VERSION 5.8 ;
BUSBITCHARS "[]" ;
DIVIDERCHAR "/" ;
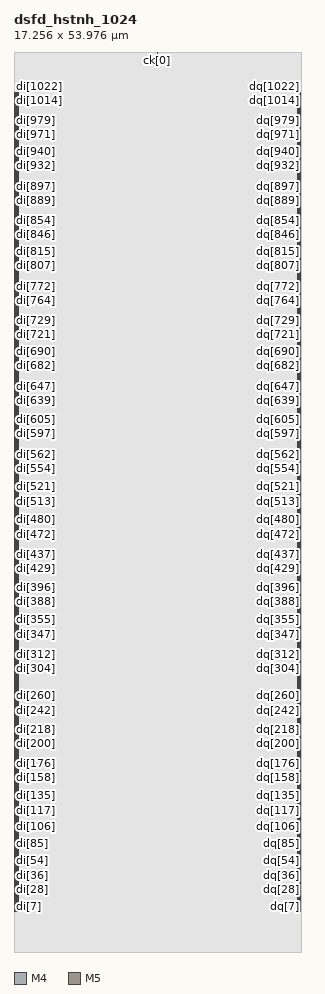
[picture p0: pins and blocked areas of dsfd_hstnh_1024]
MACRO dsfd_hstnh_1024
  CLASS BLOCK ;
  FOREIGN dsfd_hstnh_1024 0 0 ;
  SIZE 17.256 BY 53.976 ;
  SYMMETRY X Y ;
  PIN di[0]
    DIRECTION INOUT ;
    USE SIGNAL ;
    PORT
      LAYER M4 ;
        RECT 0.048 2.400 0.240 2.424 ;
    END
  END di[0]
  PIN di[1]
    DIRECTION INOUT ;
    USE SIGNAL ;
    PORT
      LAYER M4 ;
        RECT 0.048 2.448 0.240 2.472 ;
    END
  END di[1]
  PIN di[2]
    DIRECTION INOUT ;
    USE SIGNAL ;
    PORT
      LAYER M4 ;
        RECT 0.048 2.496 0.240 2.520 ;
    END
  END di[2]
  PIN di[3]
    DIRECTION INOUT ;
    USE SIGNAL ;
    PORT
      LAYER M4 ;
        RECT 0.048 2.544 0.240 2.568 ;
    END
  END di[3]
  PIN di[4]
    DIRECTION INOUT ;
    USE SIGNAL ;
    PORT
      LAYER M4 ;
        RECT 0.048 2.592 0.240 2.616 ;
    END
  END di[4]
  PIN di[5]
    DIRECTION INOUT ;
    USE SIGNAL ;
    PORT
      LAYER M4 ;
        RECT 0.048 2.640 0.240 2.664 ;
    END
  END di[5]
  PIN di[6]
    DIRECTION INOUT ;
    USE SIGNAL ;
    PORT
      LAYER M4 ;
        RECT 0.048 2.688 0.240 2.712 ;
    END
  END di[6]
  PIN di[7]
    DIRECTION INOUT ;
    USE SIGNAL ;
    PORT
      LAYER M4 ;
        RECT 0.048 2.736 0.240 2.760 ;
    END
  END di[7]
  PIN di[8]
    DIRECTION INOUT ;
    USE SIGNAL ;
    PORT
      LAYER M4 ;
        RECT 0.048 2.784 0.240 2.808 ;
    END
  END di[8]
  PIN di[9]
    DIRECTION INOUT ;
    USE SIGNAL ;
    PORT
      LAYER M4 ;
        RECT 0.048 2.832 0.240 2.856 ;
    END
  END di[9]
  PIN di[10]
    DIRECTION INOUT ;
    USE SIGNAL ;
    PORT
      LAYER M4 ;
        RECT 0.048 2.880 0.240 2.904 ;
    END
  END di[10]
  PIN di[11]
    DIRECTION INOUT ;
    USE SIGNAL ;
    PORT
      LAYER M4 ;
        RECT 0.048 2.928 0.240 2.952 ;
    END
  END di[11]
  PIN di[12]
    DIRECTION INOUT ;
    USE SIGNAL ;
    PORT
      LAYER M4 ;
        RECT 0.048 2.976 0.240 3.000 ;
    END
  END di[12]
  PIN di[13]
    DIRECTION INOUT ;
    USE SIGNAL ;
    PORT
      LAYER M4 ;
        RECT 0.048 3.024 0.240 3.048 ;
    END
  END di[13]
  PIN di[14]
    DIRECTION INOUT ;
    USE SIGNAL ;
    PORT
      LAYER M4 ;
        RECT 0.048 3.072 0.240 3.096 ;
    END
  END di[14]
  PIN di[15]
    DIRECTION INOUT ;
    USE SIGNAL ;
    PORT
      LAYER M4 ;
        RECT 0.048 3.120 0.240 3.144 ;
    END
  END di[15]
  PIN di[16]
    DIRECTION INOUT ;
    USE SIGNAL ;
    PORT
      LAYER M4 ;
        RECT 0.048 3.168 0.240 3.192 ;
    END
  END di[16]
  PIN di[17]
    DIRECTION INOUT ;
    USE SIGNAL ;
    PORT
      LAYER M4 ;
        RECT 0.048 3.216 0.240 3.240 ;
    END
  END di[17]
  PIN di[18]
    DIRECTION INOUT ;
    USE SIGNAL ;
    PORT
      LAYER M4 ;
        RECT 0.048 3.264 0.240 3.288 ;
    END
  END di[18]
  PIN di[19]
    DIRECTION INOUT ;
    USE SIGNAL ;
    PORT
      LAYER M4 ;
        RECT 0.048 3.312 0.240 3.336 ;
    END
  END di[19]
  PIN di[20]
    DIRECTION INOUT ;
    USE SIGNAL ;
    PORT
      LAYER M4 ;
        RECT 0.048 3.360 0.240 3.384 ;
    END
  END di[20]
  PIN di[21]
    DIRECTION INOUT ;
    USE SIGNAL ;
    PORT
      LAYER M4 ;
        RECT 0.048 3.408 0.240 3.432 ;
    END
  END di[21]
  PIN di[22]
    DIRECTION INOUT ;
    USE SIGNAL ;
    PORT
      LAYER M4 ;
        RECT 0.048 3.456 0.240 3.480 ;
    END
  END di[22]
  PIN di[23]
    DIRECTION INOUT ;
    USE SIGNAL ;
    PORT
      LAYER M4 ;
        RECT 0.048 3.504 0.240 3.528 ;
    END
  END di[23]
  PIN di[24]
    DIRECTION INOUT ;
    USE SIGNAL ;
    PORT
      LAYER M4 ;
        RECT 0.048 3.552 0.240 3.576 ;
    END
  END di[24]
  PIN di[25]
    DIRECTION INOUT ;
    USE SIGNAL ;
    PORT
      LAYER M4 ;
        RECT 0.048 3.600 0.240 3.624 ;
    END
  END di[25]
  PIN di[26]
    DIRECTION INOUT ;
    USE SIGNAL ;
    PORT
      LAYER M4 ;
        RECT 0.048 3.648 0.240 3.672 ;
    END
  END di[26]
  PIN di[27]
    DIRECTION INOUT ;
    USE SIGNAL ;
    PORT
      LAYER M4 ;
        RECT 0.048 3.696 0.240 3.720 ;
    END
  END di[27]
  PIN di[28]
    DIRECTION INOUT ;
    USE SIGNAL ;
    PORT
      LAYER M4 ;
        RECT 0.048 3.744 0.240 3.768 ;
    END
  END di[28]
  PIN di[29]
    DIRECTION INOUT ;
    USE SIGNAL ;
    PORT
      LAYER M4 ;
        RECT 0.048 3.792 0.240 3.816 ;
    END
  END di[29]
  PIN di[30]
    DIRECTION INOUT ;
    USE SIGNAL ;
    PORT
      LAYER M4 ;
        RECT 0.048 3.840 0.240 3.864 ;
    END
  END di[30]
  PIN di[31]
    DIRECTION INOUT ;
    USE SIGNAL ;
    PORT
      LAYER M4 ;
        RECT 0.048 3.888 0.240 3.912 ;
    END
  END di[31]
  PIN di[32]
    DIRECTION INOUT ;
    USE SIGNAL ;
    PORT
      LAYER M4 ;
        RECT 0.048 3.936 0.240 3.960 ;
    END
  END di[32]
  PIN di[33]
    DIRECTION INOUT ;
    USE SIGNAL ;
    PORT
      LAYER M4 ;
        RECT 0.048 3.984 0.240 4.008 ;
    END
  END di[33]
  PIN di[34]
    DIRECTION INOUT ;
    USE SIGNAL ;
    PORT
      LAYER M4 ;
        RECT 0.048 4.032 0.240 4.056 ;
    END
  END di[34]
  PIN di[35]
    DIRECTION INOUT ;
    USE SIGNAL ;
    PORT
      LAYER M4 ;
        RECT 0.048 4.080 0.240 4.104 ;
    END
  END di[35]
  PIN di[36]
    DIRECTION INOUT ;
    USE SIGNAL ;
    PORT
      LAYER M4 ;
        RECT 0.048 4.128 0.240 4.152 ;
    END
  END di[36]
  PIN di[37]
    DIRECTION INOUT ;
    USE SIGNAL ;
    PORT
      LAYER M4 ;
        RECT 0.048 4.176 0.240 4.200 ;
    END
  END di[37]
  PIN di[38]
    DIRECTION INOUT ;
    USE SIGNAL ;
    PORT
      LAYER M4 ;
        RECT 0.048 4.224 0.240 4.248 ;
    END
  END di[38]
  PIN di[39]
    DIRECTION INOUT ;
    USE SIGNAL ;
    PORT
      LAYER M4 ;
        RECT 0.048 4.272 0.240 4.296 ;
    END
  END di[39]
  PIN di[40]
    DIRECTION INOUT ;
    USE SIGNAL ;
    PORT
      LAYER M4 ;
        RECT 0.048 4.320 0.240 4.344 ;
    END
  END di[40]
  PIN di[41]
    DIRECTION INOUT ;
    USE SIGNAL ;
    PORT
      LAYER M4 ;
        RECT 0.048 4.368 0.240 4.392 ;
    END
  END di[41]
  PIN di[42]
    DIRECTION INOUT ;
    USE SIGNAL ;
    PORT
      LAYER M4 ;
        RECT 0.048 4.416 0.240 4.440 ;
    END
  END di[42]
  PIN di[43]
    DIRECTION INOUT ;
    USE SIGNAL ;
    PORT
      LAYER M4 ;
        RECT 0.048 4.464 0.240 4.488 ;
    END
  END di[43]
  PIN di[44]
    DIRECTION INOUT ;
    USE SIGNAL ;
    PORT
      LAYER M4 ;
        RECT 0.048 4.512 0.240 4.536 ;
    END
  END di[44]
  PIN di[45]
    DIRECTION INOUT ;
    USE SIGNAL ;
    PORT
      LAYER M4 ;
        RECT 0.048 4.560 0.240 4.584 ;
    END
  END di[45]
  PIN di[46]
    DIRECTION INOUT ;
    USE SIGNAL ;
    PORT
      LAYER M4 ;
        RECT 0.048 4.608 0.240 4.632 ;
    END
  END di[46]
  PIN di[47]
    DIRECTION INOUT ;
    USE SIGNAL ;
    PORT
      LAYER M4 ;
        RECT 0.048 4.656 0.240 4.680 ;
    END
  END di[47]
  PIN di[48]
    DIRECTION INOUT ;
    USE SIGNAL ;
    PORT
      LAYER M4 ;
        RECT 0.048 4.704 0.240 4.728 ;
    END
  END di[48]
  PIN di[49]
    DIRECTION INOUT ;
    USE SIGNAL ;
    PORT
      LAYER M4 ;
        RECT 0.048 4.752 0.240 4.776 ;
    END
  END di[49]
  PIN di[50]
    DIRECTION INOUT ;
    USE SIGNAL ;
    PORT
      LAYER M4 ;
        RECT 0.048 4.800 0.240 4.824 ;
    END
  END di[50]
  PIN di[51]
    DIRECTION INOUT ;
    USE SIGNAL ;
    PORT
      LAYER M4 ;
        RECT 0.048 4.848 0.240 4.872 ;
    END
  END di[51]
  PIN di[52]
    DIRECTION INOUT ;
    USE SIGNAL ;
    PORT
      LAYER M4 ;
        RECT 0.048 4.896 0.240 4.920 ;
    END
  END di[52]
  PIN di[53]
    DIRECTION INOUT ;
    USE SIGNAL ;
    PORT
      LAYER M4 ;
        RECT 0.048 4.944 0.240 4.968 ;
    END
  END di[53]
  PIN di[54]
    DIRECTION INOUT ;
    USE SIGNAL ;
    PORT
      LAYER M4 ;
        RECT 0.048 4.992 0.240 5.016 ;
    END
  END di[54]
  PIN di[55]
    DIRECTION INOUT ;
    USE SIGNAL ;
    PORT
      LAYER M4 ;
        RECT 0.048 5.040 0.240 5.064 ;
    END
  END di[55]
  PIN di[56]
    DIRECTION INOUT ;
    USE SIGNAL ;
    PORT
      LAYER M4 ;
        RECT 0.048 5.088 0.240 5.112 ;
    END
  END di[56]
  PIN di[57]
    DIRECTION INOUT ;
    USE SIGNAL ;
    PORT
      LAYER M4 ;
        RECT 0.048 5.136 0.240 5.160 ;
    END
  END di[57]
  PIN di[58]
    DIRECTION INOUT ;
    USE SIGNAL ;
    PORT
      LAYER M4 ;
        RECT 0.048 5.184 0.240 5.208 ;
    END
  END di[58]
  PIN di[59]
    DIRECTION INOUT ;
    USE SIGNAL ;
    PORT
      LAYER M4 ;
        RECT 0.048 5.232 0.240 5.256 ;
    END
  END di[59]
  PIN di[60]
    DIRECTION INOUT ;
    USE SIGNAL ;
    PORT
      LAYER M4 ;
        RECT 0.048 5.280 0.240 5.304 ;
    END
  END di[60]
  PIN di[61]
    DIRECTION INOUT ;
    USE SIGNAL ;
    PORT
      LAYER M4 ;
        RECT 0.048 5.328 0.240 5.352 ;
    END
  END di[61]
  PIN di[62]
    DIRECTION INOUT ;
    USE SIGNAL ;
    PORT
      LAYER M4 ;
        RECT 0.048 5.376 0.240 5.400 ;
    END
  END di[62]
  PIN di[63]
    DIRECTION INOUT ;
    USE SIGNAL ;
    PORT
      LAYER M4 ;
        RECT 0.048 5.424 0.240 5.448 ;
    END
  END di[63]
  PIN di[64]
    DIRECTION INOUT ;
    USE SIGNAL ;
    PORT
      LAYER M4 ;
        RECT 0.048 5.472 0.240 5.496 ;
    END
  END di[64]
  PIN di[65]
    DIRECTION INOUT ;
    USE SIGNAL ;
    PORT
      LAYER M4 ;
        RECT 0.048 5.520 0.240 5.544 ;
    END
  END di[65]
  PIN di[66]
    DIRECTION INOUT ;
    USE SIGNAL ;
    PORT
      LAYER M4 ;
        RECT 0.048 5.568 0.240 5.592 ;
    END
  END di[66]
  PIN di[67]
    DIRECTION INOUT ;
    USE SIGNAL ;
    PORT
      LAYER M4 ;
        RECT 0.048 5.616 0.240 5.640 ;
    END
  END di[67]
  PIN di[68]
    DIRECTION INOUT ;
    USE SIGNAL ;
    PORT
      LAYER M4 ;
        RECT 0.048 5.664 0.240 5.688 ;
    END
  END di[68]
  PIN di[69]
    DIRECTION INOUT ;
    USE SIGNAL ;
    PORT
      LAYER M4 ;
        RECT 0.048 5.712 0.240 5.736 ;
    END
  END di[69]
  PIN di[70]
    DIRECTION INOUT ;
    USE SIGNAL ;
    PORT
      LAYER M4 ;
        RECT 0.048 5.760 0.240 5.784 ;
    END
  END di[70]
  PIN di[71]
    DIRECTION INOUT ;
    USE SIGNAL ;
    PORT
      LAYER M4 ;
        RECT 0.048 5.808 0.240 5.832 ;
    END
  END di[71]
  PIN di[72]
    DIRECTION INOUT ;
    USE SIGNAL ;
    PORT
      LAYER M4 ;
        RECT 0.048 5.856 0.240 5.880 ;
    END
  END di[72]
  PIN di[73]
    DIRECTION INOUT ;
    USE SIGNAL ;
    PORT
      LAYER M4 ;
        RECT 0.048 5.904 0.240 5.928 ;
    END
  END di[73]
  PIN di[74]
    DIRECTION INOUT ;
    USE SIGNAL ;
    PORT
      LAYER M4 ;
        RECT 0.048 5.952 0.240 5.976 ;
    END
  END di[74]
  PIN di[75]
    DIRECTION INOUT ;
    USE SIGNAL ;
    PORT
      LAYER M4 ;
        RECT 0.048 6.000 0.240 6.024 ;
    END
  END di[75]
  PIN di[76]
    DIRECTION INOUT ;
    USE SIGNAL ;
    PORT
      LAYER M4 ;
        RECT 0.048 6.048 0.240 6.072 ;
    END
  END di[76]
  PIN di[77]
    DIRECTION INOUT ;
    USE SIGNAL ;
    PORT
      LAYER M4 ;
        RECT 0.048 6.096 0.240 6.120 ;
    END
  END di[77]
  PIN di[78]
    DIRECTION INOUT ;
    USE SIGNAL ;
    PORT
      LAYER M4 ;
        RECT 0.048 6.144 0.240 6.168 ;
    END
  END di[78]
  PIN di[79]
    DIRECTION INOUT ;
    USE SIGNAL ;
    PORT
      LAYER M4 ;
        RECT 0.048 6.192 0.240 6.216 ;
    END
  END di[79]
  PIN di[80]
    DIRECTION INOUT ;
    USE SIGNAL ;
    PORT
      LAYER M4 ;
        RECT 0.048 6.240 0.240 6.264 ;
    END
  END di[80]
  PIN di[81]
    DIRECTION INOUT ;
    USE SIGNAL ;
    PORT
      LAYER M4 ;
        RECT 0.048 6.288 0.240 6.312 ;
    END
  END di[81]
  PIN di[82]
    DIRECTION INOUT ;
    USE SIGNAL ;
    PORT
      LAYER M4 ;
        RECT 0.048 6.336 0.240 6.360 ;
    END
  END di[82]
  PIN di[83]
    DIRECTION INOUT ;
    USE SIGNAL ;
    PORT
      LAYER M4 ;
        RECT 0.048 6.384 0.240 6.408 ;
    END
  END di[83]
  PIN di[84]
    DIRECTION INOUT ;
    USE SIGNAL ;
    PORT
      LAYER M4 ;
        RECT 0.048 6.432 0.240 6.456 ;
    END
  END di[84]
  PIN di[85]
    DIRECTION INOUT ;
    USE SIGNAL ;
    PORT
      LAYER M4 ;
        RECT 0.048 6.480 0.240 6.504 ;
    END
  END di[85]
  PIN di[86]
    DIRECTION INOUT ;
    USE SIGNAL ;
    PORT
      LAYER M4 ;
        RECT 0.048 6.528 0.240 6.552 ;
    END
  END di[86]
  PIN di[87]
    DIRECTION INOUT ;
    USE SIGNAL ;
    PORT
      LAYER M4 ;
        RECT 0.048 6.576 0.240 6.600 ;
    END
  END di[87]
  PIN di[88]
    DIRECTION INOUT ;
    USE SIGNAL ;
    PORT
      LAYER M4 ;
        RECT 0.048 6.624 0.240 6.648 ;
    END
  END di[88]
  PIN di[89]
    DIRECTION INOUT ;
    USE SIGNAL ;
    PORT
      LAYER M4 ;
        RECT 0.048 6.672 0.240 6.696 ;
    END
  END di[89]
  PIN di[90]
    DIRECTION INOUT ;
    USE SIGNAL ;
    PORT
      LAYER M4 ;
        RECT 0.048 6.720 0.240 6.744 ;
    END
  END di[90]
  PIN di[91]
    DIRECTION INOUT ;
    USE SIGNAL ;
    PORT
      LAYER M4 ;
        RECT 0.048 6.768 0.240 6.792 ;
    END
  END di[91]
  PIN di[92]
    DIRECTION INOUT ;
    USE SIGNAL ;
    PORT
      LAYER M4 ;
        RECT 0.048 6.816 0.240 6.840 ;
    END
  END di[92]
  PIN di[93]
    DIRECTION INOUT ;
    USE SIGNAL ;
    PORT
      LAYER M4 ;
        RECT 0.048 6.864 0.240 6.888 ;
    END
  END di[93]
  PIN di[94]
    DIRECTION INOUT ;
    USE SIGNAL ;
    PORT
      LAYER M4 ;
        RECT 0.048 6.912 0.240 6.936 ;
    END
  END di[94]
  PIN di[95]
    DIRECTION INOUT ;
    USE SIGNAL ;
    PORT
      LAYER M4 ;
        RECT 0.048 6.960 0.240 6.984 ;
    END
  END di[95]
  PIN di[96]
    DIRECTION INOUT ;
    USE SIGNAL ;
    PORT
      LAYER M4 ;
        RECT 0.048 7.008 0.240 7.032 ;
    END
  END di[96]
  PIN di[97]
    DIRECTION INOUT ;
    USE SIGNAL ;
    PORT
      LAYER M4 ;
        RECT 0.048 7.056 0.240 7.080 ;
    END
  END di[97]
  PIN di[98]
    DIRECTION INOUT ;
    USE SIGNAL ;
    PORT
      LAYER M4 ;
        RECT 0.048 7.104 0.240 7.128 ;
    END
  END di[98]
  PIN di[99]
    DIRECTION INOUT ;
    USE SIGNAL ;
    PORT
      LAYER M4 ;
        RECT 0.048 7.152 0.240 7.176 ;
    END
  END di[99]
  PIN di[100]
    DIRECTION INOUT ;
    USE SIGNAL ;
    PORT
      LAYER M4 ;
        RECT 0.048 7.200 0.240 7.224 ;
    END
  END di[100]
  PIN di[101]
    DIRECTION INOUT ;
    USE SIGNAL ;
    PORT
      LAYER M4 ;
        RECT 0.048 7.248 0.240 7.272 ;
    END
  END di[101]
  PIN di[102]
    DIRECTION INOUT ;
    USE SIGNAL ;
    PORT
      LAYER M4 ;
        RECT 0.048 7.296 0.240 7.320 ;
    END
  END di[102]
  PIN di[103]
    DIRECTION INOUT ;
    USE SIGNAL ;
    PORT
      LAYER M4 ;
        RECT 0.048 7.344 0.240 7.368 ;
    END
  END di[103]
  PIN di[104]
    DIRECTION INOUT ;
    USE SIGNAL ;
    PORT
      LAYER M4 ;
        RECT 0.048 7.392 0.240 7.416 ;
    END
  END di[104]
  PIN di[105]
    DIRECTION INOUT ;
    USE SIGNAL ;
    PORT
      LAYER M4 ;
        RECT 0.048 7.440 0.240 7.464 ;
    END
  END di[105]
  PIN di[106]
    DIRECTION INOUT ;
    USE SIGNAL ;
    PORT
      LAYER M4 ;
        RECT 0.048 7.488 0.240 7.512 ;
    END
  END di[106]
  PIN di[107]
    DIRECTION INOUT ;
    USE SIGNAL ;
    PORT
      LAYER M4 ;
        RECT 0.048 7.536 0.240 7.560 ;
    END
  END di[107]
  PIN di[108]
    DIRECTION INOUT ;
    USE SIGNAL ;
    PORT
      LAYER M4 ;
        RECT 0.048 7.584 0.240 7.608 ;
    END
  END di[108]
  PIN di[109]
    DIRECTION INOUT ;
    USE SIGNAL ;
    PORT
      LAYER M4 ;
        RECT 0.048 7.632 0.240 7.656 ;
    END
  END di[109]
  PIN di[110]
    DIRECTION INOUT ;
    USE SIGNAL ;
    PORT
      LAYER M4 ;
        RECT 0.048 7.680 0.240 7.704 ;
    END
  END di[110]
  PIN di[111]
    DIRECTION INOUT ;
    USE SIGNAL ;
    PORT
      LAYER M4 ;
        RECT 0.048 7.728 0.240 7.752 ;
    END
  END di[111]
  PIN di[112]
    DIRECTION INOUT ;
    USE SIGNAL ;
    PORT
      LAYER M4 ;
        RECT 0.048 7.776 0.240 7.800 ;
    END
  END di[112]
  PIN di[113]
    DIRECTION INOUT ;
    USE SIGNAL ;
    PORT
      LAYER M4 ;
        RECT 0.048 7.824 0.240 7.848 ;
    END
  END di[113]
  PIN di[114]
    DIRECTION INOUT ;
    USE SIGNAL ;
    PORT
      LAYER M4 ;
        RECT 0.048 7.872 0.240 7.896 ;
    END
  END di[114]
  PIN di[115]
    DIRECTION INOUT ;
    USE SIGNAL ;
    PORT
      LAYER M4 ;
        RECT 0.048 7.920 0.240 7.944 ;
    END
  END di[115]
  PIN di[116]
    DIRECTION INOUT ;
    USE SIGNAL ;
    PORT
      LAYER M4 ;
        RECT 0.048 7.968 0.240 7.992 ;
    END
  END di[116]
  PIN di[117]
    DIRECTION INOUT ;
    USE SIGNAL ;
    PORT
      LAYER M4 ;
        RECT 0.048 8.016 0.240 8.040 ;
    END
  END di[117]
  PIN di[118]
    DIRECTION INOUT ;
    USE SIGNAL ;
    PORT
      LAYER M4 ;
        RECT 0.048 8.064 0.240 8.088 ;
    END
  END di[118]
  PIN di[119]
    DIRECTION INOUT ;
    USE SIGNAL ;
    PORT
      LAYER M4 ;
        RECT 0.048 8.112 0.240 8.136 ;
    END
  END di[119]
  PIN di[120]
    DIRECTION INOUT ;
    USE SIGNAL ;
    PORT
      LAYER M4 ;
        RECT 0.048 8.160 0.240 8.184 ;
    END
  END di[120]
  PIN di[121]
    DIRECTION INOUT ;
    USE SIGNAL ;
    PORT
      LAYER M4 ;
        RECT 0.048 8.208 0.240 8.232 ;
    END
  END di[121]
  PIN di[122]
    DIRECTION INOUT ;
    USE SIGNAL ;
    PORT
      LAYER M4 ;
        RECT 0.048 8.256 0.240 8.280 ;
    END
  END di[122]
  PIN di[123]
    DIRECTION INOUT ;
    USE SIGNAL ;
    PORT
      LAYER M4 ;
        RECT 0.048 8.304 0.240 8.328 ;
    END
  END di[123]
  PIN di[124]
    DIRECTION INOUT ;
    USE SIGNAL ;
    PORT
      LAYER M4 ;
        RECT 0.048 8.352 0.240 8.376 ;
    END
  END di[124]
  PIN di[125]
    DIRECTION INOUT ;
    USE SIGNAL ;
    PORT
      LAYER M4 ;
        RECT 0.048 8.400 0.240 8.424 ;
    END
  END di[125]
  PIN di[126]
    DIRECTION INOUT ;
    USE SIGNAL ;
    PORT
      LAYER M4 ;
        RECT 0.048 8.448 0.240 8.472 ;
    END
  END di[126]
  PIN di[127]
    DIRECTION INOUT ;
    USE SIGNAL ;
    PORT
      LAYER M4 ;
        RECT 0.048 8.496 0.240 8.520 ;
    END
  END di[127]
  PIN di[128]
    DIRECTION INOUT ;
    USE SIGNAL ;
    PORT
      LAYER M4 ;
        RECT 0.048 8.544 0.240 8.568 ;
    END
  END di[128]
  PIN di[129]
    DIRECTION INOUT ;
    USE SIGNAL ;
    PORT
      LAYER M4 ;
        RECT 0.048 8.592 0.240 8.616 ;
    END
  END di[129]
  PIN di[130]
    DIRECTION INOUT ;
    USE SIGNAL ;
    PORT
      LAYER M4 ;
        RECT 0.048 8.640 0.240 8.664 ;
    END
  END di[130]
  PIN di[131]
    DIRECTION INOUT ;
    USE SIGNAL ;
    PORT
      LAYER M4 ;
        RECT 0.048 8.688 0.240 8.712 ;
    END
  END di[131]
  PIN di[132]
    DIRECTION INOUT ;
    USE SIGNAL ;
    PORT
      LAYER M4 ;
        RECT 0.048 8.736 0.240 8.760 ;
    END
  END di[132]
  PIN di[133]
    DIRECTION INOUT ;
    USE SIGNAL ;
    PORT
      LAYER M4 ;
        RECT 0.048 8.784 0.240 8.808 ;
    END
  END di[133]
  PIN di[134]
    DIRECTION INOUT ;
    USE SIGNAL ;
    PORT
      LAYER M4 ;
        RECT 0.048 8.832 0.240 8.856 ;
    END
  END di[134]
  PIN di[135]
    DIRECTION INOUT ;
    USE SIGNAL ;
    PORT
      LAYER M4 ;
        RECT 0.048 8.880 0.240 8.904 ;
    END
  END di[135]
  PIN di[136]
    DIRECTION INOUT ;
    USE SIGNAL ;
    PORT
      LAYER M4 ;
        RECT 0.048 8.928 0.240 8.952 ;
    END
  END di[136]
  PIN di[137]
    DIRECTION INOUT ;
    USE SIGNAL ;
    PORT
      LAYER M4 ;
        RECT 0.048 8.976 0.240 9.000 ;
    END
  END di[137]
  PIN di[138]
    DIRECTION INOUT ;
    USE SIGNAL ;
    PORT
      LAYER M4 ;
        RECT 0.048 9.024 0.240 9.048 ;
    END
  END di[138]
  PIN di[139]
    DIRECTION INOUT ;
    USE SIGNAL ;
    PORT
      LAYER M4 ;
        RECT 0.048 9.072 0.240 9.096 ;
    END
  END di[139]
  PIN di[140]
    DIRECTION INOUT ;
    USE SIGNAL ;
    PORT
      LAYER M4 ;
        RECT 0.048 9.120 0.240 9.144 ;
    END
  END di[140]
  PIN di[141]
    DIRECTION INOUT ;
    USE SIGNAL ;
    PORT
      LAYER M4 ;
        RECT 0.048 9.168 0.240 9.192 ;
    END
  END di[141]
  PIN di[142]
    DIRECTION INOUT ;
    USE SIGNAL ;
    PORT
      LAYER M4 ;
        RECT 0.048 9.216 0.240 9.240 ;
    END
  END di[142]
  PIN di[143]
    DIRECTION INOUT ;
    USE SIGNAL ;
    PORT
      LAYER M4 ;
        RECT 0.048 9.264 0.240 9.288 ;
    END
  END di[143]
  PIN di[144]
    DIRECTION INOUT ;
    USE SIGNAL ;
    PORT
      LAYER M4 ;
        RECT 0.048 9.312 0.240 9.336 ;
    END
  END di[144]
  PIN di[145]
    DIRECTION INOUT ;
    USE SIGNAL ;
    PORT
      LAYER M4 ;
        RECT 0.048 9.360 0.240 9.384 ;
    END
  END di[145]
  PIN di[146]
    DIRECTION INOUT ;
    USE SIGNAL ;
    PORT
      LAYER M4 ;
        RECT 0.048 9.408 0.240 9.432 ;
    END
  END di[146]
  PIN di[147]
    DIRECTION INOUT ;
    USE SIGNAL ;
    PORT
      LAYER M4 ;
        RECT 0.048 9.456 0.240 9.480 ;
    END
  END di[147]
  PIN di[148]
    DIRECTION INOUT ;
    USE SIGNAL ;
    PORT
      LAYER M4 ;
        RECT 0.048 9.504 0.240 9.528 ;
    END
  END di[148]
  PIN di[149]
    DIRECTION INOUT ;
    USE SIGNAL ;
    PORT
      LAYER M4 ;
        RECT 0.048 9.552 0.240 9.576 ;
    END
  END di[149]
  PIN di[150]
    DIRECTION INOUT ;
    USE SIGNAL ;
    PORT
      LAYER M4 ;
        RECT 0.048 9.600 0.240 9.624 ;
    END
  END di[150]
  PIN di[151]
    DIRECTION INOUT ;
    USE SIGNAL ;
    PORT
      LAYER M4 ;
        RECT 0.048 9.648 0.240 9.672 ;
    END
  END di[151]
  PIN di[152]
    DIRECTION INOUT ;
    USE SIGNAL ;
    PORT
      LAYER M4 ;
        RECT 0.048 9.696 0.240 9.720 ;
    END
  END di[152]
  PIN di[153]
    DIRECTION INOUT ;
    USE SIGNAL ;
    PORT
      LAYER M4 ;
        RECT 0.048 9.744 0.240 9.768 ;
    END
  END di[153]
  PIN di[154]
    DIRECTION INOUT ;
    USE SIGNAL ;
    PORT
      LAYER M4 ;
        RECT 0.048 9.792 0.240 9.816 ;
    END
  END di[154]
  PIN di[155]
    DIRECTION INOUT ;
    USE SIGNAL ;
    PORT
      LAYER M4 ;
        RECT 0.048 9.840 0.240 9.864 ;
    END
  END di[155]
  PIN di[156]
    DIRECTION INOUT ;
    USE SIGNAL ;
    PORT
      LAYER M4 ;
        RECT 0.048 9.888 0.240 9.912 ;
    END
  END di[156]
  PIN di[157]
    DIRECTION INOUT ;
    USE SIGNAL ;
    PORT
      LAYER M4 ;
        RECT 0.048 9.936 0.240 9.960 ;
    END
  END di[157]
  PIN di[158]
    DIRECTION INOUT ;
    USE SIGNAL ;
    PORT
      LAYER M4 ;
        RECT 0.048 9.984 0.240 10.008 ;
    END
  END di[158]
  PIN di[159]
    DIRECTION INOUT ;
    USE SIGNAL ;
    PORT
      LAYER M4 ;
        RECT 0.048 10.032 0.240 10.056 ;
    END
  END di[159]
  PIN di[160]
    DIRECTION INOUT ;
    USE SIGNAL ;
    PORT
      LAYER M4 ;
        RECT 0.048 10.080 0.240 10.104 ;
    END
  END di[160]
  PIN di[161]
    DIRECTION INOUT ;
    USE SIGNAL ;
    PORT
      LAYER M4 ;
        RECT 0.048 10.128 0.240 10.152 ;
    END
  END di[161]
  PIN di[162]
    DIRECTION INOUT ;
    USE SIGNAL ;
    PORT
      LAYER M4 ;
        RECT 0.048 10.176 0.240 10.200 ;
    END
  END di[162]
  PIN di[163]
    DIRECTION INOUT ;
    USE SIGNAL ;
    PORT
      LAYER M4 ;
        RECT 0.048 10.224 0.240 10.248 ;
    END
  END di[163]
  PIN di[164]
    DIRECTION INOUT ;
    USE SIGNAL ;
    PORT
      LAYER M4 ;
        RECT 0.048 10.272 0.240 10.296 ;
    END
  END di[164]
  PIN di[165]
    DIRECTION INOUT ;
    USE SIGNAL ;
    PORT
      LAYER M4 ;
        RECT 0.048 10.320 0.240 10.344 ;
    END
  END di[165]
  PIN di[166]
    DIRECTION INOUT ;
    USE SIGNAL ;
    PORT
      LAYER M4 ;
        RECT 0.048 10.368 0.240 10.392 ;
    END
  END di[166]
  PIN di[167]
    DIRECTION INOUT ;
    USE SIGNAL ;
    PORT
      LAYER M4 ;
        RECT 0.048 10.416 0.240 10.440 ;
    END
  END di[167]
  PIN di[168]
    DIRECTION INOUT ;
    USE SIGNAL ;
    PORT
      LAYER M4 ;
        RECT 0.048 10.464 0.240 10.488 ;
    END
  END di[168]
  PIN di[169]
    DIRECTION INOUT ;
    USE SIGNAL ;
    PORT
      LAYER M4 ;
        RECT 0.048 10.512 0.240 10.536 ;
    END
  END di[169]
  PIN di[170]
    DIRECTION INOUT ;
    USE SIGNAL ;
    PORT
      LAYER M4 ;
        RECT 0.048 10.560 0.240 10.584 ;
    END
  END di[170]
  PIN di[171]
    DIRECTION INOUT ;
    USE SIGNAL ;
    PORT
      LAYER M4 ;
        RECT 0.048 10.608 0.240 10.632 ;
    END
  END di[171]
  PIN di[172]
    DIRECTION INOUT ;
    USE SIGNAL ;
    PORT
      LAYER M4 ;
        RECT 0.048 10.656 0.240 10.680 ;
    END
  END di[172]
  PIN di[173]
    DIRECTION INOUT ;
    USE SIGNAL ;
    PORT
      LAYER M4 ;
        RECT 0.048 10.704 0.240 10.728 ;
    END
  END di[173]
  PIN di[174]
    DIRECTION INOUT ;
    USE SIGNAL ;
    PORT
      LAYER M4 ;
        RECT 0.048 10.752 0.240 10.776 ;
    END
  END di[174]
  PIN di[175]
    DIRECTION INOUT ;
    USE SIGNAL ;
    PORT
      LAYER M4 ;
        RECT 0.048 10.800 0.240 10.824 ;
    END
  END di[175]
  PIN di[176]
    DIRECTION INOUT ;
    USE SIGNAL ;
    PORT
      LAYER M4 ;
        RECT 0.048 10.848 0.240 10.872 ;
    END
  END di[176]
  PIN di[177]
    DIRECTION INOUT ;
    USE SIGNAL ;
    PORT
      LAYER M4 ;
        RECT 0.048 10.896 0.240 10.920 ;
    END
  END di[177]
  PIN di[178]
    DIRECTION INOUT ;
    USE SIGNAL ;
    PORT
      LAYER M4 ;
        RECT 0.048 10.944 0.240 10.968 ;
    END
  END di[178]
  PIN di[179]
    DIRECTION INOUT ;
    USE SIGNAL ;
    PORT
      LAYER M4 ;
        RECT 0.048 10.992 0.240 11.016 ;
    END
  END di[179]
  PIN di[180]
    DIRECTION INOUT ;
    USE SIGNAL ;
    PORT
      LAYER M4 ;
        RECT 0.048 11.040 0.240 11.064 ;
    END
  END di[180]
  PIN di[181]
    DIRECTION INOUT ;
    USE SIGNAL ;
    PORT
      LAYER M4 ;
        RECT 0.048 11.088 0.240 11.112 ;
    END
  END di[181]
  PIN di[182]
    DIRECTION INOUT ;
    USE SIGNAL ;
    PORT
      LAYER M4 ;
        RECT 0.048 11.136 0.240 11.160 ;
    END
  END di[182]
  PIN di[183]
    DIRECTION INOUT ;
    USE SIGNAL ;
    PORT
      LAYER M4 ;
        RECT 0.048 11.184 0.240 11.208 ;
    END
  END di[183]
  PIN di[184]
    DIRECTION INOUT ;
    USE SIGNAL ;
    PORT
      LAYER M4 ;
        RECT 0.048 11.232 0.240 11.256 ;
    END
  END di[184]
  PIN di[185]
    DIRECTION INOUT ;
    USE SIGNAL ;
    PORT
      LAYER M4 ;
        RECT 0.048 11.280 0.240 11.304 ;
    END
  END di[185]
  PIN di[186]
    DIRECTION INOUT ;
    USE SIGNAL ;
    PORT
      LAYER M4 ;
        RECT 0.048 11.328 0.240 11.352 ;
    END
  END di[186]
  PIN di[187]
    DIRECTION INOUT ;
    USE SIGNAL ;
    PORT
      LAYER M4 ;
        RECT 0.048 11.376 0.240 11.400 ;
    END
  END di[187]
  PIN di[188]
    DIRECTION INOUT ;
    USE SIGNAL ;
    PORT
      LAYER M4 ;
        RECT 0.048 11.424 0.240 11.448 ;
    END
  END di[188]
  PIN di[189]
    DIRECTION INOUT ;
    USE SIGNAL ;
    PORT
      LAYER M4 ;
        RECT 0.048 11.472 0.240 11.496 ;
    END
  END di[189]
  PIN di[190]
    DIRECTION INOUT ;
    USE SIGNAL ;
    PORT
      LAYER M4 ;
        RECT 0.048 11.520 0.240 11.544 ;
    END
  END di[190]
  PIN di[191]
    DIRECTION INOUT ;
    USE SIGNAL ;
    PORT
      LAYER M4 ;
        RECT 0.048 11.568 0.240 11.592 ;
    END
  END di[191]
  PIN di[192]
    DIRECTION INOUT ;
    USE SIGNAL ;
    PORT
      LAYER M4 ;
        RECT 0.048 11.616 0.240 11.640 ;
    END
  END di[192]
  PIN di[193]
    DIRECTION INOUT ;
    USE SIGNAL ;
    PORT
      LAYER M4 ;
        RECT 0.048 11.664 0.240 11.688 ;
    END
  END di[193]
  PIN di[194]
    DIRECTION INOUT ;
    USE SIGNAL ;
    PORT
      LAYER M4 ;
        RECT 0.048 11.712 0.240 11.736 ;
    END
  END di[194]
  PIN di[195]
    DIRECTION INOUT ;
    USE SIGNAL ;
    PORT
      LAYER M4 ;
        RECT 0.048 11.760 0.240 11.784 ;
    END
  END di[195]
  PIN di[196]
    DIRECTION INOUT ;
    USE SIGNAL ;
    PORT
      LAYER M4 ;
        RECT 0.048 11.808 0.240 11.832 ;
    END
  END di[196]
  PIN di[197]
    DIRECTION INOUT ;
    USE SIGNAL ;
    PORT
      LAYER M4 ;
        RECT 0.048 11.856 0.240 11.880 ;
    END
  END di[197]
  PIN di[198]
    DIRECTION INOUT ;
    USE SIGNAL ;
    PORT
      LAYER M4 ;
        RECT 0.048 11.904 0.240 11.928 ;
    END
  END di[198]
  PIN di[199]
    DIRECTION INOUT ;
    USE SIGNAL ;
    PORT
      LAYER M4 ;
        RECT 0.048 11.952 0.240 11.976 ;
    END
  END di[199]
  PIN di[200]
    DIRECTION INOUT ;
    USE SIGNAL ;
    PORT
      LAYER M4 ;
        RECT 0.048 12.000 0.240 12.024 ;
    END
  END di[200]
  PIN di[201]
    DIRECTION INOUT ;
    USE SIGNAL ;
    PORT
      LAYER M4 ;
        RECT 0.048 12.048 0.240 12.072 ;
    END
  END di[201]
  PIN di[202]
    DIRECTION INOUT ;
    USE SIGNAL ;
    PORT
      LAYER M4 ;
        RECT 0.048 12.096 0.240 12.120 ;
    END
  END di[202]
  PIN di[203]
    DIRECTION INOUT ;
    USE SIGNAL ;
    PORT
      LAYER M4 ;
        RECT 0.048 12.144 0.240 12.168 ;
    END
  END di[203]
  PIN di[204]
    DIRECTION INOUT ;
    USE SIGNAL ;
    PORT
      LAYER M4 ;
        RECT 0.048 12.192 0.240 12.216 ;
    END
  END di[204]
  PIN di[205]
    DIRECTION INOUT ;
    USE SIGNAL ;
    PORT
      LAYER M4 ;
        RECT 0.048 12.240 0.240 12.264 ;
    END
  END di[205]
  PIN di[206]
    DIRECTION INOUT ;
    USE SIGNAL ;
    PORT
      LAYER M4 ;
        RECT 0.048 12.288 0.240 12.312 ;
    END
  END di[206]
  PIN di[207]
    DIRECTION INOUT ;
    USE SIGNAL ;
    PORT
      LAYER M4 ;
        RECT 0.048 12.336 0.240 12.360 ;
    END
  END di[207]
  PIN di[208]
    DIRECTION INOUT ;
    USE SIGNAL ;
    PORT
      LAYER M4 ;
        RECT 0.048 12.384 0.240 12.408 ;
    END
  END di[208]
  PIN di[209]
    DIRECTION INOUT ;
    USE SIGNAL ;
    PORT
      LAYER M4 ;
        RECT 0.048 12.432 0.240 12.456 ;
    END
  END di[209]
  PIN di[210]
    DIRECTION INOUT ;
    USE SIGNAL ;
    PORT
      LAYER M4 ;
        RECT 0.048 12.480 0.240 12.504 ;
    END
  END di[210]
  PIN di[211]
    DIRECTION INOUT ;
    USE SIGNAL ;
    PORT
      LAYER M4 ;
        RECT 0.048 12.528 0.240 12.552 ;
    END
  END di[211]
  PIN di[212]
    DIRECTION INOUT ;
    USE SIGNAL ;
    PORT
      LAYER M4 ;
        RECT 0.048 12.576 0.240 12.600 ;
    END
  END di[212]
  PIN di[213]
    DIRECTION INOUT ;
    USE SIGNAL ;
    PORT
      LAYER M4 ;
        RECT 0.048 12.624 0.240 12.648 ;
    END
  END di[213]
  PIN di[214]
    DIRECTION INOUT ;
    USE SIGNAL ;
    PORT
      LAYER M4 ;
        RECT 0.048 12.672 0.240 12.696 ;
    END
  END di[214]
  PIN di[215]
    DIRECTION INOUT ;
    USE SIGNAL ;
    PORT
      LAYER M4 ;
        RECT 0.048 12.720 0.240 12.744 ;
    END
  END di[215]
  PIN di[216]
    DIRECTION INOUT ;
    USE SIGNAL ;
    PORT
      LAYER M4 ;
        RECT 0.048 12.768 0.240 12.792 ;
    END
  END di[216]
  PIN di[217]
    DIRECTION INOUT ;
    USE SIGNAL ;
    PORT
      LAYER M4 ;
        RECT 0.048 12.816 0.240 12.840 ;
    END
  END di[217]
  PIN di[218]
    DIRECTION INOUT ;
    USE SIGNAL ;
    PORT
      LAYER M4 ;
        RECT 0.048 12.864 0.240 12.888 ;
    END
  END di[218]
  PIN di[219]
    DIRECTION INOUT ;
    USE SIGNAL ;
    PORT
      LAYER M4 ;
        RECT 0.048 12.912 0.240 12.936 ;
    END
  END di[219]
  PIN di[220]
    DIRECTION INOUT ;
    USE SIGNAL ;
    PORT
      LAYER M4 ;
        RECT 0.048 12.960 0.240 12.984 ;
    END
  END di[220]
  PIN di[221]
    DIRECTION INOUT ;
    USE SIGNAL ;
    PORT
      LAYER M4 ;
        RECT 0.048 13.008 0.240 13.032 ;
    END
  END di[221]
  PIN di[222]
    DIRECTION INOUT ;
    USE SIGNAL ;
    PORT
      LAYER M4 ;
        RECT 0.048 13.056 0.240 13.080 ;
    END
  END di[222]
  PIN di[223]
    DIRECTION INOUT ;
    USE SIGNAL ;
    PORT
      LAYER M4 ;
        RECT 0.048 13.104 0.240 13.128 ;
    END
  END di[223]
  PIN di[224]
    DIRECTION INOUT ;
    USE SIGNAL ;
    PORT
      LAYER M4 ;
        RECT 0.048 13.152 0.240 13.176 ;
    END
  END di[224]
  PIN di[225]
    DIRECTION INOUT ;
    USE SIGNAL ;
    PORT
      LAYER M4 ;
        RECT 0.048 13.200 0.240 13.224 ;
    END
  END di[225]
  PIN di[226]
    DIRECTION INOUT ;
    USE SIGNAL ;
    PORT
      LAYER M4 ;
        RECT 0.048 13.248 0.240 13.272 ;
    END
  END di[226]
  PIN di[227]
    DIRECTION INOUT ;
    USE SIGNAL ;
    PORT
      LAYER M4 ;
        RECT 0.048 13.296 0.240 13.320 ;
    END
  END di[227]
  PIN di[228]
    DIRECTION INOUT ;
    USE SIGNAL ;
    PORT
      LAYER M4 ;
        RECT 0.048 13.344 0.240 13.368 ;
    END
  END di[228]
  PIN di[229]
    DIRECTION INOUT ;
    USE SIGNAL ;
    PORT
      LAYER M4 ;
        RECT 0.048 13.392 0.240 13.416 ;
    END
  END di[229]
  PIN di[230]
    DIRECTION INOUT ;
    USE SIGNAL ;
    PORT
      LAYER M4 ;
        RECT 0.048 13.440 0.240 13.464 ;
    END
  END di[230]
  PIN di[231]
    DIRECTION INOUT ;
    USE SIGNAL ;
    PORT
      LAYER M4 ;
        RECT 0.048 13.488 0.240 13.512 ;
    END
  END di[231]
  PIN di[232]
    DIRECTION INOUT ;
    USE SIGNAL ;
    PORT
      LAYER M4 ;
        RECT 0.048 13.536 0.240 13.560 ;
    END
  END di[232]
  PIN di[233]
    DIRECTION INOUT ;
    USE SIGNAL ;
    PORT
      LAYER M4 ;
        RECT 0.048 13.584 0.240 13.608 ;
    END
  END di[233]
  PIN di[234]
    DIRECTION INOUT ;
    USE SIGNAL ;
    PORT
      LAYER M4 ;
        RECT 0.048 13.632 0.240 13.656 ;
    END
  END di[234]
  PIN di[235]
    DIRECTION INOUT ;
    USE SIGNAL ;
    PORT
      LAYER M4 ;
        RECT 0.048 13.680 0.240 13.704 ;
    END
  END di[235]
  PIN di[236]
    DIRECTION INOUT ;
    USE SIGNAL ;
    PORT
      LAYER M4 ;
        RECT 0.048 13.728 0.240 13.752 ;
    END
  END di[236]
  PIN di[237]
    DIRECTION INOUT ;
    USE SIGNAL ;
    PORT
      LAYER M4 ;
        RECT 0.048 13.776 0.240 13.800 ;
    END
  END di[237]
  PIN di[238]
    DIRECTION INOUT ;
    USE SIGNAL ;
    PORT
      LAYER M4 ;
        RECT 0.048 13.824 0.240 13.848 ;
    END
  END di[238]
  PIN di[239]
    DIRECTION INOUT ;
    USE SIGNAL ;
    PORT
      LAYER M4 ;
        RECT 0.048 13.872 0.240 13.896 ;
    END
  END di[239]
  PIN di[240]
    DIRECTION INOUT ;
    USE SIGNAL ;
    PORT
      LAYER M4 ;
        RECT 0.048 13.920 0.240 13.944 ;
    END
  END di[240]
  PIN di[241]
    DIRECTION INOUT ;
    USE SIGNAL ;
    PORT
      LAYER M4 ;
        RECT 0.048 13.968 0.240 13.992 ;
    END
  END di[241]
  PIN di[242]
    DIRECTION INOUT ;
    USE SIGNAL ;
    PORT
      LAYER M4 ;
        RECT 0.048 14.016 0.240 14.040 ;
    END
  END di[242]
  PIN di[243]
    DIRECTION INOUT ;
    USE SIGNAL ;
    PORT
      LAYER M4 ;
        RECT 0.048 14.064 0.240 14.088 ;
    END
  END di[243]
  PIN di[244]
    DIRECTION INOUT ;
    USE SIGNAL ;
    PORT
      LAYER M4 ;
        RECT 0.048 14.112 0.240 14.136 ;
    END
  END di[244]
  PIN di[245]
    DIRECTION INOUT ;
    USE SIGNAL ;
    PORT
      LAYER M4 ;
        RECT 0.048 14.160 0.240 14.184 ;
    END
  END di[245]
  PIN di[246]
    DIRECTION INOUT ;
    USE SIGNAL ;
    PORT
      LAYER M4 ;
        RECT 0.048 14.208 0.240 14.232 ;
    END
  END di[246]
  PIN di[247]
    DIRECTION INOUT ;
    USE SIGNAL ;
    PORT
      LAYER M4 ;
        RECT 0.048 14.256 0.240 14.280 ;
    END
  END di[247]
  PIN di[248]
    DIRECTION INOUT ;
    USE SIGNAL ;
    PORT
      LAYER M4 ;
        RECT 0.048 14.304 0.240 14.328 ;
    END
  END di[248]
  PIN di[249]
    DIRECTION INOUT ;
    USE SIGNAL ;
    PORT
      LAYER M4 ;
        RECT 0.048 14.352 0.240 14.376 ;
    END
  END di[249]
  PIN di[250]
    DIRECTION INOUT ;
    USE SIGNAL ;
    PORT
      LAYER M4 ;
        RECT 0.048 14.400 0.240 14.424 ;
    END
  END di[250]
  PIN di[251]
    DIRECTION INOUT ;
    USE SIGNAL ;
    PORT
      LAYER M4 ;
        RECT 0.048 14.448 0.240 14.472 ;
    END
  END di[251]
  PIN di[252]
    DIRECTION INOUT ;
    USE SIGNAL ;
    PORT
      LAYER M4 ;
        RECT 0.048 14.496 0.240 14.520 ;
    END
  END di[252]
  PIN di[253]
    DIRECTION INOUT ;
    USE SIGNAL ;
    PORT
      LAYER M4 ;
        RECT 0.048 14.544 0.240 14.568 ;
    END
  END di[253]
  PIN di[254]
    DIRECTION INOUT ;
    USE SIGNAL ;
    PORT
      LAYER M4 ;
        RECT 0.048 14.592 0.240 14.616 ;
    END
  END di[254]
  PIN di[255]
    DIRECTION INOUT ;
    USE SIGNAL ;
    PORT
      LAYER M4 ;
        RECT 0.048 14.640 0.240 14.664 ;
    END
  END di[255]
  PIN di[256]
    DIRECTION INOUT ;
    USE SIGNAL ;
    PORT
      LAYER M4 ;
        RECT 0.048 14.688 0.240 14.712 ;
    END
  END di[256]
  PIN di[257]
    DIRECTION INOUT ;
    USE SIGNAL ;
    PORT
      LAYER M4 ;
        RECT 0.048 14.736 0.240 14.760 ;
    END
  END di[257]
  PIN di[258]
    DIRECTION INOUT ;
    USE SIGNAL ;
    PORT
      LAYER M4 ;
        RECT 0.048 14.784 0.240 14.808 ;
    END
  END di[258]
  PIN di[259]
    DIRECTION INOUT ;
    USE SIGNAL ;
    PORT
      LAYER M4 ;
        RECT 0.048 14.832 0.240 14.856 ;
    END
  END di[259]
  PIN di[260]
    DIRECTION INOUT ;
    USE SIGNAL ;
    PORT
      LAYER M4 ;
        RECT 0.048 14.880 0.240 14.904 ;
    END
  END di[260]
  PIN di[261]
    DIRECTION INOUT ;
    USE SIGNAL ;
    PORT
      LAYER M4 ;
        RECT 0.048 14.928 0.240 14.952 ;
    END
  END di[261]
  PIN di[262]
    DIRECTION INOUT ;
    USE SIGNAL ;
    PORT
      LAYER M4 ;
        RECT 0.048 14.976 0.240 15.000 ;
    END
  END di[262]
  PIN di[263]
    DIRECTION INOUT ;
    USE SIGNAL ;
    PORT
      LAYER M4 ;
        RECT 0.048 15.024 0.240 15.048 ;
    END
  END di[263]
  PIN di[264]
    DIRECTION INOUT ;
    USE SIGNAL ;
    PORT
      LAYER M4 ;
        RECT 0.048 15.072 0.240 15.096 ;
    END
  END di[264]
  PIN di[265]
    DIRECTION INOUT ;
    USE SIGNAL ;
    PORT
      LAYER M4 ;
        RECT 0.048 15.120 0.240 15.144 ;
    END
  END di[265]
  PIN di[266]
    DIRECTION INOUT ;
    USE SIGNAL ;
    PORT
      LAYER M4 ;
        RECT 0.048 15.168 0.240 15.192 ;
    END
  END di[266]
  PIN di[267]
    DIRECTION INOUT ;
    USE SIGNAL ;
    PORT
      LAYER M4 ;
        RECT 0.048 15.216 0.240 15.240 ;
    END
  END di[267]
  PIN di[268]
    DIRECTION INOUT ;
    USE SIGNAL ;
    PORT
      LAYER M4 ;
        RECT 0.048 15.264 0.240 15.288 ;
    END
  END di[268]
  PIN di[269]
    DIRECTION INOUT ;
    USE SIGNAL ;
    PORT
      LAYER M4 ;
        RECT 0.048 15.312 0.240 15.336 ;
    END
  END di[269]
  PIN di[270]
    DIRECTION INOUT ;
    USE SIGNAL ;
    PORT
      LAYER M4 ;
        RECT 0.048 15.360 0.240 15.384 ;
    END
  END di[270]
  PIN di[271]
    DIRECTION INOUT ;
    USE SIGNAL ;
    PORT
      LAYER M4 ;
        RECT 0.048 15.408 0.240 15.432 ;
    END
  END di[271]
  PIN di[272]
    DIRECTION INOUT ;
    USE SIGNAL ;
    PORT
      LAYER M4 ;
        RECT 0.048 15.456 0.240 15.480 ;
    END
  END di[272]
  PIN di[273]
    DIRECTION INOUT ;
    USE SIGNAL ;
    PORT
      LAYER M4 ;
        RECT 0.048 15.504 0.240 15.528 ;
    END
  END di[273]
  PIN di[274]
    DIRECTION INOUT ;
    USE SIGNAL ;
    PORT
      LAYER M4 ;
        RECT 0.048 15.552 0.240 15.576 ;
    END
  END di[274]
  PIN di[275]
    DIRECTION INOUT ;
    USE SIGNAL ;
    PORT
      LAYER M4 ;
        RECT 0.048 15.600 0.240 15.624 ;
    END
  END di[275]
  PIN di[276]
    DIRECTION INOUT ;
    USE SIGNAL ;
    PORT
      LAYER M4 ;
        RECT 0.048 15.648 0.240 15.672 ;
    END
  END di[276]
  PIN di[277]
    DIRECTION INOUT ;
    USE SIGNAL ;
    PORT
      LAYER M4 ;
        RECT 0.048 15.696 0.240 15.720 ;
    END
  END di[277]
  PIN di[278]
    DIRECTION INOUT ;
    USE SIGNAL ;
    PORT
      LAYER M4 ;
        RECT 0.048 15.744 0.240 15.768 ;
    END
  END di[278]
  PIN di[279]
    DIRECTION INOUT ;
    USE SIGNAL ;
    PORT
      LAYER M4 ;
        RECT 0.048 15.792 0.240 15.816 ;
    END
  END di[279]
  PIN di[280]
    DIRECTION INOUT ;
    USE SIGNAL ;
    PORT
      LAYER M4 ;
        RECT 0.048 15.840 0.240 15.864 ;
    END
  END di[280]
  PIN di[281]
    DIRECTION INOUT ;
    USE SIGNAL ;
    PORT
      LAYER M4 ;
        RECT 0.048 15.888 0.240 15.912 ;
    END
  END di[281]
  PIN di[282]
    DIRECTION INOUT ;
    USE SIGNAL ;
    PORT
      LAYER M4 ;
        RECT 0.048 15.936 0.240 15.960 ;
    END
  END di[282]
  PIN di[283]
    DIRECTION INOUT ;
    USE SIGNAL ;
    PORT
      LAYER M4 ;
        RECT 0.048 15.984 0.240 16.008 ;
    END
  END di[283]
  PIN di[284]
    DIRECTION INOUT ;
    USE SIGNAL ;
    PORT
      LAYER M4 ;
        RECT 0.048 16.032 0.240 16.056 ;
    END
  END di[284]
  PIN di[285]
    DIRECTION INOUT ;
    USE SIGNAL ;
    PORT
      LAYER M4 ;
        RECT 0.048 16.080 0.240 16.104 ;
    END
  END di[285]
  PIN di[286]
    DIRECTION INOUT ;
    USE SIGNAL ;
    PORT
      LAYER M4 ;
        RECT 0.048 16.128 0.240 16.152 ;
    END
  END di[286]
  PIN di[287]
    DIRECTION INOUT ;
    USE SIGNAL ;
    PORT
      LAYER M4 ;
        RECT 0.048 16.176 0.240 16.200 ;
    END
  END di[287]
  PIN di[288]
    DIRECTION INOUT ;
    USE SIGNAL ;
    PORT
      LAYER M4 ;
        RECT 0.048 16.224 0.240 16.248 ;
    END
  END di[288]
  PIN di[289]
    DIRECTION INOUT ;
    USE SIGNAL ;
    PORT
      LAYER M4 ;
        RECT 0.048 16.272 0.240 16.296 ;
    END
  END di[289]
  PIN di[290]
    DIRECTION INOUT ;
    USE SIGNAL ;
    PORT
      LAYER M4 ;
        RECT 0.048 16.320 0.240 16.344 ;
    END
  END di[290]
  PIN di[291]
    DIRECTION INOUT ;
    USE SIGNAL ;
    PORT
      LAYER M4 ;
        RECT 0.048 16.368 0.240 16.392 ;
    END
  END di[291]
  PIN di[292]
    DIRECTION INOUT ;
    USE SIGNAL ;
    PORT
      LAYER M4 ;
        RECT 0.048 16.416 0.240 16.440 ;
    END
  END di[292]
  PIN di[293]
    DIRECTION INOUT ;
    USE SIGNAL ;
    PORT
      LAYER M4 ;
        RECT 0.048 16.464 0.240 16.488 ;
    END
  END di[293]
  PIN di[294]
    DIRECTION INOUT ;
    USE SIGNAL ;
    PORT
      LAYER M4 ;
        RECT 0.048 16.512 0.240 16.536 ;
    END
  END di[294]
  PIN di[295]
    DIRECTION INOUT ;
    USE SIGNAL ;
    PORT
      LAYER M4 ;
        RECT 0.048 16.560 0.240 16.584 ;
    END
  END di[295]
  PIN di[296]
    DIRECTION INOUT ;
    USE SIGNAL ;
    PORT
      LAYER M4 ;
        RECT 0.048 16.608 0.240 16.632 ;
    END
  END di[296]
  PIN di[297]
    DIRECTION INOUT ;
    USE SIGNAL ;
    PORT
      LAYER M4 ;
        RECT 0.048 16.656 0.240 16.680 ;
    END
  END di[297]
  PIN di[298]
    DIRECTION INOUT ;
    USE SIGNAL ;
    PORT
      LAYER M4 ;
        RECT 0.048 16.704 0.240 16.728 ;
    END
  END di[298]
  PIN di[299]
    DIRECTION INOUT ;
    USE SIGNAL ;
    PORT
      LAYER M4 ;
        RECT 0.048 16.752 0.240 16.776 ;
    END
  END di[299]
  PIN di[300]
    DIRECTION INOUT ;
    USE SIGNAL ;
    PORT
      LAYER M4 ;
        RECT 0.048 16.800 0.240 16.824 ;
    END
  END di[300]
  PIN di[301]
    DIRECTION INOUT ;
    USE SIGNAL ;
    PORT
      LAYER M4 ;
        RECT 0.048 16.848 0.240 16.872 ;
    END
  END di[301]
  PIN di[302]
    DIRECTION INOUT ;
    USE SIGNAL ;
    PORT
      LAYER M4 ;
        RECT 0.048 16.896 0.240 16.920 ;
    END
  END di[302]
  PIN di[303]
    DIRECTION INOUT ;
    USE SIGNAL ;
    PORT
      LAYER M4 ;
        RECT 0.048 16.944 0.240 16.968 ;
    END
  END di[303]
  PIN di[304]
    DIRECTION INOUT ;
    USE SIGNAL ;
    PORT
      LAYER M4 ;
        RECT 0.048 16.992 0.240 17.016 ;
    END
  END di[304]
  PIN di[305]
    DIRECTION INOUT ;
    USE SIGNAL ;
    PORT
      LAYER M4 ;
        RECT 0.048 17.040 0.240 17.064 ;
    END
  END di[305]
  PIN di[306]
    DIRECTION INOUT ;
    USE SIGNAL ;
    PORT
      LAYER M4 ;
        RECT 0.048 17.088 0.240 17.112 ;
    END
  END di[306]
  PIN di[307]
    DIRECTION INOUT ;
    USE SIGNAL ;
    PORT
      LAYER M4 ;
        RECT 0.048 17.136 0.240 17.160 ;
    END
  END di[307]
  PIN di[308]
    DIRECTION INOUT ;
    USE SIGNAL ;
    PORT
      LAYER M4 ;
        RECT 0.048 17.184 0.240 17.208 ;
    END
  END di[308]
  PIN di[309]
    DIRECTION INOUT ;
    USE SIGNAL ;
    PORT
      LAYER M4 ;
        RECT 0.048 17.232 0.240 17.256 ;
    END
  END di[309]
  PIN di[310]
    DIRECTION INOUT ;
    USE SIGNAL ;
    PORT
      LAYER M4 ;
        RECT 0.048 17.280 0.240 17.304 ;
    END
  END di[310]
  PIN di[311]
    DIRECTION INOUT ;
    USE SIGNAL ;
    PORT
      LAYER M4 ;
        RECT 0.048 17.328 0.240 17.352 ;
    END
  END di[311]
  PIN di[312]
    DIRECTION INOUT ;
    USE SIGNAL ;
    PORT
      LAYER M4 ;
        RECT 0.048 17.376 0.240 17.400 ;
    END
  END di[312]
  PIN di[313]
    DIRECTION INOUT ;
    USE SIGNAL ;
    PORT
      LAYER M4 ;
        RECT 0.048 17.424 0.240 17.448 ;
    END
  END di[313]
  PIN di[314]
    DIRECTION INOUT ;
    USE SIGNAL ;
    PORT
      LAYER M4 ;
        RECT 0.048 17.472 0.240 17.496 ;
    END
  END di[314]
  PIN di[315]
    DIRECTION INOUT ;
    USE SIGNAL ;
    PORT
      LAYER M4 ;
        RECT 0.048 17.520 0.240 17.544 ;
    END
  END di[315]
  PIN di[316]
    DIRECTION INOUT ;
    USE SIGNAL ;
    PORT
      LAYER M4 ;
        RECT 0.048 17.568 0.240 17.592 ;
    END
  END di[316]
  PIN di[317]
    DIRECTION INOUT ;
    USE SIGNAL ;
    PORT
      LAYER M4 ;
        RECT 0.048 17.616 0.240 17.640 ;
    END
  END di[317]
  PIN di[318]
    DIRECTION INOUT ;
    USE SIGNAL ;
    PORT
      LAYER M4 ;
        RECT 0.048 17.664 0.240 17.688 ;
    END
  END di[318]
  PIN di[319]
    DIRECTION INOUT ;
    USE SIGNAL ;
    PORT
      LAYER M4 ;
        RECT 0.048 17.712 0.240 17.736 ;
    END
  END di[319]
  PIN di[320]
    DIRECTION INOUT ;
    USE SIGNAL ;
    PORT
      LAYER M4 ;
        RECT 0.048 17.760 0.240 17.784 ;
    END
  END di[320]
  PIN di[321]
    DIRECTION INOUT ;
    USE SIGNAL ;
    PORT
      LAYER M4 ;
        RECT 0.048 17.808 0.240 17.832 ;
    END
  END di[321]
  PIN di[322]
    DIRECTION INOUT ;
    USE SIGNAL ;
    PORT
      LAYER M4 ;
        RECT 0.048 17.856 0.240 17.880 ;
    END
  END di[322]
  PIN di[323]
    DIRECTION INOUT ;
    USE SIGNAL ;
    PORT
      LAYER M4 ;
        RECT 0.048 17.904 0.240 17.928 ;
    END
  END di[323]
  PIN di[324]
    DIRECTION INOUT ;
    USE SIGNAL ;
    PORT
      LAYER M4 ;
        RECT 0.048 17.952 0.240 17.976 ;
    END
  END di[324]
  PIN di[325]
    DIRECTION INOUT ;
    USE SIGNAL ;
    PORT
      LAYER M4 ;
        RECT 0.048 18.000 0.240 18.024 ;
    END
  END di[325]
  PIN di[326]
    DIRECTION INOUT ;
    USE SIGNAL ;
    PORT
      LAYER M4 ;
        RECT 0.048 18.048 0.240 18.072 ;
    END
  END di[326]
  PIN di[327]
    DIRECTION INOUT ;
    USE SIGNAL ;
    PORT
      LAYER M4 ;
        RECT 0.048 18.096 0.240 18.120 ;
    END
  END di[327]
  PIN di[328]
    DIRECTION INOUT ;
    USE SIGNAL ;
    PORT
      LAYER M4 ;
        RECT 0.048 18.144 0.240 18.168 ;
    END
  END di[328]
  PIN di[329]
    DIRECTION INOUT ;
    USE SIGNAL ;
    PORT
      LAYER M4 ;
        RECT 0.048 18.192 0.240 18.216 ;
    END
  END di[329]
  PIN di[330]
    DIRECTION INOUT ;
    USE SIGNAL ;
    PORT
      LAYER M4 ;
        RECT 0.048 18.240 0.240 18.264 ;
    END
  END di[330]
  PIN di[331]
    DIRECTION INOUT ;
    USE SIGNAL ;
    PORT
      LAYER M4 ;
        RECT 0.048 18.288 0.240 18.312 ;
    END
  END di[331]
  PIN di[332]
    DIRECTION INOUT ;
    USE SIGNAL ;
    PORT
      LAYER M4 ;
        RECT 0.048 18.336 0.240 18.360 ;
    END
  END di[332]
  PIN di[333]
    DIRECTION INOUT ;
    USE SIGNAL ;
    PORT
      LAYER M4 ;
        RECT 0.048 18.384 0.240 18.408 ;
    END
  END di[333]
  PIN di[334]
    DIRECTION INOUT ;
    USE SIGNAL ;
    PORT
      LAYER M4 ;
        RECT 0.048 18.432 0.240 18.456 ;
    END
  END di[334]
  PIN di[335]
    DIRECTION INOUT ;
    USE SIGNAL ;
    PORT
      LAYER M4 ;
        RECT 0.048 18.480 0.240 18.504 ;
    END
  END di[335]
  PIN di[336]
    DIRECTION INOUT ;
    USE SIGNAL ;
    PORT
      LAYER M4 ;
        RECT 0.048 18.528 0.240 18.552 ;
    END
  END di[336]
  PIN di[337]
    DIRECTION INOUT ;
    USE SIGNAL ;
    PORT
      LAYER M4 ;
        RECT 0.048 18.576 0.240 18.600 ;
    END
  END di[337]
  PIN di[338]
    DIRECTION INOUT ;
    USE SIGNAL ;
    PORT
      LAYER M4 ;
        RECT 0.048 18.624 0.240 18.648 ;
    END
  END di[338]
  PIN di[339]
    DIRECTION INOUT ;
    USE SIGNAL ;
    PORT
      LAYER M4 ;
        RECT 0.048 18.672 0.240 18.696 ;
    END
  END di[339]
  PIN di[340]
    DIRECTION INOUT ;
    USE SIGNAL ;
    PORT
      LAYER M4 ;
        RECT 0.048 18.720 0.240 18.744 ;
    END
  END di[340]
  PIN di[341]
    DIRECTION INOUT ;
    USE SIGNAL ;
    PORT
      LAYER M4 ;
        RECT 0.048 18.768 0.240 18.792 ;
    END
  END di[341]
  PIN di[342]
    DIRECTION INOUT ;
    USE SIGNAL ;
    PORT
      LAYER M4 ;
        RECT 0.048 18.816 0.240 18.840 ;
    END
  END di[342]
  PIN di[343]
    DIRECTION INOUT ;
    USE SIGNAL ;
    PORT
      LAYER M4 ;
        RECT 0.048 18.864 0.240 18.888 ;
    END
  END di[343]
  PIN di[344]
    DIRECTION INOUT ;
    USE SIGNAL ;
    PORT
      LAYER M4 ;
        RECT 0.048 18.912 0.240 18.936 ;
    END
  END di[344]
  PIN di[345]
    DIRECTION INOUT ;
    USE SIGNAL ;
    PORT
      LAYER M4 ;
        RECT 0.048 18.960 0.240 18.984 ;
    END
  END di[345]
  PIN di[346]
    DIRECTION INOUT ;
    USE SIGNAL ;
    PORT
      LAYER M4 ;
        RECT 0.048 19.008 0.240 19.032 ;
    END
  END di[346]
  PIN di[347]
    DIRECTION INOUT ;
    USE SIGNAL ;
    PORT
      LAYER M4 ;
        RECT 0.048 19.056 0.240 19.080 ;
    END
  END di[347]
  PIN di[348]
    DIRECTION INOUT ;
    USE SIGNAL ;
    PORT
      LAYER M4 ;
        RECT 0.048 19.104 0.240 19.128 ;
    END
  END di[348]
  PIN di[349]
    DIRECTION INOUT ;
    USE SIGNAL ;
    PORT
      LAYER M4 ;
        RECT 0.048 19.152 0.240 19.176 ;
    END
  END di[349]
  PIN di[350]
    DIRECTION INOUT ;
    USE SIGNAL ;
    PORT
      LAYER M4 ;
        RECT 0.048 19.200 0.240 19.224 ;
    END
  END di[350]
  PIN di[351]
    DIRECTION INOUT ;
    USE SIGNAL ;
    PORT
      LAYER M4 ;
        RECT 0.048 19.248 0.240 19.272 ;
    END
  END di[351]
  PIN di[352]
    DIRECTION INOUT ;
    USE SIGNAL ;
    PORT
      LAYER M4 ;
        RECT 0.048 19.296 0.240 19.320 ;
    END
  END di[352]
  PIN di[353]
    DIRECTION INOUT ;
    USE SIGNAL ;
    PORT
      LAYER M4 ;
        RECT 0.048 19.344 0.240 19.368 ;
    END
  END di[353]
  PIN di[354]
    DIRECTION INOUT ;
    USE SIGNAL ;
    PORT
      LAYER M4 ;
        RECT 0.048 19.392 0.240 19.416 ;
    END
  END di[354]
  PIN di[355]
    DIRECTION INOUT ;
    USE SIGNAL ;
    PORT
      LAYER M4 ;
        RECT 0.048 19.440 0.240 19.464 ;
    END
  END di[355]
  PIN di[356]
    DIRECTION INOUT ;
    USE SIGNAL ;
    PORT
      LAYER M4 ;
        RECT 0.048 19.488 0.240 19.512 ;
    END
  END di[356]
  PIN di[357]
    DIRECTION INOUT ;
    USE SIGNAL ;
    PORT
      LAYER M4 ;
        RECT 0.048 19.536 0.240 19.560 ;
    END
  END di[357]
  PIN di[358]
    DIRECTION INOUT ;
    USE SIGNAL ;
    PORT
      LAYER M4 ;
        RECT 0.048 19.584 0.240 19.608 ;
    END
  END di[358]
  PIN di[359]
    DIRECTION INOUT ;
    USE SIGNAL ;
    PORT
      LAYER M4 ;
        RECT 0.048 19.632 0.240 19.656 ;
    END
  END di[359]
  PIN di[360]
    DIRECTION INOUT ;
    USE SIGNAL ;
    PORT
      LAYER M4 ;
        RECT 0.048 19.680 0.240 19.704 ;
    END
  END di[360]
  PIN di[361]
    DIRECTION INOUT ;
    USE SIGNAL ;
    PORT
      LAYER M4 ;
        RECT 0.048 19.728 0.240 19.752 ;
    END
  END di[361]
  PIN di[362]
    DIRECTION INOUT ;
    USE SIGNAL ;
    PORT
      LAYER M4 ;
        RECT 0.048 19.776 0.240 19.800 ;
    END
  END di[362]
  PIN di[363]
    DIRECTION INOUT ;
    USE SIGNAL ;
    PORT
      LAYER M4 ;
        RECT 0.048 19.824 0.240 19.848 ;
    END
  END di[363]
  PIN di[364]
    DIRECTION INOUT ;
    USE SIGNAL ;
    PORT
      LAYER M4 ;
        RECT 0.048 19.872 0.240 19.896 ;
    END
  END di[364]
  PIN di[365]
    DIRECTION INOUT ;
    USE SIGNAL ;
    PORT
      LAYER M4 ;
        RECT 0.048 19.920 0.240 19.944 ;
    END
  END di[365]
  PIN di[366]
    DIRECTION INOUT ;
    USE SIGNAL ;
    PORT
      LAYER M4 ;
        RECT 0.048 19.968 0.240 19.992 ;
    END
  END di[366]
  PIN di[367]
    DIRECTION INOUT ;
    USE SIGNAL ;
    PORT
      LAYER M4 ;
        RECT 0.048 20.016 0.240 20.040 ;
    END
  END di[367]
  PIN di[368]
    DIRECTION INOUT ;
    USE SIGNAL ;
    PORT
      LAYER M4 ;
        RECT 0.048 20.064 0.240 20.088 ;
    END
  END di[368]
  PIN di[369]
    DIRECTION INOUT ;
    USE SIGNAL ;
    PORT
      LAYER M4 ;
        RECT 0.048 20.112 0.240 20.136 ;
    END
  END di[369]
  PIN di[370]
    DIRECTION INOUT ;
    USE SIGNAL ;
    PORT
      LAYER M4 ;
        RECT 0.048 20.160 0.240 20.184 ;
    END
  END di[370]
  PIN di[371]
    DIRECTION INOUT ;
    USE SIGNAL ;
    PORT
      LAYER M4 ;
        RECT 0.048 20.208 0.240 20.232 ;
    END
  END di[371]
  PIN di[372]
    DIRECTION INOUT ;
    USE SIGNAL ;
    PORT
      LAYER M4 ;
        RECT 0.048 20.256 0.240 20.280 ;
    END
  END di[372]
  PIN di[373]
    DIRECTION INOUT ;
    USE SIGNAL ;
    PORT
      LAYER M4 ;
        RECT 0.048 20.304 0.240 20.328 ;
    END
  END di[373]
  PIN di[374]
    DIRECTION INOUT ;
    USE SIGNAL ;
    PORT
      LAYER M4 ;
        RECT 0.048 20.352 0.240 20.376 ;
    END
  END di[374]
  PIN di[375]
    DIRECTION INOUT ;
    USE SIGNAL ;
    PORT
      LAYER M4 ;
        RECT 0.048 20.400 0.240 20.424 ;
    END
  END di[375]
  PIN di[376]
    DIRECTION INOUT ;
    USE SIGNAL ;
    PORT
      LAYER M4 ;
        RECT 0.048 20.448 0.240 20.472 ;
    END
  END di[376]
  PIN di[377]
    DIRECTION INOUT ;
    USE SIGNAL ;
    PORT
      LAYER M4 ;
        RECT 0.048 20.496 0.240 20.520 ;
    END
  END di[377]
  PIN di[378]
    DIRECTION INOUT ;
    USE SIGNAL ;
    PORT
      LAYER M4 ;
        RECT 0.048 20.544 0.240 20.568 ;
    END
  END di[378]
  PIN di[379]
    DIRECTION INOUT ;
    USE SIGNAL ;
    PORT
      LAYER M4 ;
        RECT 0.048 20.592 0.240 20.616 ;
    END
  END di[379]
  PIN di[380]
    DIRECTION INOUT ;
    USE SIGNAL ;
    PORT
      LAYER M4 ;
        RECT 0.048 20.640 0.240 20.664 ;
    END
  END di[380]
  PIN di[381]
    DIRECTION INOUT ;
    USE SIGNAL ;
    PORT
      LAYER M4 ;
        RECT 0.048 20.688 0.240 20.712 ;
    END
  END di[381]
  PIN di[382]
    DIRECTION INOUT ;
    USE SIGNAL ;
    PORT
      LAYER M4 ;
        RECT 0.048 20.736 0.240 20.760 ;
    END
  END di[382]
  PIN di[383]
    DIRECTION INOUT ;
    USE SIGNAL ;
    PORT
      LAYER M4 ;
        RECT 0.048 20.784 0.240 20.808 ;
    END
  END di[383]
  PIN di[384]
    DIRECTION INOUT ;
    USE SIGNAL ;
    PORT
      LAYER M4 ;
        RECT 0.048 20.832 0.240 20.856 ;
    END
  END di[384]
  PIN di[385]
    DIRECTION INOUT ;
    USE SIGNAL ;
    PORT
      LAYER M4 ;
        RECT 0.048 20.880 0.240 20.904 ;
    END
  END di[385]
  PIN di[386]
    DIRECTION INOUT ;
    USE SIGNAL ;
    PORT
      LAYER M4 ;
        RECT 0.048 20.928 0.240 20.952 ;
    END
  END di[386]
  PIN di[387]
    DIRECTION INOUT ;
    USE SIGNAL ;
    PORT
      LAYER M4 ;
        RECT 0.048 20.976 0.240 21.000 ;
    END
  END di[387]
  PIN di[388]
    DIRECTION INOUT ;
    USE SIGNAL ;
    PORT
      LAYER M4 ;
        RECT 0.048 21.024 0.240 21.048 ;
    END
  END di[388]
  PIN di[389]
    DIRECTION INOUT ;
    USE SIGNAL ;
    PORT
      LAYER M4 ;
        RECT 0.048 21.072 0.240 21.096 ;
    END
  END di[389]
  PIN di[390]
    DIRECTION INOUT ;
    USE SIGNAL ;
    PORT
      LAYER M4 ;
        RECT 0.048 21.120 0.240 21.144 ;
    END
  END di[390]
  PIN di[391]
    DIRECTION INOUT ;
    USE SIGNAL ;
    PORT
      LAYER M4 ;
        RECT 0.048 21.168 0.240 21.192 ;
    END
  END di[391]
  PIN di[392]
    DIRECTION INOUT ;
    USE SIGNAL ;
    PORT
      LAYER M4 ;
        RECT 0.048 21.216 0.240 21.240 ;
    END
  END di[392]
  PIN di[393]
    DIRECTION INOUT ;
    USE SIGNAL ;
    PORT
      LAYER M4 ;
        RECT 0.048 21.264 0.240 21.288 ;
    END
  END di[393]
  PIN di[394]
    DIRECTION INOUT ;
    USE SIGNAL ;
    PORT
      LAYER M4 ;
        RECT 0.048 21.312 0.240 21.336 ;
    END
  END di[394]
  PIN di[395]
    DIRECTION INOUT ;
    USE SIGNAL ;
    PORT
      LAYER M4 ;
        RECT 0.048 21.360 0.240 21.384 ;
    END
  END di[395]
  PIN di[396]
    DIRECTION INOUT ;
    USE SIGNAL ;
    PORT
      LAYER M4 ;
        RECT 0.048 21.408 0.240 21.432 ;
    END
  END di[396]
  PIN di[397]
    DIRECTION INOUT ;
    USE SIGNAL ;
    PORT
      LAYER M4 ;
        RECT 0.048 21.456 0.240 21.480 ;
    END
  END di[397]
  PIN di[398]
    DIRECTION INOUT ;
    USE SIGNAL ;
    PORT
      LAYER M4 ;
        RECT 0.048 21.504 0.240 21.528 ;
    END
  END di[398]
  PIN di[399]
    DIRECTION INOUT ;
    USE SIGNAL ;
    PORT
      LAYER M4 ;
        RECT 0.048 21.552 0.240 21.576 ;
    END
  END di[399]
  PIN di[400]
    DIRECTION INOUT ;
    USE SIGNAL ;
    PORT
      LAYER M4 ;
        RECT 0.048 21.600 0.240 21.624 ;
    END
  END di[400]
  PIN di[401]
    DIRECTION INOUT ;
    USE SIGNAL ;
    PORT
      LAYER M4 ;
        RECT 0.048 21.648 0.240 21.672 ;
    END
  END di[401]
  PIN di[402]
    DIRECTION INOUT ;
    USE SIGNAL ;
    PORT
      LAYER M4 ;
        RECT 0.048 21.696 0.240 21.720 ;
    END
  END di[402]
  PIN di[403]
    DIRECTION INOUT ;
    USE SIGNAL ;
    PORT
      LAYER M4 ;
        RECT 0.048 21.744 0.240 21.768 ;
    END
  END di[403]
  PIN di[404]
    DIRECTION INOUT ;
    USE SIGNAL ;
    PORT
      LAYER M4 ;
        RECT 0.048 21.792 0.240 21.816 ;
    END
  END di[404]
  PIN di[405]
    DIRECTION INOUT ;
    USE SIGNAL ;
    PORT
      LAYER M4 ;
        RECT 0.048 21.840 0.240 21.864 ;
    END
  END di[405]
  PIN di[406]
    DIRECTION INOUT ;
    USE SIGNAL ;
    PORT
      LAYER M4 ;
        RECT 0.048 21.888 0.240 21.912 ;
    END
  END di[406]
  PIN di[407]
    DIRECTION INOUT ;
    USE SIGNAL ;
    PORT
      LAYER M4 ;
        RECT 0.048 21.936 0.240 21.960 ;
    END
  END di[407]
  PIN di[408]
    DIRECTION INOUT ;
    USE SIGNAL ;
    PORT
      LAYER M4 ;
        RECT 0.048 21.984 0.240 22.008 ;
    END
  END di[408]
  PIN di[409]
    DIRECTION INOUT ;
    USE SIGNAL ;
    PORT
      LAYER M4 ;
        RECT 0.048 22.032 0.240 22.056 ;
    END
  END di[409]
  PIN di[410]
    DIRECTION INOUT ;
    USE SIGNAL ;
    PORT
      LAYER M4 ;
        RECT 0.048 22.080 0.240 22.104 ;
    END
  END di[410]
  PIN di[411]
    DIRECTION INOUT ;
    USE SIGNAL ;
    PORT
      LAYER M4 ;
        RECT 0.048 22.128 0.240 22.152 ;
    END
  END di[411]
  PIN di[412]
    DIRECTION INOUT ;
    USE SIGNAL ;
    PORT
      LAYER M4 ;
        RECT 0.048 22.176 0.240 22.200 ;
    END
  END di[412]
  PIN di[413]
    DIRECTION INOUT ;
    USE SIGNAL ;
    PORT
      LAYER M4 ;
        RECT 0.048 22.224 0.240 22.248 ;
    END
  END di[413]
  PIN di[414]
    DIRECTION INOUT ;
    USE SIGNAL ;
    PORT
      LAYER M4 ;
        RECT 0.048 22.272 0.240 22.296 ;
    END
  END di[414]
  PIN di[415]
    DIRECTION INOUT ;
    USE SIGNAL ;
    PORT
      LAYER M4 ;
        RECT 0.048 22.320 0.240 22.344 ;
    END
  END di[415]
  PIN di[416]
    DIRECTION INOUT ;
    USE SIGNAL ;
    PORT
      LAYER M4 ;
        RECT 0.048 22.368 0.240 22.392 ;
    END
  END di[416]
  PIN di[417]
    DIRECTION INOUT ;
    USE SIGNAL ;
    PORT
      LAYER M4 ;
        RECT 0.048 22.416 0.240 22.440 ;
    END
  END di[417]
  PIN di[418]
    DIRECTION INOUT ;
    USE SIGNAL ;
    PORT
      LAYER M4 ;
        RECT 0.048 22.464 0.240 22.488 ;
    END
  END di[418]
  PIN di[419]
    DIRECTION INOUT ;
    USE SIGNAL ;
    PORT
      LAYER M4 ;
        RECT 0.048 22.512 0.240 22.536 ;
    END
  END di[419]
  PIN di[420]
    DIRECTION INOUT ;
    USE SIGNAL ;
    PORT
      LAYER M4 ;
        RECT 0.048 22.560 0.240 22.584 ;
    END
  END di[420]
  PIN di[421]
    DIRECTION INOUT ;
    USE SIGNAL ;
    PORT
      LAYER M4 ;
        RECT 0.048 22.608 0.240 22.632 ;
    END
  END di[421]
  PIN di[422]
    DIRECTION INOUT ;
    USE SIGNAL ;
    PORT
      LAYER M4 ;
        RECT 0.048 22.656 0.240 22.680 ;
    END
  END di[422]
  PIN di[423]
    DIRECTION INOUT ;
    USE SIGNAL ;
    PORT
      LAYER M4 ;
        RECT 0.048 22.704 0.240 22.728 ;
    END
  END di[423]
  PIN di[424]
    DIRECTION INOUT ;
    USE SIGNAL ;
    PORT
      LAYER M4 ;
        RECT 0.048 22.752 0.240 22.776 ;
    END
  END di[424]
  PIN di[425]
    DIRECTION INOUT ;
    USE SIGNAL ;
    PORT
      LAYER M4 ;
        RECT 0.048 22.800 0.240 22.824 ;
    END
  END di[425]
  PIN di[426]
    DIRECTION INOUT ;
    USE SIGNAL ;
    PORT
      LAYER M4 ;
        RECT 0.048 22.848 0.240 22.872 ;
    END
  END di[426]
  PIN di[427]
    DIRECTION INOUT ;
    USE SIGNAL ;
    PORT
      LAYER M4 ;
        RECT 0.048 22.896 0.240 22.920 ;
    END
  END di[427]
  PIN di[428]
    DIRECTION INOUT ;
    USE SIGNAL ;
    PORT
      LAYER M4 ;
        RECT 0.048 22.944 0.240 22.968 ;
    END
  END di[428]
  PIN di[429]
    DIRECTION INOUT ;
    USE SIGNAL ;
    PORT
      LAYER M4 ;
        RECT 0.048 22.992 0.240 23.016 ;
    END
  END di[429]
  PIN di[430]
    DIRECTION INOUT ;
    USE SIGNAL ;
    PORT
      LAYER M4 ;
        RECT 0.048 23.040 0.240 23.064 ;
    END
  END di[430]
  PIN di[431]
    DIRECTION INOUT ;
    USE SIGNAL ;
    PORT
      LAYER M4 ;
        RECT 0.048 23.088 0.240 23.112 ;
    END
  END di[431]
  PIN di[432]
    DIRECTION INOUT ;
    USE SIGNAL ;
    PORT
      LAYER M4 ;
        RECT 0.048 23.136 0.240 23.160 ;
    END
  END di[432]
  PIN di[433]
    DIRECTION INOUT ;
    USE SIGNAL ;
    PORT
      LAYER M4 ;
        RECT 0.048 23.184 0.240 23.208 ;
    END
  END di[433]
  PIN di[434]
    DIRECTION INOUT ;
    USE SIGNAL ;
    PORT
      LAYER M4 ;
        RECT 0.048 23.232 0.240 23.256 ;
    END
  END di[434]
  PIN di[435]
    DIRECTION INOUT ;
    USE SIGNAL ;
    PORT
      LAYER M4 ;
        RECT 0.048 23.280 0.240 23.304 ;
    END
  END di[435]
  PIN di[436]
    DIRECTION INOUT ;
    USE SIGNAL ;
    PORT
      LAYER M4 ;
        RECT 0.048 23.328 0.240 23.352 ;
    END
  END di[436]
  PIN di[437]
    DIRECTION INOUT ;
    USE SIGNAL ;
    PORT
      LAYER M4 ;
        RECT 0.048 23.376 0.240 23.400 ;
    END
  END di[437]
  PIN di[438]
    DIRECTION INOUT ;
    USE SIGNAL ;
    PORT
      LAYER M4 ;
        RECT 0.048 23.424 0.240 23.448 ;
    END
  END di[438]
  PIN di[439]
    DIRECTION INOUT ;
    USE SIGNAL ;
    PORT
      LAYER M4 ;
        RECT 0.048 23.472 0.240 23.496 ;
    END
  END di[439]
  PIN di[440]
    DIRECTION INOUT ;
    USE SIGNAL ;
    PORT
      LAYER M4 ;
        RECT 0.048 23.520 0.240 23.544 ;
    END
  END di[440]
  PIN di[441]
    DIRECTION INOUT ;
    USE SIGNAL ;
    PORT
      LAYER M4 ;
        RECT 0.048 23.568 0.240 23.592 ;
    END
  END di[441]
  PIN di[442]
    DIRECTION INOUT ;
    USE SIGNAL ;
    PORT
      LAYER M4 ;
        RECT 0.048 23.616 0.240 23.640 ;
    END
  END di[442]
  PIN di[443]
    DIRECTION INOUT ;
    USE SIGNAL ;
    PORT
      LAYER M4 ;
        RECT 0.048 23.664 0.240 23.688 ;
    END
  END di[443]
  PIN di[444]
    DIRECTION INOUT ;
    USE SIGNAL ;
    PORT
      LAYER M4 ;
        RECT 0.048 23.712 0.240 23.736 ;
    END
  END di[444]
  PIN di[445]
    DIRECTION INOUT ;
    USE SIGNAL ;
    PORT
      LAYER M4 ;
        RECT 0.048 23.760 0.240 23.784 ;
    END
  END di[445]
  PIN di[446]
    DIRECTION INOUT ;
    USE SIGNAL ;
    PORT
      LAYER M4 ;
        RECT 0.048 23.808 0.240 23.832 ;
    END
  END di[446]
  PIN di[447]
    DIRECTION INOUT ;
    USE SIGNAL ;
    PORT
      LAYER M4 ;
        RECT 0.048 23.856 0.240 23.880 ;
    END
  END di[447]
  PIN di[448]
    DIRECTION INOUT ;
    USE SIGNAL ;
    PORT
      LAYER M4 ;
        RECT 0.048 23.904 0.240 23.928 ;
    END
  END di[448]
  PIN di[449]
    DIRECTION INOUT ;
    USE SIGNAL ;
    PORT
      LAYER M4 ;
        RECT 0.048 23.952 0.240 23.976 ;
    END
  END di[449]
  PIN di[450]
    DIRECTION INOUT ;
    USE SIGNAL ;
    PORT
      LAYER M4 ;
        RECT 0.048 24.000 0.240 24.024 ;
    END
  END di[450]
  PIN di[451]
    DIRECTION INOUT ;
    USE SIGNAL ;
    PORT
      LAYER M4 ;
        RECT 0.048 24.048 0.240 24.072 ;
    END
  END di[451]
  PIN di[452]
    DIRECTION INOUT ;
    USE SIGNAL ;
    PORT
      LAYER M4 ;
        RECT 0.048 24.096 0.240 24.120 ;
    END
  END di[452]
  PIN di[453]
    DIRECTION INOUT ;
    USE SIGNAL ;
    PORT
      LAYER M4 ;
        RECT 0.048 24.144 0.240 24.168 ;
    END
  END di[453]
  PIN di[454]
    DIRECTION INOUT ;
    USE SIGNAL ;
    PORT
      LAYER M4 ;
        RECT 0.048 24.192 0.240 24.216 ;
    END
  END di[454]
  PIN di[455]
    DIRECTION INOUT ;
    USE SIGNAL ;
    PORT
      LAYER M4 ;
        RECT 0.048 24.240 0.240 24.264 ;
    END
  END di[455]
  PIN di[456]
    DIRECTION INOUT ;
    USE SIGNAL ;
    PORT
      LAYER M4 ;
        RECT 0.048 24.288 0.240 24.312 ;
    END
  END di[456]
  PIN di[457]
    DIRECTION INOUT ;
    USE SIGNAL ;
    PORT
      LAYER M4 ;
        RECT 0.048 24.336 0.240 24.360 ;
    END
  END di[457]
  PIN di[458]
    DIRECTION INOUT ;
    USE SIGNAL ;
    PORT
      LAYER M4 ;
        RECT 0.048 24.384 0.240 24.408 ;
    END
  END di[458]
  PIN di[459]
    DIRECTION INOUT ;
    USE SIGNAL ;
    PORT
      LAYER M4 ;
        RECT 0.048 24.432 0.240 24.456 ;
    END
  END di[459]
  PIN di[460]
    DIRECTION INOUT ;
    USE SIGNAL ;
    PORT
      LAYER M4 ;
        RECT 0.048 24.480 0.240 24.504 ;
    END
  END di[460]
  PIN di[461]
    DIRECTION INOUT ;
    USE SIGNAL ;
    PORT
      LAYER M4 ;
        RECT 0.048 24.528 0.240 24.552 ;
    END
  END di[461]
  PIN di[462]
    DIRECTION INOUT ;
    USE SIGNAL ;
    PORT
      LAYER M4 ;
        RECT 0.048 24.576 0.240 24.600 ;
    END
  END di[462]
  PIN di[463]
    DIRECTION INOUT ;
    USE SIGNAL ;
    PORT
      LAYER M4 ;
        RECT 0.048 24.624 0.240 24.648 ;
    END
  END di[463]
  PIN di[464]
    DIRECTION INOUT ;
    USE SIGNAL ;
    PORT
      LAYER M4 ;
        RECT 0.048 24.672 0.240 24.696 ;
    END
  END di[464]
  PIN di[465]
    DIRECTION INOUT ;
    USE SIGNAL ;
    PORT
      LAYER M4 ;
        RECT 0.048 24.720 0.240 24.744 ;
    END
  END di[465]
  PIN di[466]
    DIRECTION INOUT ;
    USE SIGNAL ;
    PORT
      LAYER M4 ;
        RECT 0.048 24.768 0.240 24.792 ;
    END
  END di[466]
  PIN di[467]
    DIRECTION INOUT ;
    USE SIGNAL ;
    PORT
      LAYER M4 ;
        RECT 0.048 24.816 0.240 24.840 ;
    END
  END di[467]
  PIN di[468]
    DIRECTION INOUT ;
    USE SIGNAL ;
    PORT
      LAYER M4 ;
        RECT 0.048 24.864 0.240 24.888 ;
    END
  END di[468]
  PIN di[469]
    DIRECTION INOUT ;
    USE SIGNAL ;
    PORT
      LAYER M4 ;
        RECT 0.048 24.912 0.240 24.936 ;
    END
  END di[469]
  PIN di[470]
    DIRECTION INOUT ;
    USE SIGNAL ;
    PORT
      LAYER M4 ;
        RECT 0.048 24.960 0.240 24.984 ;
    END
  END di[470]
  PIN di[471]
    DIRECTION INOUT ;
    USE SIGNAL ;
    PORT
      LAYER M4 ;
        RECT 0.048 25.008 0.240 25.032 ;
    END
  END di[471]
  PIN di[472]
    DIRECTION INOUT ;
    USE SIGNAL ;
    PORT
      LAYER M4 ;
        RECT 0.048 25.056 0.240 25.080 ;
    END
  END di[472]
  PIN di[473]
    DIRECTION INOUT ;
    USE SIGNAL ;
    PORT
      LAYER M4 ;
        RECT 0.048 25.104 0.240 25.128 ;
    END
  END di[473]
  PIN di[474]
    DIRECTION INOUT ;
    USE SIGNAL ;
    PORT
      LAYER M4 ;
        RECT 0.048 25.152 0.240 25.176 ;
    END
  END di[474]
  PIN di[475]
    DIRECTION INOUT ;
    USE SIGNAL ;
    PORT
      LAYER M4 ;
        RECT 0.048 25.200 0.240 25.224 ;
    END
  END di[475]
  PIN di[476]
    DIRECTION INOUT ;
    USE SIGNAL ;
    PORT
      LAYER M4 ;
        RECT 0.048 25.248 0.240 25.272 ;
    END
  END di[476]
  PIN di[477]
    DIRECTION INOUT ;
    USE SIGNAL ;
    PORT
      LAYER M4 ;
        RECT 0.048 25.296 0.240 25.320 ;
    END
  END di[477]
  PIN di[478]
    DIRECTION INOUT ;
    USE SIGNAL ;
    PORT
      LAYER M4 ;
        RECT 0.048 25.344 0.240 25.368 ;
    END
  END di[478]
  PIN di[479]
    DIRECTION INOUT ;
    USE SIGNAL ;
    PORT
      LAYER M4 ;
        RECT 0.048 25.392 0.240 25.416 ;
    END
  END di[479]
  PIN di[480]
    DIRECTION INOUT ;
    USE SIGNAL ;
    PORT
      LAYER M4 ;
        RECT 0.048 25.440 0.240 25.464 ;
    END
  END di[480]
  PIN di[481]
    DIRECTION INOUT ;
    USE SIGNAL ;
    PORT
      LAYER M4 ;
        RECT 0.048 25.488 0.240 25.512 ;
    END
  END di[481]
  PIN di[482]
    DIRECTION INOUT ;
    USE SIGNAL ;
    PORT
      LAYER M4 ;
        RECT 0.048 25.536 0.240 25.560 ;
    END
  END di[482]
  PIN di[483]
    DIRECTION INOUT ;
    USE SIGNAL ;
    PORT
      LAYER M4 ;
        RECT 0.048 25.584 0.240 25.608 ;
    END
  END di[483]
  PIN di[484]
    DIRECTION INOUT ;
    USE SIGNAL ;
    PORT
      LAYER M4 ;
        RECT 0.048 25.632 0.240 25.656 ;
    END
  END di[484]
  PIN di[485]
    DIRECTION INOUT ;
    USE SIGNAL ;
    PORT
      LAYER M4 ;
        RECT 0.048 25.680 0.240 25.704 ;
    END
  END di[485]
  PIN di[486]
    DIRECTION INOUT ;
    USE SIGNAL ;
    PORT
      LAYER M4 ;
        RECT 0.048 25.728 0.240 25.752 ;
    END
  END di[486]
  PIN di[487]
    DIRECTION INOUT ;
    USE SIGNAL ;
    PORT
      LAYER M4 ;
        RECT 0.048 25.776 0.240 25.800 ;
    END
  END di[487]
  PIN di[488]
    DIRECTION INOUT ;
    USE SIGNAL ;
    PORT
      LAYER M4 ;
        RECT 0.048 25.824 0.240 25.848 ;
    END
  END di[488]
  PIN di[489]
    DIRECTION INOUT ;
    USE SIGNAL ;
    PORT
      LAYER M4 ;
        RECT 0.048 25.872 0.240 25.896 ;
    END
  END di[489]
  PIN di[490]
    DIRECTION INOUT ;
    USE SIGNAL ;
    PORT
      LAYER M4 ;
        RECT 0.048 25.920 0.240 25.944 ;
    END
  END di[490]
  PIN di[491]
    DIRECTION INOUT ;
    USE SIGNAL ;
    PORT
      LAYER M4 ;
        RECT 0.048 25.968 0.240 25.992 ;
    END
  END di[491]
  PIN di[492]
    DIRECTION INOUT ;
    USE SIGNAL ;
    PORT
      LAYER M4 ;
        RECT 0.048 26.016 0.240 26.040 ;
    END
  END di[492]
  PIN di[493]
    DIRECTION INOUT ;
    USE SIGNAL ;
    PORT
      LAYER M4 ;
        RECT 0.048 26.064 0.240 26.088 ;
    END
  END di[493]
  PIN di[494]
    DIRECTION INOUT ;
    USE SIGNAL ;
    PORT
      LAYER M4 ;
        RECT 0.048 26.112 0.240 26.136 ;
    END
  END di[494]
  PIN di[495]
    DIRECTION INOUT ;
    USE SIGNAL ;
    PORT
      LAYER M4 ;
        RECT 0.048 26.160 0.240 26.184 ;
    END
  END di[495]
  PIN di[496]
    DIRECTION INOUT ;
    USE SIGNAL ;
    PORT
      LAYER M4 ;
        RECT 0.048 26.208 0.240 26.232 ;
    END
  END di[496]
  PIN di[497]
    DIRECTION INOUT ;
    USE SIGNAL ;
    PORT
      LAYER M4 ;
        RECT 0.048 26.256 0.240 26.280 ;
    END
  END di[497]
  PIN di[498]
    DIRECTION INOUT ;
    USE SIGNAL ;
    PORT
      LAYER M4 ;
        RECT 0.048 26.304 0.240 26.328 ;
    END
  END di[498]
  PIN di[499]
    DIRECTION INOUT ;
    USE SIGNAL ;
    PORT
      LAYER M4 ;
        RECT 0.048 26.352 0.240 26.376 ;
    END
  END di[499]
  PIN di[500]
    DIRECTION INOUT ;
    USE SIGNAL ;
    PORT
      LAYER M4 ;
        RECT 0.048 26.400 0.240 26.424 ;
    END
  END di[500]
  PIN di[501]
    DIRECTION INOUT ;
    USE SIGNAL ;
    PORT
      LAYER M4 ;
        RECT 0.048 26.448 0.240 26.472 ;
    END
  END di[501]
  PIN di[502]
    DIRECTION INOUT ;
    USE SIGNAL ;
    PORT
      LAYER M4 ;
        RECT 0.048 26.496 0.240 26.520 ;
    END
  END di[502]
  PIN di[503]
    DIRECTION INOUT ;
    USE SIGNAL ;
    PORT
      LAYER M4 ;
        RECT 0.048 26.544 0.240 26.568 ;
    END
  END di[503]
  PIN di[504]
    DIRECTION INOUT ;
    USE SIGNAL ;
    PORT
      LAYER M4 ;
        RECT 0.048 26.592 0.240 26.616 ;
    END
  END di[504]
  PIN di[505]
    DIRECTION INOUT ;
    USE SIGNAL ;
    PORT
      LAYER M4 ;
        RECT 0.048 26.640 0.240 26.664 ;
    END
  END di[505]
  PIN di[506]
    DIRECTION INOUT ;
    USE SIGNAL ;
    PORT
      LAYER M4 ;
        RECT 0.048 26.688 0.240 26.712 ;
    END
  END di[506]
  PIN di[507]
    DIRECTION INOUT ;
    USE SIGNAL ;
    PORT
      LAYER M4 ;
        RECT 0.048 26.736 0.240 26.760 ;
    END
  END di[507]
  PIN di[508]
    DIRECTION INOUT ;
    USE SIGNAL ;
    PORT
      LAYER M4 ;
        RECT 0.048 26.784 0.240 26.808 ;
    END
  END di[508]
  PIN di[509]
    DIRECTION INOUT ;
    USE SIGNAL ;
    PORT
      LAYER M4 ;
        RECT 0.048 26.832 0.240 26.856 ;
    END
  END di[509]
  PIN di[510]
    DIRECTION INOUT ;
    USE SIGNAL ;
    PORT
      LAYER M4 ;
        RECT 0.048 26.880 0.240 26.904 ;
    END
  END di[510]
  PIN di[511]
    DIRECTION INOUT ;
    USE SIGNAL ;
    PORT
      LAYER M4 ;
        RECT 0.048 26.928 0.240 26.952 ;
    END
  END di[511]
  PIN di[512]
    DIRECTION INOUT ;
    USE SIGNAL ;
    PORT
      LAYER M4 ;
        RECT 0.048 26.976 0.240 27.000 ;
    END
  END di[512]
  PIN di[513]
    DIRECTION INOUT ;
    USE SIGNAL ;
    PORT
      LAYER M4 ;
        RECT 0.048 27.024 0.240 27.048 ;
    END
  END di[513]
  PIN di[514]
    DIRECTION INOUT ;
    USE SIGNAL ;
    PORT
      LAYER M4 ;
        RECT 0.048 27.072 0.240 27.096 ;
    END
  END di[514]
  PIN di[515]
    DIRECTION INOUT ;
    USE SIGNAL ;
    PORT
      LAYER M4 ;
        RECT 0.048 27.120 0.240 27.144 ;
    END
  END di[515]
  PIN di[516]
    DIRECTION INOUT ;
    USE SIGNAL ;
    PORT
      LAYER M4 ;
        RECT 0.048 27.168 0.240 27.192 ;
    END
  END di[516]
  PIN di[517]
    DIRECTION INOUT ;
    USE SIGNAL ;
    PORT
      LAYER M4 ;
        RECT 0.048 27.216 0.240 27.240 ;
    END
  END di[517]
  PIN di[518]
    DIRECTION INOUT ;
    USE SIGNAL ;
    PORT
      LAYER M4 ;
        RECT 0.048 27.264 0.240 27.288 ;
    END
  END di[518]
  PIN di[519]
    DIRECTION INOUT ;
    USE SIGNAL ;
    PORT
      LAYER M4 ;
        RECT 0.048 27.312 0.240 27.336 ;
    END
  END di[519]
  PIN di[520]
    DIRECTION INOUT ;
    USE SIGNAL ;
    PORT
      LAYER M4 ;
        RECT 0.048 27.360 0.240 27.384 ;
    END
  END di[520]
  PIN di[521]
    DIRECTION INOUT ;
    USE SIGNAL ;
    PORT
      LAYER M4 ;
        RECT 0.048 27.408 0.240 27.432 ;
    END
  END di[521]
  PIN di[522]
    DIRECTION INOUT ;
    USE SIGNAL ;
    PORT
      LAYER M4 ;
        RECT 0.048 27.456 0.240 27.480 ;
    END
  END di[522]
  PIN di[523]
    DIRECTION INOUT ;
    USE SIGNAL ;
    PORT
      LAYER M4 ;
        RECT 0.048 27.504 0.240 27.528 ;
    END
  END di[523]
  PIN di[524]
    DIRECTION INOUT ;
    USE SIGNAL ;
    PORT
      LAYER M4 ;
        RECT 0.048 27.552 0.240 27.576 ;
    END
  END di[524]
  PIN di[525]
    DIRECTION INOUT ;
    USE SIGNAL ;
    PORT
      LAYER M4 ;
        RECT 0.048 27.600 0.240 27.624 ;
    END
  END di[525]
  PIN di[526]
    DIRECTION INOUT ;
    USE SIGNAL ;
    PORT
      LAYER M4 ;
        RECT 0.048 27.648 0.240 27.672 ;
    END
  END di[526]
  PIN di[527]
    DIRECTION INOUT ;
    USE SIGNAL ;
    PORT
      LAYER M4 ;
        RECT 0.048 27.696 0.240 27.720 ;
    END
  END di[527]
  PIN di[528]
    DIRECTION INOUT ;
    USE SIGNAL ;
    PORT
      LAYER M4 ;
        RECT 0.048 27.744 0.240 27.768 ;
    END
  END di[528]
  PIN di[529]
    DIRECTION INOUT ;
    USE SIGNAL ;
    PORT
      LAYER M4 ;
        RECT 0.048 27.792 0.240 27.816 ;
    END
  END di[529]
  PIN di[530]
    DIRECTION INOUT ;
    USE SIGNAL ;
    PORT
      LAYER M4 ;
        RECT 0.048 27.840 0.240 27.864 ;
    END
  END di[530]
  PIN di[531]
    DIRECTION INOUT ;
    USE SIGNAL ;
    PORT
      LAYER M4 ;
        RECT 0.048 27.888 0.240 27.912 ;
    END
  END di[531]
  PIN di[532]
    DIRECTION INOUT ;
    USE SIGNAL ;
    PORT
      LAYER M4 ;
        RECT 0.048 27.936 0.240 27.960 ;
    END
  END di[532]
  PIN di[533]
    DIRECTION INOUT ;
    USE SIGNAL ;
    PORT
      LAYER M4 ;
        RECT 0.048 27.984 0.240 28.008 ;
    END
  END di[533]
  PIN di[534]
    DIRECTION INOUT ;
    USE SIGNAL ;
    PORT
      LAYER M4 ;
        RECT 0.048 28.032 0.240 28.056 ;
    END
  END di[534]
  PIN di[535]
    DIRECTION INOUT ;
    USE SIGNAL ;
    PORT
      LAYER M4 ;
        RECT 0.048 28.080 0.240 28.104 ;
    END
  END di[535]
  PIN di[536]
    DIRECTION INOUT ;
    USE SIGNAL ;
    PORT
      LAYER M4 ;
        RECT 0.048 28.128 0.240 28.152 ;
    END
  END di[536]
  PIN di[537]
    DIRECTION INOUT ;
    USE SIGNAL ;
    PORT
      LAYER M4 ;
        RECT 0.048 28.176 0.240 28.200 ;
    END
  END di[537]
  PIN di[538]
    DIRECTION INOUT ;
    USE SIGNAL ;
    PORT
      LAYER M4 ;
        RECT 0.048 28.224 0.240 28.248 ;
    END
  END di[538]
  PIN di[539]
    DIRECTION INOUT ;
    USE SIGNAL ;
    PORT
      LAYER M4 ;
        RECT 0.048 28.272 0.240 28.296 ;
    END
  END di[539]
  PIN di[540]
    DIRECTION INOUT ;
    USE SIGNAL ;
    PORT
      LAYER M4 ;
        RECT 0.048 28.320 0.240 28.344 ;
    END
  END di[540]
  PIN di[541]
    DIRECTION INOUT ;
    USE SIGNAL ;
    PORT
      LAYER M4 ;
        RECT 0.048 28.368 0.240 28.392 ;
    END
  END di[541]
  PIN di[542]
    DIRECTION INOUT ;
    USE SIGNAL ;
    PORT
      LAYER M4 ;
        RECT 0.048 28.416 0.240 28.440 ;
    END
  END di[542]
  PIN di[543]
    DIRECTION INOUT ;
    USE SIGNAL ;
    PORT
      LAYER M4 ;
        RECT 0.048 28.464 0.240 28.488 ;
    END
  END di[543]
  PIN di[544]
    DIRECTION INOUT ;
    USE SIGNAL ;
    PORT
      LAYER M4 ;
        RECT 0.048 28.512 0.240 28.536 ;
    END
  END di[544]
  PIN di[545]
    DIRECTION INOUT ;
    USE SIGNAL ;
    PORT
      LAYER M4 ;
        RECT 0.048 28.560 0.240 28.584 ;
    END
  END di[545]
  PIN di[546]
    DIRECTION INOUT ;
    USE SIGNAL ;
    PORT
      LAYER M4 ;
        RECT 0.048 28.608 0.240 28.632 ;
    END
  END di[546]
  PIN di[547]
    DIRECTION INOUT ;
    USE SIGNAL ;
    PORT
      LAYER M4 ;
        RECT 0.048 28.656 0.240 28.680 ;
    END
  END di[547]
  PIN di[548]
    DIRECTION INOUT ;
    USE SIGNAL ;
    PORT
      LAYER M4 ;
        RECT 0.048 28.704 0.240 28.728 ;
    END
  END di[548]
  PIN di[549]
    DIRECTION INOUT ;
    USE SIGNAL ;
    PORT
      LAYER M4 ;
        RECT 0.048 28.752 0.240 28.776 ;
    END
  END di[549]
  PIN di[550]
    DIRECTION INOUT ;
    USE SIGNAL ;
    PORT
      LAYER M4 ;
        RECT 0.048 28.800 0.240 28.824 ;
    END
  END di[550]
  PIN di[551]
    DIRECTION INOUT ;
    USE SIGNAL ;
    PORT
      LAYER M4 ;
        RECT 0.048 28.848 0.240 28.872 ;
    END
  END di[551]
  PIN di[552]
    DIRECTION INOUT ;
    USE SIGNAL ;
    PORT
      LAYER M4 ;
        RECT 0.048 28.896 0.240 28.920 ;
    END
  END di[552]
  PIN di[553]
    DIRECTION INOUT ;
    USE SIGNAL ;
    PORT
      LAYER M4 ;
        RECT 0.048 28.944 0.240 28.968 ;
    END
  END di[553]
  PIN di[554]
    DIRECTION INOUT ;
    USE SIGNAL ;
    PORT
      LAYER M4 ;
        RECT 0.048 28.992 0.240 29.016 ;
    END
  END di[554]
  PIN di[555]
    DIRECTION INOUT ;
    USE SIGNAL ;
    PORT
      LAYER M4 ;
        RECT 0.048 29.040 0.240 29.064 ;
    END
  END di[555]
  PIN di[556]
    DIRECTION INOUT ;
    USE SIGNAL ;
    PORT
      LAYER M4 ;
        RECT 0.048 29.088 0.240 29.112 ;
    END
  END di[556]
  PIN di[557]
    DIRECTION INOUT ;
    USE SIGNAL ;
    PORT
      LAYER M4 ;
        RECT 0.048 29.136 0.240 29.160 ;
    END
  END di[557]
  PIN di[558]
    DIRECTION INOUT ;
    USE SIGNAL ;
    PORT
      LAYER M4 ;
        RECT 0.048 29.184 0.240 29.208 ;
    END
  END di[558]
  PIN di[559]
    DIRECTION INOUT ;
    USE SIGNAL ;
    PORT
      LAYER M4 ;
        RECT 0.048 29.232 0.240 29.256 ;
    END
  END di[559]
  PIN di[560]
    DIRECTION INOUT ;
    USE SIGNAL ;
    PORT
      LAYER M4 ;
        RECT 0.048 29.280 0.240 29.304 ;
    END
  END di[560]
  PIN di[561]
    DIRECTION INOUT ;
    USE SIGNAL ;
    PORT
      LAYER M4 ;
        RECT 0.048 29.328 0.240 29.352 ;
    END
  END di[561]
  PIN di[562]
    DIRECTION INOUT ;
    USE SIGNAL ;
    PORT
      LAYER M4 ;
        RECT 0.048 29.376 0.240 29.400 ;
    END
  END di[562]
  PIN di[563]
    DIRECTION INOUT ;
    USE SIGNAL ;
    PORT
      LAYER M4 ;
        RECT 0.048 29.424 0.240 29.448 ;
    END
  END di[563]
  PIN di[564]
    DIRECTION INOUT ;
    USE SIGNAL ;
    PORT
      LAYER M4 ;
        RECT 0.048 29.472 0.240 29.496 ;
    END
  END di[564]
  PIN di[565]
    DIRECTION INOUT ;
    USE SIGNAL ;
    PORT
      LAYER M4 ;
        RECT 0.048 29.520 0.240 29.544 ;
    END
  END di[565]
  PIN di[566]
    DIRECTION INOUT ;
    USE SIGNAL ;
    PORT
      LAYER M4 ;
        RECT 0.048 29.568 0.240 29.592 ;
    END
  END di[566]
  PIN di[567]
    DIRECTION INOUT ;
    USE SIGNAL ;
    PORT
      LAYER M4 ;
        RECT 0.048 29.616 0.240 29.640 ;
    END
  END di[567]
  PIN di[568]
    DIRECTION INOUT ;
    USE SIGNAL ;
    PORT
      LAYER M4 ;
        RECT 0.048 29.664 0.240 29.688 ;
    END
  END di[568]
  PIN di[569]
    DIRECTION INOUT ;
    USE SIGNAL ;
    PORT
      LAYER M4 ;
        RECT 0.048 29.712 0.240 29.736 ;
    END
  END di[569]
  PIN di[570]
    DIRECTION INOUT ;
    USE SIGNAL ;
    PORT
      LAYER M4 ;
        RECT 0.048 29.760 0.240 29.784 ;
    END
  END di[570]
  PIN di[571]
    DIRECTION INOUT ;
    USE SIGNAL ;
    PORT
      LAYER M4 ;
        RECT 0.048 29.808 0.240 29.832 ;
    END
  END di[571]
  PIN di[572]
    DIRECTION INOUT ;
    USE SIGNAL ;
    PORT
      LAYER M4 ;
        RECT 0.048 29.856 0.240 29.880 ;
    END
  END di[572]
  PIN di[573]
    DIRECTION INOUT ;
    USE SIGNAL ;
    PORT
      LAYER M4 ;
        RECT 0.048 29.904 0.240 29.928 ;
    END
  END di[573]
  PIN di[574]
    DIRECTION INOUT ;
    USE SIGNAL ;
    PORT
      LAYER M4 ;
        RECT 0.048 29.952 0.240 29.976 ;
    END
  END di[574]
  PIN di[575]
    DIRECTION INOUT ;
    USE SIGNAL ;
    PORT
      LAYER M4 ;
        RECT 0.048 30.000 0.240 30.024 ;
    END
  END di[575]
  PIN di[576]
    DIRECTION INOUT ;
    USE SIGNAL ;
    PORT
      LAYER M4 ;
        RECT 0.048 30.048 0.240 30.072 ;
    END
  END di[576]
  PIN di[577]
    DIRECTION INOUT ;
    USE SIGNAL ;
    PORT
      LAYER M4 ;
        RECT 0.048 30.096 0.240 30.120 ;
    END
  END di[577]
  PIN di[578]
    DIRECTION INOUT ;
    USE SIGNAL ;
    PORT
      LAYER M4 ;
        RECT 0.048 30.144 0.240 30.168 ;
    END
  END di[578]
  PIN di[579]
    DIRECTION INOUT ;
    USE SIGNAL ;
    PORT
      LAYER M4 ;
        RECT 0.048 30.192 0.240 30.216 ;
    END
  END di[579]
  PIN di[580]
    DIRECTION INOUT ;
    USE SIGNAL ;
    PORT
      LAYER M4 ;
        RECT 0.048 30.240 0.240 30.264 ;
    END
  END di[580]
  PIN di[581]
    DIRECTION INOUT ;
    USE SIGNAL ;
    PORT
      LAYER M4 ;
        RECT 0.048 30.288 0.240 30.312 ;
    END
  END di[581]
  PIN di[582]
    DIRECTION INOUT ;
    USE SIGNAL ;
    PORT
      LAYER M4 ;
        RECT 0.048 30.336 0.240 30.360 ;
    END
  END di[582]
  PIN di[583]
    DIRECTION INOUT ;
    USE SIGNAL ;
    PORT
      LAYER M4 ;
        RECT 0.048 30.384 0.240 30.408 ;
    END
  END di[583]
  PIN di[584]
    DIRECTION INOUT ;
    USE SIGNAL ;
    PORT
      LAYER M4 ;
        RECT 0.048 30.432 0.240 30.456 ;
    END
  END di[584]
  PIN di[585]
    DIRECTION INOUT ;
    USE SIGNAL ;
    PORT
      LAYER M4 ;
        RECT 0.048 30.480 0.240 30.504 ;
    END
  END di[585]
  PIN di[586]
    DIRECTION INOUT ;
    USE SIGNAL ;
    PORT
      LAYER M4 ;
        RECT 0.048 30.528 0.240 30.552 ;
    END
  END di[586]
  PIN di[587]
    DIRECTION INOUT ;
    USE SIGNAL ;
    PORT
      LAYER M4 ;
        RECT 0.048 30.576 0.240 30.600 ;
    END
  END di[587]
  PIN di[588]
    DIRECTION INOUT ;
    USE SIGNAL ;
    PORT
      LAYER M4 ;
        RECT 0.048 30.624 0.240 30.648 ;
    END
  END di[588]
  PIN di[589]
    DIRECTION INOUT ;
    USE SIGNAL ;
    PORT
      LAYER M4 ;
        RECT 0.048 30.672 0.240 30.696 ;
    END
  END di[589]
  PIN di[590]
    DIRECTION INOUT ;
    USE SIGNAL ;
    PORT
      LAYER M4 ;
        RECT 0.048 30.720 0.240 30.744 ;
    END
  END di[590]
  PIN di[591]
    DIRECTION INOUT ;
    USE SIGNAL ;
    PORT
      LAYER M4 ;
        RECT 0.048 30.768 0.240 30.792 ;
    END
  END di[591]
  PIN di[592]
    DIRECTION INOUT ;
    USE SIGNAL ;
    PORT
      LAYER M4 ;
        RECT 0.048 30.816 0.240 30.840 ;
    END
  END di[592]
  PIN di[593]
    DIRECTION INOUT ;
    USE SIGNAL ;
    PORT
      LAYER M4 ;
        RECT 0.048 30.864 0.240 30.888 ;
    END
  END di[593]
  PIN di[594]
    DIRECTION INOUT ;
    USE SIGNAL ;
    PORT
      LAYER M4 ;
        RECT 0.048 30.912 0.240 30.936 ;
    END
  END di[594]
  PIN di[595]
    DIRECTION INOUT ;
    USE SIGNAL ;
    PORT
      LAYER M4 ;
        RECT 0.048 30.960 0.240 30.984 ;
    END
  END di[595]
  PIN di[596]
    DIRECTION INOUT ;
    USE SIGNAL ;
    PORT
      LAYER M4 ;
        RECT 0.048 31.008 0.240 31.032 ;
    END
  END di[596]
  PIN di[597]
    DIRECTION INOUT ;
    USE SIGNAL ;
    PORT
      LAYER M4 ;
        RECT 0.048 31.056 0.240 31.080 ;
    END
  END di[597]
  PIN di[598]
    DIRECTION INOUT ;
    USE SIGNAL ;
    PORT
      LAYER M4 ;
        RECT 0.048 31.104 0.240 31.128 ;
    END
  END di[598]
  PIN di[599]
    DIRECTION INOUT ;
    USE SIGNAL ;
    PORT
      LAYER M4 ;
        RECT 0.048 31.152 0.240 31.176 ;
    END
  END di[599]
  PIN di[600]
    DIRECTION INOUT ;
    USE SIGNAL ;
    PORT
      LAYER M4 ;
        RECT 0.048 31.200 0.240 31.224 ;
    END
  END di[600]
  PIN di[601]
    DIRECTION INOUT ;
    USE SIGNAL ;
    PORT
      LAYER M4 ;
        RECT 0.048 31.248 0.240 31.272 ;
    END
  END di[601]
  PIN di[602]
    DIRECTION INOUT ;
    USE SIGNAL ;
    PORT
      LAYER M4 ;
        RECT 0.048 31.296 0.240 31.320 ;
    END
  END di[602]
  PIN di[603]
    DIRECTION INOUT ;
    USE SIGNAL ;
    PORT
      LAYER M4 ;
        RECT 0.048 31.344 0.240 31.368 ;
    END
  END di[603]
  PIN di[604]
    DIRECTION INOUT ;
    USE SIGNAL ;
    PORT
      LAYER M4 ;
        RECT 0.048 31.392 0.240 31.416 ;
    END
  END di[604]
  PIN di[605]
    DIRECTION INOUT ;
    USE SIGNAL ;
    PORT
      LAYER M4 ;
        RECT 0.048 31.440 0.240 31.464 ;
    END
  END di[605]
  PIN di[606]
    DIRECTION INOUT ;
    USE SIGNAL ;
    PORT
      LAYER M4 ;
        RECT 0.048 31.488 0.240 31.512 ;
    END
  END di[606]
  PIN di[607]
    DIRECTION INOUT ;
    USE SIGNAL ;
    PORT
      LAYER M4 ;
        RECT 0.048 31.536 0.240 31.560 ;
    END
  END di[607]
  PIN di[608]
    DIRECTION INOUT ;
    USE SIGNAL ;
    PORT
      LAYER M4 ;
        RECT 0.048 31.584 0.240 31.608 ;
    END
  END di[608]
  PIN di[609]
    DIRECTION INOUT ;
    USE SIGNAL ;
    PORT
      LAYER M4 ;
        RECT 0.048 31.632 0.240 31.656 ;
    END
  END di[609]
  PIN di[610]
    DIRECTION INOUT ;
    USE SIGNAL ;
    PORT
      LAYER M4 ;
        RECT 0.048 31.680 0.240 31.704 ;
    END
  END di[610]
  PIN di[611]
    DIRECTION INOUT ;
    USE SIGNAL ;
    PORT
      LAYER M4 ;
        RECT 0.048 31.728 0.240 31.752 ;
    END
  END di[611]
  PIN di[612]
    DIRECTION INOUT ;
    USE SIGNAL ;
    PORT
      LAYER M4 ;
        RECT 0.048 31.776 0.240 31.800 ;
    END
  END di[612]
  PIN di[613]
    DIRECTION INOUT ;
    USE SIGNAL ;
    PORT
      LAYER M4 ;
        RECT 0.048 31.824 0.240 31.848 ;
    END
  END di[613]
  PIN di[614]
    DIRECTION INOUT ;
    USE SIGNAL ;
    PORT
      LAYER M4 ;
        RECT 0.048 31.872 0.240 31.896 ;
    END
  END di[614]
  PIN di[615]
    DIRECTION INOUT ;
    USE SIGNAL ;
    PORT
      LAYER M4 ;
        RECT 0.048 31.920 0.240 31.944 ;
    END
  END di[615]
  PIN di[616]
    DIRECTION INOUT ;
    USE SIGNAL ;
    PORT
      LAYER M4 ;
        RECT 0.048 31.968 0.240 31.992 ;
    END
  END di[616]
  PIN di[617]
    DIRECTION INOUT ;
    USE SIGNAL ;
    PORT
      LAYER M4 ;
        RECT 0.048 32.016 0.240 32.040 ;
    END
  END di[617]
  PIN di[618]
    DIRECTION INOUT ;
    USE SIGNAL ;
    PORT
      LAYER M4 ;
        RECT 0.048 32.064 0.240 32.088 ;
    END
  END di[618]
  PIN di[619]
    DIRECTION INOUT ;
    USE SIGNAL ;
    PORT
      LAYER M4 ;
        RECT 0.048 32.112 0.240 32.136 ;
    END
  END di[619]
  PIN di[620]
    DIRECTION INOUT ;
    USE SIGNAL ;
    PORT
      LAYER M4 ;
        RECT 0.048 32.160 0.240 32.184 ;
    END
  END di[620]
  PIN di[621]
    DIRECTION INOUT ;
    USE SIGNAL ;
    PORT
      LAYER M4 ;
        RECT 0.048 32.208 0.240 32.232 ;
    END
  END di[621]
  PIN di[622]
    DIRECTION INOUT ;
    USE SIGNAL ;
    PORT
      LAYER M4 ;
        RECT 0.048 32.256 0.240 32.280 ;
    END
  END di[622]
  PIN di[623]
    DIRECTION INOUT ;
    USE SIGNAL ;
    PORT
      LAYER M4 ;
        RECT 0.048 32.304 0.240 32.328 ;
    END
  END di[623]
  PIN di[624]
    DIRECTION INOUT ;
    USE SIGNAL ;
    PORT
      LAYER M4 ;
        RECT 0.048 32.352 0.240 32.376 ;
    END
  END di[624]
  PIN di[625]
    DIRECTION INOUT ;
    USE SIGNAL ;
    PORT
      LAYER M4 ;
        RECT 0.048 32.400 0.240 32.424 ;
    END
  END di[625]
  PIN di[626]
    DIRECTION INOUT ;
    USE SIGNAL ;
    PORT
      LAYER M4 ;
        RECT 0.048 32.448 0.240 32.472 ;
    END
  END di[626]
  PIN di[627]
    DIRECTION INOUT ;
    USE SIGNAL ;
    PORT
      LAYER M4 ;
        RECT 0.048 32.496 0.240 32.520 ;
    END
  END di[627]
  PIN di[628]
    DIRECTION INOUT ;
    USE SIGNAL ;
    PORT
      LAYER M4 ;
        RECT 0.048 32.544 0.240 32.568 ;
    END
  END di[628]
  PIN di[629]
    DIRECTION INOUT ;
    USE SIGNAL ;
    PORT
      LAYER M4 ;
        RECT 0.048 32.592 0.240 32.616 ;
    END
  END di[629]
  PIN di[630]
    DIRECTION INOUT ;
    USE SIGNAL ;
    PORT
      LAYER M4 ;
        RECT 0.048 32.640 0.240 32.664 ;
    END
  END di[630]
  PIN di[631]
    DIRECTION INOUT ;
    USE SIGNAL ;
    PORT
      LAYER M4 ;
        RECT 0.048 32.688 0.240 32.712 ;
    END
  END di[631]
  PIN di[632]
    DIRECTION INOUT ;
    USE SIGNAL ;
    PORT
      LAYER M4 ;
        RECT 0.048 32.736 0.240 32.760 ;
    END
  END di[632]
  PIN di[633]
    DIRECTION INOUT ;
    USE SIGNAL ;
    PORT
      LAYER M4 ;
        RECT 0.048 32.784 0.240 32.808 ;
    END
  END di[633]
  PIN di[634]
    DIRECTION INOUT ;
    USE SIGNAL ;
    PORT
      LAYER M4 ;
        RECT 0.048 32.832 0.240 32.856 ;
    END
  END di[634]
  PIN di[635]
    DIRECTION INOUT ;
    USE SIGNAL ;
    PORT
      LAYER M4 ;
        RECT 0.048 32.880 0.240 32.904 ;
    END
  END di[635]
  PIN di[636]
    DIRECTION INOUT ;
    USE SIGNAL ;
    PORT
      LAYER M4 ;
        RECT 0.048 32.928 0.240 32.952 ;
    END
  END di[636]
  PIN di[637]
    DIRECTION INOUT ;
    USE SIGNAL ;
    PORT
      LAYER M4 ;
        RECT 0.048 32.976 0.240 33.000 ;
    END
  END di[637]
  PIN di[638]
    DIRECTION INOUT ;
    USE SIGNAL ;
    PORT
      LAYER M4 ;
        RECT 0.048 33.024 0.240 33.048 ;
    END
  END di[638]
  PIN di[639]
    DIRECTION INOUT ;
    USE SIGNAL ;
    PORT
      LAYER M4 ;
        RECT 0.048 33.072 0.240 33.096 ;
    END
  END di[639]
  PIN di[640]
    DIRECTION INOUT ;
    USE SIGNAL ;
    PORT
      LAYER M4 ;
        RECT 0.048 33.120 0.240 33.144 ;
    END
  END di[640]
  PIN di[641]
    DIRECTION INOUT ;
    USE SIGNAL ;
    PORT
      LAYER M4 ;
        RECT 0.048 33.168 0.240 33.192 ;
    END
  END di[641]
  PIN di[642]
    DIRECTION INOUT ;
    USE SIGNAL ;
    PORT
      LAYER M4 ;
        RECT 0.048 33.216 0.240 33.240 ;
    END
  END di[642]
  PIN di[643]
    DIRECTION INOUT ;
    USE SIGNAL ;
    PORT
      LAYER M4 ;
        RECT 0.048 33.264 0.240 33.288 ;
    END
  END di[643]
  PIN di[644]
    DIRECTION INOUT ;
    USE SIGNAL ;
    PORT
      LAYER M4 ;
        RECT 0.048 33.312 0.240 33.336 ;
    END
  END di[644]
  PIN di[645]
    DIRECTION INOUT ;
    USE SIGNAL ;
    PORT
      LAYER M4 ;
        RECT 0.048 33.360 0.240 33.384 ;
    END
  END di[645]
  PIN di[646]
    DIRECTION INOUT ;
    USE SIGNAL ;
    PORT
      LAYER M4 ;
        RECT 0.048 33.408 0.240 33.432 ;
    END
  END di[646]
  PIN di[647]
    DIRECTION INOUT ;
    USE SIGNAL ;
    PORT
      LAYER M4 ;
        RECT 0.048 33.456 0.240 33.480 ;
    END
  END di[647]
  PIN di[648]
    DIRECTION INOUT ;
    USE SIGNAL ;
    PORT
      LAYER M4 ;
        RECT 0.048 33.504 0.240 33.528 ;
    END
  END di[648]
  PIN di[649]
    DIRECTION INOUT ;
    USE SIGNAL ;
    PORT
      LAYER M4 ;
        RECT 0.048 33.552 0.240 33.576 ;
    END
  END di[649]
  PIN di[650]
    DIRECTION INOUT ;
    USE SIGNAL ;
    PORT
      LAYER M4 ;
        RECT 0.048 33.600 0.240 33.624 ;
    END
  END di[650]
  PIN di[651]
    DIRECTION INOUT ;
    USE SIGNAL ;
    PORT
      LAYER M4 ;
        RECT 0.048 33.648 0.240 33.672 ;
    END
  END di[651]
  PIN di[652]
    DIRECTION INOUT ;
    USE SIGNAL ;
    PORT
      LAYER M4 ;
        RECT 0.048 33.696 0.240 33.720 ;
    END
  END di[652]
  PIN di[653]
    DIRECTION INOUT ;
    USE SIGNAL ;
    PORT
      LAYER M4 ;
        RECT 0.048 33.744 0.240 33.768 ;
    END
  END di[653]
  PIN di[654]
    DIRECTION INOUT ;
    USE SIGNAL ;
    PORT
      LAYER M4 ;
        RECT 0.048 33.792 0.240 33.816 ;
    END
  END di[654]
  PIN di[655]
    DIRECTION INOUT ;
    USE SIGNAL ;
    PORT
      LAYER M4 ;
        RECT 0.048 33.840 0.240 33.864 ;
    END
  END di[655]
  PIN di[656]
    DIRECTION INOUT ;
    USE SIGNAL ;
    PORT
      LAYER M4 ;
        RECT 0.048 33.888 0.240 33.912 ;
    END
  END di[656]
  PIN di[657]
    DIRECTION INOUT ;
    USE SIGNAL ;
    PORT
      LAYER M4 ;
        RECT 0.048 33.936 0.240 33.960 ;
    END
  END di[657]
  PIN di[658]
    DIRECTION INOUT ;
    USE SIGNAL ;
    PORT
      LAYER M4 ;
        RECT 0.048 33.984 0.240 34.008 ;
    END
  END di[658]
  PIN di[659]
    DIRECTION INOUT ;
    USE SIGNAL ;
    PORT
      LAYER M4 ;
        RECT 0.048 34.032 0.240 34.056 ;
    END
  END di[659]
  PIN di[660]
    DIRECTION INOUT ;
    USE SIGNAL ;
    PORT
      LAYER M4 ;
        RECT 0.048 34.080 0.240 34.104 ;
    END
  END di[660]
  PIN di[661]
    DIRECTION INOUT ;
    USE SIGNAL ;
    PORT
      LAYER M4 ;
        RECT 0.048 34.128 0.240 34.152 ;
    END
  END di[661]
  PIN di[662]
    DIRECTION INOUT ;
    USE SIGNAL ;
    PORT
      LAYER M4 ;
        RECT 0.048 34.176 0.240 34.200 ;
    END
  END di[662]
  PIN di[663]
    DIRECTION INOUT ;
    USE SIGNAL ;
    PORT
      LAYER M4 ;
        RECT 0.048 34.224 0.240 34.248 ;
    END
  END di[663]
  PIN di[664]
    DIRECTION INOUT ;
    USE SIGNAL ;
    PORT
      LAYER M4 ;
        RECT 0.048 34.272 0.240 34.296 ;
    END
  END di[664]
  PIN di[665]
    DIRECTION INOUT ;
    USE SIGNAL ;
    PORT
      LAYER M4 ;
        RECT 0.048 34.320 0.240 34.344 ;
    END
  END di[665]
  PIN di[666]
    DIRECTION INOUT ;
    USE SIGNAL ;
    PORT
      LAYER M4 ;
        RECT 0.048 34.368 0.240 34.392 ;
    END
  END di[666]
  PIN di[667]
    DIRECTION INOUT ;
    USE SIGNAL ;
    PORT
      LAYER M4 ;
        RECT 0.048 34.416 0.240 34.440 ;
    END
  END di[667]
  PIN di[668]
    DIRECTION INOUT ;
    USE SIGNAL ;
    PORT
      LAYER M4 ;
        RECT 0.048 34.464 0.240 34.488 ;
    END
  END di[668]
  PIN di[669]
    DIRECTION INOUT ;
    USE SIGNAL ;
    PORT
      LAYER M4 ;
        RECT 0.048 34.512 0.240 34.536 ;
    END
  END di[669]
  PIN di[670]
    DIRECTION INOUT ;
    USE SIGNAL ;
    PORT
      LAYER M4 ;
        RECT 0.048 34.560 0.240 34.584 ;
    END
  END di[670]
  PIN di[671]
    DIRECTION INOUT ;
    USE SIGNAL ;
    PORT
      LAYER M4 ;
        RECT 0.048 34.608 0.240 34.632 ;
    END
  END di[671]
  PIN di[672]
    DIRECTION INOUT ;
    USE SIGNAL ;
    PORT
      LAYER M4 ;
        RECT 0.048 34.656 0.240 34.680 ;
    END
  END di[672]
  PIN di[673]
    DIRECTION INOUT ;
    USE SIGNAL ;
    PORT
      LAYER M4 ;
        RECT 0.048 34.704 0.240 34.728 ;
    END
  END di[673]
  PIN di[674]
    DIRECTION INOUT ;
    USE SIGNAL ;
    PORT
      LAYER M4 ;
        RECT 0.048 34.752 0.240 34.776 ;
    END
  END di[674]
  PIN di[675]
    DIRECTION INOUT ;
    USE SIGNAL ;
    PORT
      LAYER M4 ;
        RECT 0.048 34.800 0.240 34.824 ;
    END
  END di[675]
  PIN di[676]
    DIRECTION INOUT ;
    USE SIGNAL ;
    PORT
      LAYER M4 ;
        RECT 0.048 34.848 0.240 34.872 ;
    END
  END di[676]
  PIN di[677]
    DIRECTION INOUT ;
    USE SIGNAL ;
    PORT
      LAYER M4 ;
        RECT 0.048 34.896 0.240 34.920 ;
    END
  END di[677]
  PIN di[678]
    DIRECTION INOUT ;
    USE SIGNAL ;
    PORT
      LAYER M4 ;
        RECT 0.048 34.944 0.240 34.968 ;
    END
  END di[678]
  PIN di[679]
    DIRECTION INOUT ;
    USE SIGNAL ;
    PORT
      LAYER M4 ;
        RECT 0.048 34.992 0.240 35.016 ;
    END
  END di[679]
  PIN di[680]
    DIRECTION INOUT ;
    USE SIGNAL ;
    PORT
      LAYER M4 ;
        RECT 0.048 35.040 0.240 35.064 ;
    END
  END di[680]
  PIN di[681]
    DIRECTION INOUT ;
    USE SIGNAL ;
    PORT
      LAYER M4 ;
        RECT 0.048 35.088 0.240 35.112 ;
    END
  END di[681]
  PIN di[682]
    DIRECTION INOUT ;
    USE SIGNAL ;
    PORT
      LAYER M4 ;
        RECT 0.048 35.136 0.240 35.160 ;
    END
  END di[682]
  PIN di[683]
    DIRECTION INOUT ;
    USE SIGNAL ;
    PORT
      LAYER M4 ;
        RECT 0.048 35.184 0.240 35.208 ;
    END
  END di[683]
  PIN di[684]
    DIRECTION INOUT ;
    USE SIGNAL ;
    PORT
      LAYER M4 ;
        RECT 0.048 35.232 0.240 35.256 ;
    END
  END di[684]
  PIN di[685]
    DIRECTION INOUT ;
    USE SIGNAL ;
    PORT
      LAYER M4 ;
        RECT 0.048 35.280 0.240 35.304 ;
    END
  END di[685]
  PIN di[686]
    DIRECTION INOUT ;
    USE SIGNAL ;
    PORT
      LAYER M4 ;
        RECT 0.048 35.328 0.240 35.352 ;
    END
  END di[686]
  PIN di[687]
    DIRECTION INOUT ;
    USE SIGNAL ;
    PORT
      LAYER M4 ;
        RECT 0.048 35.376 0.240 35.400 ;
    END
  END di[687]
  PIN di[688]
    DIRECTION INOUT ;
    USE SIGNAL ;
    PORT
      LAYER M4 ;
        RECT 0.048 35.424 0.240 35.448 ;
    END
  END di[688]
  PIN di[689]
    DIRECTION INOUT ;
    USE SIGNAL ;
    PORT
      LAYER M4 ;
        RECT 0.048 35.472 0.240 35.496 ;
    END
  END di[689]
  PIN di[690]
    DIRECTION INOUT ;
    USE SIGNAL ;
    PORT
      LAYER M4 ;
        RECT 0.048 35.520 0.240 35.544 ;
    END
  END di[690]
  PIN di[691]
    DIRECTION INOUT ;
    USE SIGNAL ;
    PORT
      LAYER M4 ;
        RECT 0.048 35.568 0.240 35.592 ;
    END
  END di[691]
  PIN di[692]
    DIRECTION INOUT ;
    USE SIGNAL ;
    PORT
      LAYER M4 ;
        RECT 0.048 35.616 0.240 35.640 ;
    END
  END di[692]
  PIN di[693]
    DIRECTION INOUT ;
    USE SIGNAL ;
    PORT
      LAYER M4 ;
        RECT 0.048 35.664 0.240 35.688 ;
    END
  END di[693]
  PIN di[694]
    DIRECTION INOUT ;
    USE SIGNAL ;
    PORT
      LAYER M4 ;
        RECT 0.048 35.712 0.240 35.736 ;
    END
  END di[694]
  PIN di[695]
    DIRECTION INOUT ;
    USE SIGNAL ;
    PORT
      LAYER M4 ;
        RECT 0.048 35.760 0.240 35.784 ;
    END
  END di[695]
  PIN di[696]
    DIRECTION INOUT ;
    USE SIGNAL ;
    PORT
      LAYER M4 ;
        RECT 0.048 35.808 0.240 35.832 ;
    END
  END di[696]
  PIN di[697]
    DIRECTION INOUT ;
    USE SIGNAL ;
    PORT
      LAYER M4 ;
        RECT 0.048 35.856 0.240 35.880 ;
    END
  END di[697]
  PIN di[698]
    DIRECTION INOUT ;
    USE SIGNAL ;
    PORT
      LAYER M4 ;
        RECT 0.048 35.904 0.240 35.928 ;
    END
  END di[698]
  PIN di[699]
    DIRECTION INOUT ;
    USE SIGNAL ;
    PORT
      LAYER M4 ;
        RECT 0.048 35.952 0.240 35.976 ;
    END
  END di[699]
  PIN di[700]
    DIRECTION INOUT ;
    USE SIGNAL ;
    PORT
      LAYER M4 ;
        RECT 0.048 36.000 0.240 36.024 ;
    END
  END di[700]
  PIN di[701]
    DIRECTION INOUT ;
    USE SIGNAL ;
    PORT
      LAYER M4 ;
        RECT 0.048 36.048 0.240 36.072 ;
    END
  END di[701]
  PIN di[702]
    DIRECTION INOUT ;
    USE SIGNAL ;
    PORT
      LAYER M4 ;
        RECT 0.048 36.096 0.240 36.120 ;
    END
  END di[702]
  PIN di[703]
    DIRECTION INOUT ;
    USE SIGNAL ;
    PORT
      LAYER M4 ;
        RECT 0.048 36.144 0.240 36.168 ;
    END
  END di[703]
  PIN di[704]
    DIRECTION INOUT ;
    USE SIGNAL ;
    PORT
      LAYER M4 ;
        RECT 0.048 36.192 0.240 36.216 ;
    END
  END di[704]
  PIN di[705]
    DIRECTION INOUT ;
    USE SIGNAL ;
    PORT
      LAYER M4 ;
        RECT 0.048 36.240 0.240 36.264 ;
    END
  END di[705]
  PIN di[706]
    DIRECTION INOUT ;
    USE SIGNAL ;
    PORT
      LAYER M4 ;
        RECT 0.048 36.288 0.240 36.312 ;
    END
  END di[706]
  PIN di[707]
    DIRECTION INOUT ;
    USE SIGNAL ;
    PORT
      LAYER M4 ;
        RECT 0.048 36.336 0.240 36.360 ;
    END
  END di[707]
  PIN di[708]
    DIRECTION INOUT ;
    USE SIGNAL ;
    PORT
      LAYER M4 ;
        RECT 0.048 36.384 0.240 36.408 ;
    END
  END di[708]
  PIN di[709]
    DIRECTION INOUT ;
    USE SIGNAL ;
    PORT
      LAYER M4 ;
        RECT 0.048 36.432 0.240 36.456 ;
    END
  END di[709]
  PIN di[710]
    DIRECTION INOUT ;
    USE SIGNAL ;
    PORT
      LAYER M4 ;
        RECT 0.048 36.480 0.240 36.504 ;
    END
  END di[710]
  PIN di[711]
    DIRECTION INOUT ;
    USE SIGNAL ;
    PORT
      LAYER M4 ;
        RECT 0.048 36.528 0.240 36.552 ;
    END
  END di[711]
  PIN di[712]
    DIRECTION INOUT ;
    USE SIGNAL ;
    PORT
      LAYER M4 ;
        RECT 0.048 36.576 0.240 36.600 ;
    END
  END di[712]
  PIN di[713]
    DIRECTION INOUT ;
    USE SIGNAL ;
    PORT
      LAYER M4 ;
        RECT 0.048 36.624 0.240 36.648 ;
    END
  END di[713]
  PIN di[714]
    DIRECTION INOUT ;
    USE SIGNAL ;
    PORT
      LAYER M4 ;
        RECT 0.048 36.672 0.240 36.696 ;
    END
  END di[714]
  PIN di[715]
    DIRECTION INOUT ;
    USE SIGNAL ;
    PORT
      LAYER M4 ;
        RECT 0.048 36.720 0.240 36.744 ;
    END
  END di[715]
  PIN di[716]
    DIRECTION INOUT ;
    USE SIGNAL ;
    PORT
      LAYER M4 ;
        RECT 0.048 36.768 0.240 36.792 ;
    END
  END di[716]
  PIN di[717]
    DIRECTION INOUT ;
    USE SIGNAL ;
    PORT
      LAYER M4 ;
        RECT 0.048 36.816 0.240 36.840 ;
    END
  END di[717]
  PIN di[718]
    DIRECTION INOUT ;
    USE SIGNAL ;
    PORT
      LAYER M4 ;
        RECT 0.048 36.864 0.240 36.888 ;
    END
  END di[718]
  PIN di[719]
    DIRECTION INOUT ;
    USE SIGNAL ;
    PORT
      LAYER M4 ;
        RECT 0.048 36.912 0.240 36.936 ;
    END
  END di[719]
  PIN di[720]
    DIRECTION INOUT ;
    USE SIGNAL ;
    PORT
      LAYER M4 ;
        RECT 0.048 36.960 0.240 36.984 ;
    END
  END di[720]
  PIN di[721]
    DIRECTION INOUT ;
    USE SIGNAL ;
    PORT
      LAYER M4 ;
        RECT 0.048 37.008 0.240 37.032 ;
    END
  END di[721]
  PIN di[722]
    DIRECTION INOUT ;
    USE SIGNAL ;
    PORT
      LAYER M4 ;
        RECT 0.048 37.056 0.240 37.080 ;
    END
  END di[722]
  PIN di[723]
    DIRECTION INOUT ;
    USE SIGNAL ;
    PORT
      LAYER M4 ;
        RECT 0.048 37.104 0.240 37.128 ;
    END
  END di[723]
  PIN di[724]
    DIRECTION INOUT ;
    USE SIGNAL ;
    PORT
      LAYER M4 ;
        RECT 0.048 37.152 0.240 37.176 ;
    END
  END di[724]
  PIN di[725]
    DIRECTION INOUT ;
    USE SIGNAL ;
    PORT
      LAYER M4 ;
        RECT 0.048 37.200 0.240 37.224 ;
    END
  END di[725]
  PIN di[726]
    DIRECTION INOUT ;
    USE SIGNAL ;
    PORT
      LAYER M4 ;
        RECT 0.048 37.248 0.240 37.272 ;
    END
  END di[726]
  PIN di[727]
    DIRECTION INOUT ;
    USE SIGNAL ;
    PORT
      LAYER M4 ;
        RECT 0.048 37.296 0.240 37.320 ;
    END
  END di[727]
  PIN di[728]
    DIRECTION INOUT ;
    USE SIGNAL ;
    PORT
      LAYER M4 ;
        RECT 0.048 37.344 0.240 37.368 ;
    END
  END di[728]
  PIN di[729]
    DIRECTION INOUT ;
    USE SIGNAL ;
    PORT
      LAYER M4 ;
        RECT 0.048 37.392 0.240 37.416 ;
    END
  END di[729]
  PIN di[730]
    DIRECTION INOUT ;
    USE SIGNAL ;
    PORT
      LAYER M4 ;
        RECT 0.048 37.440 0.240 37.464 ;
    END
  END di[730]
  PIN di[731]
    DIRECTION INOUT ;
    USE SIGNAL ;
    PORT
      LAYER M4 ;
        RECT 0.048 37.488 0.240 37.512 ;
    END
  END di[731]
  PIN di[732]
    DIRECTION INOUT ;
    USE SIGNAL ;
    PORT
      LAYER M4 ;
        RECT 0.048 37.536 0.240 37.560 ;
    END
  END di[732]
  PIN di[733]
    DIRECTION INOUT ;
    USE SIGNAL ;
    PORT
      LAYER M4 ;
        RECT 0.048 37.584 0.240 37.608 ;
    END
  END di[733]
  PIN di[734]
    DIRECTION INOUT ;
    USE SIGNAL ;
    PORT
      LAYER M4 ;
        RECT 0.048 37.632 0.240 37.656 ;
    END
  END di[734]
  PIN di[735]
    DIRECTION INOUT ;
    USE SIGNAL ;
    PORT
      LAYER M4 ;
        RECT 0.048 37.680 0.240 37.704 ;
    END
  END di[735]
  PIN di[736]
    DIRECTION INOUT ;
    USE SIGNAL ;
    PORT
      LAYER M4 ;
        RECT 0.048 37.728 0.240 37.752 ;
    END
  END di[736]
  PIN di[737]
    DIRECTION INOUT ;
    USE SIGNAL ;
    PORT
      LAYER M4 ;
        RECT 0.048 37.776 0.240 37.800 ;
    END
  END di[737]
  PIN di[738]
    DIRECTION INOUT ;
    USE SIGNAL ;
    PORT
      LAYER M4 ;
        RECT 0.048 37.824 0.240 37.848 ;
    END
  END di[738]
  PIN di[739]
    DIRECTION INOUT ;
    USE SIGNAL ;
    PORT
      LAYER M4 ;
        RECT 0.048 37.872 0.240 37.896 ;
    END
  END di[739]
  PIN di[740]
    DIRECTION INOUT ;
    USE SIGNAL ;
    PORT
      LAYER M4 ;
        RECT 0.048 37.920 0.240 37.944 ;
    END
  END di[740]
  PIN di[741]
    DIRECTION INOUT ;
    USE SIGNAL ;
    PORT
      LAYER M4 ;
        RECT 0.048 37.968 0.240 37.992 ;
    END
  END di[741]
  PIN di[742]
    DIRECTION INOUT ;
    USE SIGNAL ;
    PORT
      LAYER M4 ;
        RECT 0.048 38.016 0.240 38.040 ;
    END
  END di[742]
  PIN di[743]
    DIRECTION INOUT ;
    USE SIGNAL ;
    PORT
      LAYER M4 ;
        RECT 0.048 38.064 0.240 38.088 ;
    END
  END di[743]
  PIN di[744]
    DIRECTION INOUT ;
    USE SIGNAL ;
    PORT
      LAYER M4 ;
        RECT 0.048 38.112 0.240 38.136 ;
    END
  END di[744]
  PIN di[745]
    DIRECTION INOUT ;
    USE SIGNAL ;
    PORT
      LAYER M4 ;
        RECT 0.048 38.160 0.240 38.184 ;
    END
  END di[745]
  PIN di[746]
    DIRECTION INOUT ;
    USE SIGNAL ;
    PORT
      LAYER M4 ;
        RECT 0.048 38.208 0.240 38.232 ;
    END
  END di[746]
  PIN di[747]
    DIRECTION INOUT ;
    USE SIGNAL ;
    PORT
      LAYER M4 ;
        RECT 0.048 38.256 0.240 38.280 ;
    END
  END di[747]
  PIN di[748]
    DIRECTION INOUT ;
    USE SIGNAL ;
    PORT
      LAYER M4 ;
        RECT 0.048 38.304 0.240 38.328 ;
    END
  END di[748]
  PIN di[749]
    DIRECTION INOUT ;
    USE SIGNAL ;
    PORT
      LAYER M4 ;
        RECT 0.048 38.352 0.240 38.376 ;
    END
  END di[749]
  PIN di[750]
    DIRECTION INOUT ;
    USE SIGNAL ;
    PORT
      LAYER M4 ;
        RECT 0.048 38.400 0.240 38.424 ;
    END
  END di[750]
  PIN di[751]
    DIRECTION INOUT ;
    USE SIGNAL ;
    PORT
      LAYER M4 ;
        RECT 0.048 38.448 0.240 38.472 ;
    END
  END di[751]
  PIN di[752]
    DIRECTION INOUT ;
    USE SIGNAL ;
    PORT
      LAYER M4 ;
        RECT 0.048 38.496 0.240 38.520 ;
    END
  END di[752]
  PIN di[753]
    DIRECTION INOUT ;
    USE SIGNAL ;
    PORT
      LAYER M4 ;
        RECT 0.048 38.544 0.240 38.568 ;
    END
  END di[753]
  PIN di[754]
    DIRECTION INOUT ;
    USE SIGNAL ;
    PORT
      LAYER M4 ;
        RECT 0.048 38.592 0.240 38.616 ;
    END
  END di[754]
  PIN di[755]
    DIRECTION INOUT ;
    USE SIGNAL ;
    PORT
      LAYER M4 ;
        RECT 0.048 38.640 0.240 38.664 ;
    END
  END di[755]
  PIN di[756]
    DIRECTION INOUT ;
    USE SIGNAL ;
    PORT
      LAYER M4 ;
        RECT 0.048 38.688 0.240 38.712 ;
    END
  END di[756]
  PIN di[757]
    DIRECTION INOUT ;
    USE SIGNAL ;
    PORT
      LAYER M4 ;
        RECT 0.048 38.736 0.240 38.760 ;
    END
  END di[757]
  PIN di[758]
    DIRECTION INOUT ;
    USE SIGNAL ;
    PORT
      LAYER M4 ;
        RECT 0.048 38.784 0.240 38.808 ;
    END
  END di[758]
  PIN di[759]
    DIRECTION INOUT ;
    USE SIGNAL ;
    PORT
      LAYER M4 ;
        RECT 0.048 38.832 0.240 38.856 ;
    END
  END di[759]
  PIN di[760]
    DIRECTION INOUT ;
    USE SIGNAL ;
    PORT
      LAYER M4 ;
        RECT 0.048 38.880 0.240 38.904 ;
    END
  END di[760]
  PIN di[761]
    DIRECTION INOUT ;
    USE SIGNAL ;
    PORT
      LAYER M4 ;
        RECT 0.048 38.928 0.240 38.952 ;
    END
  END di[761]
  PIN di[762]
    DIRECTION INOUT ;
    USE SIGNAL ;
    PORT
      LAYER M4 ;
        RECT 0.048 38.976 0.240 39.000 ;
    END
  END di[762]
  PIN di[763]
    DIRECTION INOUT ;
    USE SIGNAL ;
    PORT
      LAYER M4 ;
        RECT 0.048 39.024 0.240 39.048 ;
    END
  END di[763]
  PIN di[764]
    DIRECTION INOUT ;
    USE SIGNAL ;
    PORT
      LAYER M4 ;
        RECT 0.048 39.072 0.240 39.096 ;
    END
  END di[764]
  PIN di[765]
    DIRECTION INOUT ;
    USE SIGNAL ;
    PORT
      LAYER M4 ;
        RECT 0.048 39.120 0.240 39.144 ;
    END
  END di[765]
  PIN di[766]
    DIRECTION INOUT ;
    USE SIGNAL ;
    PORT
      LAYER M4 ;
        RECT 0.048 39.168 0.240 39.192 ;
    END
  END di[766]
  PIN di[767]
    DIRECTION INOUT ;
    USE SIGNAL ;
    PORT
      LAYER M4 ;
        RECT 0.048 39.216 0.240 39.240 ;
    END
  END di[767]
  PIN di[768]
    DIRECTION INOUT ;
    USE SIGNAL ;
    PORT
      LAYER M4 ;
        RECT 0.048 39.264 0.240 39.288 ;
    END
  END di[768]
  PIN di[769]
    DIRECTION INOUT ;
    USE SIGNAL ;
    PORT
      LAYER M4 ;
        RECT 0.048 39.312 0.240 39.336 ;
    END
  END di[769]
  PIN di[770]
    DIRECTION INOUT ;
    USE SIGNAL ;
    PORT
      LAYER M4 ;
        RECT 0.048 39.360 0.240 39.384 ;
    END
  END di[770]
  PIN di[771]
    DIRECTION INOUT ;
    USE SIGNAL ;
    PORT
      LAYER M4 ;
        RECT 0.048 39.408 0.240 39.432 ;
    END
  END di[771]
  PIN di[772]
    DIRECTION INOUT ;
    USE SIGNAL ;
    PORT
      LAYER M4 ;
        RECT 0.048 39.456 0.240 39.480 ;
    END
  END di[772]
  PIN di[773]
    DIRECTION INOUT ;
    USE SIGNAL ;
    PORT
      LAYER M4 ;
        RECT 0.048 39.504 0.240 39.528 ;
    END
  END di[773]
  PIN di[774]
    DIRECTION INOUT ;
    USE SIGNAL ;
    PORT
      LAYER M4 ;
        RECT 0.048 39.552 0.240 39.576 ;
    END
  END di[774]
  PIN di[775]
    DIRECTION INOUT ;
    USE SIGNAL ;
    PORT
      LAYER M4 ;
        RECT 0.048 39.600 0.240 39.624 ;
    END
  END di[775]
  PIN di[776]
    DIRECTION INOUT ;
    USE SIGNAL ;
    PORT
      LAYER M4 ;
        RECT 0.048 39.648 0.240 39.672 ;
    END
  END di[776]
  PIN di[777]
    DIRECTION INOUT ;
    USE SIGNAL ;
    PORT
      LAYER M4 ;
        RECT 0.048 39.696 0.240 39.720 ;
    END
  END di[777]
  PIN di[778]
    DIRECTION INOUT ;
    USE SIGNAL ;
    PORT
      LAYER M4 ;
        RECT 0.048 39.744 0.240 39.768 ;
    END
  END di[778]
  PIN di[779]
    DIRECTION INOUT ;
    USE SIGNAL ;
    PORT
      LAYER M4 ;
        RECT 0.048 39.792 0.240 39.816 ;
    END
  END di[779]
  PIN di[780]
    DIRECTION INOUT ;
    USE SIGNAL ;
    PORT
      LAYER M4 ;
        RECT 0.048 39.840 0.240 39.864 ;
    END
  END di[780]
  PIN di[781]
    DIRECTION INOUT ;
    USE SIGNAL ;
    PORT
      LAYER M4 ;
        RECT 0.048 39.888 0.240 39.912 ;
    END
  END di[781]
  PIN di[782]
    DIRECTION INOUT ;
    USE SIGNAL ;
    PORT
      LAYER M4 ;
        RECT 0.048 39.936 0.240 39.960 ;
    END
  END di[782]
  PIN di[783]
    DIRECTION INOUT ;
    USE SIGNAL ;
    PORT
      LAYER M4 ;
        RECT 0.048 39.984 0.240 40.008 ;
    END
  END di[783]
  PIN di[784]
    DIRECTION INOUT ;
    USE SIGNAL ;
    PORT
      LAYER M4 ;
        RECT 0.048 40.032 0.240 40.056 ;
    END
  END di[784]
  PIN di[785]
    DIRECTION INOUT ;
    USE SIGNAL ;
    PORT
      LAYER M4 ;
        RECT 0.048 40.080 0.240 40.104 ;
    END
  END di[785]
  PIN di[786]
    DIRECTION INOUT ;
    USE SIGNAL ;
    PORT
      LAYER M4 ;
        RECT 0.048 40.128 0.240 40.152 ;
    END
  END di[786]
  PIN di[787]
    DIRECTION INOUT ;
    USE SIGNAL ;
    PORT
      LAYER M4 ;
        RECT 0.048 40.176 0.240 40.200 ;
    END
  END di[787]
  PIN di[788]
    DIRECTION INOUT ;
    USE SIGNAL ;
    PORT
      LAYER M4 ;
        RECT 0.048 40.224 0.240 40.248 ;
    END
  END di[788]
  PIN di[789]
    DIRECTION INOUT ;
    USE SIGNAL ;
    PORT
      LAYER M4 ;
        RECT 0.048 40.272 0.240 40.296 ;
    END
  END di[789]
  PIN di[790]
    DIRECTION INOUT ;
    USE SIGNAL ;
    PORT
      LAYER M4 ;
        RECT 0.048 40.320 0.240 40.344 ;
    END
  END di[790]
  PIN di[791]
    DIRECTION INOUT ;
    USE SIGNAL ;
    PORT
      LAYER M4 ;
        RECT 0.048 40.368 0.240 40.392 ;
    END
  END di[791]
  PIN di[792]
    DIRECTION INOUT ;
    USE SIGNAL ;
    PORT
      LAYER M4 ;
        RECT 0.048 40.416 0.240 40.440 ;
    END
  END di[792]
  PIN di[793]
    DIRECTION INOUT ;
    USE SIGNAL ;
    PORT
      LAYER M4 ;
        RECT 0.048 40.464 0.240 40.488 ;
    END
  END di[793]
  PIN di[794]
    DIRECTION INOUT ;
    USE SIGNAL ;
    PORT
      LAYER M4 ;
        RECT 0.048 40.512 0.240 40.536 ;
    END
  END di[794]
  PIN di[795]
    DIRECTION INOUT ;
    USE SIGNAL ;
    PORT
      LAYER M4 ;
        RECT 0.048 40.560 0.240 40.584 ;
    END
  END di[795]
  PIN di[796]
    DIRECTION INOUT ;
    USE SIGNAL ;
    PORT
      LAYER M4 ;
        RECT 0.048 40.608 0.240 40.632 ;
    END
  END di[796]
  PIN di[797]
    DIRECTION INOUT ;
    USE SIGNAL ;
    PORT
      LAYER M4 ;
        RECT 0.048 40.656 0.240 40.680 ;
    END
  END di[797]
  PIN di[798]
    DIRECTION INOUT ;
    USE SIGNAL ;
    PORT
      LAYER M4 ;
        RECT 0.048 40.704 0.240 40.728 ;
    END
  END di[798]
  PIN di[799]
    DIRECTION INOUT ;
    USE SIGNAL ;
    PORT
      LAYER M4 ;
        RECT 0.048 40.752 0.240 40.776 ;
    END
  END di[799]
  PIN di[800]
    DIRECTION INOUT ;
    USE SIGNAL ;
    PORT
      LAYER M4 ;
        RECT 0.048 40.800 0.240 40.824 ;
    END
  END di[800]
  PIN di[801]
    DIRECTION INOUT ;
    USE SIGNAL ;
    PORT
      LAYER M4 ;
        RECT 0.048 40.848 0.240 40.872 ;
    END
  END di[801]
  PIN di[802]
    DIRECTION INOUT ;
    USE SIGNAL ;
    PORT
      LAYER M4 ;
        RECT 0.048 40.896 0.240 40.920 ;
    END
  END di[802]
  PIN di[803]
    DIRECTION INOUT ;
    USE SIGNAL ;
    PORT
      LAYER M4 ;
        RECT 0.048 40.944 0.240 40.968 ;
    END
  END di[803]
  PIN di[804]
    DIRECTION INOUT ;
    USE SIGNAL ;
    PORT
      LAYER M4 ;
        RECT 0.048 40.992 0.240 41.016 ;
    END
  END di[804]
  PIN di[805]
    DIRECTION INOUT ;
    USE SIGNAL ;
    PORT
      LAYER M4 ;
        RECT 0.048 41.040 0.240 41.064 ;
    END
  END di[805]
  PIN di[806]
    DIRECTION INOUT ;
    USE SIGNAL ;
    PORT
      LAYER M4 ;
        RECT 0.048 41.088 0.240 41.112 ;
    END
  END di[806]
  PIN di[807]
    DIRECTION INOUT ;
    USE SIGNAL ;
    PORT
      LAYER M4 ;
        RECT 0.048 41.136 0.240 41.160 ;
    END
  END di[807]
  PIN di[808]
    DIRECTION INOUT ;
    USE SIGNAL ;
    PORT
      LAYER M4 ;
        RECT 0.048 41.184 0.240 41.208 ;
    END
  END di[808]
  PIN di[809]
    DIRECTION INOUT ;
    USE SIGNAL ;
    PORT
      LAYER M4 ;
        RECT 0.048 41.232 0.240 41.256 ;
    END
  END di[809]
  PIN di[810]
    DIRECTION INOUT ;
    USE SIGNAL ;
    PORT
      LAYER M4 ;
        RECT 0.048 41.280 0.240 41.304 ;
    END
  END di[810]
  PIN di[811]
    DIRECTION INOUT ;
    USE SIGNAL ;
    PORT
      LAYER M4 ;
        RECT 0.048 41.328 0.240 41.352 ;
    END
  END di[811]
  PIN di[812]
    DIRECTION INOUT ;
    USE SIGNAL ;
    PORT
      LAYER M4 ;
        RECT 0.048 41.376 0.240 41.400 ;
    END
  END di[812]
  PIN di[813]
    DIRECTION INOUT ;
    USE SIGNAL ;
    PORT
      LAYER M4 ;
        RECT 0.048 41.424 0.240 41.448 ;
    END
  END di[813]
  PIN di[814]
    DIRECTION INOUT ;
    USE SIGNAL ;
    PORT
      LAYER M4 ;
        RECT 0.048 41.472 0.240 41.496 ;
    END
  END di[814]
  PIN di[815]
    DIRECTION INOUT ;
    USE SIGNAL ;
    PORT
      LAYER M4 ;
        RECT 0.048 41.520 0.240 41.544 ;
    END
  END di[815]
  PIN di[816]
    DIRECTION INOUT ;
    USE SIGNAL ;
    PORT
      LAYER M4 ;
        RECT 0.048 41.568 0.240 41.592 ;
    END
  END di[816]
  PIN di[817]
    DIRECTION INOUT ;
    USE SIGNAL ;
    PORT
      LAYER M4 ;
        RECT 0.048 41.616 0.240 41.640 ;
    END
  END di[817]
  PIN di[818]
    DIRECTION INOUT ;
    USE SIGNAL ;
    PORT
      LAYER M4 ;
        RECT 0.048 41.664 0.240 41.688 ;
    END
  END di[818]
  PIN di[819]
    DIRECTION INOUT ;
    USE SIGNAL ;
    PORT
      LAYER M4 ;
        RECT 0.048 41.712 0.240 41.736 ;
    END
  END di[819]
  PIN di[820]
    DIRECTION INOUT ;
    USE SIGNAL ;
    PORT
      LAYER M4 ;
        RECT 0.048 41.760 0.240 41.784 ;
    END
  END di[820]
  PIN di[821]
    DIRECTION INOUT ;
    USE SIGNAL ;
    PORT
      LAYER M4 ;
        RECT 0.048 41.808 0.240 41.832 ;
    END
  END di[821]
  PIN di[822]
    DIRECTION INOUT ;
    USE SIGNAL ;
    PORT
      LAYER M4 ;
        RECT 0.048 41.856 0.240 41.880 ;
    END
  END di[822]
  PIN di[823]
    DIRECTION INOUT ;
    USE SIGNAL ;
    PORT
      LAYER M4 ;
        RECT 0.048 41.904 0.240 41.928 ;
    END
  END di[823]
  PIN di[824]
    DIRECTION INOUT ;
    USE SIGNAL ;
    PORT
      LAYER M4 ;
        RECT 0.048 41.952 0.240 41.976 ;
    END
  END di[824]
  PIN di[825]
    DIRECTION INOUT ;
    USE SIGNAL ;
    PORT
      LAYER M4 ;
        RECT 0.048 42.000 0.240 42.024 ;
    END
  END di[825]
  PIN di[826]
    DIRECTION INOUT ;
    USE SIGNAL ;
    PORT
      LAYER M4 ;
        RECT 0.048 42.048 0.240 42.072 ;
    END
  END di[826]
  PIN di[827]
    DIRECTION INOUT ;
    USE SIGNAL ;
    PORT
      LAYER M4 ;
        RECT 0.048 42.096 0.240 42.120 ;
    END
  END di[827]
  PIN di[828]
    DIRECTION INOUT ;
    USE SIGNAL ;
    PORT
      LAYER M4 ;
        RECT 0.048 42.144 0.240 42.168 ;
    END
  END di[828]
  PIN di[829]
    DIRECTION INOUT ;
    USE SIGNAL ;
    PORT
      LAYER M4 ;
        RECT 0.048 42.192 0.240 42.216 ;
    END
  END di[829]
  PIN di[830]
    DIRECTION INOUT ;
    USE SIGNAL ;
    PORT
      LAYER M4 ;
        RECT 0.048 42.240 0.240 42.264 ;
    END
  END di[830]
  PIN di[831]
    DIRECTION INOUT ;
    USE SIGNAL ;
    PORT
      LAYER M4 ;
        RECT 0.048 42.288 0.240 42.312 ;
    END
  END di[831]
  PIN di[832]
    DIRECTION INOUT ;
    USE SIGNAL ;
    PORT
      LAYER M4 ;
        RECT 0.048 42.336 0.240 42.360 ;
    END
  END di[832]
  PIN di[833]
    DIRECTION INOUT ;
    USE SIGNAL ;
    PORT
      LAYER M4 ;
        RECT 0.048 42.384 0.240 42.408 ;
    END
  END di[833]
  PIN di[834]
    DIRECTION INOUT ;
    USE SIGNAL ;
    PORT
      LAYER M4 ;
        RECT 0.048 42.432 0.240 42.456 ;
    END
  END di[834]
  PIN di[835]
    DIRECTION INOUT ;
    USE SIGNAL ;
    PORT
      LAYER M4 ;
        RECT 0.048 42.480 0.240 42.504 ;
    END
  END di[835]
  PIN di[836]
    DIRECTION INOUT ;
    USE SIGNAL ;
    PORT
      LAYER M4 ;
        RECT 0.048 42.528 0.240 42.552 ;
    END
  END di[836]
  PIN di[837]
    DIRECTION INOUT ;
    USE SIGNAL ;
    PORT
      LAYER M4 ;
        RECT 0.048 42.576 0.240 42.600 ;
    END
  END di[837]
  PIN di[838]
    DIRECTION INOUT ;
    USE SIGNAL ;
    PORT
      LAYER M4 ;
        RECT 0.048 42.624 0.240 42.648 ;
    END
  END di[838]
  PIN di[839]
    DIRECTION INOUT ;
    USE SIGNAL ;
    PORT
      LAYER M4 ;
        RECT 0.048 42.672 0.240 42.696 ;
    END
  END di[839]
  PIN di[840]
    DIRECTION INOUT ;
    USE SIGNAL ;
    PORT
      LAYER M4 ;
        RECT 0.048 42.720 0.240 42.744 ;
    END
  END di[840]
  PIN di[841]
    DIRECTION INOUT ;
    USE SIGNAL ;
    PORT
      LAYER M4 ;
        RECT 0.048 42.768 0.240 42.792 ;
    END
  END di[841]
  PIN di[842]
    DIRECTION INOUT ;
    USE SIGNAL ;
    PORT
      LAYER M4 ;
        RECT 0.048 42.816 0.240 42.840 ;
    END
  END di[842]
  PIN di[843]
    DIRECTION INOUT ;
    USE SIGNAL ;
    PORT
      LAYER M4 ;
        RECT 0.048 42.864 0.240 42.888 ;
    END
  END di[843]
  PIN di[844]
    DIRECTION INOUT ;
    USE SIGNAL ;
    PORT
      LAYER M4 ;
        RECT 0.048 42.912 0.240 42.936 ;
    END
  END di[844]
  PIN di[845]
    DIRECTION INOUT ;
    USE SIGNAL ;
    PORT
      LAYER M4 ;
        RECT 0.048 42.960 0.240 42.984 ;
    END
  END di[845]
  PIN di[846]
    DIRECTION INOUT ;
    USE SIGNAL ;
    PORT
      LAYER M4 ;
        RECT 0.048 43.008 0.240 43.032 ;
    END
  END di[846]
  PIN di[847]
    DIRECTION INOUT ;
    USE SIGNAL ;
    PORT
      LAYER M4 ;
        RECT 0.048 43.056 0.240 43.080 ;
    END
  END di[847]
  PIN di[848]
    DIRECTION INOUT ;
    USE SIGNAL ;
    PORT
      LAYER M4 ;
        RECT 0.048 43.104 0.240 43.128 ;
    END
  END di[848]
  PIN di[849]
    DIRECTION INOUT ;
    USE SIGNAL ;
    PORT
      LAYER M4 ;
        RECT 0.048 43.152 0.240 43.176 ;
    END
  END di[849]
  PIN di[850]
    DIRECTION INOUT ;
    USE SIGNAL ;
    PORT
      LAYER M4 ;
        RECT 0.048 43.200 0.240 43.224 ;
    END
  END di[850]
  PIN di[851]
    DIRECTION INOUT ;
    USE SIGNAL ;
    PORT
      LAYER M4 ;
        RECT 0.048 43.248 0.240 43.272 ;
    END
  END di[851]
  PIN di[852]
    DIRECTION INOUT ;
    USE SIGNAL ;
    PORT
      LAYER M4 ;
        RECT 0.048 43.296 0.240 43.320 ;
    END
  END di[852]
  PIN di[853]
    DIRECTION INOUT ;
    USE SIGNAL ;
    PORT
      LAYER M4 ;
        RECT 0.048 43.344 0.240 43.368 ;
    END
  END di[853]
  PIN di[854]
    DIRECTION INOUT ;
    USE SIGNAL ;
    PORT
      LAYER M4 ;
        RECT 0.048 43.392 0.240 43.416 ;
    END
  END di[854]
  PIN di[855]
    DIRECTION INOUT ;
    USE SIGNAL ;
    PORT
      LAYER M4 ;
        RECT 0.048 43.440 0.240 43.464 ;
    END
  END di[855]
  PIN di[856]
    DIRECTION INOUT ;
    USE SIGNAL ;
    PORT
      LAYER M4 ;
        RECT 0.048 43.488 0.240 43.512 ;
    END
  END di[856]
  PIN di[857]
    DIRECTION INOUT ;
    USE SIGNAL ;
    PORT
      LAYER M4 ;
        RECT 0.048 43.536 0.240 43.560 ;
    END
  END di[857]
  PIN di[858]
    DIRECTION INOUT ;
    USE SIGNAL ;
    PORT
      LAYER M4 ;
        RECT 0.048 43.584 0.240 43.608 ;
    END
  END di[858]
  PIN di[859]
    DIRECTION INOUT ;
    USE SIGNAL ;
    PORT
      LAYER M4 ;
        RECT 0.048 43.632 0.240 43.656 ;
    END
  END di[859]
  PIN di[860]
    DIRECTION INOUT ;
    USE SIGNAL ;
    PORT
      LAYER M4 ;
        RECT 0.048 43.680 0.240 43.704 ;
    END
  END di[860]
  PIN di[861]
    DIRECTION INOUT ;
    USE SIGNAL ;
    PORT
      LAYER M4 ;
        RECT 0.048 43.728 0.240 43.752 ;
    END
  END di[861]
  PIN di[862]
    DIRECTION INOUT ;
    USE SIGNAL ;
    PORT
      LAYER M4 ;
        RECT 0.048 43.776 0.240 43.800 ;
    END
  END di[862]
  PIN di[863]
    DIRECTION INOUT ;
    USE SIGNAL ;
    PORT
      LAYER M4 ;
        RECT 0.048 43.824 0.240 43.848 ;
    END
  END di[863]
  PIN di[864]
    DIRECTION INOUT ;
    USE SIGNAL ;
    PORT
      LAYER M4 ;
        RECT 0.048 43.872 0.240 43.896 ;
    END
  END di[864]
  PIN di[865]
    DIRECTION INOUT ;
    USE SIGNAL ;
    PORT
      LAYER M4 ;
        RECT 0.048 43.920 0.240 43.944 ;
    END
  END di[865]
  PIN di[866]
    DIRECTION INOUT ;
    USE SIGNAL ;
    PORT
      LAYER M4 ;
        RECT 0.048 43.968 0.240 43.992 ;
    END
  END di[866]
  PIN di[867]
    DIRECTION INOUT ;
    USE SIGNAL ;
    PORT
      LAYER M4 ;
        RECT 0.048 44.016 0.240 44.040 ;
    END
  END di[867]
  PIN di[868]
    DIRECTION INOUT ;
    USE SIGNAL ;
    PORT
      LAYER M4 ;
        RECT 0.048 44.064 0.240 44.088 ;
    END
  END di[868]
  PIN di[869]
    DIRECTION INOUT ;
    USE SIGNAL ;
    PORT
      LAYER M4 ;
        RECT 0.048 44.112 0.240 44.136 ;
    END
  END di[869]
  PIN di[870]
    DIRECTION INOUT ;
    USE SIGNAL ;
    PORT
      LAYER M4 ;
        RECT 0.048 44.160 0.240 44.184 ;
    END
  END di[870]
  PIN di[871]
    DIRECTION INOUT ;
    USE SIGNAL ;
    PORT
      LAYER M4 ;
        RECT 0.048 44.208 0.240 44.232 ;
    END
  END di[871]
  PIN di[872]
    DIRECTION INOUT ;
    USE SIGNAL ;
    PORT
      LAYER M4 ;
        RECT 0.048 44.256 0.240 44.280 ;
    END
  END di[872]
  PIN di[873]
    DIRECTION INOUT ;
    USE SIGNAL ;
    PORT
      LAYER M4 ;
        RECT 0.048 44.304 0.240 44.328 ;
    END
  END di[873]
  PIN di[874]
    DIRECTION INOUT ;
    USE SIGNAL ;
    PORT
      LAYER M4 ;
        RECT 0.048 44.352 0.240 44.376 ;
    END
  END di[874]
  PIN di[875]
    DIRECTION INOUT ;
    USE SIGNAL ;
    PORT
      LAYER M4 ;
        RECT 0.048 44.400 0.240 44.424 ;
    END
  END di[875]
  PIN di[876]
    DIRECTION INOUT ;
    USE SIGNAL ;
    PORT
      LAYER M4 ;
        RECT 0.048 44.448 0.240 44.472 ;
    END
  END di[876]
  PIN di[877]
    DIRECTION INOUT ;
    USE SIGNAL ;
    PORT
      LAYER M4 ;
        RECT 0.048 44.496 0.240 44.520 ;
    END
  END di[877]
  PIN di[878]
    DIRECTION INOUT ;
    USE SIGNAL ;
    PORT
      LAYER M4 ;
        RECT 0.048 44.544 0.240 44.568 ;
    END
  END di[878]
  PIN di[879]
    DIRECTION INOUT ;
    USE SIGNAL ;
    PORT
      LAYER M4 ;
        RECT 0.048 44.592 0.240 44.616 ;
    END
  END di[879]
  PIN di[880]
    DIRECTION INOUT ;
    USE SIGNAL ;
    PORT
      LAYER M4 ;
        RECT 0.048 44.640 0.240 44.664 ;
    END
  END di[880]
  PIN di[881]
    DIRECTION INOUT ;
    USE SIGNAL ;
    PORT
      LAYER M4 ;
        RECT 0.048 44.688 0.240 44.712 ;
    END
  END di[881]
  PIN di[882]
    DIRECTION INOUT ;
    USE SIGNAL ;
    PORT
      LAYER M4 ;
        RECT 0.048 44.736 0.240 44.760 ;
    END
  END di[882]
  PIN di[883]
    DIRECTION INOUT ;
    USE SIGNAL ;
    PORT
      LAYER M4 ;
        RECT 0.048 44.784 0.240 44.808 ;
    END
  END di[883]
  PIN di[884]
    DIRECTION INOUT ;
    USE SIGNAL ;
    PORT
      LAYER M4 ;
        RECT 0.048 44.832 0.240 44.856 ;
    END
  END di[884]
  PIN di[885]
    DIRECTION INOUT ;
    USE SIGNAL ;
    PORT
      LAYER M4 ;
        RECT 0.048 44.880 0.240 44.904 ;
    END
  END di[885]
  PIN di[886]
    DIRECTION INOUT ;
    USE SIGNAL ;
    PORT
      LAYER M4 ;
        RECT 0.048 44.928 0.240 44.952 ;
    END
  END di[886]
  PIN di[887]
    DIRECTION INOUT ;
    USE SIGNAL ;
    PORT
      LAYER M4 ;
        RECT 0.048 44.976 0.240 45.000 ;
    END
  END di[887]
  PIN di[888]
    DIRECTION INOUT ;
    USE SIGNAL ;
    PORT
      LAYER M4 ;
        RECT 0.048 45.024 0.240 45.048 ;
    END
  END di[888]
  PIN di[889]
    DIRECTION INOUT ;
    USE SIGNAL ;
    PORT
      LAYER M4 ;
        RECT 0.048 45.072 0.240 45.096 ;
    END
  END di[889]
  PIN di[890]
    DIRECTION INOUT ;
    USE SIGNAL ;
    PORT
      LAYER M4 ;
        RECT 0.048 45.120 0.240 45.144 ;
    END
  END di[890]
  PIN di[891]
    DIRECTION INOUT ;
    USE SIGNAL ;
    PORT
      LAYER M4 ;
        RECT 0.048 45.168 0.240 45.192 ;
    END
  END di[891]
  PIN di[892]
    DIRECTION INOUT ;
    USE SIGNAL ;
    PORT
      LAYER M4 ;
        RECT 0.048 45.216 0.240 45.240 ;
    END
  END di[892]
  PIN di[893]
    DIRECTION INOUT ;
    USE SIGNAL ;
    PORT
      LAYER M4 ;
        RECT 0.048 45.264 0.240 45.288 ;
    END
  END di[893]
  PIN di[894]
    DIRECTION INOUT ;
    USE SIGNAL ;
    PORT
      LAYER M4 ;
        RECT 0.048 45.312 0.240 45.336 ;
    END
  END di[894]
  PIN di[895]
    DIRECTION INOUT ;
    USE SIGNAL ;
    PORT
      LAYER M4 ;
        RECT 0.048 45.360 0.240 45.384 ;
    END
  END di[895]
  PIN di[896]
    DIRECTION INOUT ;
    USE SIGNAL ;
    PORT
      LAYER M4 ;
        RECT 0.048 45.408 0.240 45.432 ;
    END
  END di[896]
  PIN di[897]
    DIRECTION INOUT ;
    USE SIGNAL ;
    PORT
      LAYER M4 ;
        RECT 0.048 45.456 0.240 45.480 ;
    END
  END di[897]
  PIN di[898]
    DIRECTION INOUT ;
    USE SIGNAL ;
    PORT
      LAYER M4 ;
        RECT 0.048 45.504 0.240 45.528 ;
    END
  END di[898]
  PIN di[899]
    DIRECTION INOUT ;
    USE SIGNAL ;
    PORT
      LAYER M4 ;
        RECT 0.048 45.552 0.240 45.576 ;
    END
  END di[899]
  PIN di[900]
    DIRECTION INOUT ;
    USE SIGNAL ;
    PORT
      LAYER M4 ;
        RECT 0.048 45.600 0.240 45.624 ;
    END
  END di[900]
  PIN di[901]
    DIRECTION INOUT ;
    USE SIGNAL ;
    PORT
      LAYER M4 ;
        RECT 0.048 45.648 0.240 45.672 ;
    END
  END di[901]
  PIN di[902]
    DIRECTION INOUT ;
    USE SIGNAL ;
    PORT
      LAYER M4 ;
        RECT 0.048 45.696 0.240 45.720 ;
    END
  END di[902]
  PIN di[903]
    DIRECTION INOUT ;
    USE SIGNAL ;
    PORT
      LAYER M4 ;
        RECT 0.048 45.744 0.240 45.768 ;
    END
  END di[903]
  PIN di[904]
    DIRECTION INOUT ;
    USE SIGNAL ;
    PORT
      LAYER M4 ;
        RECT 0.048 45.792 0.240 45.816 ;
    END
  END di[904]
  PIN di[905]
    DIRECTION INOUT ;
    USE SIGNAL ;
    PORT
      LAYER M4 ;
        RECT 0.048 45.840 0.240 45.864 ;
    END
  END di[905]
  PIN di[906]
    DIRECTION INOUT ;
    USE SIGNAL ;
    PORT
      LAYER M4 ;
        RECT 0.048 45.888 0.240 45.912 ;
    END
  END di[906]
  PIN di[907]
    DIRECTION INOUT ;
    USE SIGNAL ;
    PORT
      LAYER M4 ;
        RECT 0.048 45.936 0.240 45.960 ;
    END
  END di[907]
  PIN di[908]
    DIRECTION INOUT ;
    USE SIGNAL ;
    PORT
      LAYER M4 ;
        RECT 0.048 45.984 0.240 46.008 ;
    END
  END di[908]
  PIN di[909]
    DIRECTION INOUT ;
    USE SIGNAL ;
    PORT
      LAYER M4 ;
        RECT 0.048 46.032 0.240 46.056 ;
    END
  END di[909]
  PIN di[910]
    DIRECTION INOUT ;
    USE SIGNAL ;
    PORT
      LAYER M4 ;
        RECT 0.048 46.080 0.240 46.104 ;
    END
  END di[910]
  PIN di[911]
    DIRECTION INOUT ;
    USE SIGNAL ;
    PORT
      LAYER M4 ;
        RECT 0.048 46.128 0.240 46.152 ;
    END
  END di[911]
  PIN di[912]
    DIRECTION INOUT ;
    USE SIGNAL ;
    PORT
      LAYER M4 ;
        RECT 0.048 46.176 0.240 46.200 ;
    END
  END di[912]
  PIN di[913]
    DIRECTION INOUT ;
    USE SIGNAL ;
    PORT
      LAYER M4 ;
        RECT 0.048 46.224 0.240 46.248 ;
    END
  END di[913]
  PIN di[914]
    DIRECTION INOUT ;
    USE SIGNAL ;
    PORT
      LAYER M4 ;
        RECT 0.048 46.272 0.240 46.296 ;
    END
  END di[914]
  PIN di[915]
    DIRECTION INOUT ;
    USE SIGNAL ;
    PORT
      LAYER M4 ;
        RECT 0.048 46.320 0.240 46.344 ;
    END
  END di[915]
  PIN di[916]
    DIRECTION INOUT ;
    USE SIGNAL ;
    PORT
      LAYER M4 ;
        RECT 0.048 46.368 0.240 46.392 ;
    END
  END di[916]
  PIN di[917]
    DIRECTION INOUT ;
    USE SIGNAL ;
    PORT
      LAYER M4 ;
        RECT 0.048 46.416 0.240 46.440 ;
    END
  END di[917]
  PIN di[918]
    DIRECTION INOUT ;
    USE SIGNAL ;
    PORT
      LAYER M4 ;
        RECT 0.048 46.464 0.240 46.488 ;
    END
  END di[918]
  PIN di[919]
    DIRECTION INOUT ;
    USE SIGNAL ;
    PORT
      LAYER M4 ;
        RECT 0.048 46.512 0.240 46.536 ;
    END
  END di[919]
  PIN di[920]
    DIRECTION INOUT ;
    USE SIGNAL ;
    PORT
      LAYER M4 ;
        RECT 0.048 46.560 0.240 46.584 ;
    END
  END di[920]
  PIN di[921]
    DIRECTION INOUT ;
    USE SIGNAL ;
    PORT
      LAYER M4 ;
        RECT 0.048 46.608 0.240 46.632 ;
    END
  END di[921]
  PIN di[922]
    DIRECTION INOUT ;
    USE SIGNAL ;
    PORT
      LAYER M4 ;
        RECT 0.048 46.656 0.240 46.680 ;
    END
  END di[922]
  PIN di[923]
    DIRECTION INOUT ;
    USE SIGNAL ;
    PORT
      LAYER M4 ;
        RECT 0.048 46.704 0.240 46.728 ;
    END
  END di[923]
  PIN di[924]
    DIRECTION INOUT ;
    USE SIGNAL ;
    PORT
      LAYER M4 ;
        RECT 0.048 46.752 0.240 46.776 ;
    END
  END di[924]
  PIN di[925]
    DIRECTION INOUT ;
    USE SIGNAL ;
    PORT
      LAYER M4 ;
        RECT 0.048 46.800 0.240 46.824 ;
    END
  END di[925]
  PIN di[926]
    DIRECTION INOUT ;
    USE SIGNAL ;
    PORT
      LAYER M4 ;
        RECT 0.048 46.848 0.240 46.872 ;
    END
  END di[926]
  PIN di[927]
    DIRECTION INOUT ;
    USE SIGNAL ;
    PORT
      LAYER M4 ;
        RECT 0.048 46.896 0.240 46.920 ;
    END
  END di[927]
  PIN di[928]
    DIRECTION INOUT ;
    USE SIGNAL ;
    PORT
      LAYER M4 ;
        RECT 0.048 46.944 0.240 46.968 ;
    END
  END di[928]
  PIN di[929]
    DIRECTION INOUT ;
    USE SIGNAL ;
    PORT
      LAYER M4 ;
        RECT 0.048 46.992 0.240 47.016 ;
    END
  END di[929]
  PIN di[930]
    DIRECTION INOUT ;
    USE SIGNAL ;
    PORT
      LAYER M4 ;
        RECT 0.048 47.040 0.240 47.064 ;
    END
  END di[930]
  PIN di[931]
    DIRECTION INOUT ;
    USE SIGNAL ;
    PORT
      LAYER M4 ;
        RECT 0.048 47.088 0.240 47.112 ;
    END
  END di[931]
  PIN di[932]
    DIRECTION INOUT ;
    USE SIGNAL ;
    PORT
      LAYER M4 ;
        RECT 0.048 47.136 0.240 47.160 ;
    END
  END di[932]
  PIN di[933]
    DIRECTION INOUT ;
    USE SIGNAL ;
    PORT
      LAYER M4 ;
        RECT 0.048 47.184 0.240 47.208 ;
    END
  END di[933]
  PIN di[934]
    DIRECTION INOUT ;
    USE SIGNAL ;
    PORT
      LAYER M4 ;
        RECT 0.048 47.232 0.240 47.256 ;
    END
  END di[934]
  PIN di[935]
    DIRECTION INOUT ;
    USE SIGNAL ;
    PORT
      LAYER M4 ;
        RECT 0.048 47.280 0.240 47.304 ;
    END
  END di[935]
  PIN di[936]
    DIRECTION INOUT ;
    USE SIGNAL ;
    PORT
      LAYER M4 ;
        RECT 0.048 47.328 0.240 47.352 ;
    END
  END di[936]
  PIN di[937]
    DIRECTION INOUT ;
    USE SIGNAL ;
    PORT
      LAYER M4 ;
        RECT 0.048 47.376 0.240 47.400 ;
    END
  END di[937]
  PIN di[938]
    DIRECTION INOUT ;
    USE SIGNAL ;
    PORT
      LAYER M4 ;
        RECT 0.048 47.424 0.240 47.448 ;
    END
  END di[938]
  PIN di[939]
    DIRECTION INOUT ;
    USE SIGNAL ;
    PORT
      LAYER M4 ;
        RECT 0.048 47.472 0.240 47.496 ;
    END
  END di[939]
  PIN di[940]
    DIRECTION INOUT ;
    USE SIGNAL ;
    PORT
      LAYER M4 ;
        RECT 0.048 47.520 0.240 47.544 ;
    END
  END di[940]
  PIN di[941]
    DIRECTION INOUT ;
    USE SIGNAL ;
    PORT
      LAYER M4 ;
        RECT 0.048 47.568 0.240 47.592 ;
    END
  END di[941]
  PIN di[942]
    DIRECTION INOUT ;
    USE SIGNAL ;
    PORT
      LAYER M4 ;
        RECT 0.048 47.616 0.240 47.640 ;
    END
  END di[942]
  PIN di[943]
    DIRECTION INOUT ;
    USE SIGNAL ;
    PORT
      LAYER M4 ;
        RECT 0.048 47.664 0.240 47.688 ;
    END
  END di[943]
  PIN di[944]
    DIRECTION INOUT ;
    USE SIGNAL ;
    PORT
      LAYER M4 ;
        RECT 0.048 47.712 0.240 47.736 ;
    END
  END di[944]
  PIN di[945]
    DIRECTION INOUT ;
    USE SIGNAL ;
    PORT
      LAYER M4 ;
        RECT 0.048 47.760 0.240 47.784 ;
    END
  END di[945]
  PIN di[946]
    DIRECTION INOUT ;
    USE SIGNAL ;
    PORT
      LAYER M4 ;
        RECT 0.048 47.808 0.240 47.832 ;
    END
  END di[946]
  PIN di[947]
    DIRECTION INOUT ;
    USE SIGNAL ;
    PORT
      LAYER M4 ;
        RECT 0.048 47.856 0.240 47.880 ;
    END
  END di[947]
  PIN di[948]
    DIRECTION INOUT ;
    USE SIGNAL ;
    PORT
      LAYER M4 ;
        RECT 0.048 47.904 0.240 47.928 ;
    END
  END di[948]
  PIN di[949]
    DIRECTION INOUT ;
    USE SIGNAL ;
    PORT
      LAYER M4 ;
        RECT 0.048 47.952 0.240 47.976 ;
    END
  END di[949]
  PIN di[950]
    DIRECTION INOUT ;
    USE SIGNAL ;
    PORT
      LAYER M4 ;
        RECT 0.048 48.000 0.240 48.024 ;
    END
  END di[950]
  PIN di[951]
    DIRECTION INOUT ;
    USE SIGNAL ;
    PORT
      LAYER M4 ;
        RECT 0.048 48.048 0.240 48.072 ;
    END
  END di[951]
  PIN di[952]
    DIRECTION INOUT ;
    USE SIGNAL ;
    PORT
      LAYER M4 ;
        RECT 0.048 48.096 0.240 48.120 ;
    END
  END di[952]
  PIN di[953]
    DIRECTION INOUT ;
    USE SIGNAL ;
    PORT
      LAYER M4 ;
        RECT 0.048 48.144 0.240 48.168 ;
    END
  END di[953]
  PIN di[954]
    DIRECTION INOUT ;
    USE SIGNAL ;
    PORT
      LAYER M4 ;
        RECT 0.048 48.192 0.240 48.216 ;
    END
  END di[954]
  PIN di[955]
    DIRECTION INOUT ;
    USE SIGNAL ;
    PORT
      LAYER M4 ;
        RECT 0.048 48.240 0.240 48.264 ;
    END
  END di[955]
  PIN di[956]
    DIRECTION INOUT ;
    USE SIGNAL ;
    PORT
      LAYER M4 ;
        RECT 0.048 48.288 0.240 48.312 ;
    END
  END di[956]
  PIN di[957]
    DIRECTION INOUT ;
    USE SIGNAL ;
    PORT
      LAYER M4 ;
        RECT 0.048 48.336 0.240 48.360 ;
    END
  END di[957]
  PIN di[958]
    DIRECTION INOUT ;
    USE SIGNAL ;
    PORT
      LAYER M4 ;
        RECT 0.048 48.384 0.240 48.408 ;
    END
  END di[958]
  PIN di[959]
    DIRECTION INOUT ;
    USE SIGNAL ;
    PORT
      LAYER M4 ;
        RECT 0.048 48.432 0.240 48.456 ;
    END
  END di[959]
  PIN di[960]
    DIRECTION INOUT ;
    USE SIGNAL ;
    PORT
      LAYER M4 ;
        RECT 0.048 48.480 0.240 48.504 ;
    END
  END di[960]
  PIN di[961]
    DIRECTION INOUT ;
    USE SIGNAL ;
    PORT
      LAYER M4 ;
        RECT 0.048 48.528 0.240 48.552 ;
    END
  END di[961]
  PIN di[962]
    DIRECTION INOUT ;
    USE SIGNAL ;
    PORT
      LAYER M4 ;
        RECT 0.048 48.576 0.240 48.600 ;
    END
  END di[962]
  PIN di[963]
    DIRECTION INOUT ;
    USE SIGNAL ;
    PORT
      LAYER M4 ;
        RECT 0.048 48.624 0.240 48.648 ;
    END
  END di[963]
  PIN di[964]
    DIRECTION INOUT ;
    USE SIGNAL ;
    PORT
      LAYER M4 ;
        RECT 0.048 48.672 0.240 48.696 ;
    END
  END di[964]
  PIN di[965]
    DIRECTION INOUT ;
    USE SIGNAL ;
    PORT
      LAYER M4 ;
        RECT 0.048 48.720 0.240 48.744 ;
    END
  END di[965]
  PIN di[966]
    DIRECTION INOUT ;
    USE SIGNAL ;
    PORT
      LAYER M4 ;
        RECT 0.048 48.768 0.240 48.792 ;
    END
  END di[966]
  PIN di[967]
    DIRECTION INOUT ;
    USE SIGNAL ;
    PORT
      LAYER M4 ;
        RECT 0.048 48.816 0.240 48.840 ;
    END
  END di[967]
  PIN di[968]
    DIRECTION INOUT ;
    USE SIGNAL ;
    PORT
      LAYER M4 ;
        RECT 0.048 48.864 0.240 48.888 ;
    END
  END di[968]
  PIN di[969]
    DIRECTION INOUT ;
    USE SIGNAL ;
    PORT
      LAYER M4 ;
        RECT 0.048 48.912 0.240 48.936 ;
    END
  END di[969]
  PIN di[970]
    DIRECTION INOUT ;
    USE SIGNAL ;
    PORT
      LAYER M4 ;
        RECT 0.048 48.960 0.240 48.984 ;
    END
  END di[970]
  PIN di[971]
    DIRECTION INOUT ;
    USE SIGNAL ;
    PORT
      LAYER M4 ;
        RECT 0.048 49.008 0.240 49.032 ;
    END
  END di[971]
  PIN di[972]
    DIRECTION INOUT ;
    USE SIGNAL ;
    PORT
      LAYER M4 ;
        RECT 0.048 49.056 0.240 49.080 ;
    END
  END di[972]
  PIN di[973]
    DIRECTION INOUT ;
    USE SIGNAL ;
    PORT
      LAYER M4 ;
        RECT 0.048 49.104 0.240 49.128 ;
    END
  END di[973]
  PIN di[974]
    DIRECTION INOUT ;
    USE SIGNAL ;
    PORT
      LAYER M4 ;
        RECT 0.048 49.152 0.240 49.176 ;
    END
  END di[974]
  PIN di[975]
    DIRECTION INOUT ;
    USE SIGNAL ;
    PORT
      LAYER M4 ;
        RECT 0.048 49.200 0.240 49.224 ;
    END
  END di[975]
  PIN di[976]
    DIRECTION INOUT ;
    USE SIGNAL ;
    PORT
      LAYER M4 ;
        RECT 0.048 49.248 0.240 49.272 ;
    END
  END di[976]
  PIN di[977]
    DIRECTION INOUT ;
    USE SIGNAL ;
    PORT
      LAYER M4 ;
        RECT 0.048 49.296 0.240 49.320 ;
    END
  END di[977]
  PIN di[978]
    DIRECTION INOUT ;
    USE SIGNAL ;
    PORT
      LAYER M4 ;
        RECT 0.048 49.344 0.240 49.368 ;
    END
  END di[978]
  PIN di[979]
    DIRECTION INOUT ;
    USE SIGNAL ;
    PORT
      LAYER M4 ;
        RECT 0.048 49.392 0.240 49.416 ;
    END
  END di[979]
  PIN di[980]
    DIRECTION INOUT ;
    USE SIGNAL ;
    PORT
      LAYER M4 ;
        RECT 0.048 49.440 0.240 49.464 ;
    END
  END di[980]
  PIN di[981]
    DIRECTION INOUT ;
    USE SIGNAL ;
    PORT
      LAYER M4 ;
        RECT 0.048 49.488 0.240 49.512 ;
    END
  END di[981]
  PIN di[982]
    DIRECTION INOUT ;
    USE SIGNAL ;
    PORT
      LAYER M4 ;
        RECT 0.048 49.536 0.240 49.560 ;
    END
  END di[982]
  PIN di[983]
    DIRECTION INOUT ;
    USE SIGNAL ;
    PORT
      LAYER M4 ;
        RECT 0.048 49.584 0.240 49.608 ;
    END
  END di[983]
  PIN di[984]
    DIRECTION INOUT ;
    USE SIGNAL ;
    PORT
      LAYER M4 ;
        RECT 0.048 49.632 0.240 49.656 ;
    END
  END di[984]
  PIN di[985]
    DIRECTION INOUT ;
    USE SIGNAL ;
    PORT
      LAYER M4 ;
        RECT 0.048 49.680 0.240 49.704 ;
    END
  END di[985]
  PIN di[986]
    DIRECTION INOUT ;
    USE SIGNAL ;
    PORT
      LAYER M4 ;
        RECT 0.048 49.728 0.240 49.752 ;
    END
  END di[986]
  PIN di[987]
    DIRECTION INOUT ;
    USE SIGNAL ;
    PORT
      LAYER M4 ;
        RECT 0.048 49.776 0.240 49.800 ;
    END
  END di[987]
  PIN di[988]
    DIRECTION INOUT ;
    USE SIGNAL ;
    PORT
      LAYER M4 ;
        RECT 0.048 49.824 0.240 49.848 ;
    END
  END di[988]
  PIN di[989]
    DIRECTION INOUT ;
    USE SIGNAL ;
    PORT
      LAYER M4 ;
        RECT 0.048 49.872 0.240 49.896 ;
    END
  END di[989]
  PIN di[990]
    DIRECTION INOUT ;
    USE SIGNAL ;
    PORT
      LAYER M4 ;
        RECT 0.048 49.920 0.240 49.944 ;
    END
  END di[990]
  PIN di[991]
    DIRECTION INOUT ;
    USE SIGNAL ;
    PORT
      LAYER M4 ;
        RECT 0.048 49.968 0.240 49.992 ;
    END
  END di[991]
  PIN di[992]
    DIRECTION INOUT ;
    USE SIGNAL ;
    PORT
      LAYER M4 ;
        RECT 0.048 50.016 0.240 50.040 ;
    END
  END di[992]
  PIN di[993]
    DIRECTION INOUT ;
    USE SIGNAL ;
    PORT
      LAYER M4 ;
        RECT 0.048 50.064 0.240 50.088 ;
    END
  END di[993]
  PIN di[994]
    DIRECTION INOUT ;
    USE SIGNAL ;
    PORT
      LAYER M4 ;
        RECT 0.048 50.112 0.240 50.136 ;
    END
  END di[994]
  PIN di[995]
    DIRECTION INOUT ;
    USE SIGNAL ;
    PORT
      LAYER M4 ;
        RECT 0.048 50.160 0.240 50.184 ;
    END
  END di[995]
  PIN di[996]
    DIRECTION INOUT ;
    USE SIGNAL ;
    PORT
      LAYER M4 ;
        RECT 0.048 50.208 0.240 50.232 ;
    END
  END di[996]
  PIN di[997]
    DIRECTION INOUT ;
    USE SIGNAL ;
    PORT
      LAYER M4 ;
        RECT 0.048 50.256 0.240 50.280 ;
    END
  END di[997]
  PIN di[998]
    DIRECTION INOUT ;
    USE SIGNAL ;
    PORT
      LAYER M4 ;
        RECT 0.048 50.304 0.240 50.328 ;
    END
  END di[998]
  PIN di[999]
    DIRECTION INOUT ;
    USE SIGNAL ;
    PORT
      LAYER M4 ;
        RECT 0.048 50.352 0.240 50.376 ;
    END
  END di[999]
  PIN di[1000]
    DIRECTION INOUT ;
    USE SIGNAL ;
    PORT
      LAYER M4 ;
        RECT 0.048 50.400 0.240 50.424 ;
    END
  END di[1000]
  PIN di[1001]
    DIRECTION INOUT ;
    USE SIGNAL ;
    PORT
      LAYER M4 ;
        RECT 0.048 50.448 0.240 50.472 ;
    END
  END di[1001]
  PIN di[1002]
    DIRECTION INOUT ;
    USE SIGNAL ;
    PORT
      LAYER M4 ;
        RECT 0.048 50.496 0.240 50.520 ;
    END
  END di[1002]
  PIN di[1003]
    DIRECTION INOUT ;
    USE SIGNAL ;
    PORT
      LAYER M4 ;
        RECT 0.048 50.544 0.240 50.568 ;
    END
  END di[1003]
  PIN di[1004]
    DIRECTION INOUT ;
    USE SIGNAL ;
    PORT
      LAYER M4 ;
        RECT 0.048 50.592 0.240 50.616 ;
    END
  END di[1004]
  PIN di[1005]
    DIRECTION INOUT ;
    USE SIGNAL ;
    PORT
      LAYER M4 ;
        RECT 0.048 50.640 0.240 50.664 ;
    END
  END di[1005]
  PIN di[1006]
    DIRECTION INOUT ;
    USE SIGNAL ;
    PORT
      LAYER M4 ;
        RECT 0.048 50.688 0.240 50.712 ;
    END
  END di[1006]
  PIN di[1007]
    DIRECTION INOUT ;
    USE SIGNAL ;
    PORT
      LAYER M4 ;
        RECT 0.048 50.736 0.240 50.760 ;
    END
  END di[1007]
  PIN di[1008]
    DIRECTION INOUT ;
    USE SIGNAL ;
    PORT
      LAYER M4 ;
        RECT 0.048 50.784 0.240 50.808 ;
    END
  END di[1008]
  PIN di[1009]
    DIRECTION INOUT ;
    USE SIGNAL ;
    PORT
      LAYER M4 ;
        RECT 0.048 50.832 0.240 50.856 ;
    END
  END di[1009]
  PIN di[1010]
    DIRECTION INOUT ;
    USE SIGNAL ;
    PORT
      LAYER M4 ;
        RECT 0.048 50.880 0.240 50.904 ;
    END
  END di[1010]
  PIN di[1011]
    DIRECTION INOUT ;
    USE SIGNAL ;
    PORT
      LAYER M4 ;
        RECT 0.048 50.928 0.240 50.952 ;
    END
  END di[1011]
  PIN di[1012]
    DIRECTION INOUT ;
    USE SIGNAL ;
    PORT
      LAYER M4 ;
        RECT 0.048 50.976 0.240 51.000 ;
    END
  END di[1012]
  PIN di[1013]
    DIRECTION INOUT ;
    USE SIGNAL ;
    PORT
      LAYER M4 ;
        RECT 0.048 51.024 0.240 51.048 ;
    END
  END di[1013]
  PIN di[1014]
    DIRECTION INOUT ;
    USE SIGNAL ;
    PORT
      LAYER M4 ;
        RECT 0.048 51.072 0.240 51.096 ;
    END
  END di[1014]
  PIN di[1015]
    DIRECTION INOUT ;
    USE SIGNAL ;
    PORT
      LAYER M4 ;
        RECT 0.048 51.120 0.240 51.144 ;
    END
  END di[1015]
  PIN di[1016]
    DIRECTION INOUT ;
    USE SIGNAL ;
    PORT
      LAYER M4 ;
        RECT 0.048 51.168 0.240 51.192 ;
    END
  END di[1016]
  PIN di[1017]
    DIRECTION INOUT ;
    USE SIGNAL ;
    PORT
      LAYER M4 ;
        RECT 0.048 51.216 0.240 51.240 ;
    END
  END di[1017]
  PIN di[1018]
    DIRECTION INOUT ;
    USE SIGNAL ;
    PORT
      LAYER M4 ;
        RECT 0.048 51.264 0.240 51.288 ;
    END
  END di[1018]
  PIN di[1019]
    DIRECTION INOUT ;
    USE SIGNAL ;
    PORT
      LAYER M4 ;
        RECT 0.048 51.312 0.240 51.336 ;
    END
  END di[1019]
  PIN di[1020]
    DIRECTION INOUT ;
    USE SIGNAL ;
    PORT
      LAYER M4 ;
        RECT 0.048 51.360 0.240 51.384 ;
    END
  END di[1020]
  PIN di[1021]
    DIRECTION INOUT ;
    USE SIGNAL ;
    PORT
      LAYER M4 ;
        RECT 0.048 51.408 0.240 51.432 ;
    END
  END di[1021]
  PIN di[1022]
    DIRECTION INOUT ;
    USE SIGNAL ;
    PORT
      LAYER M4 ;
        RECT 0.048 51.456 0.240 51.480 ;
    END
  END di[1022]
  PIN di[1023]
    DIRECTION INOUT ;
    USE SIGNAL ;
    PORT
      LAYER M4 ;
        RECT 0.048 51.504 0.240 51.528 ;
    END
  END di[1023]
  PIN dq[0]
    DIRECTION INOUT ;
    USE SIGNAL ;
    PORT
      LAYER M4 ;
        RECT 17.016 2.400 17.208 2.424 ;
    END
  END dq[0]
  PIN dq[1]
    DIRECTION INOUT ;
    USE SIGNAL ;
    PORT
      LAYER M4 ;
        RECT 17.016 2.448 17.208 2.472 ;
    END
  END dq[1]
  PIN dq[2]
    DIRECTION INOUT ;
    USE SIGNAL ;
    PORT
      LAYER M4 ;
        RECT 17.016 2.496 17.208 2.520 ;
    END
  END dq[2]
  PIN dq[3]
    DIRECTION INOUT ;
    USE SIGNAL ;
    PORT
      LAYER M4 ;
        RECT 17.016 2.544 17.208 2.568 ;
    END
  END dq[3]
  PIN dq[4]
    DIRECTION INOUT ;
    USE SIGNAL ;
    PORT
      LAYER M4 ;
        RECT 17.016 2.592 17.208 2.616 ;
    END
  END dq[4]
  PIN dq[5]
    DIRECTION INOUT ;
    USE SIGNAL ;
    PORT
      LAYER M4 ;
        RECT 17.016 2.640 17.208 2.664 ;
    END
  END dq[5]
  PIN dq[6]
    DIRECTION INOUT ;
    USE SIGNAL ;
    PORT
      LAYER M4 ;
        RECT 17.016 2.688 17.208 2.712 ;
    END
  END dq[6]
  PIN dq[7]
    DIRECTION INOUT ;
    USE SIGNAL ;
    PORT
      LAYER M4 ;
        RECT 17.016 2.736 17.208 2.760 ;
    END
  END dq[7]
  PIN dq[8]
    DIRECTION INOUT ;
    USE SIGNAL ;
    PORT
      LAYER M4 ;
        RECT 17.016 2.784 17.208 2.808 ;
    END
  END dq[8]
  PIN dq[9]
    DIRECTION INOUT ;
    USE SIGNAL ;
    PORT
      LAYER M4 ;
        RECT 17.016 2.832 17.208 2.856 ;
    END
  END dq[9]
  PIN dq[10]
    DIRECTION INOUT ;
    USE SIGNAL ;
    PORT
      LAYER M4 ;
        RECT 17.016 2.880 17.208 2.904 ;
    END
  END dq[10]
  PIN dq[11]
    DIRECTION INOUT ;
    USE SIGNAL ;
    PORT
      LAYER M4 ;
        RECT 17.016 2.928 17.208 2.952 ;
    END
  END dq[11]
  PIN dq[12]
    DIRECTION INOUT ;
    USE SIGNAL ;
    PORT
      LAYER M4 ;
        RECT 17.016 2.976 17.208 3.000 ;
    END
  END dq[12]
  PIN dq[13]
    DIRECTION INOUT ;
    USE SIGNAL ;
    PORT
      LAYER M4 ;
        RECT 17.016 3.024 17.208 3.048 ;
    END
  END dq[13]
  PIN dq[14]
    DIRECTION INOUT ;
    USE SIGNAL ;
    PORT
      LAYER M4 ;
        RECT 17.016 3.072 17.208 3.096 ;
    END
  END dq[14]
  PIN dq[15]
    DIRECTION INOUT ;
    USE SIGNAL ;
    PORT
      LAYER M4 ;
        RECT 17.016 3.120 17.208 3.144 ;
    END
  END dq[15]
  PIN dq[16]
    DIRECTION INOUT ;
    USE SIGNAL ;
    PORT
      LAYER M4 ;
        RECT 17.016 3.168 17.208 3.192 ;
    END
  END dq[16]
  PIN dq[17]
    DIRECTION INOUT ;
    USE SIGNAL ;
    PORT
      LAYER M4 ;
        RECT 17.016 3.216 17.208 3.240 ;
    END
  END dq[17]
  PIN dq[18]
    DIRECTION INOUT ;
    USE SIGNAL ;
    PORT
      LAYER M4 ;
        RECT 17.016 3.264 17.208 3.288 ;
    END
  END dq[18]
  PIN dq[19]
    DIRECTION INOUT ;
    USE SIGNAL ;
    PORT
      LAYER M4 ;
        RECT 17.016 3.312 17.208 3.336 ;
    END
  END dq[19]
  PIN dq[20]
    DIRECTION INOUT ;
    USE SIGNAL ;
    PORT
      LAYER M4 ;
        RECT 17.016 3.360 17.208 3.384 ;
    END
  END dq[20]
  PIN dq[21]
    DIRECTION INOUT ;
    USE SIGNAL ;
    PORT
      LAYER M4 ;
        RECT 17.016 3.408 17.208 3.432 ;
    END
  END dq[21]
  PIN dq[22]
    DIRECTION INOUT ;
    USE SIGNAL ;
    PORT
      LAYER M4 ;
        RECT 17.016 3.456 17.208 3.480 ;
    END
  END dq[22]
  PIN dq[23]
    DIRECTION INOUT ;
    USE SIGNAL ;
    PORT
      LAYER M4 ;
        RECT 17.016 3.504 17.208 3.528 ;
    END
  END dq[23]
  PIN dq[24]
    DIRECTION INOUT ;
    USE SIGNAL ;
    PORT
      LAYER M4 ;
        RECT 17.016 3.552 17.208 3.576 ;
    END
  END dq[24]
  PIN dq[25]
    DIRECTION INOUT ;
    USE SIGNAL ;
    PORT
      LAYER M4 ;
        RECT 17.016 3.600 17.208 3.624 ;
    END
  END dq[25]
  PIN dq[26]
    DIRECTION INOUT ;
    USE SIGNAL ;
    PORT
      LAYER M4 ;
        RECT 17.016 3.648 17.208 3.672 ;
    END
  END dq[26]
  PIN dq[27]
    DIRECTION INOUT ;
    USE SIGNAL ;
    PORT
      LAYER M4 ;
        RECT 17.016 3.696 17.208 3.720 ;
    END
  END dq[27]
  PIN dq[28]
    DIRECTION INOUT ;
    USE SIGNAL ;
    PORT
      LAYER M4 ;
        RECT 17.016 3.744 17.208 3.768 ;
    END
  END dq[28]
  PIN dq[29]
    DIRECTION INOUT ;
    USE SIGNAL ;
    PORT
      LAYER M4 ;
        RECT 17.016 3.792 17.208 3.816 ;
    END
  END dq[29]
  PIN dq[30]
    DIRECTION INOUT ;
    USE SIGNAL ;
    PORT
      LAYER M4 ;
        RECT 17.016 3.840 17.208 3.864 ;
    END
  END dq[30]
  PIN dq[31]
    DIRECTION INOUT ;
    USE SIGNAL ;
    PORT
      LAYER M4 ;
        RECT 17.016 3.888 17.208 3.912 ;
    END
  END dq[31]
  PIN dq[32]
    DIRECTION INOUT ;
    USE SIGNAL ;
    PORT
      LAYER M4 ;
        RECT 17.016 3.936 17.208 3.960 ;
    END
  END dq[32]
  PIN dq[33]
    DIRECTION INOUT ;
    USE SIGNAL ;
    PORT
      LAYER M4 ;
        RECT 17.016 3.984 17.208 4.008 ;
    END
  END dq[33]
  PIN dq[34]
    DIRECTION INOUT ;
    USE SIGNAL ;
    PORT
      LAYER M4 ;
        RECT 17.016 4.032 17.208 4.056 ;
    END
  END dq[34]
  PIN dq[35]
    DIRECTION INOUT ;
    USE SIGNAL ;
    PORT
      LAYER M4 ;
        RECT 17.016 4.080 17.208 4.104 ;
    END
  END dq[35]
  PIN dq[36]
    DIRECTION INOUT ;
    USE SIGNAL ;
    PORT
      LAYER M4 ;
        RECT 17.016 4.128 17.208 4.152 ;
    END
  END dq[36]
  PIN dq[37]
    DIRECTION INOUT ;
    USE SIGNAL ;
    PORT
      LAYER M4 ;
        RECT 17.016 4.176 17.208 4.200 ;
    END
  END dq[37]
  PIN dq[38]
    DIRECTION INOUT ;
    USE SIGNAL ;
    PORT
      LAYER M4 ;
        RECT 17.016 4.224 17.208 4.248 ;
    END
  END dq[38]
  PIN dq[39]
    DIRECTION INOUT ;
    USE SIGNAL ;
    PORT
      LAYER M4 ;
        RECT 17.016 4.272 17.208 4.296 ;
    END
  END dq[39]
  PIN dq[40]
    DIRECTION INOUT ;
    USE SIGNAL ;
    PORT
      LAYER M4 ;
        RECT 17.016 4.320 17.208 4.344 ;
    END
  END dq[40]
  PIN dq[41]
    DIRECTION INOUT ;
    USE SIGNAL ;
    PORT
      LAYER M4 ;
        RECT 17.016 4.368 17.208 4.392 ;
    END
  END dq[41]
  PIN dq[42]
    DIRECTION INOUT ;
    USE SIGNAL ;
    PORT
      LAYER M4 ;
        RECT 17.016 4.416 17.208 4.440 ;
    END
  END dq[42]
  PIN dq[43]
    DIRECTION INOUT ;
    USE SIGNAL ;
    PORT
      LAYER M4 ;
        RECT 17.016 4.464 17.208 4.488 ;
    END
  END dq[43]
  PIN dq[44]
    DIRECTION INOUT ;
    USE SIGNAL ;
    PORT
      LAYER M4 ;
        RECT 17.016 4.512 17.208 4.536 ;
    END
  END dq[44]
  PIN dq[45]
    DIRECTION INOUT ;
    USE SIGNAL ;
    PORT
      LAYER M4 ;
        RECT 17.016 4.560 17.208 4.584 ;
    END
  END dq[45]
  PIN dq[46]
    DIRECTION INOUT ;
    USE SIGNAL ;
    PORT
      LAYER M4 ;
        RECT 17.016 4.608 17.208 4.632 ;
    END
  END dq[46]
  PIN dq[47]
    DIRECTION INOUT ;
    USE SIGNAL ;
    PORT
      LAYER M4 ;
        RECT 17.016 4.656 17.208 4.680 ;
    END
  END dq[47]
  PIN dq[48]
    DIRECTION INOUT ;
    USE SIGNAL ;
    PORT
      LAYER M4 ;
        RECT 17.016 4.704 17.208 4.728 ;
    END
  END dq[48]
  PIN dq[49]
    DIRECTION INOUT ;
    USE SIGNAL ;
    PORT
      LAYER M4 ;
        RECT 17.016 4.752 17.208 4.776 ;
    END
  END dq[49]
  PIN dq[50]
    DIRECTION INOUT ;
    USE SIGNAL ;
    PORT
      LAYER M4 ;
        RECT 17.016 4.800 17.208 4.824 ;
    END
  END dq[50]
  PIN dq[51]
    DIRECTION INOUT ;
    USE SIGNAL ;
    PORT
      LAYER M4 ;
        RECT 17.016 4.848 17.208 4.872 ;
    END
  END dq[51]
  PIN dq[52]
    DIRECTION INOUT ;
    USE SIGNAL ;
    PORT
      LAYER M4 ;
        RECT 17.016 4.896 17.208 4.920 ;
    END
  END dq[52]
  PIN dq[53]
    DIRECTION INOUT ;
    USE SIGNAL ;
    PORT
      LAYER M4 ;
        RECT 17.016 4.944 17.208 4.968 ;
    END
  END dq[53]
  PIN dq[54]
    DIRECTION INOUT ;
    USE SIGNAL ;
    PORT
      LAYER M4 ;
        RECT 17.016 4.992 17.208 5.016 ;
    END
  END dq[54]
  PIN dq[55]
    DIRECTION INOUT ;
    USE SIGNAL ;
    PORT
      LAYER M4 ;
        RECT 17.016 5.040 17.208 5.064 ;
    END
  END dq[55]
  PIN dq[56]
    DIRECTION INOUT ;
    USE SIGNAL ;
    PORT
      LAYER M4 ;
        RECT 17.016 5.088 17.208 5.112 ;
    END
  END dq[56]
  PIN dq[57]
    DIRECTION INOUT ;
    USE SIGNAL ;
    PORT
      LAYER M4 ;
        RECT 17.016 5.136 17.208 5.160 ;
    END
  END dq[57]
  PIN dq[58]
    DIRECTION INOUT ;
    USE SIGNAL ;
    PORT
      LAYER M4 ;
        RECT 17.016 5.184 17.208 5.208 ;
    END
  END dq[58]
  PIN dq[59]
    DIRECTION INOUT ;
    USE SIGNAL ;
    PORT
      LAYER M4 ;
        RECT 17.016 5.232 17.208 5.256 ;
    END
  END dq[59]
  PIN dq[60]
    DIRECTION INOUT ;
    USE SIGNAL ;
    PORT
      LAYER M4 ;
        RECT 17.016 5.280 17.208 5.304 ;
    END
  END dq[60]
  PIN dq[61]
    DIRECTION INOUT ;
    USE SIGNAL ;
    PORT
      LAYER M4 ;
        RECT 17.016 5.328 17.208 5.352 ;
    END
  END dq[61]
  PIN dq[62]
    DIRECTION INOUT ;
    USE SIGNAL ;
    PORT
      LAYER M4 ;
        RECT 17.016 5.376 17.208 5.400 ;
    END
  END dq[62]
  PIN dq[63]
    DIRECTION INOUT ;
    USE SIGNAL ;
    PORT
      LAYER M4 ;
        RECT 17.016 5.424 17.208 5.448 ;
    END
  END dq[63]
  PIN dq[64]
    DIRECTION INOUT ;
    USE SIGNAL ;
    PORT
      LAYER M4 ;
        RECT 17.016 5.472 17.208 5.496 ;
    END
  END dq[64]
  PIN dq[65]
    DIRECTION INOUT ;
    USE SIGNAL ;
    PORT
      LAYER M4 ;
        RECT 17.016 5.520 17.208 5.544 ;
    END
  END dq[65]
  PIN dq[66]
    DIRECTION INOUT ;
    USE SIGNAL ;
    PORT
      LAYER M4 ;
        RECT 17.016 5.568 17.208 5.592 ;
    END
  END dq[66]
  PIN dq[67]
    DIRECTION INOUT ;
    USE SIGNAL ;
    PORT
      LAYER M4 ;
        RECT 17.016 5.616 17.208 5.640 ;
    END
  END dq[67]
  PIN dq[68]
    DIRECTION INOUT ;
    USE SIGNAL ;
    PORT
      LAYER M4 ;
        RECT 17.016 5.664 17.208 5.688 ;
    END
  END dq[68]
  PIN dq[69]
    DIRECTION INOUT ;
    USE SIGNAL ;
    PORT
      LAYER M4 ;
        RECT 17.016 5.712 17.208 5.736 ;
    END
  END dq[69]
  PIN dq[70]
    DIRECTION INOUT ;
    USE SIGNAL ;
    PORT
      LAYER M4 ;
        RECT 17.016 5.760 17.208 5.784 ;
    END
  END dq[70]
  PIN dq[71]
    DIRECTION INOUT ;
    USE SIGNAL ;
    PORT
      LAYER M4 ;
        RECT 17.016 5.808 17.208 5.832 ;
    END
  END dq[71]
  PIN dq[72]
    DIRECTION INOUT ;
    USE SIGNAL ;
    PORT
      LAYER M4 ;
        RECT 17.016 5.856 17.208 5.880 ;
    END
  END dq[72]
  PIN dq[73]
    DIRECTION INOUT ;
    USE SIGNAL ;
    PORT
      LAYER M4 ;
        RECT 17.016 5.904 17.208 5.928 ;
    END
  END dq[73]
  PIN dq[74]
    DIRECTION INOUT ;
    USE SIGNAL ;
    PORT
      LAYER M4 ;
        RECT 17.016 5.952 17.208 5.976 ;
    END
  END dq[74]
  PIN dq[75]
    DIRECTION INOUT ;
    USE SIGNAL ;
    PORT
      LAYER M4 ;
        RECT 17.016 6.000 17.208 6.024 ;
    END
  END dq[75]
  PIN dq[76]
    DIRECTION INOUT ;
    USE SIGNAL ;
    PORT
      LAYER M4 ;
        RECT 17.016 6.048 17.208 6.072 ;
    END
  END dq[76]
  PIN dq[77]
    DIRECTION INOUT ;
    USE SIGNAL ;
    PORT
      LAYER M4 ;
        RECT 17.016 6.096 17.208 6.120 ;
    END
  END dq[77]
  PIN dq[78]
    DIRECTION INOUT ;
    USE SIGNAL ;
    PORT
      LAYER M4 ;
        RECT 17.016 6.144 17.208 6.168 ;
    END
  END dq[78]
  PIN dq[79]
    DIRECTION INOUT ;
    USE SIGNAL ;
    PORT
      LAYER M4 ;
        RECT 17.016 6.192 17.208 6.216 ;
    END
  END dq[79]
  PIN dq[80]
    DIRECTION INOUT ;
    USE SIGNAL ;
    PORT
      LAYER M4 ;
        RECT 17.016 6.240 17.208 6.264 ;
    END
  END dq[80]
  PIN dq[81]
    DIRECTION INOUT ;
    USE SIGNAL ;
    PORT
      LAYER M4 ;
        RECT 17.016 6.288 17.208 6.312 ;
    END
  END dq[81]
  PIN dq[82]
    DIRECTION INOUT ;
    USE SIGNAL ;
    PORT
      LAYER M4 ;
        RECT 17.016 6.336 17.208 6.360 ;
    END
  END dq[82]
  PIN dq[83]
    DIRECTION INOUT ;
    USE SIGNAL ;
    PORT
      LAYER M4 ;
        RECT 17.016 6.384 17.208 6.408 ;
    END
  END dq[83]
  PIN dq[84]
    DIRECTION INOUT ;
    USE SIGNAL ;
    PORT
      LAYER M4 ;
        RECT 17.016 6.432 17.208 6.456 ;
    END
  END dq[84]
  PIN dq[85]
    DIRECTION INOUT ;
    USE SIGNAL ;
    PORT
      LAYER M4 ;
        RECT 17.016 6.480 17.208 6.504 ;
    END
  END dq[85]
  PIN dq[86]
    DIRECTION INOUT ;
    USE SIGNAL ;
    PORT
      LAYER M4 ;
        RECT 17.016 6.528 17.208 6.552 ;
    END
  END dq[86]
  PIN dq[87]
    DIRECTION INOUT ;
    USE SIGNAL ;
    PORT
      LAYER M4 ;
        RECT 17.016 6.576 17.208 6.600 ;
    END
  END dq[87]
  PIN dq[88]
    DIRECTION INOUT ;
    USE SIGNAL ;
    PORT
      LAYER M4 ;
        RECT 17.016 6.624 17.208 6.648 ;
    END
  END dq[88]
  PIN dq[89]
    DIRECTION INOUT ;
    USE SIGNAL ;
    PORT
      LAYER M4 ;
        RECT 17.016 6.672 17.208 6.696 ;
    END
  END dq[89]
  PIN dq[90]
    DIRECTION INOUT ;
    USE SIGNAL ;
    PORT
      LAYER M4 ;
        RECT 17.016 6.720 17.208 6.744 ;
    END
  END dq[90]
  PIN dq[91]
    DIRECTION INOUT ;
    USE SIGNAL ;
    PORT
      LAYER M4 ;
        RECT 17.016 6.768 17.208 6.792 ;
    END
  END dq[91]
  PIN dq[92]
    DIRECTION INOUT ;
    USE SIGNAL ;
    PORT
      LAYER M4 ;
        RECT 17.016 6.816 17.208 6.840 ;
    END
  END dq[92]
  PIN dq[93]
    DIRECTION INOUT ;
    USE SIGNAL ;
    PORT
      LAYER M4 ;
        RECT 17.016 6.864 17.208 6.888 ;
    END
  END dq[93]
  PIN dq[94]
    DIRECTION INOUT ;
    USE SIGNAL ;
    PORT
      LAYER M4 ;
        RECT 17.016 6.912 17.208 6.936 ;
    END
  END dq[94]
  PIN dq[95]
    DIRECTION INOUT ;
    USE SIGNAL ;
    PORT
      LAYER M4 ;
        RECT 17.016 6.960 17.208 6.984 ;
    END
  END dq[95]
  PIN dq[96]
    DIRECTION INOUT ;
    USE SIGNAL ;
    PORT
      LAYER M4 ;
        RECT 17.016 7.008 17.208 7.032 ;
    END
  END dq[96]
  PIN dq[97]
    DIRECTION INOUT ;
    USE SIGNAL ;
    PORT
      LAYER M4 ;
        RECT 17.016 7.056 17.208 7.080 ;
    END
  END dq[97]
  PIN dq[98]
    DIRECTION INOUT ;
    USE SIGNAL ;
    PORT
      LAYER M4 ;
        RECT 17.016 7.104 17.208 7.128 ;
    END
  END dq[98]
  PIN dq[99]
    DIRECTION INOUT ;
    USE SIGNAL ;
    PORT
      LAYER M4 ;
        RECT 17.016 7.152 17.208 7.176 ;
    END
  END dq[99]
  PIN dq[100]
    DIRECTION INOUT ;
    USE SIGNAL ;
    PORT
      LAYER M4 ;
        RECT 17.016 7.200 17.208 7.224 ;
    END
  END dq[100]
  PIN dq[101]
    DIRECTION INOUT ;
    USE SIGNAL ;
    PORT
      LAYER M4 ;
        RECT 17.016 7.248 17.208 7.272 ;
    END
  END dq[101]
  PIN dq[102]
    DIRECTION INOUT ;
    USE SIGNAL ;
    PORT
      LAYER M4 ;
        RECT 17.016 7.296 17.208 7.320 ;
    END
  END dq[102]
  PIN dq[103]
    DIRECTION INOUT ;
    USE SIGNAL ;
    PORT
      LAYER M4 ;
        RECT 17.016 7.344 17.208 7.368 ;
    END
  END dq[103]
  PIN dq[104]
    DIRECTION INOUT ;
    USE SIGNAL ;
    PORT
      LAYER M4 ;
        RECT 17.016 7.392 17.208 7.416 ;
    END
  END dq[104]
  PIN dq[105]
    DIRECTION INOUT ;
    USE SIGNAL ;
    PORT
      LAYER M4 ;
        RECT 17.016 7.440 17.208 7.464 ;
    END
  END dq[105]
  PIN dq[106]
    DIRECTION INOUT ;
    USE SIGNAL ;
    PORT
      LAYER M4 ;
        RECT 17.016 7.488 17.208 7.512 ;
    END
  END dq[106]
  PIN dq[107]
    DIRECTION INOUT ;
    USE SIGNAL ;
    PORT
      LAYER M4 ;
        RECT 17.016 7.536 17.208 7.560 ;
    END
  END dq[107]
  PIN dq[108]
    DIRECTION INOUT ;
    USE SIGNAL ;
    PORT
      LAYER M4 ;
        RECT 17.016 7.584 17.208 7.608 ;
    END
  END dq[108]
  PIN dq[109]
    DIRECTION INOUT ;
    USE SIGNAL ;
    PORT
      LAYER M4 ;
        RECT 17.016 7.632 17.208 7.656 ;
    END
  END dq[109]
  PIN dq[110]
    DIRECTION INOUT ;
    USE SIGNAL ;
    PORT
      LAYER M4 ;
        RECT 17.016 7.680 17.208 7.704 ;
    END
  END dq[110]
  PIN dq[111]
    DIRECTION INOUT ;
    USE SIGNAL ;
    PORT
      LAYER M4 ;
        RECT 17.016 7.728 17.208 7.752 ;
    END
  END dq[111]
  PIN dq[112]
    DIRECTION INOUT ;
    USE SIGNAL ;
    PORT
      LAYER M4 ;
        RECT 17.016 7.776 17.208 7.800 ;
    END
  END dq[112]
  PIN dq[113]
    DIRECTION INOUT ;
    USE SIGNAL ;
    PORT
      LAYER M4 ;
        RECT 17.016 7.824 17.208 7.848 ;
    END
  END dq[113]
  PIN dq[114]
    DIRECTION INOUT ;
    USE SIGNAL ;
    PORT
      LAYER M4 ;
        RECT 17.016 7.872 17.208 7.896 ;
    END
  END dq[114]
  PIN dq[115]
    DIRECTION INOUT ;
    USE SIGNAL ;
    PORT
      LAYER M4 ;
        RECT 17.016 7.920 17.208 7.944 ;
    END
  END dq[115]
  PIN dq[116]
    DIRECTION INOUT ;
    USE SIGNAL ;
    PORT
      LAYER M4 ;
        RECT 17.016 7.968 17.208 7.992 ;
    END
  END dq[116]
  PIN dq[117]
    DIRECTION INOUT ;
    USE SIGNAL ;
    PORT
      LAYER M4 ;
        RECT 17.016 8.016 17.208 8.040 ;
    END
  END dq[117]
  PIN dq[118]
    DIRECTION INOUT ;
    USE SIGNAL ;
    PORT
      LAYER M4 ;
        RECT 17.016 8.064 17.208 8.088 ;
    END
  END dq[118]
  PIN dq[119]
    DIRECTION INOUT ;
    USE SIGNAL ;
    PORT
      LAYER M4 ;
        RECT 17.016 8.112 17.208 8.136 ;
    END
  END dq[119]
  PIN dq[120]
    DIRECTION INOUT ;
    USE SIGNAL ;
    PORT
      LAYER M4 ;
        RECT 17.016 8.160 17.208 8.184 ;
    END
  END dq[120]
  PIN dq[121]
    DIRECTION INOUT ;
    USE SIGNAL ;
    PORT
      LAYER M4 ;
        RECT 17.016 8.208 17.208 8.232 ;
    END
  END dq[121]
  PIN dq[122]
    DIRECTION INOUT ;
    USE SIGNAL ;
    PORT
      LAYER M4 ;
        RECT 17.016 8.256 17.208 8.280 ;
    END
  END dq[122]
  PIN dq[123]
    DIRECTION INOUT ;
    USE SIGNAL ;
    PORT
      LAYER M4 ;
        RECT 17.016 8.304 17.208 8.328 ;
    END
  END dq[123]
  PIN dq[124]
    DIRECTION INOUT ;
    USE SIGNAL ;
    PORT
      LAYER M4 ;
        RECT 17.016 8.352 17.208 8.376 ;
    END
  END dq[124]
  PIN dq[125]
    DIRECTION INOUT ;
    USE SIGNAL ;
    PORT
      LAYER M4 ;
        RECT 17.016 8.400 17.208 8.424 ;
    END
  END dq[125]
  PIN dq[126]
    DIRECTION INOUT ;
    USE SIGNAL ;
    PORT
      LAYER M4 ;
        RECT 17.016 8.448 17.208 8.472 ;
    END
  END dq[126]
  PIN dq[127]
    DIRECTION INOUT ;
    USE SIGNAL ;
    PORT
      LAYER M4 ;
        RECT 17.016 8.496 17.208 8.520 ;
    END
  END dq[127]
  PIN dq[128]
    DIRECTION INOUT ;
    USE SIGNAL ;
    PORT
      LAYER M4 ;
        RECT 17.016 8.544 17.208 8.568 ;
    END
  END dq[128]
  PIN dq[129]
    DIRECTION INOUT ;
    USE SIGNAL ;
    PORT
      LAYER M4 ;
        RECT 17.016 8.592 17.208 8.616 ;
    END
  END dq[129]
  PIN dq[130]
    DIRECTION INOUT ;
    USE SIGNAL ;
    PORT
      LAYER M4 ;
        RECT 17.016 8.640 17.208 8.664 ;
    END
  END dq[130]
  PIN dq[131]
    DIRECTION INOUT ;
    USE SIGNAL ;
    PORT
      LAYER M4 ;
        RECT 17.016 8.688 17.208 8.712 ;
    END
  END dq[131]
  PIN dq[132]
    DIRECTION INOUT ;
    USE SIGNAL ;
    PORT
      LAYER M4 ;
        RECT 17.016 8.736 17.208 8.760 ;
    END
  END dq[132]
  PIN dq[133]
    DIRECTION INOUT ;
    USE SIGNAL ;
    PORT
      LAYER M4 ;
        RECT 17.016 8.784 17.208 8.808 ;
    END
  END dq[133]
  PIN dq[134]
    DIRECTION INOUT ;
    USE SIGNAL ;
    PORT
      LAYER M4 ;
        RECT 17.016 8.832 17.208 8.856 ;
    END
  END dq[134]
  PIN dq[135]
    DIRECTION INOUT ;
    USE SIGNAL ;
    PORT
      LAYER M4 ;
        RECT 17.016 8.880 17.208 8.904 ;
    END
  END dq[135]
  PIN dq[136]
    DIRECTION INOUT ;
    USE SIGNAL ;
    PORT
      LAYER M4 ;
        RECT 17.016 8.928 17.208 8.952 ;
    END
  END dq[136]
  PIN dq[137]
    DIRECTION INOUT ;
    USE SIGNAL ;
    PORT
      LAYER M4 ;
        RECT 17.016 8.976 17.208 9.000 ;
    END
  END dq[137]
  PIN dq[138]
    DIRECTION INOUT ;
    USE SIGNAL ;
    PORT
      LAYER M4 ;
        RECT 17.016 9.024 17.208 9.048 ;
    END
  END dq[138]
  PIN dq[139]
    DIRECTION INOUT ;
    USE SIGNAL ;
    PORT
      LAYER M4 ;
        RECT 17.016 9.072 17.208 9.096 ;
    END
  END dq[139]
  PIN dq[140]
    DIRECTION INOUT ;
    USE SIGNAL ;
    PORT
      LAYER M4 ;
        RECT 17.016 9.120 17.208 9.144 ;
    END
  END dq[140]
  PIN dq[141]
    DIRECTION INOUT ;
    USE SIGNAL ;
    PORT
      LAYER M4 ;
        RECT 17.016 9.168 17.208 9.192 ;
    END
  END dq[141]
  PIN dq[142]
    DIRECTION INOUT ;
    USE SIGNAL ;
    PORT
      LAYER M4 ;
        RECT 17.016 9.216 17.208 9.240 ;
    END
  END dq[142]
  PIN dq[143]
    DIRECTION INOUT ;
    USE SIGNAL ;
    PORT
      LAYER M4 ;
        RECT 17.016 9.264 17.208 9.288 ;
    END
  END dq[143]
  PIN dq[144]
    DIRECTION INOUT ;
    USE SIGNAL ;
    PORT
      LAYER M4 ;
        RECT 17.016 9.312 17.208 9.336 ;
    END
  END dq[144]
  PIN dq[145]
    DIRECTION INOUT ;
    USE SIGNAL ;
    PORT
      LAYER M4 ;
        RECT 17.016 9.360 17.208 9.384 ;
    END
  END dq[145]
  PIN dq[146]
    DIRECTION INOUT ;
    USE SIGNAL ;
    PORT
      LAYER M4 ;
        RECT 17.016 9.408 17.208 9.432 ;
    END
  END dq[146]
  PIN dq[147]
    DIRECTION INOUT ;
    USE SIGNAL ;
    PORT
      LAYER M4 ;
        RECT 17.016 9.456 17.208 9.480 ;
    END
  END dq[147]
  PIN dq[148]
    DIRECTION INOUT ;
    USE SIGNAL ;
    PORT
      LAYER M4 ;
        RECT 17.016 9.504 17.208 9.528 ;
    END
  END dq[148]
  PIN dq[149]
    DIRECTION INOUT ;
    USE SIGNAL ;
    PORT
      LAYER M4 ;
        RECT 17.016 9.552 17.208 9.576 ;
    END
  END dq[149]
  PIN dq[150]
    DIRECTION INOUT ;
    USE SIGNAL ;
    PORT
      LAYER M4 ;
        RECT 17.016 9.600 17.208 9.624 ;
    END
  END dq[150]
  PIN dq[151]
    DIRECTION INOUT ;
    USE SIGNAL ;
    PORT
      LAYER M4 ;
        RECT 17.016 9.648 17.208 9.672 ;
    END
  END dq[151]
  PIN dq[152]
    DIRECTION INOUT ;
    USE SIGNAL ;
    PORT
      LAYER M4 ;
        RECT 17.016 9.696 17.208 9.720 ;
    END
  END dq[152]
  PIN dq[153]
    DIRECTION INOUT ;
    USE SIGNAL ;
    PORT
      LAYER M4 ;
        RECT 17.016 9.744 17.208 9.768 ;
    END
  END dq[153]
  PIN dq[154]
    DIRECTION INOUT ;
    USE SIGNAL ;
    PORT
      LAYER M4 ;
        RECT 17.016 9.792 17.208 9.816 ;
    END
  END dq[154]
  PIN dq[155]
    DIRECTION INOUT ;
    USE SIGNAL ;
    PORT
      LAYER M4 ;
        RECT 17.016 9.840 17.208 9.864 ;
    END
  END dq[155]
  PIN dq[156]
    DIRECTION INOUT ;
    USE SIGNAL ;
    PORT
      LAYER M4 ;
        RECT 17.016 9.888 17.208 9.912 ;
    END
  END dq[156]
  PIN dq[157]
    DIRECTION INOUT ;
    USE SIGNAL ;
    PORT
      LAYER M4 ;
        RECT 17.016 9.936 17.208 9.960 ;
    END
  END dq[157]
  PIN dq[158]
    DIRECTION INOUT ;
    USE SIGNAL ;
    PORT
      LAYER M4 ;
        RECT 17.016 9.984 17.208 10.008 ;
    END
  END dq[158]
  PIN dq[159]
    DIRECTION INOUT ;
    USE SIGNAL ;
    PORT
      LAYER M4 ;
        RECT 17.016 10.032 17.208 10.056 ;
    END
  END dq[159]
  PIN dq[160]
    DIRECTION INOUT ;
    USE SIGNAL ;
    PORT
      LAYER M4 ;
        RECT 17.016 10.080 17.208 10.104 ;
    END
  END dq[160]
  PIN dq[161]
    DIRECTION INOUT ;
    USE SIGNAL ;
    PORT
      LAYER M4 ;
        RECT 17.016 10.128 17.208 10.152 ;
    END
  END dq[161]
  PIN dq[162]
    DIRECTION INOUT ;
    USE SIGNAL ;
    PORT
      LAYER M4 ;
        RECT 17.016 10.176 17.208 10.200 ;
    END
  END dq[162]
  PIN dq[163]
    DIRECTION INOUT ;
    USE SIGNAL ;
    PORT
      LAYER M4 ;
        RECT 17.016 10.224 17.208 10.248 ;
    END
  END dq[163]
  PIN dq[164]
    DIRECTION INOUT ;
    USE SIGNAL ;
    PORT
      LAYER M4 ;
        RECT 17.016 10.272 17.208 10.296 ;
    END
  END dq[164]
  PIN dq[165]
    DIRECTION INOUT ;
    USE SIGNAL ;
    PORT
      LAYER M4 ;
        RECT 17.016 10.320 17.208 10.344 ;
    END
  END dq[165]
  PIN dq[166]
    DIRECTION INOUT ;
    USE SIGNAL ;
    PORT
      LAYER M4 ;
        RECT 17.016 10.368 17.208 10.392 ;
    END
  END dq[166]
  PIN dq[167]
    DIRECTION INOUT ;
    USE SIGNAL ;
    PORT
      LAYER M4 ;
        RECT 17.016 10.416 17.208 10.440 ;
    END
  END dq[167]
  PIN dq[168]
    DIRECTION INOUT ;
    USE SIGNAL ;
    PORT
      LAYER M4 ;
        RECT 17.016 10.464 17.208 10.488 ;
    END
  END dq[168]
  PIN dq[169]
    DIRECTION INOUT ;
    USE SIGNAL ;
    PORT
      LAYER M4 ;
        RECT 17.016 10.512 17.208 10.536 ;
    END
  END dq[169]
  PIN dq[170]
    DIRECTION INOUT ;
    USE SIGNAL ;
    PORT
      LAYER M4 ;
        RECT 17.016 10.560 17.208 10.584 ;
    END
  END dq[170]
  PIN dq[171]
    DIRECTION INOUT ;
    USE SIGNAL ;
    PORT
      LAYER M4 ;
        RECT 17.016 10.608 17.208 10.632 ;
    END
  END dq[171]
  PIN dq[172]
    DIRECTION INOUT ;
    USE SIGNAL ;
    PORT
      LAYER M4 ;
        RECT 17.016 10.656 17.208 10.680 ;
    END
  END dq[172]
  PIN dq[173]
    DIRECTION INOUT ;
    USE SIGNAL ;
    PORT
      LAYER M4 ;
        RECT 17.016 10.704 17.208 10.728 ;
    END
  END dq[173]
  PIN dq[174]
    DIRECTION INOUT ;
    USE SIGNAL ;
    PORT
      LAYER M4 ;
        RECT 17.016 10.752 17.208 10.776 ;
    END
  END dq[174]
  PIN dq[175]
    DIRECTION INOUT ;
    USE SIGNAL ;
    PORT
      LAYER M4 ;
        RECT 17.016 10.800 17.208 10.824 ;
    END
  END dq[175]
  PIN dq[176]
    DIRECTION INOUT ;
    USE SIGNAL ;
    PORT
      LAYER M4 ;
        RECT 17.016 10.848 17.208 10.872 ;
    END
  END dq[176]
  PIN dq[177]
    DIRECTION INOUT ;
    USE SIGNAL ;
    PORT
      LAYER M4 ;
        RECT 17.016 10.896 17.208 10.920 ;
    END
  END dq[177]
  PIN dq[178]
    DIRECTION INOUT ;
    USE SIGNAL ;
    PORT
      LAYER M4 ;
        RECT 17.016 10.944 17.208 10.968 ;
    END
  END dq[178]
  PIN dq[179]
    DIRECTION INOUT ;
    USE SIGNAL ;
    PORT
      LAYER M4 ;
        RECT 17.016 10.992 17.208 11.016 ;
    END
  END dq[179]
  PIN dq[180]
    DIRECTION INOUT ;
    USE SIGNAL ;
    PORT
      LAYER M4 ;
        RECT 17.016 11.040 17.208 11.064 ;
    END
  END dq[180]
  PIN dq[181]
    DIRECTION INOUT ;
    USE SIGNAL ;
    PORT
      LAYER M4 ;
        RECT 17.016 11.088 17.208 11.112 ;
    END
  END dq[181]
  PIN dq[182]
    DIRECTION INOUT ;
    USE SIGNAL ;
    PORT
      LAYER M4 ;
        RECT 17.016 11.136 17.208 11.160 ;
    END
  END dq[182]
  PIN dq[183]
    DIRECTION INOUT ;
    USE SIGNAL ;
    PORT
      LAYER M4 ;
        RECT 17.016 11.184 17.208 11.208 ;
    END
  END dq[183]
  PIN dq[184]
    DIRECTION INOUT ;
    USE SIGNAL ;
    PORT
      LAYER M4 ;
        RECT 17.016 11.232 17.208 11.256 ;
    END
  END dq[184]
  PIN dq[185]
    DIRECTION INOUT ;
    USE SIGNAL ;
    PORT
      LAYER M4 ;
        RECT 17.016 11.280 17.208 11.304 ;
    END
  END dq[185]
  PIN dq[186]
    DIRECTION INOUT ;
    USE SIGNAL ;
    PORT
      LAYER M4 ;
        RECT 17.016 11.328 17.208 11.352 ;
    END
  END dq[186]
  PIN dq[187]
    DIRECTION INOUT ;
    USE SIGNAL ;
    PORT
      LAYER M4 ;
        RECT 17.016 11.376 17.208 11.400 ;
    END
  END dq[187]
  PIN dq[188]
    DIRECTION INOUT ;
    USE SIGNAL ;
    PORT
      LAYER M4 ;
        RECT 17.016 11.424 17.208 11.448 ;
    END
  END dq[188]
  PIN dq[189]
    DIRECTION INOUT ;
    USE SIGNAL ;
    PORT
      LAYER M4 ;
        RECT 17.016 11.472 17.208 11.496 ;
    END
  END dq[189]
  PIN dq[190]
    DIRECTION INOUT ;
    USE SIGNAL ;
    PORT
      LAYER M4 ;
        RECT 17.016 11.520 17.208 11.544 ;
    END
  END dq[190]
  PIN dq[191]
    DIRECTION INOUT ;
    USE SIGNAL ;
    PORT
      LAYER M4 ;
        RECT 17.016 11.568 17.208 11.592 ;
    END
  END dq[191]
  PIN dq[192]
    DIRECTION INOUT ;
    USE SIGNAL ;
    PORT
      LAYER M4 ;
        RECT 17.016 11.616 17.208 11.640 ;
    END
  END dq[192]
  PIN dq[193]
    DIRECTION INOUT ;
    USE SIGNAL ;
    PORT
      LAYER M4 ;
        RECT 17.016 11.664 17.208 11.688 ;
    END
  END dq[193]
  PIN dq[194]
    DIRECTION INOUT ;
    USE SIGNAL ;
    PORT
      LAYER M4 ;
        RECT 17.016 11.712 17.208 11.736 ;
    END
  END dq[194]
  PIN dq[195]
    DIRECTION INOUT ;
    USE SIGNAL ;
    PORT
      LAYER M4 ;
        RECT 17.016 11.760 17.208 11.784 ;
    END
  END dq[195]
  PIN dq[196]
    DIRECTION INOUT ;
    USE SIGNAL ;
    PORT
      LAYER M4 ;
        RECT 17.016 11.808 17.208 11.832 ;
    END
  END dq[196]
  PIN dq[197]
    DIRECTION INOUT ;
    USE SIGNAL ;
    PORT
      LAYER M4 ;
        RECT 17.016 11.856 17.208 11.880 ;
    END
  END dq[197]
  PIN dq[198]
    DIRECTION INOUT ;
    USE SIGNAL ;
    PORT
      LAYER M4 ;
        RECT 17.016 11.904 17.208 11.928 ;
    END
  END dq[198]
  PIN dq[199]
    DIRECTION INOUT ;
    USE SIGNAL ;
    PORT
      LAYER M4 ;
        RECT 17.016 11.952 17.208 11.976 ;
    END
  END dq[199]
  PIN dq[200]
    DIRECTION INOUT ;
    USE SIGNAL ;
    PORT
      LAYER M4 ;
        RECT 17.016 12.000 17.208 12.024 ;
    END
  END dq[200]
  PIN dq[201]
    DIRECTION INOUT ;
    USE SIGNAL ;
    PORT
      LAYER M4 ;
        RECT 17.016 12.048 17.208 12.072 ;
    END
  END dq[201]
  PIN dq[202]
    DIRECTION INOUT ;
    USE SIGNAL ;
    PORT
      LAYER M4 ;
        RECT 17.016 12.096 17.208 12.120 ;
    END
  END dq[202]
  PIN dq[203]
    DIRECTION INOUT ;
    USE SIGNAL ;
    PORT
      LAYER M4 ;
        RECT 17.016 12.144 17.208 12.168 ;
    END
  END dq[203]
  PIN dq[204]
    DIRECTION INOUT ;
    USE SIGNAL ;
    PORT
      LAYER M4 ;
        RECT 17.016 12.192 17.208 12.216 ;
    END
  END dq[204]
  PIN dq[205]
    DIRECTION INOUT ;
    USE SIGNAL ;
    PORT
      LAYER M4 ;
        RECT 17.016 12.240 17.208 12.264 ;
    END
  END dq[205]
  PIN dq[206]
    DIRECTION INOUT ;
    USE SIGNAL ;
    PORT
      LAYER M4 ;
        RECT 17.016 12.288 17.208 12.312 ;
    END
  END dq[206]
  PIN dq[207]
    DIRECTION INOUT ;
    USE SIGNAL ;
    PORT
      LAYER M4 ;
        RECT 17.016 12.336 17.208 12.360 ;
    END
  END dq[207]
  PIN dq[208]
    DIRECTION INOUT ;
    USE SIGNAL ;
    PORT
      LAYER M4 ;
        RECT 17.016 12.384 17.208 12.408 ;
    END
  END dq[208]
  PIN dq[209]
    DIRECTION INOUT ;
    USE SIGNAL ;
    PORT
      LAYER M4 ;
        RECT 17.016 12.432 17.208 12.456 ;
    END
  END dq[209]
  PIN dq[210]
    DIRECTION INOUT ;
    USE SIGNAL ;
    PORT
      LAYER M4 ;
        RECT 17.016 12.480 17.208 12.504 ;
    END
  END dq[210]
  PIN dq[211]
    DIRECTION INOUT ;
    USE SIGNAL ;
    PORT
      LAYER M4 ;
        RECT 17.016 12.528 17.208 12.552 ;
    END
  END dq[211]
  PIN dq[212]
    DIRECTION INOUT ;
    USE SIGNAL ;
    PORT
      LAYER M4 ;
        RECT 17.016 12.576 17.208 12.600 ;
    END
  END dq[212]
  PIN dq[213]
    DIRECTION INOUT ;
    USE SIGNAL ;
    PORT
      LAYER M4 ;
        RECT 17.016 12.624 17.208 12.648 ;
    END
  END dq[213]
  PIN dq[214]
    DIRECTION INOUT ;
    USE SIGNAL ;
    PORT
      LAYER M4 ;
        RECT 17.016 12.672 17.208 12.696 ;
    END
  END dq[214]
  PIN dq[215]
    DIRECTION INOUT ;
    USE SIGNAL ;
    PORT
      LAYER M4 ;
        RECT 17.016 12.720 17.208 12.744 ;
    END
  END dq[215]
  PIN dq[216]
    DIRECTION INOUT ;
    USE SIGNAL ;
    PORT
      LAYER M4 ;
        RECT 17.016 12.768 17.208 12.792 ;
    END
  END dq[216]
  PIN dq[217]
    DIRECTION INOUT ;
    USE SIGNAL ;
    PORT
      LAYER M4 ;
        RECT 17.016 12.816 17.208 12.840 ;
    END
  END dq[217]
  PIN dq[218]
    DIRECTION INOUT ;
    USE SIGNAL ;
    PORT
      LAYER M4 ;
        RECT 17.016 12.864 17.208 12.888 ;
    END
  END dq[218]
  PIN dq[219]
    DIRECTION INOUT ;
    USE SIGNAL ;
    PORT
      LAYER M4 ;
        RECT 17.016 12.912 17.208 12.936 ;
    END
  END dq[219]
  PIN dq[220]
    DIRECTION INOUT ;
    USE SIGNAL ;
    PORT
      LAYER M4 ;
        RECT 17.016 12.960 17.208 12.984 ;
    END
  END dq[220]
  PIN dq[221]
    DIRECTION INOUT ;
    USE SIGNAL ;
    PORT
      LAYER M4 ;
        RECT 17.016 13.008 17.208 13.032 ;
    END
  END dq[221]
  PIN dq[222]
    DIRECTION INOUT ;
    USE SIGNAL ;
    PORT
      LAYER M4 ;
        RECT 17.016 13.056 17.208 13.080 ;
    END
  END dq[222]
  PIN dq[223]
    DIRECTION INOUT ;
    USE SIGNAL ;
    PORT
      LAYER M4 ;
        RECT 17.016 13.104 17.208 13.128 ;
    END
  END dq[223]
  PIN dq[224]
    DIRECTION INOUT ;
    USE SIGNAL ;
    PORT
      LAYER M4 ;
        RECT 17.016 13.152 17.208 13.176 ;
    END
  END dq[224]
  PIN dq[225]
    DIRECTION INOUT ;
    USE SIGNAL ;
    PORT
      LAYER M4 ;
        RECT 17.016 13.200 17.208 13.224 ;
    END
  END dq[225]
  PIN dq[226]
    DIRECTION INOUT ;
    USE SIGNAL ;
    PORT
      LAYER M4 ;
        RECT 17.016 13.248 17.208 13.272 ;
    END
  END dq[226]
  PIN dq[227]
    DIRECTION INOUT ;
    USE SIGNAL ;
    PORT
      LAYER M4 ;
        RECT 17.016 13.296 17.208 13.320 ;
    END
  END dq[227]
  PIN dq[228]
    DIRECTION INOUT ;
    USE SIGNAL ;
    PORT
      LAYER M4 ;
        RECT 17.016 13.344 17.208 13.368 ;
    END
  END dq[228]
  PIN dq[229]
    DIRECTION INOUT ;
    USE SIGNAL ;
    PORT
      LAYER M4 ;
        RECT 17.016 13.392 17.208 13.416 ;
    END
  END dq[229]
  PIN dq[230]
    DIRECTION INOUT ;
    USE SIGNAL ;
    PORT
      LAYER M4 ;
        RECT 17.016 13.440 17.208 13.464 ;
    END
  END dq[230]
  PIN dq[231]
    DIRECTION INOUT ;
    USE SIGNAL ;
    PORT
      LAYER M4 ;
        RECT 17.016 13.488 17.208 13.512 ;
    END
  END dq[231]
  PIN dq[232]
    DIRECTION INOUT ;
    USE SIGNAL ;
    PORT
      LAYER M4 ;
        RECT 17.016 13.536 17.208 13.560 ;
    END
  END dq[232]
  PIN dq[233]
    DIRECTION INOUT ;
    USE SIGNAL ;
    PORT
      LAYER M4 ;
        RECT 17.016 13.584 17.208 13.608 ;
    END
  END dq[233]
  PIN dq[234]
    DIRECTION INOUT ;
    USE SIGNAL ;
    PORT
      LAYER M4 ;
        RECT 17.016 13.632 17.208 13.656 ;
    END
  END dq[234]
  PIN dq[235]
    DIRECTION INOUT ;
    USE SIGNAL ;
    PORT
      LAYER M4 ;
        RECT 17.016 13.680 17.208 13.704 ;
    END
  END dq[235]
  PIN dq[236]
    DIRECTION INOUT ;
    USE SIGNAL ;
    PORT
      LAYER M4 ;
        RECT 17.016 13.728 17.208 13.752 ;
    END
  END dq[236]
  PIN dq[237]
    DIRECTION INOUT ;
    USE SIGNAL ;
    PORT
      LAYER M4 ;
        RECT 17.016 13.776 17.208 13.800 ;
    END
  END dq[237]
  PIN dq[238]
    DIRECTION INOUT ;
    USE SIGNAL ;
    PORT
      LAYER M4 ;
        RECT 17.016 13.824 17.208 13.848 ;
    END
  END dq[238]
  PIN dq[239]
    DIRECTION INOUT ;
    USE SIGNAL ;
    PORT
      LAYER M4 ;
        RECT 17.016 13.872 17.208 13.896 ;
    END
  END dq[239]
  PIN dq[240]
    DIRECTION INOUT ;
    USE SIGNAL ;
    PORT
      LAYER M4 ;
        RECT 17.016 13.920 17.208 13.944 ;
    END
  END dq[240]
  PIN dq[241]
    DIRECTION INOUT ;
    USE SIGNAL ;
    PORT
      LAYER M4 ;
        RECT 17.016 13.968 17.208 13.992 ;
    END
  END dq[241]
  PIN dq[242]
    DIRECTION INOUT ;
    USE SIGNAL ;
    PORT
      LAYER M4 ;
        RECT 17.016 14.016 17.208 14.040 ;
    END
  END dq[242]
  PIN dq[243]
    DIRECTION INOUT ;
    USE SIGNAL ;
    PORT
      LAYER M4 ;
        RECT 17.016 14.064 17.208 14.088 ;
    END
  END dq[243]
  PIN dq[244]
    DIRECTION INOUT ;
    USE SIGNAL ;
    PORT
      LAYER M4 ;
        RECT 17.016 14.112 17.208 14.136 ;
    END
  END dq[244]
  PIN dq[245]
    DIRECTION INOUT ;
    USE SIGNAL ;
    PORT
      LAYER M4 ;
        RECT 17.016 14.160 17.208 14.184 ;
    END
  END dq[245]
  PIN dq[246]
    DIRECTION INOUT ;
    USE SIGNAL ;
    PORT
      LAYER M4 ;
        RECT 17.016 14.208 17.208 14.232 ;
    END
  END dq[246]
  PIN dq[247]
    DIRECTION INOUT ;
    USE SIGNAL ;
    PORT
      LAYER M4 ;
        RECT 17.016 14.256 17.208 14.280 ;
    END
  END dq[247]
  PIN dq[248]
    DIRECTION INOUT ;
    USE SIGNAL ;
    PORT
      LAYER M4 ;
        RECT 17.016 14.304 17.208 14.328 ;
    END
  END dq[248]
  PIN dq[249]
    DIRECTION INOUT ;
    USE SIGNAL ;
    PORT
      LAYER M4 ;
        RECT 17.016 14.352 17.208 14.376 ;
    END
  END dq[249]
  PIN dq[250]
    DIRECTION INOUT ;
    USE SIGNAL ;
    PORT
      LAYER M4 ;
        RECT 17.016 14.400 17.208 14.424 ;
    END
  END dq[250]
  PIN dq[251]
    DIRECTION INOUT ;
    USE SIGNAL ;
    PORT
      LAYER M4 ;
        RECT 17.016 14.448 17.208 14.472 ;
    END
  END dq[251]
  PIN dq[252]
    DIRECTION INOUT ;
    USE SIGNAL ;
    PORT
      LAYER M4 ;
        RECT 17.016 14.496 17.208 14.520 ;
    END
  END dq[252]
  PIN dq[253]
    DIRECTION INOUT ;
    USE SIGNAL ;
    PORT
      LAYER M4 ;
        RECT 17.016 14.544 17.208 14.568 ;
    END
  END dq[253]
  PIN dq[254]
    DIRECTION INOUT ;
    USE SIGNAL ;
    PORT
      LAYER M4 ;
        RECT 17.016 14.592 17.208 14.616 ;
    END
  END dq[254]
  PIN dq[255]
    DIRECTION INOUT ;
    USE SIGNAL ;
    PORT
      LAYER M4 ;
        RECT 17.016 14.640 17.208 14.664 ;
    END
  END dq[255]
  PIN dq[256]
    DIRECTION INOUT ;
    USE SIGNAL ;
    PORT
      LAYER M4 ;
        RECT 17.016 14.688 17.208 14.712 ;
    END
  END dq[256]
  PIN dq[257]
    DIRECTION INOUT ;
    USE SIGNAL ;
    PORT
      LAYER M4 ;
        RECT 17.016 14.736 17.208 14.760 ;
    END
  END dq[257]
  PIN dq[258]
    DIRECTION INOUT ;
    USE SIGNAL ;
    PORT
      LAYER M4 ;
        RECT 17.016 14.784 17.208 14.808 ;
    END
  END dq[258]
  PIN dq[259]
    DIRECTION INOUT ;
    USE SIGNAL ;
    PORT
      LAYER M4 ;
        RECT 17.016 14.832 17.208 14.856 ;
    END
  END dq[259]
  PIN dq[260]
    DIRECTION INOUT ;
    USE SIGNAL ;
    PORT
      LAYER M4 ;
        RECT 17.016 14.880 17.208 14.904 ;
    END
  END dq[260]
  PIN dq[261]
    DIRECTION INOUT ;
    USE SIGNAL ;
    PORT
      LAYER M4 ;
        RECT 17.016 14.928 17.208 14.952 ;
    END
  END dq[261]
  PIN dq[262]
    DIRECTION INOUT ;
    USE SIGNAL ;
    PORT
      LAYER M4 ;
        RECT 17.016 14.976 17.208 15.000 ;
    END
  END dq[262]
  PIN dq[263]
    DIRECTION INOUT ;
    USE SIGNAL ;
    PORT
      LAYER M4 ;
        RECT 17.016 15.024 17.208 15.048 ;
    END
  END dq[263]
  PIN dq[264]
    DIRECTION INOUT ;
    USE SIGNAL ;
    PORT
      LAYER M4 ;
        RECT 17.016 15.072 17.208 15.096 ;
    END
  END dq[264]
  PIN dq[265]
    DIRECTION INOUT ;
    USE SIGNAL ;
    PORT
      LAYER M4 ;
        RECT 17.016 15.120 17.208 15.144 ;
    END
  END dq[265]
  PIN dq[266]
    DIRECTION INOUT ;
    USE SIGNAL ;
    PORT
      LAYER M4 ;
        RECT 17.016 15.168 17.208 15.192 ;
    END
  END dq[266]
  PIN dq[267]
    DIRECTION INOUT ;
    USE SIGNAL ;
    PORT
      LAYER M4 ;
        RECT 17.016 15.216 17.208 15.240 ;
    END
  END dq[267]
  PIN dq[268]
    DIRECTION INOUT ;
    USE SIGNAL ;
    PORT
      LAYER M4 ;
        RECT 17.016 15.264 17.208 15.288 ;
    END
  END dq[268]
  PIN dq[269]
    DIRECTION INOUT ;
    USE SIGNAL ;
    PORT
      LAYER M4 ;
        RECT 17.016 15.312 17.208 15.336 ;
    END
  END dq[269]
  PIN dq[270]
    DIRECTION INOUT ;
    USE SIGNAL ;
    PORT
      LAYER M4 ;
        RECT 17.016 15.360 17.208 15.384 ;
    END
  END dq[270]
  PIN dq[271]
    DIRECTION INOUT ;
    USE SIGNAL ;
    PORT
      LAYER M4 ;
        RECT 17.016 15.408 17.208 15.432 ;
    END
  END dq[271]
  PIN dq[272]
    DIRECTION INOUT ;
    USE SIGNAL ;
    PORT
      LAYER M4 ;
        RECT 17.016 15.456 17.208 15.480 ;
    END
  END dq[272]
  PIN dq[273]
    DIRECTION INOUT ;
    USE SIGNAL ;
    PORT
      LAYER M4 ;
        RECT 17.016 15.504 17.208 15.528 ;
    END
  END dq[273]
  PIN dq[274]
    DIRECTION INOUT ;
    USE SIGNAL ;
    PORT
      LAYER M4 ;
        RECT 17.016 15.552 17.208 15.576 ;
    END
  END dq[274]
  PIN dq[275]
    DIRECTION INOUT ;
    USE SIGNAL ;
    PORT
      LAYER M4 ;
        RECT 17.016 15.600 17.208 15.624 ;
    END
  END dq[275]
  PIN dq[276]
    DIRECTION INOUT ;
    USE SIGNAL ;
    PORT
      LAYER M4 ;
        RECT 17.016 15.648 17.208 15.672 ;
    END
  END dq[276]
  PIN dq[277]
    DIRECTION INOUT ;
    USE SIGNAL ;
    PORT
      LAYER M4 ;
        RECT 17.016 15.696 17.208 15.720 ;
    END
  END dq[277]
  PIN dq[278]
    DIRECTION INOUT ;
    USE SIGNAL ;
    PORT
      LAYER M4 ;
        RECT 17.016 15.744 17.208 15.768 ;
    END
  END dq[278]
  PIN dq[279]
    DIRECTION INOUT ;
    USE SIGNAL ;
    PORT
      LAYER M4 ;
        RECT 17.016 15.792 17.208 15.816 ;
    END
  END dq[279]
  PIN dq[280]
    DIRECTION INOUT ;
    USE SIGNAL ;
    PORT
      LAYER M4 ;
        RECT 17.016 15.840 17.208 15.864 ;
    END
  END dq[280]
  PIN dq[281]
    DIRECTION INOUT ;
    USE SIGNAL ;
    PORT
      LAYER M4 ;
        RECT 17.016 15.888 17.208 15.912 ;
    END
  END dq[281]
  PIN dq[282]
    DIRECTION INOUT ;
    USE SIGNAL ;
    PORT
      LAYER M4 ;
        RECT 17.016 15.936 17.208 15.960 ;
    END
  END dq[282]
  PIN dq[283]
    DIRECTION INOUT ;
    USE SIGNAL ;
    PORT
      LAYER M4 ;
        RECT 17.016 15.984 17.208 16.008 ;
    END
  END dq[283]
  PIN dq[284]
    DIRECTION INOUT ;
    USE SIGNAL ;
    PORT
      LAYER M4 ;
        RECT 17.016 16.032 17.208 16.056 ;
    END
  END dq[284]
  PIN dq[285]
    DIRECTION INOUT ;
    USE SIGNAL ;
    PORT
      LAYER M4 ;
        RECT 17.016 16.080 17.208 16.104 ;
    END
  END dq[285]
  PIN dq[286]
    DIRECTION INOUT ;
    USE SIGNAL ;
    PORT
      LAYER M4 ;
        RECT 17.016 16.128 17.208 16.152 ;
    END
  END dq[286]
  PIN dq[287]
    DIRECTION INOUT ;
    USE SIGNAL ;
    PORT
      LAYER M4 ;
        RECT 17.016 16.176 17.208 16.200 ;
    END
  END dq[287]
  PIN dq[288]
    DIRECTION INOUT ;
    USE SIGNAL ;
    PORT
      LAYER M4 ;
        RECT 17.016 16.224 17.208 16.248 ;
    END
  END dq[288]
  PIN dq[289]
    DIRECTION INOUT ;
    USE SIGNAL ;
    PORT
      LAYER M4 ;
        RECT 17.016 16.272 17.208 16.296 ;
    END
  END dq[289]
  PIN dq[290]
    DIRECTION INOUT ;
    USE SIGNAL ;
    PORT
      LAYER M4 ;
        RECT 17.016 16.320 17.208 16.344 ;
    END
  END dq[290]
  PIN dq[291]
    DIRECTION INOUT ;
    USE SIGNAL ;
    PORT
      LAYER M4 ;
        RECT 17.016 16.368 17.208 16.392 ;
    END
  END dq[291]
  PIN dq[292]
    DIRECTION INOUT ;
    USE SIGNAL ;
    PORT
      LAYER M4 ;
        RECT 17.016 16.416 17.208 16.440 ;
    END
  END dq[292]
  PIN dq[293]
    DIRECTION INOUT ;
    USE SIGNAL ;
    PORT
      LAYER M4 ;
        RECT 17.016 16.464 17.208 16.488 ;
    END
  END dq[293]
  PIN dq[294]
    DIRECTION INOUT ;
    USE SIGNAL ;
    PORT
      LAYER M4 ;
        RECT 17.016 16.512 17.208 16.536 ;
    END
  END dq[294]
  PIN dq[295]
    DIRECTION INOUT ;
    USE SIGNAL ;
    PORT
      LAYER M4 ;
        RECT 17.016 16.560 17.208 16.584 ;
    END
  END dq[295]
  PIN dq[296]
    DIRECTION INOUT ;
    USE SIGNAL ;
    PORT
      LAYER M4 ;
        RECT 17.016 16.608 17.208 16.632 ;
    END
  END dq[296]
  PIN dq[297]
    DIRECTION INOUT ;
    USE SIGNAL ;
    PORT
      LAYER M4 ;
        RECT 17.016 16.656 17.208 16.680 ;
    END
  END dq[297]
  PIN dq[298]
    DIRECTION INOUT ;
    USE SIGNAL ;
    PORT
      LAYER M4 ;
        RECT 17.016 16.704 17.208 16.728 ;
    END
  END dq[298]
  PIN dq[299]
    DIRECTION INOUT ;
    USE SIGNAL ;
    PORT
      LAYER M4 ;
        RECT 17.016 16.752 17.208 16.776 ;
    END
  END dq[299]
  PIN dq[300]
    DIRECTION INOUT ;
    USE SIGNAL ;
    PORT
      LAYER M4 ;
        RECT 17.016 16.800 17.208 16.824 ;
    END
  END dq[300]
  PIN dq[301]
    DIRECTION INOUT ;
    USE SIGNAL ;
    PORT
      LAYER M4 ;
        RECT 17.016 16.848 17.208 16.872 ;
    END
  END dq[301]
  PIN dq[302]
    DIRECTION INOUT ;
    USE SIGNAL ;
    PORT
      LAYER M4 ;
        RECT 17.016 16.896 17.208 16.920 ;
    END
  END dq[302]
  PIN dq[303]
    DIRECTION INOUT ;
    USE SIGNAL ;
    PORT
      LAYER M4 ;
        RECT 17.016 16.944 17.208 16.968 ;
    END
  END dq[303]
  PIN dq[304]
    DIRECTION INOUT ;
    USE SIGNAL ;
    PORT
      LAYER M4 ;
        RECT 17.016 16.992 17.208 17.016 ;
    END
  END dq[304]
  PIN dq[305]
    DIRECTION INOUT ;
    USE SIGNAL ;
    PORT
      LAYER M4 ;
        RECT 17.016 17.040 17.208 17.064 ;
    END
  END dq[305]
  PIN dq[306]
    DIRECTION INOUT ;
    USE SIGNAL ;
    PORT
      LAYER M4 ;
        RECT 17.016 17.088 17.208 17.112 ;
    END
  END dq[306]
  PIN dq[307]
    DIRECTION INOUT ;
    USE SIGNAL ;
    PORT
      LAYER M4 ;
        RECT 17.016 17.136 17.208 17.160 ;
    END
  END dq[307]
  PIN dq[308]
    DIRECTION INOUT ;
    USE SIGNAL ;
    PORT
      LAYER M4 ;
        RECT 17.016 17.184 17.208 17.208 ;
    END
  END dq[308]
  PIN dq[309]
    DIRECTION INOUT ;
    USE SIGNAL ;
    PORT
      LAYER M4 ;
        RECT 17.016 17.232 17.208 17.256 ;
    END
  END dq[309]
  PIN dq[310]
    DIRECTION INOUT ;
    USE SIGNAL ;
    PORT
      LAYER M4 ;
        RECT 17.016 17.280 17.208 17.304 ;
    END
  END dq[310]
  PIN dq[311]
    DIRECTION INOUT ;
    USE SIGNAL ;
    PORT
      LAYER M4 ;
        RECT 17.016 17.328 17.208 17.352 ;
    END
  END dq[311]
  PIN dq[312]
    DIRECTION INOUT ;
    USE SIGNAL ;
    PORT
      LAYER M4 ;
        RECT 17.016 17.376 17.208 17.400 ;
    END
  END dq[312]
  PIN dq[313]
    DIRECTION INOUT ;
    USE SIGNAL ;
    PORT
      LAYER M4 ;
        RECT 17.016 17.424 17.208 17.448 ;
    END
  END dq[313]
  PIN dq[314]
    DIRECTION INOUT ;
    USE SIGNAL ;
    PORT
      LAYER M4 ;
        RECT 17.016 17.472 17.208 17.496 ;
    END
  END dq[314]
  PIN dq[315]
    DIRECTION INOUT ;
    USE SIGNAL ;
    PORT
      LAYER M4 ;
        RECT 17.016 17.520 17.208 17.544 ;
    END
  END dq[315]
  PIN dq[316]
    DIRECTION INOUT ;
    USE SIGNAL ;
    PORT
      LAYER M4 ;
        RECT 17.016 17.568 17.208 17.592 ;
    END
  END dq[316]
  PIN dq[317]
    DIRECTION INOUT ;
    USE SIGNAL ;
    PORT
      LAYER M4 ;
        RECT 17.016 17.616 17.208 17.640 ;
    END
  END dq[317]
  PIN dq[318]
    DIRECTION INOUT ;
    USE SIGNAL ;
    PORT
      LAYER M4 ;
        RECT 17.016 17.664 17.208 17.688 ;
    END
  END dq[318]
  PIN dq[319]
    DIRECTION INOUT ;
    USE SIGNAL ;
    PORT
      LAYER M4 ;
        RECT 17.016 17.712 17.208 17.736 ;
    END
  END dq[319]
  PIN dq[320]
    DIRECTION INOUT ;
    USE SIGNAL ;
    PORT
      LAYER M4 ;
        RECT 17.016 17.760 17.208 17.784 ;
    END
  END dq[320]
  PIN dq[321]
    DIRECTION INOUT ;
    USE SIGNAL ;
    PORT
      LAYER M4 ;
        RECT 17.016 17.808 17.208 17.832 ;
    END
  END dq[321]
  PIN dq[322]
    DIRECTION INOUT ;
    USE SIGNAL ;
    PORT
      LAYER M4 ;
        RECT 17.016 17.856 17.208 17.880 ;
    END
  END dq[322]
  PIN dq[323]
    DIRECTION INOUT ;
    USE SIGNAL ;
    PORT
      LAYER M4 ;
        RECT 17.016 17.904 17.208 17.928 ;
    END
  END dq[323]
  PIN dq[324]
    DIRECTION INOUT ;
    USE SIGNAL ;
    PORT
      LAYER M4 ;
        RECT 17.016 17.952 17.208 17.976 ;
    END
  END dq[324]
  PIN dq[325]
    DIRECTION INOUT ;
    USE SIGNAL ;
    PORT
      LAYER M4 ;
        RECT 17.016 18.000 17.208 18.024 ;
    END
  END dq[325]
  PIN dq[326]
    DIRECTION INOUT ;
    USE SIGNAL ;
    PORT
      LAYER M4 ;
        RECT 17.016 18.048 17.208 18.072 ;
    END
  END dq[326]
  PIN dq[327]
    DIRECTION INOUT ;
    USE SIGNAL ;
    PORT
      LAYER M4 ;
        RECT 17.016 18.096 17.208 18.120 ;
    END
  END dq[327]
  PIN dq[328]
    DIRECTION INOUT ;
    USE SIGNAL ;
    PORT
      LAYER M4 ;
        RECT 17.016 18.144 17.208 18.168 ;
    END
  END dq[328]
  PIN dq[329]
    DIRECTION INOUT ;
    USE SIGNAL ;
    PORT
      LAYER M4 ;
        RECT 17.016 18.192 17.208 18.216 ;
    END
  END dq[329]
  PIN dq[330]
    DIRECTION INOUT ;
    USE SIGNAL ;
    PORT
      LAYER M4 ;
        RECT 17.016 18.240 17.208 18.264 ;
    END
  END dq[330]
  PIN dq[331]
    DIRECTION INOUT ;
    USE SIGNAL ;
    PORT
      LAYER M4 ;
        RECT 17.016 18.288 17.208 18.312 ;
    END
  END dq[331]
  PIN dq[332]
    DIRECTION INOUT ;
    USE SIGNAL ;
    PORT
      LAYER M4 ;
        RECT 17.016 18.336 17.208 18.360 ;
    END
  END dq[332]
  PIN dq[333]
    DIRECTION INOUT ;
    USE SIGNAL ;
    PORT
      LAYER M4 ;
        RECT 17.016 18.384 17.208 18.408 ;
    END
  END dq[333]
  PIN dq[334]
    DIRECTION INOUT ;
    USE SIGNAL ;
    PORT
      LAYER M4 ;
        RECT 17.016 18.432 17.208 18.456 ;
    END
  END dq[334]
  PIN dq[335]
    DIRECTION INOUT ;
    USE SIGNAL ;
    PORT
      LAYER M4 ;
        RECT 17.016 18.480 17.208 18.504 ;
    END
  END dq[335]
  PIN dq[336]
    DIRECTION INOUT ;
    USE SIGNAL ;
    PORT
      LAYER M4 ;
        RECT 17.016 18.528 17.208 18.552 ;
    END
  END dq[336]
  PIN dq[337]
    DIRECTION INOUT ;
    USE SIGNAL ;
    PORT
      LAYER M4 ;
        RECT 17.016 18.576 17.208 18.600 ;
    END
  END dq[337]
  PIN dq[338]
    DIRECTION INOUT ;
    USE SIGNAL ;
    PORT
      LAYER M4 ;
        RECT 17.016 18.624 17.208 18.648 ;
    END
  END dq[338]
  PIN dq[339]
    DIRECTION INOUT ;
    USE SIGNAL ;
    PORT
      LAYER M4 ;
        RECT 17.016 18.672 17.208 18.696 ;
    END
  END dq[339]
  PIN dq[340]
    DIRECTION INOUT ;
    USE SIGNAL ;
    PORT
      LAYER M4 ;
        RECT 17.016 18.720 17.208 18.744 ;
    END
  END dq[340]
  PIN dq[341]
    DIRECTION INOUT ;
    USE SIGNAL ;
    PORT
      LAYER M4 ;
        RECT 17.016 18.768 17.208 18.792 ;
    END
  END dq[341]
  PIN dq[342]
    DIRECTION INOUT ;
    USE SIGNAL ;
    PORT
      LAYER M4 ;
        RECT 17.016 18.816 17.208 18.840 ;
    END
  END dq[342]
  PIN dq[343]
    DIRECTION INOUT ;
    USE SIGNAL ;
    PORT
      LAYER M4 ;
        RECT 17.016 18.864 17.208 18.888 ;
    END
  END dq[343]
  PIN dq[344]
    DIRECTION INOUT ;
    USE SIGNAL ;
    PORT
      LAYER M4 ;
        RECT 17.016 18.912 17.208 18.936 ;
    END
  END dq[344]
  PIN dq[345]
    DIRECTION INOUT ;
    USE SIGNAL ;
    PORT
      LAYER M4 ;
        RECT 17.016 18.960 17.208 18.984 ;
    END
  END dq[345]
  PIN dq[346]
    DIRECTION INOUT ;
    USE SIGNAL ;
    PORT
      LAYER M4 ;
        RECT 17.016 19.008 17.208 19.032 ;
    END
  END dq[346]
  PIN dq[347]
    DIRECTION INOUT ;
    USE SIGNAL ;
    PORT
      LAYER M4 ;
        RECT 17.016 19.056 17.208 19.080 ;
    END
  END dq[347]
  PIN dq[348]
    DIRECTION INOUT ;
    USE SIGNAL ;
    PORT
      LAYER M4 ;
        RECT 17.016 19.104 17.208 19.128 ;
    END
  END dq[348]
  PIN dq[349]
    DIRECTION INOUT ;
    USE SIGNAL ;
    PORT
      LAYER M4 ;
        RECT 17.016 19.152 17.208 19.176 ;
    END
  END dq[349]
  PIN dq[350]
    DIRECTION INOUT ;
    USE SIGNAL ;
    PORT
      LAYER M4 ;
        RECT 17.016 19.200 17.208 19.224 ;
    END
  END dq[350]
  PIN dq[351]
    DIRECTION INOUT ;
    USE SIGNAL ;
    PORT
      LAYER M4 ;
        RECT 17.016 19.248 17.208 19.272 ;
    END
  END dq[351]
  PIN dq[352]
    DIRECTION INOUT ;
    USE SIGNAL ;
    PORT
      LAYER M4 ;
        RECT 17.016 19.296 17.208 19.320 ;
    END
  END dq[352]
  PIN dq[353]
    DIRECTION INOUT ;
    USE SIGNAL ;
    PORT
      LAYER M4 ;
        RECT 17.016 19.344 17.208 19.368 ;
    END
  END dq[353]
  PIN dq[354]
    DIRECTION INOUT ;
    USE SIGNAL ;
    PORT
      LAYER M4 ;
        RECT 17.016 19.392 17.208 19.416 ;
    END
  END dq[354]
  PIN dq[355]
    DIRECTION INOUT ;
    USE SIGNAL ;
    PORT
      LAYER M4 ;
        RECT 17.016 19.440 17.208 19.464 ;
    END
  END dq[355]
  PIN dq[356]
    DIRECTION INOUT ;
    USE SIGNAL ;
    PORT
      LAYER M4 ;
        RECT 17.016 19.488 17.208 19.512 ;
    END
  END dq[356]
  PIN dq[357]
    DIRECTION INOUT ;
    USE SIGNAL ;
    PORT
      LAYER M4 ;
        RECT 17.016 19.536 17.208 19.560 ;
    END
  END dq[357]
  PIN dq[358]
    DIRECTION INOUT ;
    USE SIGNAL ;
    PORT
      LAYER M4 ;
        RECT 17.016 19.584 17.208 19.608 ;
    END
  END dq[358]
  PIN dq[359]
    DIRECTION INOUT ;
    USE SIGNAL ;
    PORT
      LAYER M4 ;
        RECT 17.016 19.632 17.208 19.656 ;
    END
  END dq[359]
  PIN dq[360]
    DIRECTION INOUT ;
    USE SIGNAL ;
    PORT
      LAYER M4 ;
        RECT 17.016 19.680 17.208 19.704 ;
    END
  END dq[360]
  PIN dq[361]
    DIRECTION INOUT ;
    USE SIGNAL ;
    PORT
      LAYER M4 ;
        RECT 17.016 19.728 17.208 19.752 ;
    END
  END dq[361]
  PIN dq[362]
    DIRECTION INOUT ;
    USE SIGNAL ;
    PORT
      LAYER M4 ;
        RECT 17.016 19.776 17.208 19.800 ;
    END
  END dq[362]
  PIN dq[363]
    DIRECTION INOUT ;
    USE SIGNAL ;
    PORT
      LAYER M4 ;
        RECT 17.016 19.824 17.208 19.848 ;
    END
  END dq[363]
  PIN dq[364]
    DIRECTION INOUT ;
    USE SIGNAL ;
    PORT
      LAYER M4 ;
        RECT 17.016 19.872 17.208 19.896 ;
    END
  END dq[364]
  PIN dq[365]
    DIRECTION INOUT ;
    USE SIGNAL ;
    PORT
      LAYER M4 ;
        RECT 17.016 19.920 17.208 19.944 ;
    END
  END dq[365]
  PIN dq[366]
    DIRECTION INOUT ;
    USE SIGNAL ;
    PORT
      LAYER M4 ;
        RECT 17.016 19.968 17.208 19.992 ;
    END
  END dq[366]
  PIN dq[367]
    DIRECTION INOUT ;
    USE SIGNAL ;
    PORT
      LAYER M4 ;
        RECT 17.016 20.016 17.208 20.040 ;
    END
  END dq[367]
  PIN dq[368]
    DIRECTION INOUT ;
    USE SIGNAL ;
    PORT
      LAYER M4 ;
        RECT 17.016 20.064 17.208 20.088 ;
    END
  END dq[368]
  PIN dq[369]
    DIRECTION INOUT ;
    USE SIGNAL ;
    PORT
      LAYER M4 ;
        RECT 17.016 20.112 17.208 20.136 ;
    END
  END dq[369]
  PIN dq[370]
    DIRECTION INOUT ;
    USE SIGNAL ;
    PORT
      LAYER M4 ;
        RECT 17.016 20.160 17.208 20.184 ;
    END
  END dq[370]
  PIN dq[371]
    DIRECTION INOUT ;
    USE SIGNAL ;
    PORT
      LAYER M4 ;
        RECT 17.016 20.208 17.208 20.232 ;
    END
  END dq[371]
  PIN dq[372]
    DIRECTION INOUT ;
    USE SIGNAL ;
    PORT
      LAYER M4 ;
        RECT 17.016 20.256 17.208 20.280 ;
    END
  END dq[372]
  PIN dq[373]
    DIRECTION INOUT ;
    USE SIGNAL ;
    PORT
      LAYER M4 ;
        RECT 17.016 20.304 17.208 20.328 ;
    END
  END dq[373]
  PIN dq[374]
    DIRECTION INOUT ;
    USE SIGNAL ;
    PORT
      LAYER M4 ;
        RECT 17.016 20.352 17.208 20.376 ;
    END
  END dq[374]
  PIN dq[375]
    DIRECTION INOUT ;
    USE SIGNAL ;
    PORT
      LAYER M4 ;
        RECT 17.016 20.400 17.208 20.424 ;
    END
  END dq[375]
  PIN dq[376]
    DIRECTION INOUT ;
    USE SIGNAL ;
    PORT
      LAYER M4 ;
        RECT 17.016 20.448 17.208 20.472 ;
    END
  END dq[376]
  PIN dq[377]
    DIRECTION INOUT ;
    USE SIGNAL ;
    PORT
      LAYER M4 ;
        RECT 17.016 20.496 17.208 20.520 ;
    END
  END dq[377]
  PIN dq[378]
    DIRECTION INOUT ;
    USE SIGNAL ;
    PORT
      LAYER M4 ;
        RECT 17.016 20.544 17.208 20.568 ;
    END
  END dq[378]
  PIN dq[379]
    DIRECTION INOUT ;
    USE SIGNAL ;
    PORT
      LAYER M4 ;
        RECT 17.016 20.592 17.208 20.616 ;
    END
  END dq[379]
  PIN dq[380]
    DIRECTION INOUT ;
    USE SIGNAL ;
    PORT
      LAYER M4 ;
        RECT 17.016 20.640 17.208 20.664 ;
    END
  END dq[380]
  PIN dq[381]
    DIRECTION INOUT ;
    USE SIGNAL ;
    PORT
      LAYER M4 ;
        RECT 17.016 20.688 17.208 20.712 ;
    END
  END dq[381]
  PIN dq[382]
    DIRECTION INOUT ;
    USE SIGNAL ;
    PORT
      LAYER M4 ;
        RECT 17.016 20.736 17.208 20.760 ;
    END
  END dq[382]
  PIN dq[383]
    DIRECTION INOUT ;
    USE SIGNAL ;
    PORT
      LAYER M4 ;
        RECT 17.016 20.784 17.208 20.808 ;
    END
  END dq[383]
  PIN dq[384]
    DIRECTION INOUT ;
    USE SIGNAL ;
    PORT
      LAYER M4 ;
        RECT 17.016 20.832 17.208 20.856 ;
    END
  END dq[384]
  PIN dq[385]
    DIRECTION INOUT ;
    USE SIGNAL ;
    PORT
      LAYER M4 ;
        RECT 17.016 20.880 17.208 20.904 ;
    END
  END dq[385]
  PIN dq[386]
    DIRECTION INOUT ;
    USE SIGNAL ;
    PORT
      LAYER M4 ;
        RECT 17.016 20.928 17.208 20.952 ;
    END
  END dq[386]
  PIN dq[387]
    DIRECTION INOUT ;
    USE SIGNAL ;
    PORT
      LAYER M4 ;
        RECT 17.016 20.976 17.208 21.000 ;
    END
  END dq[387]
  PIN dq[388]
    DIRECTION INOUT ;
    USE SIGNAL ;
    PORT
      LAYER M4 ;
        RECT 17.016 21.024 17.208 21.048 ;
    END
  END dq[388]
  PIN dq[389]
    DIRECTION INOUT ;
    USE SIGNAL ;
    PORT
      LAYER M4 ;
        RECT 17.016 21.072 17.208 21.096 ;
    END
  END dq[389]
  PIN dq[390]
    DIRECTION INOUT ;
    USE SIGNAL ;
    PORT
      LAYER M4 ;
        RECT 17.016 21.120 17.208 21.144 ;
    END
  END dq[390]
  PIN dq[391]
    DIRECTION INOUT ;
    USE SIGNAL ;
    PORT
      LAYER M4 ;
        RECT 17.016 21.168 17.208 21.192 ;
    END
  END dq[391]
  PIN dq[392]
    DIRECTION INOUT ;
    USE SIGNAL ;
    PORT
      LAYER M4 ;
        RECT 17.016 21.216 17.208 21.240 ;
    END
  END dq[392]
  PIN dq[393]
    DIRECTION INOUT ;
    USE SIGNAL ;
    PORT
      LAYER M4 ;
        RECT 17.016 21.264 17.208 21.288 ;
    END
  END dq[393]
  PIN dq[394]
    DIRECTION INOUT ;
    USE SIGNAL ;
    PORT
      LAYER M4 ;
        RECT 17.016 21.312 17.208 21.336 ;
    END
  END dq[394]
  PIN dq[395]
    DIRECTION INOUT ;
    USE SIGNAL ;
    PORT
      LAYER M4 ;
        RECT 17.016 21.360 17.208 21.384 ;
    END
  END dq[395]
  PIN dq[396]
    DIRECTION INOUT ;
    USE SIGNAL ;
    PORT
      LAYER M4 ;
        RECT 17.016 21.408 17.208 21.432 ;
    END
  END dq[396]
  PIN dq[397]
    DIRECTION INOUT ;
    USE SIGNAL ;
    PORT
      LAYER M4 ;
        RECT 17.016 21.456 17.208 21.480 ;
    END
  END dq[397]
  PIN dq[398]
    DIRECTION INOUT ;
    USE SIGNAL ;
    PORT
      LAYER M4 ;
        RECT 17.016 21.504 17.208 21.528 ;
    END
  END dq[398]
  PIN dq[399]
    DIRECTION INOUT ;
    USE SIGNAL ;
    PORT
      LAYER M4 ;
        RECT 17.016 21.552 17.208 21.576 ;
    END
  END dq[399]
  PIN dq[400]
    DIRECTION INOUT ;
    USE SIGNAL ;
    PORT
      LAYER M4 ;
        RECT 17.016 21.600 17.208 21.624 ;
    END
  END dq[400]
  PIN dq[401]
    DIRECTION INOUT ;
    USE SIGNAL ;
    PORT
      LAYER M4 ;
        RECT 17.016 21.648 17.208 21.672 ;
    END
  END dq[401]
  PIN dq[402]
    DIRECTION INOUT ;
    USE SIGNAL ;
    PORT
      LAYER M4 ;
        RECT 17.016 21.696 17.208 21.720 ;
    END
  END dq[402]
  PIN dq[403]
    DIRECTION INOUT ;
    USE SIGNAL ;
    PORT
      LAYER M4 ;
        RECT 17.016 21.744 17.208 21.768 ;
    END
  END dq[403]
  PIN dq[404]
    DIRECTION INOUT ;
    USE SIGNAL ;
    PORT
      LAYER M4 ;
        RECT 17.016 21.792 17.208 21.816 ;
    END
  END dq[404]
  PIN dq[405]
    DIRECTION INOUT ;
    USE SIGNAL ;
    PORT
      LAYER M4 ;
        RECT 17.016 21.840 17.208 21.864 ;
    END
  END dq[405]
  PIN dq[406]
    DIRECTION INOUT ;
    USE SIGNAL ;
    PORT
      LAYER M4 ;
        RECT 17.016 21.888 17.208 21.912 ;
    END
  END dq[406]
  PIN dq[407]
    DIRECTION INOUT ;
    USE SIGNAL ;
    PORT
      LAYER M4 ;
        RECT 17.016 21.936 17.208 21.960 ;
    END
  END dq[407]
  PIN dq[408]
    DIRECTION INOUT ;
    USE SIGNAL ;
    PORT
      LAYER M4 ;
        RECT 17.016 21.984 17.208 22.008 ;
    END
  END dq[408]
  PIN dq[409]
    DIRECTION INOUT ;
    USE SIGNAL ;
    PORT
      LAYER M4 ;
        RECT 17.016 22.032 17.208 22.056 ;
    END
  END dq[409]
  PIN dq[410]
    DIRECTION INOUT ;
    USE SIGNAL ;
    PORT
      LAYER M4 ;
        RECT 17.016 22.080 17.208 22.104 ;
    END
  END dq[410]
  PIN dq[411]
    DIRECTION INOUT ;
    USE SIGNAL ;
    PORT
      LAYER M4 ;
        RECT 17.016 22.128 17.208 22.152 ;
    END
  END dq[411]
  PIN dq[412]
    DIRECTION INOUT ;
    USE SIGNAL ;
    PORT
      LAYER M4 ;
        RECT 17.016 22.176 17.208 22.200 ;
    END
  END dq[412]
  PIN dq[413]
    DIRECTION INOUT ;
    USE SIGNAL ;
    PORT
      LAYER M4 ;
        RECT 17.016 22.224 17.208 22.248 ;
    END
  END dq[413]
  PIN dq[414]
    DIRECTION INOUT ;
    USE SIGNAL ;
    PORT
      LAYER M4 ;
        RECT 17.016 22.272 17.208 22.296 ;
    END
  END dq[414]
  PIN dq[415]
    DIRECTION INOUT ;
    USE SIGNAL ;
    PORT
      LAYER M4 ;
        RECT 17.016 22.320 17.208 22.344 ;
    END
  END dq[415]
  PIN dq[416]
    DIRECTION INOUT ;
    USE SIGNAL ;
    PORT
      LAYER M4 ;
        RECT 17.016 22.368 17.208 22.392 ;
    END
  END dq[416]
  PIN dq[417]
    DIRECTION INOUT ;
    USE SIGNAL ;
    PORT
      LAYER M4 ;
        RECT 17.016 22.416 17.208 22.440 ;
    END
  END dq[417]
  PIN dq[418]
    DIRECTION INOUT ;
    USE SIGNAL ;
    PORT
      LAYER M4 ;
        RECT 17.016 22.464 17.208 22.488 ;
    END
  END dq[418]
  PIN dq[419]
    DIRECTION INOUT ;
    USE SIGNAL ;
    PORT
      LAYER M4 ;
        RECT 17.016 22.512 17.208 22.536 ;
    END
  END dq[419]
  PIN dq[420]
    DIRECTION INOUT ;
    USE SIGNAL ;
    PORT
      LAYER M4 ;
        RECT 17.016 22.560 17.208 22.584 ;
    END
  END dq[420]
  PIN dq[421]
    DIRECTION INOUT ;
    USE SIGNAL ;
    PORT
      LAYER M4 ;
        RECT 17.016 22.608 17.208 22.632 ;
    END
  END dq[421]
  PIN dq[422]
    DIRECTION INOUT ;
    USE SIGNAL ;
    PORT
      LAYER M4 ;
        RECT 17.016 22.656 17.208 22.680 ;
    END
  END dq[422]
  PIN dq[423]
    DIRECTION INOUT ;
    USE SIGNAL ;
    PORT
      LAYER M4 ;
        RECT 17.016 22.704 17.208 22.728 ;
    END
  END dq[423]
  PIN dq[424]
    DIRECTION INOUT ;
    USE SIGNAL ;
    PORT
      LAYER M4 ;
        RECT 17.016 22.752 17.208 22.776 ;
    END
  END dq[424]
  PIN dq[425]
    DIRECTION INOUT ;
    USE SIGNAL ;
    PORT
      LAYER M4 ;
        RECT 17.016 22.800 17.208 22.824 ;
    END
  END dq[425]
  PIN dq[426]
    DIRECTION INOUT ;
    USE SIGNAL ;
    PORT
      LAYER M4 ;
        RECT 17.016 22.848 17.208 22.872 ;
    END
  END dq[426]
  PIN dq[427]
    DIRECTION INOUT ;
    USE SIGNAL ;
    PORT
      LAYER M4 ;
        RECT 17.016 22.896 17.208 22.920 ;
    END
  END dq[427]
  PIN dq[428]
    DIRECTION INOUT ;
    USE SIGNAL ;
    PORT
      LAYER M4 ;
        RECT 17.016 22.944 17.208 22.968 ;
    END
  END dq[428]
  PIN dq[429]
    DIRECTION INOUT ;
    USE SIGNAL ;
    PORT
      LAYER M4 ;
        RECT 17.016 22.992 17.208 23.016 ;
    END
  END dq[429]
  PIN dq[430]
    DIRECTION INOUT ;
    USE SIGNAL ;
    PORT
      LAYER M4 ;
        RECT 17.016 23.040 17.208 23.064 ;
    END
  END dq[430]
  PIN dq[431]
    DIRECTION INOUT ;
    USE SIGNAL ;
    PORT
      LAYER M4 ;
        RECT 17.016 23.088 17.208 23.112 ;
    END
  END dq[431]
  PIN dq[432]
    DIRECTION INOUT ;
    USE SIGNAL ;
    PORT
      LAYER M4 ;
        RECT 17.016 23.136 17.208 23.160 ;
    END
  END dq[432]
  PIN dq[433]
    DIRECTION INOUT ;
    USE SIGNAL ;
    PORT
      LAYER M4 ;
        RECT 17.016 23.184 17.208 23.208 ;
    END
  END dq[433]
  PIN dq[434]
    DIRECTION INOUT ;
    USE SIGNAL ;
    PORT
      LAYER M4 ;
        RECT 17.016 23.232 17.208 23.256 ;
    END
  END dq[434]
  PIN dq[435]
    DIRECTION INOUT ;
    USE SIGNAL ;
    PORT
      LAYER M4 ;
        RECT 17.016 23.280 17.208 23.304 ;
    END
  END dq[435]
  PIN dq[436]
    DIRECTION INOUT ;
    USE SIGNAL ;
    PORT
      LAYER M4 ;
        RECT 17.016 23.328 17.208 23.352 ;
    END
  END dq[436]
  PIN dq[437]
    DIRECTION INOUT ;
    USE SIGNAL ;
    PORT
      LAYER M4 ;
        RECT 17.016 23.376 17.208 23.400 ;
    END
  END dq[437]
  PIN dq[438]
    DIRECTION INOUT ;
    USE SIGNAL ;
    PORT
      LAYER M4 ;
        RECT 17.016 23.424 17.208 23.448 ;
    END
  END dq[438]
  PIN dq[439]
    DIRECTION INOUT ;
    USE SIGNAL ;
    PORT
      LAYER M4 ;
        RECT 17.016 23.472 17.208 23.496 ;
    END
  END dq[439]
  PIN dq[440]
    DIRECTION INOUT ;
    USE SIGNAL ;
    PORT
      LAYER M4 ;
        RECT 17.016 23.520 17.208 23.544 ;
    END
  END dq[440]
  PIN dq[441]
    DIRECTION INOUT ;
    USE SIGNAL ;
    PORT
      LAYER M4 ;
        RECT 17.016 23.568 17.208 23.592 ;
    END
  END dq[441]
  PIN dq[442]
    DIRECTION INOUT ;
    USE SIGNAL ;
    PORT
      LAYER M4 ;
        RECT 17.016 23.616 17.208 23.640 ;
    END
  END dq[442]
  PIN dq[443]
    DIRECTION INOUT ;
    USE SIGNAL ;
    PORT
      LAYER M4 ;
        RECT 17.016 23.664 17.208 23.688 ;
    END
  END dq[443]
  PIN dq[444]
    DIRECTION INOUT ;
    USE SIGNAL ;
    PORT
      LAYER M4 ;
        RECT 17.016 23.712 17.208 23.736 ;
    END
  END dq[444]
  PIN dq[445]
    DIRECTION INOUT ;
    USE SIGNAL ;
    PORT
      LAYER M4 ;
        RECT 17.016 23.760 17.208 23.784 ;
    END
  END dq[445]
  PIN dq[446]
    DIRECTION INOUT ;
    USE SIGNAL ;
    PORT
      LAYER M4 ;
        RECT 17.016 23.808 17.208 23.832 ;
    END
  END dq[446]
  PIN dq[447]
    DIRECTION INOUT ;
    USE SIGNAL ;
    PORT
      LAYER M4 ;
        RECT 17.016 23.856 17.208 23.880 ;
    END
  END dq[447]
  PIN dq[448]
    DIRECTION INOUT ;
    USE SIGNAL ;
    PORT
      LAYER M4 ;
        RECT 17.016 23.904 17.208 23.928 ;
    END
  END dq[448]
  PIN dq[449]
    DIRECTION INOUT ;
    USE SIGNAL ;
    PORT
      LAYER M4 ;
        RECT 17.016 23.952 17.208 23.976 ;
    END
  END dq[449]
  PIN dq[450]
    DIRECTION INOUT ;
    USE SIGNAL ;
    PORT
      LAYER M4 ;
        RECT 17.016 24.000 17.208 24.024 ;
    END
  END dq[450]
  PIN dq[451]
    DIRECTION INOUT ;
    USE SIGNAL ;
    PORT
      LAYER M4 ;
        RECT 17.016 24.048 17.208 24.072 ;
    END
  END dq[451]
  PIN dq[452]
    DIRECTION INOUT ;
    USE SIGNAL ;
    PORT
      LAYER M4 ;
        RECT 17.016 24.096 17.208 24.120 ;
    END
  END dq[452]
  PIN dq[453]
    DIRECTION INOUT ;
    USE SIGNAL ;
    PORT
      LAYER M4 ;
        RECT 17.016 24.144 17.208 24.168 ;
    END
  END dq[453]
  PIN dq[454]
    DIRECTION INOUT ;
    USE SIGNAL ;
    PORT
      LAYER M4 ;
        RECT 17.016 24.192 17.208 24.216 ;
    END
  END dq[454]
  PIN dq[455]
    DIRECTION INOUT ;
    USE SIGNAL ;
    PORT
      LAYER M4 ;
        RECT 17.016 24.240 17.208 24.264 ;
    END
  END dq[455]
  PIN dq[456]
    DIRECTION INOUT ;
    USE SIGNAL ;
    PORT
      LAYER M4 ;
        RECT 17.016 24.288 17.208 24.312 ;
    END
  END dq[456]
  PIN dq[457]
    DIRECTION INOUT ;
    USE SIGNAL ;
    PORT
      LAYER M4 ;
        RECT 17.016 24.336 17.208 24.360 ;
    END
  END dq[457]
  PIN dq[458]
    DIRECTION INOUT ;
    USE SIGNAL ;
    PORT
      LAYER M4 ;
        RECT 17.016 24.384 17.208 24.408 ;
    END
  END dq[458]
  PIN dq[459]
    DIRECTION INOUT ;
    USE SIGNAL ;
    PORT
      LAYER M4 ;
        RECT 17.016 24.432 17.208 24.456 ;
    END
  END dq[459]
  PIN dq[460]
    DIRECTION INOUT ;
    USE SIGNAL ;
    PORT
      LAYER M4 ;
        RECT 17.016 24.480 17.208 24.504 ;
    END
  END dq[460]
  PIN dq[461]
    DIRECTION INOUT ;
    USE SIGNAL ;
    PORT
      LAYER M4 ;
        RECT 17.016 24.528 17.208 24.552 ;
    END
  END dq[461]
  PIN dq[462]
    DIRECTION INOUT ;
    USE SIGNAL ;
    PORT
      LAYER M4 ;
        RECT 17.016 24.576 17.208 24.600 ;
    END
  END dq[462]
  PIN dq[463]
    DIRECTION INOUT ;
    USE SIGNAL ;
    PORT
      LAYER M4 ;
        RECT 17.016 24.624 17.208 24.648 ;
    END
  END dq[463]
  PIN dq[464]
    DIRECTION INOUT ;
    USE SIGNAL ;
    PORT
      LAYER M4 ;
        RECT 17.016 24.672 17.208 24.696 ;
    END
  END dq[464]
  PIN dq[465]
    DIRECTION INOUT ;
    USE SIGNAL ;
    PORT
      LAYER M4 ;
        RECT 17.016 24.720 17.208 24.744 ;
    END
  END dq[465]
  PIN dq[466]
    DIRECTION INOUT ;
    USE SIGNAL ;
    PORT
      LAYER M4 ;
        RECT 17.016 24.768 17.208 24.792 ;
    END
  END dq[466]
  PIN dq[467]
    DIRECTION INOUT ;
    USE SIGNAL ;
    PORT
      LAYER M4 ;
        RECT 17.016 24.816 17.208 24.840 ;
    END
  END dq[467]
  PIN dq[468]
    DIRECTION INOUT ;
    USE SIGNAL ;
    PORT
      LAYER M4 ;
        RECT 17.016 24.864 17.208 24.888 ;
    END
  END dq[468]
  PIN dq[469]
    DIRECTION INOUT ;
    USE SIGNAL ;
    PORT
      LAYER M4 ;
        RECT 17.016 24.912 17.208 24.936 ;
    END
  END dq[469]
  PIN dq[470]
    DIRECTION INOUT ;
    USE SIGNAL ;
    PORT
      LAYER M4 ;
        RECT 17.016 24.960 17.208 24.984 ;
    END
  END dq[470]
  PIN dq[471]
    DIRECTION INOUT ;
    USE SIGNAL ;
    PORT
      LAYER M4 ;
        RECT 17.016 25.008 17.208 25.032 ;
    END
  END dq[471]
  PIN dq[472]
    DIRECTION INOUT ;
    USE SIGNAL ;
    PORT
      LAYER M4 ;
        RECT 17.016 25.056 17.208 25.080 ;
    END
  END dq[472]
  PIN dq[473]
    DIRECTION INOUT ;
    USE SIGNAL ;
    PORT
      LAYER M4 ;
        RECT 17.016 25.104 17.208 25.128 ;
    END
  END dq[473]
  PIN dq[474]
    DIRECTION INOUT ;
    USE SIGNAL ;
    PORT
      LAYER M4 ;
        RECT 17.016 25.152 17.208 25.176 ;
    END
  END dq[474]
  PIN dq[475]
    DIRECTION INOUT ;
    USE SIGNAL ;
    PORT
      LAYER M4 ;
        RECT 17.016 25.200 17.208 25.224 ;
    END
  END dq[475]
  PIN dq[476]
    DIRECTION INOUT ;
    USE SIGNAL ;
    PORT
      LAYER M4 ;
        RECT 17.016 25.248 17.208 25.272 ;
    END
  END dq[476]
  PIN dq[477]
    DIRECTION INOUT ;
    USE SIGNAL ;
    PORT
      LAYER M4 ;
        RECT 17.016 25.296 17.208 25.320 ;
    END
  END dq[477]
  PIN dq[478]
    DIRECTION INOUT ;
    USE SIGNAL ;
    PORT
      LAYER M4 ;
        RECT 17.016 25.344 17.208 25.368 ;
    END
  END dq[478]
  PIN dq[479]
    DIRECTION INOUT ;
    USE SIGNAL ;
    PORT
      LAYER M4 ;
        RECT 17.016 25.392 17.208 25.416 ;
    END
  END dq[479]
  PIN dq[480]
    DIRECTION INOUT ;
    USE SIGNAL ;
    PORT
      LAYER M4 ;
        RECT 17.016 25.440 17.208 25.464 ;
    END
  END dq[480]
  PIN dq[481]
    DIRECTION INOUT ;
    USE SIGNAL ;
    PORT
      LAYER M4 ;
        RECT 17.016 25.488 17.208 25.512 ;
    END
  END dq[481]
  PIN dq[482]
    DIRECTION INOUT ;
    USE SIGNAL ;
    PORT
      LAYER M4 ;
        RECT 17.016 25.536 17.208 25.560 ;
    END
  END dq[482]
  PIN dq[483]
    DIRECTION INOUT ;
    USE SIGNAL ;
    PORT
      LAYER M4 ;
        RECT 17.016 25.584 17.208 25.608 ;
    END
  END dq[483]
  PIN dq[484]
    DIRECTION INOUT ;
    USE SIGNAL ;
    PORT
      LAYER M4 ;
        RECT 17.016 25.632 17.208 25.656 ;
    END
  END dq[484]
  PIN dq[485]
    DIRECTION INOUT ;
    USE SIGNAL ;
    PORT
      LAYER M4 ;
        RECT 17.016 25.680 17.208 25.704 ;
    END
  END dq[485]
  PIN dq[486]
    DIRECTION INOUT ;
    USE SIGNAL ;
    PORT
      LAYER M4 ;
        RECT 17.016 25.728 17.208 25.752 ;
    END
  END dq[486]
  PIN dq[487]
    DIRECTION INOUT ;
    USE SIGNAL ;
    PORT
      LAYER M4 ;
        RECT 17.016 25.776 17.208 25.800 ;
    END
  END dq[487]
  PIN dq[488]
    DIRECTION INOUT ;
    USE SIGNAL ;
    PORT
      LAYER M4 ;
        RECT 17.016 25.824 17.208 25.848 ;
    END
  END dq[488]
  PIN dq[489]
    DIRECTION INOUT ;
    USE SIGNAL ;
    PORT
      LAYER M4 ;
        RECT 17.016 25.872 17.208 25.896 ;
    END
  END dq[489]
  PIN dq[490]
    DIRECTION INOUT ;
    USE SIGNAL ;
    PORT
      LAYER M4 ;
        RECT 17.016 25.920 17.208 25.944 ;
    END
  END dq[490]
  PIN dq[491]
    DIRECTION INOUT ;
    USE SIGNAL ;
    PORT
      LAYER M4 ;
        RECT 17.016 25.968 17.208 25.992 ;
    END
  END dq[491]
  PIN dq[492]
    DIRECTION INOUT ;
    USE SIGNAL ;
    PORT
      LAYER M4 ;
        RECT 17.016 26.016 17.208 26.040 ;
    END
  END dq[492]
  PIN dq[493]
    DIRECTION INOUT ;
    USE SIGNAL ;
    PORT
      LAYER M4 ;
        RECT 17.016 26.064 17.208 26.088 ;
    END
  END dq[493]
  PIN dq[494]
    DIRECTION INOUT ;
    USE SIGNAL ;
    PORT
      LAYER M4 ;
        RECT 17.016 26.112 17.208 26.136 ;
    END
  END dq[494]
  PIN dq[495]
    DIRECTION INOUT ;
    USE SIGNAL ;
    PORT
      LAYER M4 ;
        RECT 17.016 26.160 17.208 26.184 ;
    END
  END dq[495]
  PIN dq[496]
    DIRECTION INOUT ;
    USE SIGNAL ;
    PORT
      LAYER M4 ;
        RECT 17.016 26.208 17.208 26.232 ;
    END
  END dq[496]
  PIN dq[497]
    DIRECTION INOUT ;
    USE SIGNAL ;
    PORT
      LAYER M4 ;
        RECT 17.016 26.256 17.208 26.280 ;
    END
  END dq[497]
  PIN dq[498]
    DIRECTION INOUT ;
    USE SIGNAL ;
    PORT
      LAYER M4 ;
        RECT 17.016 26.304 17.208 26.328 ;
    END
  END dq[498]
  PIN dq[499]
    DIRECTION INOUT ;
    USE SIGNAL ;
    PORT
      LAYER M4 ;
        RECT 17.016 26.352 17.208 26.376 ;
    END
  END dq[499]
  PIN dq[500]
    DIRECTION INOUT ;
    USE SIGNAL ;
    PORT
      LAYER M4 ;
        RECT 17.016 26.400 17.208 26.424 ;
    END
  END dq[500]
  PIN dq[501]
    DIRECTION INOUT ;
    USE SIGNAL ;
    PORT
      LAYER M4 ;
        RECT 17.016 26.448 17.208 26.472 ;
    END
  END dq[501]
  PIN dq[502]
    DIRECTION INOUT ;
    USE SIGNAL ;
    PORT
      LAYER M4 ;
        RECT 17.016 26.496 17.208 26.520 ;
    END
  END dq[502]
  PIN dq[503]
    DIRECTION INOUT ;
    USE SIGNAL ;
    PORT
      LAYER M4 ;
        RECT 17.016 26.544 17.208 26.568 ;
    END
  END dq[503]
  PIN dq[504]
    DIRECTION INOUT ;
    USE SIGNAL ;
    PORT
      LAYER M4 ;
        RECT 17.016 26.592 17.208 26.616 ;
    END
  END dq[504]
  PIN dq[505]
    DIRECTION INOUT ;
    USE SIGNAL ;
    PORT
      LAYER M4 ;
        RECT 17.016 26.640 17.208 26.664 ;
    END
  END dq[505]
  PIN dq[506]
    DIRECTION INOUT ;
    USE SIGNAL ;
    PORT
      LAYER M4 ;
        RECT 17.016 26.688 17.208 26.712 ;
    END
  END dq[506]
  PIN dq[507]
    DIRECTION INOUT ;
    USE SIGNAL ;
    PORT
      LAYER M4 ;
        RECT 17.016 26.736 17.208 26.760 ;
    END
  END dq[507]
  PIN dq[508]
    DIRECTION INOUT ;
    USE SIGNAL ;
    PORT
      LAYER M4 ;
        RECT 17.016 26.784 17.208 26.808 ;
    END
  END dq[508]
  PIN dq[509]
    DIRECTION INOUT ;
    USE SIGNAL ;
    PORT
      LAYER M4 ;
        RECT 17.016 26.832 17.208 26.856 ;
    END
  END dq[509]
  PIN dq[510]
    DIRECTION INOUT ;
    USE SIGNAL ;
    PORT
      LAYER M4 ;
        RECT 17.016 26.880 17.208 26.904 ;
    END
  END dq[510]
  PIN dq[511]
    DIRECTION INOUT ;
    USE SIGNAL ;
    PORT
      LAYER M4 ;
        RECT 17.016 26.928 17.208 26.952 ;
    END
  END dq[511]
  PIN dq[512]
    DIRECTION INOUT ;
    USE SIGNAL ;
    PORT
      LAYER M4 ;
        RECT 17.016 26.976 17.208 27.000 ;
    END
  END dq[512]
  PIN dq[513]
    DIRECTION INOUT ;
    USE SIGNAL ;
    PORT
      LAYER M4 ;
        RECT 17.016 27.024 17.208 27.048 ;
    END
  END dq[513]
  PIN dq[514]
    DIRECTION INOUT ;
    USE SIGNAL ;
    PORT
      LAYER M4 ;
        RECT 17.016 27.072 17.208 27.096 ;
    END
  END dq[514]
  PIN dq[515]
    DIRECTION INOUT ;
    USE SIGNAL ;
    PORT
      LAYER M4 ;
        RECT 17.016 27.120 17.208 27.144 ;
    END
  END dq[515]
  PIN dq[516]
    DIRECTION INOUT ;
    USE SIGNAL ;
    PORT
      LAYER M4 ;
        RECT 17.016 27.168 17.208 27.192 ;
    END
  END dq[516]
  PIN dq[517]
    DIRECTION INOUT ;
    USE SIGNAL ;
    PORT
      LAYER M4 ;
        RECT 17.016 27.216 17.208 27.240 ;
    END
  END dq[517]
  PIN dq[518]
    DIRECTION INOUT ;
    USE SIGNAL ;
    PORT
      LAYER M4 ;
        RECT 17.016 27.264 17.208 27.288 ;
    END
  END dq[518]
  PIN dq[519]
    DIRECTION INOUT ;
    USE SIGNAL ;
    PORT
      LAYER M4 ;
        RECT 17.016 27.312 17.208 27.336 ;
    END
  END dq[519]
  PIN dq[520]
    DIRECTION INOUT ;
    USE SIGNAL ;
    PORT
      LAYER M4 ;
        RECT 17.016 27.360 17.208 27.384 ;
    END
  END dq[520]
  PIN dq[521]
    DIRECTION INOUT ;
    USE SIGNAL ;
    PORT
      LAYER M4 ;
        RECT 17.016 27.408 17.208 27.432 ;
    END
  END dq[521]
  PIN dq[522]
    DIRECTION INOUT ;
    USE SIGNAL ;
    PORT
      LAYER M4 ;
        RECT 17.016 27.456 17.208 27.480 ;
    END
  END dq[522]
  PIN dq[523]
    DIRECTION INOUT ;
    USE SIGNAL ;
    PORT
      LAYER M4 ;
        RECT 17.016 27.504 17.208 27.528 ;
    END
  END dq[523]
  PIN dq[524]
    DIRECTION INOUT ;
    USE SIGNAL ;
    PORT
      LAYER M4 ;
        RECT 17.016 27.552 17.208 27.576 ;
    END
  END dq[524]
  PIN dq[525]
    DIRECTION INOUT ;
    USE SIGNAL ;
    PORT
      LAYER M4 ;
        RECT 17.016 27.600 17.208 27.624 ;
    END
  END dq[525]
  PIN dq[526]
    DIRECTION INOUT ;
    USE SIGNAL ;
    PORT
      LAYER M4 ;
        RECT 17.016 27.648 17.208 27.672 ;
    END
  END dq[526]
  PIN dq[527]
    DIRECTION INOUT ;
    USE SIGNAL ;
    PORT
      LAYER M4 ;
        RECT 17.016 27.696 17.208 27.720 ;
    END
  END dq[527]
  PIN dq[528]
    DIRECTION INOUT ;
    USE SIGNAL ;
    PORT
      LAYER M4 ;
        RECT 17.016 27.744 17.208 27.768 ;
    END
  END dq[528]
  PIN dq[529]
    DIRECTION INOUT ;
    USE SIGNAL ;
    PORT
      LAYER M4 ;
        RECT 17.016 27.792 17.208 27.816 ;
    END
  END dq[529]
  PIN dq[530]
    DIRECTION INOUT ;
    USE SIGNAL ;
    PORT
      LAYER M4 ;
        RECT 17.016 27.840 17.208 27.864 ;
    END
  END dq[530]
  PIN dq[531]
    DIRECTION INOUT ;
    USE SIGNAL ;
    PORT
      LAYER M4 ;
        RECT 17.016 27.888 17.208 27.912 ;
    END
  END dq[531]
  PIN dq[532]
    DIRECTION INOUT ;
    USE SIGNAL ;
    PORT
      LAYER M4 ;
        RECT 17.016 27.936 17.208 27.960 ;
    END
  END dq[532]
  PIN dq[533]
    DIRECTION INOUT ;
    USE SIGNAL ;
    PORT
      LAYER M4 ;
        RECT 17.016 27.984 17.208 28.008 ;
    END
  END dq[533]
  PIN dq[534]
    DIRECTION INOUT ;
    USE SIGNAL ;
    PORT
      LAYER M4 ;
        RECT 17.016 28.032 17.208 28.056 ;
    END
  END dq[534]
  PIN dq[535]
    DIRECTION INOUT ;
    USE SIGNAL ;
    PORT
      LAYER M4 ;
        RECT 17.016 28.080 17.208 28.104 ;
    END
  END dq[535]
  PIN dq[536]
    DIRECTION INOUT ;
    USE SIGNAL ;
    PORT
      LAYER M4 ;
        RECT 17.016 28.128 17.208 28.152 ;
    END
  END dq[536]
  PIN dq[537]
    DIRECTION INOUT ;
    USE SIGNAL ;
    PORT
      LAYER M4 ;
        RECT 17.016 28.176 17.208 28.200 ;
    END
  END dq[537]
  PIN dq[538]
    DIRECTION INOUT ;
    USE SIGNAL ;
    PORT
      LAYER M4 ;
        RECT 17.016 28.224 17.208 28.248 ;
    END
  END dq[538]
  PIN dq[539]
    DIRECTION INOUT ;
    USE SIGNAL ;
    PORT
      LAYER M4 ;
        RECT 17.016 28.272 17.208 28.296 ;
    END
  END dq[539]
  PIN dq[540]
    DIRECTION INOUT ;
    USE SIGNAL ;
    PORT
      LAYER M4 ;
        RECT 17.016 28.320 17.208 28.344 ;
    END
  END dq[540]
  PIN dq[541]
    DIRECTION INOUT ;
    USE SIGNAL ;
    PORT
      LAYER M4 ;
        RECT 17.016 28.368 17.208 28.392 ;
    END
  END dq[541]
  PIN dq[542]
    DIRECTION INOUT ;
    USE SIGNAL ;
    PORT
      LAYER M4 ;
        RECT 17.016 28.416 17.208 28.440 ;
    END
  END dq[542]
  PIN dq[543]
    DIRECTION INOUT ;
    USE SIGNAL ;
    PORT
      LAYER M4 ;
        RECT 17.016 28.464 17.208 28.488 ;
    END
  END dq[543]
  PIN dq[544]
    DIRECTION INOUT ;
    USE SIGNAL ;
    PORT
      LAYER M4 ;
        RECT 17.016 28.512 17.208 28.536 ;
    END
  END dq[544]
  PIN dq[545]
    DIRECTION INOUT ;
    USE SIGNAL ;
    PORT
      LAYER M4 ;
        RECT 17.016 28.560 17.208 28.584 ;
    END
  END dq[545]
  PIN dq[546]
    DIRECTION INOUT ;
    USE SIGNAL ;
    PORT
      LAYER M4 ;
        RECT 17.016 28.608 17.208 28.632 ;
    END
  END dq[546]
  PIN dq[547]
    DIRECTION INOUT ;
    USE SIGNAL ;
    PORT
      LAYER M4 ;
        RECT 17.016 28.656 17.208 28.680 ;
    END
  END dq[547]
  PIN dq[548]
    DIRECTION INOUT ;
    USE SIGNAL ;
    PORT
      LAYER M4 ;
        RECT 17.016 28.704 17.208 28.728 ;
    END
  END dq[548]
  PIN dq[549]
    DIRECTION INOUT ;
    USE SIGNAL ;
    PORT
      LAYER M4 ;
        RECT 17.016 28.752 17.208 28.776 ;
    END
  END dq[549]
  PIN dq[550]
    DIRECTION INOUT ;
    USE SIGNAL ;
    PORT
      LAYER M4 ;
        RECT 17.016 28.800 17.208 28.824 ;
    END
  END dq[550]
  PIN dq[551]
    DIRECTION INOUT ;
    USE SIGNAL ;
    PORT
      LAYER M4 ;
        RECT 17.016 28.848 17.208 28.872 ;
    END
  END dq[551]
  PIN dq[552]
    DIRECTION INOUT ;
    USE SIGNAL ;
    PORT
      LAYER M4 ;
        RECT 17.016 28.896 17.208 28.920 ;
    END
  END dq[552]
  PIN dq[553]
    DIRECTION INOUT ;
    USE SIGNAL ;
    PORT
      LAYER M4 ;
        RECT 17.016 28.944 17.208 28.968 ;
    END
  END dq[553]
  PIN dq[554]
    DIRECTION INOUT ;
    USE SIGNAL ;
    PORT
      LAYER M4 ;
        RECT 17.016 28.992 17.208 29.016 ;
    END
  END dq[554]
  PIN dq[555]
    DIRECTION INOUT ;
    USE SIGNAL ;
    PORT
      LAYER M4 ;
        RECT 17.016 29.040 17.208 29.064 ;
    END
  END dq[555]
  PIN dq[556]
    DIRECTION INOUT ;
    USE SIGNAL ;
    PORT
      LAYER M4 ;
        RECT 17.016 29.088 17.208 29.112 ;
    END
  END dq[556]
  PIN dq[557]
    DIRECTION INOUT ;
    USE SIGNAL ;
    PORT
      LAYER M4 ;
        RECT 17.016 29.136 17.208 29.160 ;
    END
  END dq[557]
  PIN dq[558]
    DIRECTION INOUT ;
    USE SIGNAL ;
    PORT
      LAYER M4 ;
        RECT 17.016 29.184 17.208 29.208 ;
    END
  END dq[558]
  PIN dq[559]
    DIRECTION INOUT ;
    USE SIGNAL ;
    PORT
      LAYER M4 ;
        RECT 17.016 29.232 17.208 29.256 ;
    END
  END dq[559]
  PIN dq[560]
    DIRECTION INOUT ;
    USE SIGNAL ;
    PORT
      LAYER M4 ;
        RECT 17.016 29.280 17.208 29.304 ;
    END
  END dq[560]
  PIN dq[561]
    DIRECTION INOUT ;
    USE SIGNAL ;
    PORT
      LAYER M4 ;
        RECT 17.016 29.328 17.208 29.352 ;
    END
  END dq[561]
  PIN dq[562]
    DIRECTION INOUT ;
    USE SIGNAL ;
    PORT
      LAYER M4 ;
        RECT 17.016 29.376 17.208 29.400 ;
    END
  END dq[562]
  PIN dq[563]
    DIRECTION INOUT ;
    USE SIGNAL ;
    PORT
      LAYER M4 ;
        RECT 17.016 29.424 17.208 29.448 ;
    END
  END dq[563]
  PIN dq[564]
    DIRECTION INOUT ;
    USE SIGNAL ;
    PORT
      LAYER M4 ;
        RECT 17.016 29.472 17.208 29.496 ;
    END
  END dq[564]
  PIN dq[565]
    DIRECTION INOUT ;
    USE SIGNAL ;
    PORT
      LAYER M4 ;
        RECT 17.016 29.520 17.208 29.544 ;
    END
  END dq[565]
  PIN dq[566]
    DIRECTION INOUT ;
    USE SIGNAL ;
    PORT
      LAYER M4 ;
        RECT 17.016 29.568 17.208 29.592 ;
    END
  END dq[566]
  PIN dq[567]
    DIRECTION INOUT ;
    USE SIGNAL ;
    PORT
      LAYER M4 ;
        RECT 17.016 29.616 17.208 29.640 ;
    END
  END dq[567]
  PIN dq[568]
    DIRECTION INOUT ;
    USE SIGNAL ;
    PORT
      LAYER M4 ;
        RECT 17.016 29.664 17.208 29.688 ;
    END
  END dq[568]
  PIN dq[569]
    DIRECTION INOUT ;
    USE SIGNAL ;
    PORT
      LAYER M4 ;
        RECT 17.016 29.712 17.208 29.736 ;
    END
  END dq[569]
  PIN dq[570]
    DIRECTION INOUT ;
    USE SIGNAL ;
    PORT
      LAYER M4 ;
        RECT 17.016 29.760 17.208 29.784 ;
    END
  END dq[570]
  PIN dq[571]
    DIRECTION INOUT ;
    USE SIGNAL ;
    PORT
      LAYER M4 ;
        RECT 17.016 29.808 17.208 29.832 ;
    END
  END dq[571]
  PIN dq[572]
    DIRECTION INOUT ;
    USE SIGNAL ;
    PORT
      LAYER M4 ;
        RECT 17.016 29.856 17.208 29.880 ;
    END
  END dq[572]
  PIN dq[573]
    DIRECTION INOUT ;
    USE SIGNAL ;
    PORT
      LAYER M4 ;
        RECT 17.016 29.904 17.208 29.928 ;
    END
  END dq[573]
  PIN dq[574]
    DIRECTION INOUT ;
    USE SIGNAL ;
    PORT
      LAYER M4 ;
        RECT 17.016 29.952 17.208 29.976 ;
    END
  END dq[574]
  PIN dq[575]
    DIRECTION INOUT ;
    USE SIGNAL ;
    PORT
      LAYER M4 ;
        RECT 17.016 30.000 17.208 30.024 ;
    END
  END dq[575]
  PIN dq[576]
    DIRECTION INOUT ;
    USE SIGNAL ;
    PORT
      LAYER M4 ;
        RECT 17.016 30.048 17.208 30.072 ;
    END
  END dq[576]
  PIN dq[577]
    DIRECTION INOUT ;
    USE SIGNAL ;
    PORT
      LAYER M4 ;
        RECT 17.016 30.096 17.208 30.120 ;
    END
  END dq[577]
  PIN dq[578]
    DIRECTION INOUT ;
    USE SIGNAL ;
    PORT
      LAYER M4 ;
        RECT 17.016 30.144 17.208 30.168 ;
    END
  END dq[578]
  PIN dq[579]
    DIRECTION INOUT ;
    USE SIGNAL ;
    PORT
      LAYER M4 ;
        RECT 17.016 30.192 17.208 30.216 ;
    END
  END dq[579]
  PIN dq[580]
    DIRECTION INOUT ;
    USE SIGNAL ;
    PORT
      LAYER M4 ;
        RECT 17.016 30.240 17.208 30.264 ;
    END
  END dq[580]
  PIN dq[581]
    DIRECTION INOUT ;
    USE SIGNAL ;
    PORT
      LAYER M4 ;
        RECT 17.016 30.288 17.208 30.312 ;
    END
  END dq[581]
  PIN dq[582]
    DIRECTION INOUT ;
    USE SIGNAL ;
    PORT
      LAYER M4 ;
        RECT 17.016 30.336 17.208 30.360 ;
    END
  END dq[582]
  PIN dq[583]
    DIRECTION INOUT ;
    USE SIGNAL ;
    PORT
      LAYER M4 ;
        RECT 17.016 30.384 17.208 30.408 ;
    END
  END dq[583]
  PIN dq[584]
    DIRECTION INOUT ;
    USE SIGNAL ;
    PORT
      LAYER M4 ;
        RECT 17.016 30.432 17.208 30.456 ;
    END
  END dq[584]
  PIN dq[585]
    DIRECTION INOUT ;
    USE SIGNAL ;
    PORT
      LAYER M4 ;
        RECT 17.016 30.480 17.208 30.504 ;
    END
  END dq[585]
  PIN dq[586]
    DIRECTION INOUT ;
    USE SIGNAL ;
    PORT
      LAYER M4 ;
        RECT 17.016 30.528 17.208 30.552 ;
    END
  END dq[586]
  PIN dq[587]
    DIRECTION INOUT ;
    USE SIGNAL ;
    PORT
      LAYER M4 ;
        RECT 17.016 30.576 17.208 30.600 ;
    END
  END dq[587]
  PIN dq[588]
    DIRECTION INOUT ;
    USE SIGNAL ;
    PORT
      LAYER M4 ;
        RECT 17.016 30.624 17.208 30.648 ;
    END
  END dq[588]
  PIN dq[589]
    DIRECTION INOUT ;
    USE SIGNAL ;
    PORT
      LAYER M4 ;
        RECT 17.016 30.672 17.208 30.696 ;
    END
  END dq[589]
  PIN dq[590]
    DIRECTION INOUT ;
    USE SIGNAL ;
    PORT
      LAYER M4 ;
        RECT 17.016 30.720 17.208 30.744 ;
    END
  END dq[590]
  PIN dq[591]
    DIRECTION INOUT ;
    USE SIGNAL ;
    PORT
      LAYER M4 ;
        RECT 17.016 30.768 17.208 30.792 ;
    END
  END dq[591]
  PIN dq[592]
    DIRECTION INOUT ;
    USE SIGNAL ;
    PORT
      LAYER M4 ;
        RECT 17.016 30.816 17.208 30.840 ;
    END
  END dq[592]
  PIN dq[593]
    DIRECTION INOUT ;
    USE SIGNAL ;
    PORT
      LAYER M4 ;
        RECT 17.016 30.864 17.208 30.888 ;
    END
  END dq[593]
  PIN dq[594]
    DIRECTION INOUT ;
    USE SIGNAL ;
    PORT
      LAYER M4 ;
        RECT 17.016 30.912 17.208 30.936 ;
    END
  END dq[594]
  PIN dq[595]
    DIRECTION INOUT ;
    USE SIGNAL ;
    PORT
      LAYER M4 ;
        RECT 17.016 30.960 17.208 30.984 ;
    END
  END dq[595]
  PIN dq[596]
    DIRECTION INOUT ;
    USE SIGNAL ;
    PORT
      LAYER M4 ;
        RECT 17.016 31.008 17.208 31.032 ;
    END
  END dq[596]
  PIN dq[597]
    DIRECTION INOUT ;
    USE SIGNAL ;
    PORT
      LAYER M4 ;
        RECT 17.016 31.056 17.208 31.080 ;
    END
  END dq[597]
  PIN dq[598]
    DIRECTION INOUT ;
    USE SIGNAL ;
    PORT
      LAYER M4 ;
        RECT 17.016 31.104 17.208 31.128 ;
    END
  END dq[598]
  PIN dq[599]
    DIRECTION INOUT ;
    USE SIGNAL ;
    PORT
      LAYER M4 ;
        RECT 17.016 31.152 17.208 31.176 ;
    END
  END dq[599]
  PIN dq[600]
    DIRECTION INOUT ;
    USE SIGNAL ;
    PORT
      LAYER M4 ;
        RECT 17.016 31.200 17.208 31.224 ;
    END
  END dq[600]
  PIN dq[601]
    DIRECTION INOUT ;
    USE SIGNAL ;
    PORT
      LAYER M4 ;
        RECT 17.016 31.248 17.208 31.272 ;
    END
  END dq[601]
  PIN dq[602]
    DIRECTION INOUT ;
    USE SIGNAL ;
    PORT
      LAYER M4 ;
        RECT 17.016 31.296 17.208 31.320 ;
    END
  END dq[602]
  PIN dq[603]
    DIRECTION INOUT ;
    USE SIGNAL ;
    PORT
      LAYER M4 ;
        RECT 17.016 31.344 17.208 31.368 ;
    END
  END dq[603]
  PIN dq[604]
    DIRECTION INOUT ;
    USE SIGNAL ;
    PORT
      LAYER M4 ;
        RECT 17.016 31.392 17.208 31.416 ;
    END
  END dq[604]
  PIN dq[605]
    DIRECTION INOUT ;
    USE SIGNAL ;
    PORT
      LAYER M4 ;
        RECT 17.016 31.440 17.208 31.464 ;
    END
  END dq[605]
  PIN dq[606]
    DIRECTION INOUT ;
    USE SIGNAL ;
    PORT
      LAYER M4 ;
        RECT 17.016 31.488 17.208 31.512 ;
    END
  END dq[606]
  PIN dq[607]
    DIRECTION INOUT ;
    USE SIGNAL ;
    PORT
      LAYER M4 ;
        RECT 17.016 31.536 17.208 31.560 ;
    END
  END dq[607]
  PIN dq[608]
    DIRECTION INOUT ;
    USE SIGNAL ;
    PORT
      LAYER M4 ;
        RECT 17.016 31.584 17.208 31.608 ;
    END
  END dq[608]
  PIN dq[609]
    DIRECTION INOUT ;
    USE SIGNAL ;
    PORT
      LAYER M4 ;
        RECT 17.016 31.632 17.208 31.656 ;
    END
  END dq[609]
  PIN dq[610]
    DIRECTION INOUT ;
    USE SIGNAL ;
    PORT
      LAYER M4 ;
        RECT 17.016 31.680 17.208 31.704 ;
    END
  END dq[610]
  PIN dq[611]
    DIRECTION INOUT ;
    USE SIGNAL ;
    PORT
      LAYER M4 ;
        RECT 17.016 31.728 17.208 31.752 ;
    END
  END dq[611]
  PIN dq[612]
    DIRECTION INOUT ;
    USE SIGNAL ;
    PORT
      LAYER M4 ;
        RECT 17.016 31.776 17.208 31.800 ;
    END
  END dq[612]
  PIN dq[613]
    DIRECTION INOUT ;
    USE SIGNAL ;
    PORT
      LAYER M4 ;
        RECT 17.016 31.824 17.208 31.848 ;
    END
  END dq[613]
  PIN dq[614]
    DIRECTION INOUT ;
    USE SIGNAL ;
    PORT
      LAYER M4 ;
        RECT 17.016 31.872 17.208 31.896 ;
    END
  END dq[614]
  PIN dq[615]
    DIRECTION INOUT ;
    USE SIGNAL ;
    PORT
      LAYER M4 ;
        RECT 17.016 31.920 17.208 31.944 ;
    END
  END dq[615]
  PIN dq[616]
    DIRECTION INOUT ;
    USE SIGNAL ;
    PORT
      LAYER M4 ;
        RECT 17.016 31.968 17.208 31.992 ;
    END
  END dq[616]
  PIN dq[617]
    DIRECTION INOUT ;
    USE SIGNAL ;
    PORT
      LAYER M4 ;
        RECT 17.016 32.016 17.208 32.040 ;
    END
  END dq[617]
  PIN dq[618]
    DIRECTION INOUT ;
    USE SIGNAL ;
    PORT
      LAYER M4 ;
        RECT 17.016 32.064 17.208 32.088 ;
    END
  END dq[618]
  PIN dq[619]
    DIRECTION INOUT ;
    USE SIGNAL ;
    PORT
      LAYER M4 ;
        RECT 17.016 32.112 17.208 32.136 ;
    END
  END dq[619]
  PIN dq[620]
    DIRECTION INOUT ;
    USE SIGNAL ;
    PORT
      LAYER M4 ;
        RECT 17.016 32.160 17.208 32.184 ;
    END
  END dq[620]
  PIN dq[621]
    DIRECTION INOUT ;
    USE SIGNAL ;
    PORT
      LAYER M4 ;
        RECT 17.016 32.208 17.208 32.232 ;
    END
  END dq[621]
  PIN dq[622]
    DIRECTION INOUT ;
    USE SIGNAL ;
    PORT
      LAYER M4 ;
        RECT 17.016 32.256 17.208 32.280 ;
    END
  END dq[622]
  PIN dq[623]
    DIRECTION INOUT ;
    USE SIGNAL ;
    PORT
      LAYER M4 ;
        RECT 17.016 32.304 17.208 32.328 ;
    END
  END dq[623]
  PIN dq[624]
    DIRECTION INOUT ;
    USE SIGNAL ;
    PORT
      LAYER M4 ;
        RECT 17.016 32.352 17.208 32.376 ;
    END
  END dq[624]
  PIN dq[625]
    DIRECTION INOUT ;
    USE SIGNAL ;
    PORT
      LAYER M4 ;
        RECT 17.016 32.400 17.208 32.424 ;
    END
  END dq[625]
  PIN dq[626]
    DIRECTION INOUT ;
    USE SIGNAL ;
    PORT
      LAYER M4 ;
        RECT 17.016 32.448 17.208 32.472 ;
    END
  END dq[626]
  PIN dq[627]
    DIRECTION INOUT ;
    USE SIGNAL ;
    PORT
      LAYER M4 ;
        RECT 17.016 32.496 17.208 32.520 ;
    END
  END dq[627]
  PIN dq[628]
    DIRECTION INOUT ;
    USE SIGNAL ;
    PORT
      LAYER M4 ;
        RECT 17.016 32.544 17.208 32.568 ;
    END
  END dq[628]
  PIN dq[629]
    DIRECTION INOUT ;
    USE SIGNAL ;
    PORT
      LAYER M4 ;
        RECT 17.016 32.592 17.208 32.616 ;
    END
  END dq[629]
  PIN dq[630]
    DIRECTION INOUT ;
    USE SIGNAL ;
    PORT
      LAYER M4 ;
        RECT 17.016 32.640 17.208 32.664 ;
    END
  END dq[630]
  PIN dq[631]
    DIRECTION INOUT ;
    USE SIGNAL ;
    PORT
      LAYER M4 ;
        RECT 17.016 32.688 17.208 32.712 ;
    END
  END dq[631]
  PIN dq[632]
    DIRECTION INOUT ;
    USE SIGNAL ;
    PORT
      LAYER M4 ;
        RECT 17.016 32.736 17.208 32.760 ;
    END
  END dq[632]
  PIN dq[633]
    DIRECTION INOUT ;
    USE SIGNAL ;
    PORT
      LAYER M4 ;
        RECT 17.016 32.784 17.208 32.808 ;
    END
  END dq[633]
  PIN dq[634]
    DIRECTION INOUT ;
    USE SIGNAL ;
    PORT
      LAYER M4 ;
        RECT 17.016 32.832 17.208 32.856 ;
    END
  END dq[634]
  PIN dq[635]
    DIRECTION INOUT ;
    USE SIGNAL ;
    PORT
      LAYER M4 ;
        RECT 17.016 32.880 17.208 32.904 ;
    END
  END dq[635]
  PIN dq[636]
    DIRECTION INOUT ;
    USE SIGNAL ;
    PORT
      LAYER M4 ;
        RECT 17.016 32.928 17.208 32.952 ;
    END
  END dq[636]
  PIN dq[637]
    DIRECTION INOUT ;
    USE SIGNAL ;
    PORT
      LAYER M4 ;
        RECT 17.016 32.976 17.208 33.000 ;
    END
  END dq[637]
  PIN dq[638]
    DIRECTION INOUT ;
    USE SIGNAL ;
    PORT
      LAYER M4 ;
        RECT 17.016 33.024 17.208 33.048 ;
    END
  END dq[638]
  PIN dq[639]
    DIRECTION INOUT ;
    USE SIGNAL ;
    PORT
      LAYER M4 ;
        RECT 17.016 33.072 17.208 33.096 ;
    END
  END dq[639]
  PIN dq[640]
    DIRECTION INOUT ;
    USE SIGNAL ;
    PORT
      LAYER M4 ;
        RECT 17.016 33.120 17.208 33.144 ;
    END
  END dq[640]
  PIN dq[641]
    DIRECTION INOUT ;
    USE SIGNAL ;
    PORT
      LAYER M4 ;
        RECT 17.016 33.168 17.208 33.192 ;
    END
  END dq[641]
  PIN dq[642]
    DIRECTION INOUT ;
    USE SIGNAL ;
    PORT
      LAYER M4 ;
        RECT 17.016 33.216 17.208 33.240 ;
    END
  END dq[642]
  PIN dq[643]
    DIRECTION INOUT ;
    USE SIGNAL ;
    PORT
      LAYER M4 ;
        RECT 17.016 33.264 17.208 33.288 ;
    END
  END dq[643]
  PIN dq[644]
    DIRECTION INOUT ;
    USE SIGNAL ;
    PORT
      LAYER M4 ;
        RECT 17.016 33.312 17.208 33.336 ;
    END
  END dq[644]
  PIN dq[645]
    DIRECTION INOUT ;
    USE SIGNAL ;
    PORT
      LAYER M4 ;
        RECT 17.016 33.360 17.208 33.384 ;
    END
  END dq[645]
  PIN dq[646]
    DIRECTION INOUT ;
    USE SIGNAL ;
    PORT
      LAYER M4 ;
        RECT 17.016 33.408 17.208 33.432 ;
    END
  END dq[646]
  PIN dq[647]
    DIRECTION INOUT ;
    USE SIGNAL ;
    PORT
      LAYER M4 ;
        RECT 17.016 33.456 17.208 33.480 ;
    END
  END dq[647]
  PIN dq[648]
    DIRECTION INOUT ;
    USE SIGNAL ;
    PORT
      LAYER M4 ;
        RECT 17.016 33.504 17.208 33.528 ;
    END
  END dq[648]
  PIN dq[649]
    DIRECTION INOUT ;
    USE SIGNAL ;
    PORT
      LAYER M4 ;
        RECT 17.016 33.552 17.208 33.576 ;
    END
  END dq[649]
  PIN dq[650]
    DIRECTION INOUT ;
    USE SIGNAL ;
    PORT
      LAYER M4 ;
        RECT 17.016 33.600 17.208 33.624 ;
    END
  END dq[650]
  PIN dq[651]
    DIRECTION INOUT ;
    USE SIGNAL ;
    PORT
      LAYER M4 ;
        RECT 17.016 33.648 17.208 33.672 ;
    END
  END dq[651]
  PIN dq[652]
    DIRECTION INOUT ;
    USE SIGNAL ;
    PORT
      LAYER M4 ;
        RECT 17.016 33.696 17.208 33.720 ;
    END
  END dq[652]
  PIN dq[653]
    DIRECTION INOUT ;
    USE SIGNAL ;
    PORT
      LAYER M4 ;
        RECT 17.016 33.744 17.208 33.768 ;
    END
  END dq[653]
  PIN dq[654]
    DIRECTION INOUT ;
    USE SIGNAL ;
    PORT
      LAYER M4 ;
        RECT 17.016 33.792 17.208 33.816 ;
    END
  END dq[654]
  PIN dq[655]
    DIRECTION INOUT ;
    USE SIGNAL ;
    PORT
      LAYER M4 ;
        RECT 17.016 33.840 17.208 33.864 ;
    END
  END dq[655]
  PIN dq[656]
    DIRECTION INOUT ;
    USE SIGNAL ;
    PORT
      LAYER M4 ;
        RECT 17.016 33.888 17.208 33.912 ;
    END
  END dq[656]
  PIN dq[657]
    DIRECTION INOUT ;
    USE SIGNAL ;
    PORT
      LAYER M4 ;
        RECT 17.016 33.936 17.208 33.960 ;
    END
  END dq[657]
  PIN dq[658]
    DIRECTION INOUT ;
    USE SIGNAL ;
    PORT
      LAYER M4 ;
        RECT 17.016 33.984 17.208 34.008 ;
    END
  END dq[658]
  PIN dq[659]
    DIRECTION INOUT ;
    USE SIGNAL ;
    PORT
      LAYER M4 ;
        RECT 17.016 34.032 17.208 34.056 ;
    END
  END dq[659]
  PIN dq[660]
    DIRECTION INOUT ;
    USE SIGNAL ;
    PORT
      LAYER M4 ;
        RECT 17.016 34.080 17.208 34.104 ;
    END
  END dq[660]
  PIN dq[661]
    DIRECTION INOUT ;
    USE SIGNAL ;
    PORT
      LAYER M4 ;
        RECT 17.016 34.128 17.208 34.152 ;
    END
  END dq[661]
  PIN dq[662]
    DIRECTION INOUT ;
    USE SIGNAL ;
    PORT
      LAYER M4 ;
        RECT 17.016 34.176 17.208 34.200 ;
    END
  END dq[662]
  PIN dq[663]
    DIRECTION INOUT ;
    USE SIGNAL ;
    PORT
      LAYER M4 ;
        RECT 17.016 34.224 17.208 34.248 ;
    END
  END dq[663]
  PIN dq[664]
    DIRECTION INOUT ;
    USE SIGNAL ;
    PORT
      LAYER M4 ;
        RECT 17.016 34.272 17.208 34.296 ;
    END
  END dq[664]
  PIN dq[665]
    DIRECTION INOUT ;
    USE SIGNAL ;
    PORT
      LAYER M4 ;
        RECT 17.016 34.320 17.208 34.344 ;
    END
  END dq[665]
  PIN dq[666]
    DIRECTION INOUT ;
    USE SIGNAL ;
    PORT
      LAYER M4 ;
        RECT 17.016 34.368 17.208 34.392 ;
    END
  END dq[666]
  PIN dq[667]
    DIRECTION INOUT ;
    USE SIGNAL ;
    PORT
      LAYER M4 ;
        RECT 17.016 34.416 17.208 34.440 ;
    END
  END dq[667]
  PIN dq[668]
    DIRECTION INOUT ;
    USE SIGNAL ;
    PORT
      LAYER M4 ;
        RECT 17.016 34.464 17.208 34.488 ;
    END
  END dq[668]
  PIN dq[669]
    DIRECTION INOUT ;
    USE SIGNAL ;
    PORT
      LAYER M4 ;
        RECT 17.016 34.512 17.208 34.536 ;
    END
  END dq[669]
  PIN dq[670]
    DIRECTION INOUT ;
    USE SIGNAL ;
    PORT
      LAYER M4 ;
        RECT 17.016 34.560 17.208 34.584 ;
    END
  END dq[670]
  PIN dq[671]
    DIRECTION INOUT ;
    USE SIGNAL ;
    PORT
      LAYER M4 ;
        RECT 17.016 34.608 17.208 34.632 ;
    END
  END dq[671]
  PIN dq[672]
    DIRECTION INOUT ;
    USE SIGNAL ;
    PORT
      LAYER M4 ;
        RECT 17.016 34.656 17.208 34.680 ;
    END
  END dq[672]
  PIN dq[673]
    DIRECTION INOUT ;
    USE SIGNAL ;
    PORT
      LAYER M4 ;
        RECT 17.016 34.704 17.208 34.728 ;
    END
  END dq[673]
  PIN dq[674]
    DIRECTION INOUT ;
    USE SIGNAL ;
    PORT
      LAYER M4 ;
        RECT 17.016 34.752 17.208 34.776 ;
    END
  END dq[674]
  PIN dq[675]
    DIRECTION INOUT ;
    USE SIGNAL ;
    PORT
      LAYER M4 ;
        RECT 17.016 34.800 17.208 34.824 ;
    END
  END dq[675]
  PIN dq[676]
    DIRECTION INOUT ;
    USE SIGNAL ;
    PORT
      LAYER M4 ;
        RECT 17.016 34.848 17.208 34.872 ;
    END
  END dq[676]
  PIN dq[677]
    DIRECTION INOUT ;
    USE SIGNAL ;
    PORT
      LAYER M4 ;
        RECT 17.016 34.896 17.208 34.920 ;
    END
  END dq[677]
  PIN dq[678]
    DIRECTION INOUT ;
    USE SIGNAL ;
    PORT
      LAYER M4 ;
        RECT 17.016 34.944 17.208 34.968 ;
    END
  END dq[678]
  PIN dq[679]
    DIRECTION INOUT ;
    USE SIGNAL ;
    PORT
      LAYER M4 ;
        RECT 17.016 34.992 17.208 35.016 ;
    END
  END dq[679]
  PIN dq[680]
    DIRECTION INOUT ;
    USE SIGNAL ;
    PORT
      LAYER M4 ;
        RECT 17.016 35.040 17.208 35.064 ;
    END
  END dq[680]
  PIN dq[681]
    DIRECTION INOUT ;
    USE SIGNAL ;
    PORT
      LAYER M4 ;
        RECT 17.016 35.088 17.208 35.112 ;
    END
  END dq[681]
  PIN dq[682]
    DIRECTION INOUT ;
    USE SIGNAL ;
    PORT
      LAYER M4 ;
        RECT 17.016 35.136 17.208 35.160 ;
    END
  END dq[682]
  PIN dq[683]
    DIRECTION INOUT ;
    USE SIGNAL ;
    PORT
      LAYER M4 ;
        RECT 17.016 35.184 17.208 35.208 ;
    END
  END dq[683]
  PIN dq[684]
    DIRECTION INOUT ;
    USE SIGNAL ;
    PORT
      LAYER M4 ;
        RECT 17.016 35.232 17.208 35.256 ;
    END
  END dq[684]
  PIN dq[685]
    DIRECTION INOUT ;
    USE SIGNAL ;
    PORT
      LAYER M4 ;
        RECT 17.016 35.280 17.208 35.304 ;
    END
  END dq[685]
  PIN dq[686]
    DIRECTION INOUT ;
    USE SIGNAL ;
    PORT
      LAYER M4 ;
        RECT 17.016 35.328 17.208 35.352 ;
    END
  END dq[686]
  PIN dq[687]
    DIRECTION INOUT ;
    USE SIGNAL ;
    PORT
      LAYER M4 ;
        RECT 17.016 35.376 17.208 35.400 ;
    END
  END dq[687]
  PIN dq[688]
    DIRECTION INOUT ;
    USE SIGNAL ;
    PORT
      LAYER M4 ;
        RECT 17.016 35.424 17.208 35.448 ;
    END
  END dq[688]
  PIN dq[689]
    DIRECTION INOUT ;
    USE SIGNAL ;
    PORT
      LAYER M4 ;
        RECT 17.016 35.472 17.208 35.496 ;
    END
  END dq[689]
  PIN dq[690]
    DIRECTION INOUT ;
    USE SIGNAL ;
    PORT
      LAYER M4 ;
        RECT 17.016 35.520 17.208 35.544 ;
    END
  END dq[690]
  PIN dq[691]
    DIRECTION INOUT ;
    USE SIGNAL ;
    PORT
      LAYER M4 ;
        RECT 17.016 35.568 17.208 35.592 ;
    END
  END dq[691]
  PIN dq[692]
    DIRECTION INOUT ;
    USE SIGNAL ;
    PORT
      LAYER M4 ;
        RECT 17.016 35.616 17.208 35.640 ;
    END
  END dq[692]
  PIN dq[693]
    DIRECTION INOUT ;
    USE SIGNAL ;
    PORT
      LAYER M4 ;
        RECT 17.016 35.664 17.208 35.688 ;
    END
  END dq[693]
  PIN dq[694]
    DIRECTION INOUT ;
    USE SIGNAL ;
    PORT
      LAYER M4 ;
        RECT 17.016 35.712 17.208 35.736 ;
    END
  END dq[694]
  PIN dq[695]
    DIRECTION INOUT ;
    USE SIGNAL ;
    PORT
      LAYER M4 ;
        RECT 17.016 35.760 17.208 35.784 ;
    END
  END dq[695]
  PIN dq[696]
    DIRECTION INOUT ;
    USE SIGNAL ;
    PORT
      LAYER M4 ;
        RECT 17.016 35.808 17.208 35.832 ;
    END
  END dq[696]
  PIN dq[697]
    DIRECTION INOUT ;
    USE SIGNAL ;
    PORT
      LAYER M4 ;
        RECT 17.016 35.856 17.208 35.880 ;
    END
  END dq[697]
  PIN dq[698]
    DIRECTION INOUT ;
    USE SIGNAL ;
    PORT
      LAYER M4 ;
        RECT 17.016 35.904 17.208 35.928 ;
    END
  END dq[698]
  PIN dq[699]
    DIRECTION INOUT ;
    USE SIGNAL ;
    PORT
      LAYER M4 ;
        RECT 17.016 35.952 17.208 35.976 ;
    END
  END dq[699]
  PIN dq[700]
    DIRECTION INOUT ;
    USE SIGNAL ;
    PORT
      LAYER M4 ;
        RECT 17.016 36.000 17.208 36.024 ;
    END
  END dq[700]
  PIN dq[701]
    DIRECTION INOUT ;
    USE SIGNAL ;
    PORT
      LAYER M4 ;
        RECT 17.016 36.048 17.208 36.072 ;
    END
  END dq[701]
  PIN dq[702]
    DIRECTION INOUT ;
    USE SIGNAL ;
    PORT
      LAYER M4 ;
        RECT 17.016 36.096 17.208 36.120 ;
    END
  END dq[702]
  PIN dq[703]
    DIRECTION INOUT ;
    USE SIGNAL ;
    PORT
      LAYER M4 ;
        RECT 17.016 36.144 17.208 36.168 ;
    END
  END dq[703]
  PIN dq[704]
    DIRECTION INOUT ;
    USE SIGNAL ;
    PORT
      LAYER M4 ;
        RECT 17.016 36.192 17.208 36.216 ;
    END
  END dq[704]
  PIN dq[705]
    DIRECTION INOUT ;
    USE SIGNAL ;
    PORT
      LAYER M4 ;
        RECT 17.016 36.240 17.208 36.264 ;
    END
  END dq[705]
  PIN dq[706]
    DIRECTION INOUT ;
    USE SIGNAL ;
    PORT
      LAYER M4 ;
        RECT 17.016 36.288 17.208 36.312 ;
    END
  END dq[706]
  PIN dq[707]
    DIRECTION INOUT ;
    USE SIGNAL ;
    PORT
      LAYER M4 ;
        RECT 17.016 36.336 17.208 36.360 ;
    END
  END dq[707]
  PIN dq[708]
    DIRECTION INOUT ;
    USE SIGNAL ;
    PORT
      LAYER M4 ;
        RECT 17.016 36.384 17.208 36.408 ;
    END
  END dq[708]
  PIN dq[709]
    DIRECTION INOUT ;
    USE SIGNAL ;
    PORT
      LAYER M4 ;
        RECT 17.016 36.432 17.208 36.456 ;
    END
  END dq[709]
  PIN dq[710]
    DIRECTION INOUT ;
    USE SIGNAL ;
    PORT
      LAYER M4 ;
        RECT 17.016 36.480 17.208 36.504 ;
    END
  END dq[710]
  PIN dq[711]
    DIRECTION INOUT ;
    USE SIGNAL ;
    PORT
      LAYER M4 ;
        RECT 17.016 36.528 17.208 36.552 ;
    END
  END dq[711]
  PIN dq[712]
    DIRECTION INOUT ;
    USE SIGNAL ;
    PORT
      LAYER M4 ;
        RECT 17.016 36.576 17.208 36.600 ;
    END
  END dq[712]
  PIN dq[713]
    DIRECTION INOUT ;
    USE SIGNAL ;
    PORT
      LAYER M4 ;
        RECT 17.016 36.624 17.208 36.648 ;
    END
  END dq[713]
  PIN dq[714]
    DIRECTION INOUT ;
    USE SIGNAL ;
    PORT
      LAYER M4 ;
        RECT 17.016 36.672 17.208 36.696 ;
    END
  END dq[714]
  PIN dq[715]
    DIRECTION INOUT ;
    USE SIGNAL ;
    PORT
      LAYER M4 ;
        RECT 17.016 36.720 17.208 36.744 ;
    END
  END dq[715]
  PIN dq[716]
    DIRECTION INOUT ;
    USE SIGNAL ;
    PORT
      LAYER M4 ;
        RECT 17.016 36.768 17.208 36.792 ;
    END
  END dq[716]
  PIN dq[717]
    DIRECTION INOUT ;
    USE SIGNAL ;
    PORT
      LAYER M4 ;
        RECT 17.016 36.816 17.208 36.840 ;
    END
  END dq[717]
  PIN dq[718]
    DIRECTION INOUT ;
    USE SIGNAL ;
    PORT
      LAYER M4 ;
        RECT 17.016 36.864 17.208 36.888 ;
    END
  END dq[718]
  PIN dq[719]
    DIRECTION INOUT ;
    USE SIGNAL ;
    PORT
      LAYER M4 ;
        RECT 17.016 36.912 17.208 36.936 ;
    END
  END dq[719]
  PIN dq[720]
    DIRECTION INOUT ;
    USE SIGNAL ;
    PORT
      LAYER M4 ;
        RECT 17.016 36.960 17.208 36.984 ;
    END
  END dq[720]
  PIN dq[721]
    DIRECTION INOUT ;
    USE SIGNAL ;
    PORT
      LAYER M4 ;
        RECT 17.016 37.008 17.208 37.032 ;
    END
  END dq[721]
  PIN dq[722]
    DIRECTION INOUT ;
    USE SIGNAL ;
    PORT
      LAYER M4 ;
        RECT 17.016 37.056 17.208 37.080 ;
    END
  END dq[722]
  PIN dq[723]
    DIRECTION INOUT ;
    USE SIGNAL ;
    PORT
      LAYER M4 ;
        RECT 17.016 37.104 17.208 37.128 ;
    END
  END dq[723]
  PIN dq[724]
    DIRECTION INOUT ;
    USE SIGNAL ;
    PORT
      LAYER M4 ;
        RECT 17.016 37.152 17.208 37.176 ;
    END
  END dq[724]
  PIN dq[725]
    DIRECTION INOUT ;
    USE SIGNAL ;
    PORT
      LAYER M4 ;
        RECT 17.016 37.200 17.208 37.224 ;
    END
  END dq[725]
  PIN dq[726]
    DIRECTION INOUT ;
    USE SIGNAL ;
    PORT
      LAYER M4 ;
        RECT 17.016 37.248 17.208 37.272 ;
    END
  END dq[726]
  PIN dq[727]
    DIRECTION INOUT ;
    USE SIGNAL ;
    PORT
      LAYER M4 ;
        RECT 17.016 37.296 17.208 37.320 ;
    END
  END dq[727]
  PIN dq[728]
    DIRECTION INOUT ;
    USE SIGNAL ;
    PORT
      LAYER M4 ;
        RECT 17.016 37.344 17.208 37.368 ;
    END
  END dq[728]
  PIN dq[729]
    DIRECTION INOUT ;
    USE SIGNAL ;
    PORT
      LAYER M4 ;
        RECT 17.016 37.392 17.208 37.416 ;
    END
  END dq[729]
  PIN dq[730]
    DIRECTION INOUT ;
    USE SIGNAL ;
    PORT
      LAYER M4 ;
        RECT 17.016 37.440 17.208 37.464 ;
    END
  END dq[730]
  PIN dq[731]
    DIRECTION INOUT ;
    USE SIGNAL ;
    PORT
      LAYER M4 ;
        RECT 17.016 37.488 17.208 37.512 ;
    END
  END dq[731]
  PIN dq[732]
    DIRECTION INOUT ;
    USE SIGNAL ;
    PORT
      LAYER M4 ;
        RECT 17.016 37.536 17.208 37.560 ;
    END
  END dq[732]
  PIN dq[733]
    DIRECTION INOUT ;
    USE SIGNAL ;
    PORT
      LAYER M4 ;
        RECT 17.016 37.584 17.208 37.608 ;
    END
  END dq[733]
  PIN dq[734]
    DIRECTION INOUT ;
    USE SIGNAL ;
    PORT
      LAYER M4 ;
        RECT 17.016 37.632 17.208 37.656 ;
    END
  END dq[734]
  PIN dq[735]
    DIRECTION INOUT ;
    USE SIGNAL ;
    PORT
      LAYER M4 ;
        RECT 17.016 37.680 17.208 37.704 ;
    END
  END dq[735]
  PIN dq[736]
    DIRECTION INOUT ;
    USE SIGNAL ;
    PORT
      LAYER M4 ;
        RECT 17.016 37.728 17.208 37.752 ;
    END
  END dq[736]
  PIN dq[737]
    DIRECTION INOUT ;
    USE SIGNAL ;
    PORT
      LAYER M4 ;
        RECT 17.016 37.776 17.208 37.800 ;
    END
  END dq[737]
  PIN dq[738]
    DIRECTION INOUT ;
    USE SIGNAL ;
    PORT
      LAYER M4 ;
        RECT 17.016 37.824 17.208 37.848 ;
    END
  END dq[738]
  PIN dq[739]
    DIRECTION INOUT ;
    USE SIGNAL ;
    PORT
      LAYER M4 ;
        RECT 17.016 37.872 17.208 37.896 ;
    END
  END dq[739]
  PIN dq[740]
    DIRECTION INOUT ;
    USE SIGNAL ;
    PORT
      LAYER M4 ;
        RECT 17.016 37.920 17.208 37.944 ;
    END
  END dq[740]
  PIN dq[741]
    DIRECTION INOUT ;
    USE SIGNAL ;
    PORT
      LAYER M4 ;
        RECT 17.016 37.968 17.208 37.992 ;
    END
  END dq[741]
  PIN dq[742]
    DIRECTION INOUT ;
    USE SIGNAL ;
    PORT
      LAYER M4 ;
        RECT 17.016 38.016 17.208 38.040 ;
    END
  END dq[742]
  PIN dq[743]
    DIRECTION INOUT ;
    USE SIGNAL ;
    PORT
      LAYER M4 ;
        RECT 17.016 38.064 17.208 38.088 ;
    END
  END dq[743]
  PIN dq[744]
    DIRECTION INOUT ;
    USE SIGNAL ;
    PORT
      LAYER M4 ;
        RECT 17.016 38.112 17.208 38.136 ;
    END
  END dq[744]
  PIN dq[745]
    DIRECTION INOUT ;
    USE SIGNAL ;
    PORT
      LAYER M4 ;
        RECT 17.016 38.160 17.208 38.184 ;
    END
  END dq[745]
  PIN dq[746]
    DIRECTION INOUT ;
    USE SIGNAL ;
    PORT
      LAYER M4 ;
        RECT 17.016 38.208 17.208 38.232 ;
    END
  END dq[746]
  PIN dq[747]
    DIRECTION INOUT ;
    USE SIGNAL ;
    PORT
      LAYER M4 ;
        RECT 17.016 38.256 17.208 38.280 ;
    END
  END dq[747]
  PIN dq[748]
    DIRECTION INOUT ;
    USE SIGNAL ;
    PORT
      LAYER M4 ;
        RECT 17.016 38.304 17.208 38.328 ;
    END
  END dq[748]
  PIN dq[749]
    DIRECTION INOUT ;
    USE SIGNAL ;
    PORT
      LAYER M4 ;
        RECT 17.016 38.352 17.208 38.376 ;
    END
  END dq[749]
  PIN dq[750]
    DIRECTION INOUT ;
    USE SIGNAL ;
    PORT
      LAYER M4 ;
        RECT 17.016 38.400 17.208 38.424 ;
    END
  END dq[750]
  PIN dq[751]
    DIRECTION INOUT ;
    USE SIGNAL ;
    PORT
      LAYER M4 ;
        RECT 17.016 38.448 17.208 38.472 ;
    END
  END dq[751]
  PIN dq[752]
    DIRECTION INOUT ;
    USE SIGNAL ;
    PORT
      LAYER M4 ;
        RECT 17.016 38.496 17.208 38.520 ;
    END
  END dq[752]
  PIN dq[753]
    DIRECTION INOUT ;
    USE SIGNAL ;
    PORT
      LAYER M4 ;
        RECT 17.016 38.544 17.208 38.568 ;
    END
  END dq[753]
  PIN dq[754]
    DIRECTION INOUT ;
    USE SIGNAL ;
    PORT
      LAYER M4 ;
        RECT 17.016 38.592 17.208 38.616 ;
    END
  END dq[754]
  PIN dq[755]
    DIRECTION INOUT ;
    USE SIGNAL ;
    PORT
      LAYER M4 ;
        RECT 17.016 38.640 17.208 38.664 ;
    END
  END dq[755]
  PIN dq[756]
    DIRECTION INOUT ;
    USE SIGNAL ;
    PORT
      LAYER M4 ;
        RECT 17.016 38.688 17.208 38.712 ;
    END
  END dq[756]
  PIN dq[757]
    DIRECTION INOUT ;
    USE SIGNAL ;
    PORT
      LAYER M4 ;
        RECT 17.016 38.736 17.208 38.760 ;
    END
  END dq[757]
  PIN dq[758]
    DIRECTION INOUT ;
    USE SIGNAL ;
    PORT
      LAYER M4 ;
        RECT 17.016 38.784 17.208 38.808 ;
    END
  END dq[758]
  PIN dq[759]
    DIRECTION INOUT ;
    USE SIGNAL ;
    PORT
      LAYER M4 ;
        RECT 17.016 38.832 17.208 38.856 ;
    END
  END dq[759]
  PIN dq[760]
    DIRECTION INOUT ;
    USE SIGNAL ;
    PORT
      LAYER M4 ;
        RECT 17.016 38.880 17.208 38.904 ;
    END
  END dq[760]
  PIN dq[761]
    DIRECTION INOUT ;
    USE SIGNAL ;
    PORT
      LAYER M4 ;
        RECT 17.016 38.928 17.208 38.952 ;
    END
  END dq[761]
  PIN dq[762]
    DIRECTION INOUT ;
    USE SIGNAL ;
    PORT
      LAYER M4 ;
        RECT 17.016 38.976 17.208 39.000 ;
    END
  END dq[762]
  PIN dq[763]
    DIRECTION INOUT ;
    USE SIGNAL ;
    PORT
      LAYER M4 ;
        RECT 17.016 39.024 17.208 39.048 ;
    END
  END dq[763]
  PIN dq[764]
    DIRECTION INOUT ;
    USE SIGNAL ;
    PORT
      LAYER M4 ;
        RECT 17.016 39.072 17.208 39.096 ;
    END
  END dq[764]
  PIN dq[765]
    DIRECTION INOUT ;
    USE SIGNAL ;
    PORT
      LAYER M4 ;
        RECT 17.016 39.120 17.208 39.144 ;
    END
  END dq[765]
  PIN dq[766]
    DIRECTION INOUT ;
    USE SIGNAL ;
    PORT
      LAYER M4 ;
        RECT 17.016 39.168 17.208 39.192 ;
    END
  END dq[766]
  PIN dq[767]
    DIRECTION INOUT ;
    USE SIGNAL ;
    PORT
      LAYER M4 ;
        RECT 17.016 39.216 17.208 39.240 ;
    END
  END dq[767]
  PIN dq[768]
    DIRECTION INOUT ;
    USE SIGNAL ;
    PORT
      LAYER M4 ;
        RECT 17.016 39.264 17.208 39.288 ;
    END
  END dq[768]
  PIN dq[769]
    DIRECTION INOUT ;
    USE SIGNAL ;
    PORT
      LAYER M4 ;
        RECT 17.016 39.312 17.208 39.336 ;
    END
  END dq[769]
  PIN dq[770]
    DIRECTION INOUT ;
    USE SIGNAL ;
    PORT
      LAYER M4 ;
        RECT 17.016 39.360 17.208 39.384 ;
    END
  END dq[770]
  PIN dq[771]
    DIRECTION INOUT ;
    USE SIGNAL ;
    PORT
      LAYER M4 ;
        RECT 17.016 39.408 17.208 39.432 ;
    END
  END dq[771]
  PIN dq[772]
    DIRECTION INOUT ;
    USE SIGNAL ;
    PORT
      LAYER M4 ;
        RECT 17.016 39.456 17.208 39.480 ;
    END
  END dq[772]
  PIN dq[773]
    DIRECTION INOUT ;
    USE SIGNAL ;
    PORT
      LAYER M4 ;
        RECT 17.016 39.504 17.208 39.528 ;
    END
  END dq[773]
  PIN dq[774]
    DIRECTION INOUT ;
    USE SIGNAL ;
    PORT
      LAYER M4 ;
        RECT 17.016 39.552 17.208 39.576 ;
    END
  END dq[774]
  PIN dq[775]
    DIRECTION INOUT ;
    USE SIGNAL ;
    PORT
      LAYER M4 ;
        RECT 17.016 39.600 17.208 39.624 ;
    END
  END dq[775]
  PIN dq[776]
    DIRECTION INOUT ;
    USE SIGNAL ;
    PORT
      LAYER M4 ;
        RECT 17.016 39.648 17.208 39.672 ;
    END
  END dq[776]
  PIN dq[777]
    DIRECTION INOUT ;
    USE SIGNAL ;
    PORT
      LAYER M4 ;
        RECT 17.016 39.696 17.208 39.720 ;
    END
  END dq[777]
  PIN dq[778]
    DIRECTION INOUT ;
    USE SIGNAL ;
    PORT
      LAYER M4 ;
        RECT 17.016 39.744 17.208 39.768 ;
    END
  END dq[778]
  PIN dq[779]
    DIRECTION INOUT ;
    USE SIGNAL ;
    PORT
      LAYER M4 ;
        RECT 17.016 39.792 17.208 39.816 ;
    END
  END dq[779]
  PIN dq[780]
    DIRECTION INOUT ;
    USE SIGNAL ;
    PORT
      LAYER M4 ;
        RECT 17.016 39.840 17.208 39.864 ;
    END
  END dq[780]
  PIN dq[781]
    DIRECTION INOUT ;
    USE SIGNAL ;
    PORT
      LAYER M4 ;
        RECT 17.016 39.888 17.208 39.912 ;
    END
  END dq[781]
  PIN dq[782]
    DIRECTION INOUT ;
    USE SIGNAL ;
    PORT
      LAYER M4 ;
        RECT 17.016 39.936 17.208 39.960 ;
    END
  END dq[782]
  PIN dq[783]
    DIRECTION INOUT ;
    USE SIGNAL ;
    PORT
      LAYER M4 ;
        RECT 17.016 39.984 17.208 40.008 ;
    END
  END dq[783]
  PIN dq[784]
    DIRECTION INOUT ;
    USE SIGNAL ;
    PORT
      LAYER M4 ;
        RECT 17.016 40.032 17.208 40.056 ;
    END
  END dq[784]
  PIN dq[785]
    DIRECTION INOUT ;
    USE SIGNAL ;
    PORT
      LAYER M4 ;
        RECT 17.016 40.080 17.208 40.104 ;
    END
  END dq[785]
  PIN dq[786]
    DIRECTION INOUT ;
    USE SIGNAL ;
    PORT
      LAYER M4 ;
        RECT 17.016 40.128 17.208 40.152 ;
    END
  END dq[786]
  PIN dq[787]
    DIRECTION INOUT ;
    USE SIGNAL ;
    PORT
      LAYER M4 ;
        RECT 17.016 40.176 17.208 40.200 ;
    END
  END dq[787]
  PIN dq[788]
    DIRECTION INOUT ;
    USE SIGNAL ;
    PORT
      LAYER M4 ;
        RECT 17.016 40.224 17.208 40.248 ;
    END
  END dq[788]
  PIN dq[789]
    DIRECTION INOUT ;
    USE SIGNAL ;
    PORT
      LAYER M4 ;
        RECT 17.016 40.272 17.208 40.296 ;
    END
  END dq[789]
  PIN dq[790]
    DIRECTION INOUT ;
    USE SIGNAL ;
    PORT
      LAYER M4 ;
        RECT 17.016 40.320 17.208 40.344 ;
    END
  END dq[790]
  PIN dq[791]
    DIRECTION INOUT ;
    USE SIGNAL ;
    PORT
      LAYER M4 ;
        RECT 17.016 40.368 17.208 40.392 ;
    END
  END dq[791]
  PIN dq[792]
    DIRECTION INOUT ;
    USE SIGNAL ;
    PORT
      LAYER M4 ;
        RECT 17.016 40.416 17.208 40.440 ;
    END
  END dq[792]
  PIN dq[793]
    DIRECTION INOUT ;
    USE SIGNAL ;
    PORT
      LAYER M4 ;
        RECT 17.016 40.464 17.208 40.488 ;
    END
  END dq[793]
  PIN dq[794]
    DIRECTION INOUT ;
    USE SIGNAL ;
    PORT
      LAYER M4 ;
        RECT 17.016 40.512 17.208 40.536 ;
    END
  END dq[794]
  PIN dq[795]
    DIRECTION INOUT ;
    USE SIGNAL ;
    PORT
      LAYER M4 ;
        RECT 17.016 40.560 17.208 40.584 ;
    END
  END dq[795]
  PIN dq[796]
    DIRECTION INOUT ;
    USE SIGNAL ;
    PORT
      LAYER M4 ;
        RECT 17.016 40.608 17.208 40.632 ;
    END
  END dq[796]
  PIN dq[797]
    DIRECTION INOUT ;
    USE SIGNAL ;
    PORT
      LAYER M4 ;
        RECT 17.016 40.656 17.208 40.680 ;
    END
  END dq[797]
  PIN dq[798]
    DIRECTION INOUT ;
    USE SIGNAL ;
    PORT
      LAYER M4 ;
        RECT 17.016 40.704 17.208 40.728 ;
    END
  END dq[798]
  PIN dq[799]
    DIRECTION INOUT ;
    USE SIGNAL ;
    PORT
      LAYER M4 ;
        RECT 17.016 40.752 17.208 40.776 ;
    END
  END dq[799]
  PIN dq[800]
    DIRECTION INOUT ;
    USE SIGNAL ;
    PORT
      LAYER M4 ;
        RECT 17.016 40.800 17.208 40.824 ;
    END
  END dq[800]
  PIN dq[801]
    DIRECTION INOUT ;
    USE SIGNAL ;
    PORT
      LAYER M4 ;
        RECT 17.016 40.848 17.208 40.872 ;
    END
  END dq[801]
  PIN dq[802]
    DIRECTION INOUT ;
    USE SIGNAL ;
    PORT
      LAYER M4 ;
        RECT 17.016 40.896 17.208 40.920 ;
    END
  END dq[802]
  PIN dq[803]
    DIRECTION INOUT ;
    USE SIGNAL ;
    PORT
      LAYER M4 ;
        RECT 17.016 40.944 17.208 40.968 ;
    END
  END dq[803]
  PIN dq[804]
    DIRECTION INOUT ;
    USE SIGNAL ;
    PORT
      LAYER M4 ;
        RECT 17.016 40.992 17.208 41.016 ;
    END
  END dq[804]
  PIN dq[805]
    DIRECTION INOUT ;
    USE SIGNAL ;
    PORT
      LAYER M4 ;
        RECT 17.016 41.040 17.208 41.064 ;
    END
  END dq[805]
  PIN dq[806]
    DIRECTION INOUT ;
    USE SIGNAL ;
    PORT
      LAYER M4 ;
        RECT 17.016 41.088 17.208 41.112 ;
    END
  END dq[806]
  PIN dq[807]
    DIRECTION INOUT ;
    USE SIGNAL ;
    PORT
      LAYER M4 ;
        RECT 17.016 41.136 17.208 41.160 ;
    END
  END dq[807]
  PIN dq[808]
    DIRECTION INOUT ;
    USE SIGNAL ;
    PORT
      LAYER M4 ;
        RECT 17.016 41.184 17.208 41.208 ;
    END
  END dq[808]
  PIN dq[809]
    DIRECTION INOUT ;
    USE SIGNAL ;
    PORT
      LAYER M4 ;
        RECT 17.016 41.232 17.208 41.256 ;
    END
  END dq[809]
  PIN dq[810]
    DIRECTION INOUT ;
    USE SIGNAL ;
    PORT
      LAYER M4 ;
        RECT 17.016 41.280 17.208 41.304 ;
    END
  END dq[810]
  PIN dq[811]
    DIRECTION INOUT ;
    USE SIGNAL ;
    PORT
      LAYER M4 ;
        RECT 17.016 41.328 17.208 41.352 ;
    END
  END dq[811]
  PIN dq[812]
    DIRECTION INOUT ;
    USE SIGNAL ;
    PORT
      LAYER M4 ;
        RECT 17.016 41.376 17.208 41.400 ;
    END
  END dq[812]
  PIN dq[813]
    DIRECTION INOUT ;
    USE SIGNAL ;
    PORT
      LAYER M4 ;
        RECT 17.016 41.424 17.208 41.448 ;
    END
  END dq[813]
  PIN dq[814]
    DIRECTION INOUT ;
    USE SIGNAL ;
    PORT
      LAYER M4 ;
        RECT 17.016 41.472 17.208 41.496 ;
    END
  END dq[814]
  PIN dq[815]
    DIRECTION INOUT ;
    USE SIGNAL ;
    PORT
      LAYER M4 ;
        RECT 17.016 41.520 17.208 41.544 ;
    END
  END dq[815]
  PIN dq[816]
    DIRECTION INOUT ;
    USE SIGNAL ;
    PORT
      LAYER M4 ;
        RECT 17.016 41.568 17.208 41.592 ;
    END
  END dq[816]
  PIN dq[817]
    DIRECTION INOUT ;
    USE SIGNAL ;
    PORT
      LAYER M4 ;
        RECT 17.016 41.616 17.208 41.640 ;
    END
  END dq[817]
  PIN dq[818]
    DIRECTION INOUT ;
    USE SIGNAL ;
    PORT
      LAYER M4 ;
        RECT 17.016 41.664 17.208 41.688 ;
    END
  END dq[818]
  PIN dq[819]
    DIRECTION INOUT ;
    USE SIGNAL ;
    PORT
      LAYER M4 ;
        RECT 17.016 41.712 17.208 41.736 ;
    END
  END dq[819]
  PIN dq[820]
    DIRECTION INOUT ;
    USE SIGNAL ;
    PORT
      LAYER M4 ;
        RECT 17.016 41.760 17.208 41.784 ;
    END
  END dq[820]
  PIN dq[821]
    DIRECTION INOUT ;
    USE SIGNAL ;
    PORT
      LAYER M4 ;
        RECT 17.016 41.808 17.208 41.832 ;
    END
  END dq[821]
  PIN dq[822]
    DIRECTION INOUT ;
    USE SIGNAL ;
    PORT
      LAYER M4 ;
        RECT 17.016 41.856 17.208 41.880 ;
    END
  END dq[822]
  PIN dq[823]
    DIRECTION INOUT ;
    USE SIGNAL ;
    PORT
      LAYER M4 ;
        RECT 17.016 41.904 17.208 41.928 ;
    END
  END dq[823]
  PIN dq[824]
    DIRECTION INOUT ;
    USE SIGNAL ;
    PORT
      LAYER M4 ;
        RECT 17.016 41.952 17.208 41.976 ;
    END
  END dq[824]
  PIN dq[825]
    DIRECTION INOUT ;
    USE SIGNAL ;
    PORT
      LAYER M4 ;
        RECT 17.016 42.000 17.208 42.024 ;
    END
  END dq[825]
  PIN dq[826]
    DIRECTION INOUT ;
    USE SIGNAL ;
    PORT
      LAYER M4 ;
        RECT 17.016 42.048 17.208 42.072 ;
    END
  END dq[826]
  PIN dq[827]
    DIRECTION INOUT ;
    USE SIGNAL ;
    PORT
      LAYER M4 ;
        RECT 17.016 42.096 17.208 42.120 ;
    END
  END dq[827]
  PIN dq[828]
    DIRECTION INOUT ;
    USE SIGNAL ;
    PORT
      LAYER M4 ;
        RECT 17.016 42.144 17.208 42.168 ;
    END
  END dq[828]
  PIN dq[829]
    DIRECTION INOUT ;
    USE SIGNAL ;
    PORT
      LAYER M4 ;
        RECT 17.016 42.192 17.208 42.216 ;
    END
  END dq[829]
  PIN dq[830]
    DIRECTION INOUT ;
    USE SIGNAL ;
    PORT
      LAYER M4 ;
        RECT 17.016 42.240 17.208 42.264 ;
    END
  END dq[830]
  PIN dq[831]
    DIRECTION INOUT ;
    USE SIGNAL ;
    PORT
      LAYER M4 ;
        RECT 17.016 42.288 17.208 42.312 ;
    END
  END dq[831]
  PIN dq[832]
    DIRECTION INOUT ;
    USE SIGNAL ;
    PORT
      LAYER M4 ;
        RECT 17.016 42.336 17.208 42.360 ;
    END
  END dq[832]
  PIN dq[833]
    DIRECTION INOUT ;
    USE SIGNAL ;
    PORT
      LAYER M4 ;
        RECT 17.016 42.384 17.208 42.408 ;
    END
  END dq[833]
  PIN dq[834]
    DIRECTION INOUT ;
    USE SIGNAL ;
    PORT
      LAYER M4 ;
        RECT 17.016 42.432 17.208 42.456 ;
    END
  END dq[834]
  PIN dq[835]
    DIRECTION INOUT ;
    USE SIGNAL ;
    PORT
      LAYER M4 ;
        RECT 17.016 42.480 17.208 42.504 ;
    END
  END dq[835]
  PIN dq[836]
    DIRECTION INOUT ;
    USE SIGNAL ;
    PORT
      LAYER M4 ;
        RECT 17.016 42.528 17.208 42.552 ;
    END
  END dq[836]
  PIN dq[837]
    DIRECTION INOUT ;
    USE SIGNAL ;
    PORT
      LAYER M4 ;
        RECT 17.016 42.576 17.208 42.600 ;
    END
  END dq[837]
  PIN dq[838]
    DIRECTION INOUT ;
    USE SIGNAL ;
    PORT
      LAYER M4 ;
        RECT 17.016 42.624 17.208 42.648 ;
    END
  END dq[838]
  PIN dq[839]
    DIRECTION INOUT ;
    USE SIGNAL ;
    PORT
      LAYER M4 ;
        RECT 17.016 42.672 17.208 42.696 ;
    END
  END dq[839]
  PIN dq[840]
    DIRECTION INOUT ;
    USE SIGNAL ;
    PORT
      LAYER M4 ;
        RECT 17.016 42.720 17.208 42.744 ;
    END
  END dq[840]
  PIN dq[841]
    DIRECTION INOUT ;
    USE SIGNAL ;
    PORT
      LAYER M4 ;
        RECT 17.016 42.768 17.208 42.792 ;
    END
  END dq[841]
  PIN dq[842]
    DIRECTION INOUT ;
    USE SIGNAL ;
    PORT
      LAYER M4 ;
        RECT 17.016 42.816 17.208 42.840 ;
    END
  END dq[842]
  PIN dq[843]
    DIRECTION INOUT ;
    USE SIGNAL ;
    PORT
      LAYER M4 ;
        RECT 17.016 42.864 17.208 42.888 ;
    END
  END dq[843]
  PIN dq[844]
    DIRECTION INOUT ;
    USE SIGNAL ;
    PORT
      LAYER M4 ;
        RECT 17.016 42.912 17.208 42.936 ;
    END
  END dq[844]
  PIN dq[845]
    DIRECTION INOUT ;
    USE SIGNAL ;
    PORT
      LAYER M4 ;
        RECT 17.016 42.960 17.208 42.984 ;
    END
  END dq[845]
  PIN dq[846]
    DIRECTION INOUT ;
    USE SIGNAL ;
    PORT
      LAYER M4 ;
        RECT 17.016 43.008 17.208 43.032 ;
    END
  END dq[846]
  PIN dq[847]
    DIRECTION INOUT ;
    USE SIGNAL ;
    PORT
      LAYER M4 ;
        RECT 17.016 43.056 17.208 43.080 ;
    END
  END dq[847]
  PIN dq[848]
    DIRECTION INOUT ;
    USE SIGNAL ;
    PORT
      LAYER M4 ;
        RECT 17.016 43.104 17.208 43.128 ;
    END
  END dq[848]
  PIN dq[849]
    DIRECTION INOUT ;
    USE SIGNAL ;
    PORT
      LAYER M4 ;
        RECT 17.016 43.152 17.208 43.176 ;
    END
  END dq[849]
  PIN dq[850]
    DIRECTION INOUT ;
    USE SIGNAL ;
    PORT
      LAYER M4 ;
        RECT 17.016 43.200 17.208 43.224 ;
    END
  END dq[850]
  PIN dq[851]
    DIRECTION INOUT ;
    USE SIGNAL ;
    PORT
      LAYER M4 ;
        RECT 17.016 43.248 17.208 43.272 ;
    END
  END dq[851]
  PIN dq[852]
    DIRECTION INOUT ;
    USE SIGNAL ;
    PORT
      LAYER M4 ;
        RECT 17.016 43.296 17.208 43.320 ;
    END
  END dq[852]
  PIN dq[853]
    DIRECTION INOUT ;
    USE SIGNAL ;
    PORT
      LAYER M4 ;
        RECT 17.016 43.344 17.208 43.368 ;
    END
  END dq[853]
  PIN dq[854]
    DIRECTION INOUT ;
    USE SIGNAL ;
    PORT
      LAYER M4 ;
        RECT 17.016 43.392 17.208 43.416 ;
    END
  END dq[854]
  PIN dq[855]
    DIRECTION INOUT ;
    USE SIGNAL ;
    PORT
      LAYER M4 ;
        RECT 17.016 43.440 17.208 43.464 ;
    END
  END dq[855]
  PIN dq[856]
    DIRECTION INOUT ;
    USE SIGNAL ;
    PORT
      LAYER M4 ;
        RECT 17.016 43.488 17.208 43.512 ;
    END
  END dq[856]
  PIN dq[857]
    DIRECTION INOUT ;
    USE SIGNAL ;
    PORT
      LAYER M4 ;
        RECT 17.016 43.536 17.208 43.560 ;
    END
  END dq[857]
  PIN dq[858]
    DIRECTION INOUT ;
    USE SIGNAL ;
    PORT
      LAYER M4 ;
        RECT 17.016 43.584 17.208 43.608 ;
    END
  END dq[858]
  PIN dq[859]
    DIRECTION INOUT ;
    USE SIGNAL ;
    PORT
      LAYER M4 ;
        RECT 17.016 43.632 17.208 43.656 ;
    END
  END dq[859]
  PIN dq[860]
    DIRECTION INOUT ;
    USE SIGNAL ;
    PORT
      LAYER M4 ;
        RECT 17.016 43.680 17.208 43.704 ;
    END
  END dq[860]
  PIN dq[861]
    DIRECTION INOUT ;
    USE SIGNAL ;
    PORT
      LAYER M4 ;
        RECT 17.016 43.728 17.208 43.752 ;
    END
  END dq[861]
  PIN dq[862]
    DIRECTION INOUT ;
    USE SIGNAL ;
    PORT
      LAYER M4 ;
        RECT 17.016 43.776 17.208 43.800 ;
    END
  END dq[862]
  PIN dq[863]
    DIRECTION INOUT ;
    USE SIGNAL ;
    PORT
      LAYER M4 ;
        RECT 17.016 43.824 17.208 43.848 ;
    END
  END dq[863]
  PIN dq[864]
    DIRECTION INOUT ;
    USE SIGNAL ;
    PORT
      LAYER M4 ;
        RECT 17.016 43.872 17.208 43.896 ;
    END
  END dq[864]
  PIN dq[865]
    DIRECTION INOUT ;
    USE SIGNAL ;
    PORT
      LAYER M4 ;
        RECT 17.016 43.920 17.208 43.944 ;
    END
  END dq[865]
  PIN dq[866]
    DIRECTION INOUT ;
    USE SIGNAL ;
    PORT
      LAYER M4 ;
        RECT 17.016 43.968 17.208 43.992 ;
    END
  END dq[866]
  PIN dq[867]
    DIRECTION INOUT ;
    USE SIGNAL ;
    PORT
      LAYER M4 ;
        RECT 17.016 44.016 17.208 44.040 ;
    END
  END dq[867]
  PIN dq[868]
    DIRECTION INOUT ;
    USE SIGNAL ;
    PORT
      LAYER M4 ;
        RECT 17.016 44.064 17.208 44.088 ;
    END
  END dq[868]
  PIN dq[869]
    DIRECTION INOUT ;
    USE SIGNAL ;
    PORT
      LAYER M4 ;
        RECT 17.016 44.112 17.208 44.136 ;
    END
  END dq[869]
  PIN dq[870]
    DIRECTION INOUT ;
    USE SIGNAL ;
    PORT
      LAYER M4 ;
        RECT 17.016 44.160 17.208 44.184 ;
    END
  END dq[870]
  PIN dq[871]
    DIRECTION INOUT ;
    USE SIGNAL ;
    PORT
      LAYER M4 ;
        RECT 17.016 44.208 17.208 44.232 ;
    END
  END dq[871]
  PIN dq[872]
    DIRECTION INOUT ;
    USE SIGNAL ;
    PORT
      LAYER M4 ;
        RECT 17.016 44.256 17.208 44.280 ;
    END
  END dq[872]
  PIN dq[873]
    DIRECTION INOUT ;
    USE SIGNAL ;
    PORT
      LAYER M4 ;
        RECT 17.016 44.304 17.208 44.328 ;
    END
  END dq[873]
  PIN dq[874]
    DIRECTION INOUT ;
    USE SIGNAL ;
    PORT
      LAYER M4 ;
        RECT 17.016 44.352 17.208 44.376 ;
    END
  END dq[874]
  PIN dq[875]
    DIRECTION INOUT ;
    USE SIGNAL ;
    PORT
      LAYER M4 ;
        RECT 17.016 44.400 17.208 44.424 ;
    END
  END dq[875]
  PIN dq[876]
    DIRECTION INOUT ;
    USE SIGNAL ;
    PORT
      LAYER M4 ;
        RECT 17.016 44.448 17.208 44.472 ;
    END
  END dq[876]
  PIN dq[877]
    DIRECTION INOUT ;
    USE SIGNAL ;
    PORT
      LAYER M4 ;
        RECT 17.016 44.496 17.208 44.520 ;
    END
  END dq[877]
  PIN dq[878]
    DIRECTION INOUT ;
    USE SIGNAL ;
    PORT
      LAYER M4 ;
        RECT 17.016 44.544 17.208 44.568 ;
    END
  END dq[878]
  PIN dq[879]
    DIRECTION INOUT ;
    USE SIGNAL ;
    PORT
      LAYER M4 ;
        RECT 17.016 44.592 17.208 44.616 ;
    END
  END dq[879]
  PIN dq[880]
    DIRECTION INOUT ;
    USE SIGNAL ;
    PORT
      LAYER M4 ;
        RECT 17.016 44.640 17.208 44.664 ;
    END
  END dq[880]
  PIN dq[881]
    DIRECTION INOUT ;
    USE SIGNAL ;
    PORT
      LAYER M4 ;
        RECT 17.016 44.688 17.208 44.712 ;
    END
  END dq[881]
  PIN dq[882]
    DIRECTION INOUT ;
    USE SIGNAL ;
    PORT
      LAYER M4 ;
        RECT 17.016 44.736 17.208 44.760 ;
    END
  END dq[882]
  PIN dq[883]
    DIRECTION INOUT ;
    USE SIGNAL ;
    PORT
      LAYER M4 ;
        RECT 17.016 44.784 17.208 44.808 ;
    END
  END dq[883]
  PIN dq[884]
    DIRECTION INOUT ;
    USE SIGNAL ;
    PORT
      LAYER M4 ;
        RECT 17.016 44.832 17.208 44.856 ;
    END
  END dq[884]
  PIN dq[885]
    DIRECTION INOUT ;
    USE SIGNAL ;
    PORT
      LAYER M4 ;
        RECT 17.016 44.880 17.208 44.904 ;
    END
  END dq[885]
  PIN dq[886]
    DIRECTION INOUT ;
    USE SIGNAL ;
    PORT
      LAYER M4 ;
        RECT 17.016 44.928 17.208 44.952 ;
    END
  END dq[886]
  PIN dq[887]
    DIRECTION INOUT ;
    USE SIGNAL ;
    PORT
      LAYER M4 ;
        RECT 17.016 44.976 17.208 45.000 ;
    END
  END dq[887]
  PIN dq[888]
    DIRECTION INOUT ;
    USE SIGNAL ;
    PORT
      LAYER M4 ;
        RECT 17.016 45.024 17.208 45.048 ;
    END
  END dq[888]
  PIN dq[889]
    DIRECTION INOUT ;
    USE SIGNAL ;
    PORT
      LAYER M4 ;
        RECT 17.016 45.072 17.208 45.096 ;
    END
  END dq[889]
  PIN dq[890]
    DIRECTION INOUT ;
    USE SIGNAL ;
    PORT
      LAYER M4 ;
        RECT 17.016 45.120 17.208 45.144 ;
    END
  END dq[890]
  PIN dq[891]
    DIRECTION INOUT ;
    USE SIGNAL ;
    PORT
      LAYER M4 ;
        RECT 17.016 45.168 17.208 45.192 ;
    END
  END dq[891]
  PIN dq[892]
    DIRECTION INOUT ;
    USE SIGNAL ;
    PORT
      LAYER M4 ;
        RECT 17.016 45.216 17.208 45.240 ;
    END
  END dq[892]
  PIN dq[893]
    DIRECTION INOUT ;
    USE SIGNAL ;
    PORT
      LAYER M4 ;
        RECT 17.016 45.264 17.208 45.288 ;
    END
  END dq[893]
  PIN dq[894]
    DIRECTION INOUT ;
    USE SIGNAL ;
    PORT
      LAYER M4 ;
        RECT 17.016 45.312 17.208 45.336 ;
    END
  END dq[894]
  PIN dq[895]
    DIRECTION INOUT ;
    USE SIGNAL ;
    PORT
      LAYER M4 ;
        RECT 17.016 45.360 17.208 45.384 ;
    END
  END dq[895]
  PIN dq[896]
    DIRECTION INOUT ;
    USE SIGNAL ;
    PORT
      LAYER M4 ;
        RECT 17.016 45.408 17.208 45.432 ;
    END
  END dq[896]
  PIN dq[897]
    DIRECTION INOUT ;
    USE SIGNAL ;
    PORT
      LAYER M4 ;
        RECT 17.016 45.456 17.208 45.480 ;
    END
  END dq[897]
  PIN dq[898]
    DIRECTION INOUT ;
    USE SIGNAL ;
    PORT
      LAYER M4 ;
        RECT 17.016 45.504 17.208 45.528 ;
    END
  END dq[898]
  PIN dq[899]
    DIRECTION INOUT ;
    USE SIGNAL ;
    PORT
      LAYER M4 ;
        RECT 17.016 45.552 17.208 45.576 ;
    END
  END dq[899]
  PIN dq[900]
    DIRECTION INOUT ;
    USE SIGNAL ;
    PORT
      LAYER M4 ;
        RECT 17.016 45.600 17.208 45.624 ;
    END
  END dq[900]
  PIN dq[901]
    DIRECTION INOUT ;
    USE SIGNAL ;
    PORT
      LAYER M4 ;
        RECT 17.016 45.648 17.208 45.672 ;
    END
  END dq[901]
  PIN dq[902]
    DIRECTION INOUT ;
    USE SIGNAL ;
    PORT
      LAYER M4 ;
        RECT 17.016 45.696 17.208 45.720 ;
    END
  END dq[902]
  PIN dq[903]
    DIRECTION INOUT ;
    USE SIGNAL ;
    PORT
      LAYER M4 ;
        RECT 17.016 45.744 17.208 45.768 ;
    END
  END dq[903]
  PIN dq[904]
    DIRECTION INOUT ;
    USE SIGNAL ;
    PORT
      LAYER M4 ;
        RECT 17.016 45.792 17.208 45.816 ;
    END
  END dq[904]
  PIN dq[905]
    DIRECTION INOUT ;
    USE SIGNAL ;
    PORT
      LAYER M4 ;
        RECT 17.016 45.840 17.208 45.864 ;
    END
  END dq[905]
  PIN dq[906]
    DIRECTION INOUT ;
    USE SIGNAL ;
    PORT
      LAYER M4 ;
        RECT 17.016 45.888 17.208 45.912 ;
    END
  END dq[906]
  PIN dq[907]
    DIRECTION INOUT ;
    USE SIGNAL ;
    PORT
      LAYER M4 ;
        RECT 17.016 45.936 17.208 45.960 ;
    END
  END dq[907]
  PIN dq[908]
    DIRECTION INOUT ;
    USE SIGNAL ;
    PORT
      LAYER M4 ;
        RECT 17.016 45.984 17.208 46.008 ;
    END
  END dq[908]
  PIN dq[909]
    DIRECTION INOUT ;
    USE SIGNAL ;
    PORT
      LAYER M4 ;
        RECT 17.016 46.032 17.208 46.056 ;
    END
  END dq[909]
  PIN dq[910]
    DIRECTION INOUT ;
    USE SIGNAL ;
    PORT
      LAYER M4 ;
        RECT 17.016 46.080 17.208 46.104 ;
    END
  END dq[910]
  PIN dq[911]
    DIRECTION INOUT ;
    USE SIGNAL ;
    PORT
      LAYER M4 ;
        RECT 17.016 46.128 17.208 46.152 ;
    END
  END dq[911]
  PIN dq[912]
    DIRECTION INOUT ;
    USE SIGNAL ;
    PORT
      LAYER M4 ;
        RECT 17.016 46.176 17.208 46.200 ;
    END
  END dq[912]
  PIN dq[913]
    DIRECTION INOUT ;
    USE SIGNAL ;
    PORT
      LAYER M4 ;
        RECT 17.016 46.224 17.208 46.248 ;
    END
  END dq[913]
  PIN dq[914]
    DIRECTION INOUT ;
    USE SIGNAL ;
    PORT
      LAYER M4 ;
        RECT 17.016 46.272 17.208 46.296 ;
    END
  END dq[914]
  PIN dq[915]
    DIRECTION INOUT ;
    USE SIGNAL ;
    PORT
      LAYER M4 ;
        RECT 17.016 46.320 17.208 46.344 ;
    END
  END dq[915]
  PIN dq[916]
    DIRECTION INOUT ;
    USE SIGNAL ;
    PORT
      LAYER M4 ;
        RECT 17.016 46.368 17.208 46.392 ;
    END
  END dq[916]
  PIN dq[917]
    DIRECTION INOUT ;
    USE SIGNAL ;
    PORT
      LAYER M4 ;
        RECT 17.016 46.416 17.208 46.440 ;
    END
  END dq[917]
  PIN dq[918]
    DIRECTION INOUT ;
    USE SIGNAL ;
    PORT
      LAYER M4 ;
        RECT 17.016 46.464 17.208 46.488 ;
    END
  END dq[918]
  PIN dq[919]
    DIRECTION INOUT ;
    USE SIGNAL ;
    PORT
      LAYER M4 ;
        RECT 17.016 46.512 17.208 46.536 ;
    END
  END dq[919]
  PIN dq[920]
    DIRECTION INOUT ;
    USE SIGNAL ;
    PORT
      LAYER M4 ;
        RECT 17.016 46.560 17.208 46.584 ;
    END
  END dq[920]
  PIN dq[921]
    DIRECTION INOUT ;
    USE SIGNAL ;
    PORT
      LAYER M4 ;
        RECT 17.016 46.608 17.208 46.632 ;
    END
  END dq[921]
  PIN dq[922]
    DIRECTION INOUT ;
    USE SIGNAL ;
    PORT
      LAYER M4 ;
        RECT 17.016 46.656 17.208 46.680 ;
    END
  END dq[922]
  PIN dq[923]
    DIRECTION INOUT ;
    USE SIGNAL ;
    PORT
      LAYER M4 ;
        RECT 17.016 46.704 17.208 46.728 ;
    END
  END dq[923]
  PIN dq[924]
    DIRECTION INOUT ;
    USE SIGNAL ;
    PORT
      LAYER M4 ;
        RECT 17.016 46.752 17.208 46.776 ;
    END
  END dq[924]
  PIN dq[925]
    DIRECTION INOUT ;
    USE SIGNAL ;
    PORT
      LAYER M4 ;
        RECT 17.016 46.800 17.208 46.824 ;
    END
  END dq[925]
  PIN dq[926]
    DIRECTION INOUT ;
    USE SIGNAL ;
    PORT
      LAYER M4 ;
        RECT 17.016 46.848 17.208 46.872 ;
    END
  END dq[926]
  PIN dq[927]
    DIRECTION INOUT ;
    USE SIGNAL ;
    PORT
      LAYER M4 ;
        RECT 17.016 46.896 17.208 46.920 ;
    END
  END dq[927]
  PIN dq[928]
    DIRECTION INOUT ;
    USE SIGNAL ;
    PORT
      LAYER M4 ;
        RECT 17.016 46.944 17.208 46.968 ;
    END
  END dq[928]
  PIN dq[929]
    DIRECTION INOUT ;
    USE SIGNAL ;
    PORT
      LAYER M4 ;
        RECT 17.016 46.992 17.208 47.016 ;
    END
  END dq[929]
  PIN dq[930]
    DIRECTION INOUT ;
    USE SIGNAL ;
    PORT
      LAYER M4 ;
        RECT 17.016 47.040 17.208 47.064 ;
    END
  END dq[930]
  PIN dq[931]
    DIRECTION INOUT ;
    USE SIGNAL ;
    PORT
      LAYER M4 ;
        RECT 17.016 47.088 17.208 47.112 ;
    END
  END dq[931]
  PIN dq[932]
    DIRECTION INOUT ;
    USE SIGNAL ;
    PORT
      LAYER M4 ;
        RECT 17.016 47.136 17.208 47.160 ;
    END
  END dq[932]
  PIN dq[933]
    DIRECTION INOUT ;
    USE SIGNAL ;
    PORT
      LAYER M4 ;
        RECT 17.016 47.184 17.208 47.208 ;
    END
  END dq[933]
  PIN dq[934]
    DIRECTION INOUT ;
    USE SIGNAL ;
    PORT
      LAYER M4 ;
        RECT 17.016 47.232 17.208 47.256 ;
    END
  END dq[934]
  PIN dq[935]
    DIRECTION INOUT ;
    USE SIGNAL ;
    PORT
      LAYER M4 ;
        RECT 17.016 47.280 17.208 47.304 ;
    END
  END dq[935]
  PIN dq[936]
    DIRECTION INOUT ;
    USE SIGNAL ;
    PORT
      LAYER M4 ;
        RECT 17.016 47.328 17.208 47.352 ;
    END
  END dq[936]
  PIN dq[937]
    DIRECTION INOUT ;
    USE SIGNAL ;
    PORT
      LAYER M4 ;
        RECT 17.016 47.376 17.208 47.400 ;
    END
  END dq[937]
  PIN dq[938]
    DIRECTION INOUT ;
    USE SIGNAL ;
    PORT
      LAYER M4 ;
        RECT 17.016 47.424 17.208 47.448 ;
    END
  END dq[938]
  PIN dq[939]
    DIRECTION INOUT ;
    USE SIGNAL ;
    PORT
      LAYER M4 ;
        RECT 17.016 47.472 17.208 47.496 ;
    END
  END dq[939]
  PIN dq[940]
    DIRECTION INOUT ;
    USE SIGNAL ;
    PORT
      LAYER M4 ;
        RECT 17.016 47.520 17.208 47.544 ;
    END
  END dq[940]
  PIN dq[941]
    DIRECTION INOUT ;
    USE SIGNAL ;
    PORT
      LAYER M4 ;
        RECT 17.016 47.568 17.208 47.592 ;
    END
  END dq[941]
  PIN dq[942]
    DIRECTION INOUT ;
    USE SIGNAL ;
    PORT
      LAYER M4 ;
        RECT 17.016 47.616 17.208 47.640 ;
    END
  END dq[942]
  PIN dq[943]
    DIRECTION INOUT ;
    USE SIGNAL ;
    PORT
      LAYER M4 ;
        RECT 17.016 47.664 17.208 47.688 ;
    END
  END dq[943]
  PIN dq[944]
    DIRECTION INOUT ;
    USE SIGNAL ;
    PORT
      LAYER M4 ;
        RECT 17.016 47.712 17.208 47.736 ;
    END
  END dq[944]
  PIN dq[945]
    DIRECTION INOUT ;
    USE SIGNAL ;
    PORT
      LAYER M4 ;
        RECT 17.016 47.760 17.208 47.784 ;
    END
  END dq[945]
  PIN dq[946]
    DIRECTION INOUT ;
    USE SIGNAL ;
    PORT
      LAYER M4 ;
        RECT 17.016 47.808 17.208 47.832 ;
    END
  END dq[946]
  PIN dq[947]
    DIRECTION INOUT ;
    USE SIGNAL ;
    PORT
      LAYER M4 ;
        RECT 17.016 47.856 17.208 47.880 ;
    END
  END dq[947]
  PIN dq[948]
    DIRECTION INOUT ;
    USE SIGNAL ;
    PORT
      LAYER M4 ;
        RECT 17.016 47.904 17.208 47.928 ;
    END
  END dq[948]
  PIN dq[949]
    DIRECTION INOUT ;
    USE SIGNAL ;
    PORT
      LAYER M4 ;
        RECT 17.016 47.952 17.208 47.976 ;
    END
  END dq[949]
  PIN dq[950]
    DIRECTION INOUT ;
    USE SIGNAL ;
    PORT
      LAYER M4 ;
        RECT 17.016 48.000 17.208 48.024 ;
    END
  END dq[950]
  PIN dq[951]
    DIRECTION INOUT ;
    USE SIGNAL ;
    PORT
      LAYER M4 ;
        RECT 17.016 48.048 17.208 48.072 ;
    END
  END dq[951]
  PIN dq[952]
    DIRECTION INOUT ;
    USE SIGNAL ;
    PORT
      LAYER M4 ;
        RECT 17.016 48.096 17.208 48.120 ;
    END
  END dq[952]
  PIN dq[953]
    DIRECTION INOUT ;
    USE SIGNAL ;
    PORT
      LAYER M4 ;
        RECT 17.016 48.144 17.208 48.168 ;
    END
  END dq[953]
  PIN dq[954]
    DIRECTION INOUT ;
    USE SIGNAL ;
    PORT
      LAYER M4 ;
        RECT 17.016 48.192 17.208 48.216 ;
    END
  END dq[954]
  PIN dq[955]
    DIRECTION INOUT ;
    USE SIGNAL ;
    PORT
      LAYER M4 ;
        RECT 17.016 48.240 17.208 48.264 ;
    END
  END dq[955]
  PIN dq[956]
    DIRECTION INOUT ;
    USE SIGNAL ;
    PORT
      LAYER M4 ;
        RECT 17.016 48.288 17.208 48.312 ;
    END
  END dq[956]
  PIN dq[957]
    DIRECTION INOUT ;
    USE SIGNAL ;
    PORT
      LAYER M4 ;
        RECT 17.016 48.336 17.208 48.360 ;
    END
  END dq[957]
  PIN dq[958]
    DIRECTION INOUT ;
    USE SIGNAL ;
    PORT
      LAYER M4 ;
        RECT 17.016 48.384 17.208 48.408 ;
    END
  END dq[958]
  PIN dq[959]
    DIRECTION INOUT ;
    USE SIGNAL ;
    PORT
      LAYER M4 ;
        RECT 17.016 48.432 17.208 48.456 ;
    END
  END dq[959]
  PIN dq[960]
    DIRECTION INOUT ;
    USE SIGNAL ;
    PORT
      LAYER M4 ;
        RECT 17.016 48.480 17.208 48.504 ;
    END
  END dq[960]
  PIN dq[961]
    DIRECTION INOUT ;
    USE SIGNAL ;
    PORT
      LAYER M4 ;
        RECT 17.016 48.528 17.208 48.552 ;
    END
  END dq[961]
  PIN dq[962]
    DIRECTION INOUT ;
    USE SIGNAL ;
    PORT
      LAYER M4 ;
        RECT 17.016 48.576 17.208 48.600 ;
    END
  END dq[962]
  PIN dq[963]
    DIRECTION INOUT ;
    USE SIGNAL ;
    PORT
      LAYER M4 ;
        RECT 17.016 48.624 17.208 48.648 ;
    END
  END dq[963]
  PIN dq[964]
    DIRECTION INOUT ;
    USE SIGNAL ;
    PORT
      LAYER M4 ;
        RECT 17.016 48.672 17.208 48.696 ;
    END
  END dq[964]
  PIN dq[965]
    DIRECTION INOUT ;
    USE SIGNAL ;
    PORT
      LAYER M4 ;
        RECT 17.016 48.720 17.208 48.744 ;
    END
  END dq[965]
  PIN dq[966]
    DIRECTION INOUT ;
    USE SIGNAL ;
    PORT
      LAYER M4 ;
        RECT 17.016 48.768 17.208 48.792 ;
    END
  END dq[966]
  PIN dq[967]
    DIRECTION INOUT ;
    USE SIGNAL ;
    PORT
      LAYER M4 ;
        RECT 17.016 48.816 17.208 48.840 ;
    END
  END dq[967]
  PIN dq[968]
    DIRECTION INOUT ;
    USE SIGNAL ;
    PORT
      LAYER M4 ;
        RECT 17.016 48.864 17.208 48.888 ;
    END
  END dq[968]
  PIN dq[969]
    DIRECTION INOUT ;
    USE SIGNAL ;
    PORT
      LAYER M4 ;
        RECT 17.016 48.912 17.208 48.936 ;
    END
  END dq[969]
  PIN dq[970]
    DIRECTION INOUT ;
    USE SIGNAL ;
    PORT
      LAYER M4 ;
        RECT 17.016 48.960 17.208 48.984 ;
    END
  END dq[970]
  PIN dq[971]
    DIRECTION INOUT ;
    USE SIGNAL ;
    PORT
      LAYER M4 ;
        RECT 17.016 49.008 17.208 49.032 ;
    END
  END dq[971]
  PIN dq[972]
    DIRECTION INOUT ;
    USE SIGNAL ;
    PORT
      LAYER M4 ;
        RECT 17.016 49.056 17.208 49.080 ;
    END
  END dq[972]
  PIN dq[973]
    DIRECTION INOUT ;
    USE SIGNAL ;
    PORT
      LAYER M4 ;
        RECT 17.016 49.104 17.208 49.128 ;
    END
  END dq[973]
  PIN dq[974]
    DIRECTION INOUT ;
    USE SIGNAL ;
    PORT
      LAYER M4 ;
        RECT 17.016 49.152 17.208 49.176 ;
    END
  END dq[974]
  PIN dq[975]
    DIRECTION INOUT ;
    USE SIGNAL ;
    PORT
      LAYER M4 ;
        RECT 17.016 49.200 17.208 49.224 ;
    END
  END dq[975]
  PIN dq[976]
    DIRECTION INOUT ;
    USE SIGNAL ;
    PORT
      LAYER M4 ;
        RECT 17.016 49.248 17.208 49.272 ;
    END
  END dq[976]
  PIN dq[977]
    DIRECTION INOUT ;
    USE SIGNAL ;
    PORT
      LAYER M4 ;
        RECT 17.016 49.296 17.208 49.320 ;
    END
  END dq[977]
  PIN dq[978]
    DIRECTION INOUT ;
    USE SIGNAL ;
    PORT
      LAYER M4 ;
        RECT 17.016 49.344 17.208 49.368 ;
    END
  END dq[978]
  PIN dq[979]
    DIRECTION INOUT ;
    USE SIGNAL ;
    PORT
      LAYER M4 ;
        RECT 17.016 49.392 17.208 49.416 ;
    END
  END dq[979]
  PIN dq[980]
    DIRECTION INOUT ;
    USE SIGNAL ;
    PORT
      LAYER M4 ;
        RECT 17.016 49.440 17.208 49.464 ;
    END
  END dq[980]
  PIN dq[981]
    DIRECTION INOUT ;
    USE SIGNAL ;
    PORT
      LAYER M4 ;
        RECT 17.016 49.488 17.208 49.512 ;
    END
  END dq[981]
  PIN dq[982]
    DIRECTION INOUT ;
    USE SIGNAL ;
    PORT
      LAYER M4 ;
        RECT 17.016 49.536 17.208 49.560 ;
    END
  END dq[982]
  PIN dq[983]
    DIRECTION INOUT ;
    USE SIGNAL ;
    PORT
      LAYER M4 ;
        RECT 17.016 49.584 17.208 49.608 ;
    END
  END dq[983]
  PIN dq[984]
    DIRECTION INOUT ;
    USE SIGNAL ;
    PORT
      LAYER M4 ;
        RECT 17.016 49.632 17.208 49.656 ;
    END
  END dq[984]
  PIN dq[985]
    DIRECTION INOUT ;
    USE SIGNAL ;
    PORT
      LAYER M4 ;
        RECT 17.016 49.680 17.208 49.704 ;
    END
  END dq[985]
  PIN dq[986]
    DIRECTION INOUT ;
    USE SIGNAL ;
    PORT
      LAYER M4 ;
        RECT 17.016 49.728 17.208 49.752 ;
    END
  END dq[986]
  PIN dq[987]
    DIRECTION INOUT ;
    USE SIGNAL ;
    PORT
      LAYER M4 ;
        RECT 17.016 49.776 17.208 49.800 ;
    END
  END dq[987]
  PIN dq[988]
    DIRECTION INOUT ;
    USE SIGNAL ;
    PORT
      LAYER M4 ;
        RECT 17.016 49.824 17.208 49.848 ;
    END
  END dq[988]
  PIN dq[989]
    DIRECTION INOUT ;
    USE SIGNAL ;
    PORT
      LAYER M4 ;
        RECT 17.016 49.872 17.208 49.896 ;
    END
  END dq[989]
  PIN dq[990]
    DIRECTION INOUT ;
    USE SIGNAL ;
    PORT
      LAYER M4 ;
        RECT 17.016 49.920 17.208 49.944 ;
    END
  END dq[990]
  PIN dq[991]
    DIRECTION INOUT ;
    USE SIGNAL ;
    PORT
      LAYER M4 ;
        RECT 17.016 49.968 17.208 49.992 ;
    END
  END dq[991]
  PIN dq[992]
    DIRECTION INOUT ;
    USE SIGNAL ;
    PORT
      LAYER M4 ;
        RECT 17.016 50.016 17.208 50.040 ;
    END
  END dq[992]
  PIN dq[993]
    DIRECTION INOUT ;
    USE SIGNAL ;
    PORT
      LAYER M4 ;
        RECT 17.016 50.064 17.208 50.088 ;
    END
  END dq[993]
  PIN dq[994]
    DIRECTION INOUT ;
    USE SIGNAL ;
    PORT
      LAYER M4 ;
        RECT 17.016 50.112 17.208 50.136 ;
    END
  END dq[994]
  PIN dq[995]
    DIRECTION INOUT ;
    USE SIGNAL ;
    PORT
      LAYER M4 ;
        RECT 17.016 50.160 17.208 50.184 ;
    END
  END dq[995]
  PIN dq[996]
    DIRECTION INOUT ;
    USE SIGNAL ;
    PORT
      LAYER M4 ;
        RECT 17.016 50.208 17.208 50.232 ;
    END
  END dq[996]
  PIN dq[997]
    DIRECTION INOUT ;
    USE SIGNAL ;
    PORT
      LAYER M4 ;
        RECT 17.016 50.256 17.208 50.280 ;
    END
  END dq[997]
  PIN dq[998]
    DIRECTION INOUT ;
    USE SIGNAL ;
    PORT
      LAYER M4 ;
        RECT 17.016 50.304 17.208 50.328 ;
    END
  END dq[998]
  PIN dq[999]
    DIRECTION INOUT ;
    USE SIGNAL ;
    PORT
      LAYER M4 ;
        RECT 17.016 50.352 17.208 50.376 ;
    END
  END dq[999]
  PIN dq[1000]
    DIRECTION INOUT ;
    USE SIGNAL ;
    PORT
      LAYER M4 ;
        RECT 17.016 50.400 17.208 50.424 ;
    END
  END dq[1000]
  PIN dq[1001]
    DIRECTION INOUT ;
    USE SIGNAL ;
    PORT
      LAYER M4 ;
        RECT 17.016 50.448 17.208 50.472 ;
    END
  END dq[1001]
  PIN dq[1002]
    DIRECTION INOUT ;
    USE SIGNAL ;
    PORT
      LAYER M4 ;
        RECT 17.016 50.496 17.208 50.520 ;
    END
  END dq[1002]
  PIN dq[1003]
    DIRECTION INOUT ;
    USE SIGNAL ;
    PORT
      LAYER M4 ;
        RECT 17.016 50.544 17.208 50.568 ;
    END
  END dq[1003]
  PIN dq[1004]
    DIRECTION INOUT ;
    USE SIGNAL ;
    PORT
      LAYER M4 ;
        RECT 17.016 50.592 17.208 50.616 ;
    END
  END dq[1004]
  PIN dq[1005]
    DIRECTION INOUT ;
    USE SIGNAL ;
    PORT
      LAYER M4 ;
        RECT 17.016 50.640 17.208 50.664 ;
    END
  END dq[1005]
  PIN dq[1006]
    DIRECTION INOUT ;
    USE SIGNAL ;
    PORT
      LAYER M4 ;
        RECT 17.016 50.688 17.208 50.712 ;
    END
  END dq[1006]
  PIN dq[1007]
    DIRECTION INOUT ;
    USE SIGNAL ;
    PORT
      LAYER M4 ;
        RECT 17.016 50.736 17.208 50.760 ;
    END
  END dq[1007]
  PIN dq[1008]
    DIRECTION INOUT ;
    USE SIGNAL ;
    PORT
      LAYER M4 ;
        RECT 17.016 50.784 17.208 50.808 ;
    END
  END dq[1008]
  PIN dq[1009]
    DIRECTION INOUT ;
    USE SIGNAL ;
    PORT
      LAYER M4 ;
        RECT 17.016 50.832 17.208 50.856 ;
    END
  END dq[1009]
  PIN dq[1010]
    DIRECTION INOUT ;
    USE SIGNAL ;
    PORT
      LAYER M4 ;
        RECT 17.016 50.880 17.208 50.904 ;
    END
  END dq[1010]
  PIN dq[1011]
    DIRECTION INOUT ;
    USE SIGNAL ;
    PORT
      LAYER M4 ;
        RECT 17.016 50.928 17.208 50.952 ;
    END
  END dq[1011]
  PIN dq[1012]
    DIRECTION INOUT ;
    USE SIGNAL ;
    PORT
      LAYER M4 ;
        RECT 17.016 50.976 17.208 51.000 ;
    END
  END dq[1012]
  PIN dq[1013]
    DIRECTION INOUT ;
    USE SIGNAL ;
    PORT
      LAYER M4 ;
        RECT 17.016 51.024 17.208 51.048 ;
    END
  END dq[1013]
  PIN dq[1014]
    DIRECTION INOUT ;
    USE SIGNAL ;
    PORT
      LAYER M4 ;
        RECT 17.016 51.072 17.208 51.096 ;
    END
  END dq[1014]
  PIN dq[1015]
    DIRECTION INOUT ;
    USE SIGNAL ;
    PORT
      LAYER M4 ;
        RECT 17.016 51.120 17.208 51.144 ;
    END
  END dq[1015]
  PIN dq[1016]
    DIRECTION INOUT ;
    USE SIGNAL ;
    PORT
      LAYER M4 ;
        RECT 17.016 51.168 17.208 51.192 ;
    END
  END dq[1016]
  PIN dq[1017]
    DIRECTION INOUT ;
    USE SIGNAL ;
    PORT
      LAYER M4 ;
        RECT 17.016 51.216 17.208 51.240 ;
    END
  END dq[1017]
  PIN dq[1018]
    DIRECTION INOUT ;
    USE SIGNAL ;
    PORT
      LAYER M4 ;
        RECT 17.016 51.264 17.208 51.288 ;
    END
  END dq[1018]
  PIN dq[1019]
    DIRECTION INOUT ;
    USE SIGNAL ;
    PORT
      LAYER M4 ;
        RECT 17.016 51.312 17.208 51.336 ;
    END
  END dq[1019]
  PIN dq[1020]
    DIRECTION INOUT ;
    USE SIGNAL ;
    PORT
      LAYER M4 ;
        RECT 17.016 51.360 17.208 51.384 ;
    END
  END dq[1020]
  PIN dq[1021]
    DIRECTION INOUT ;
    USE SIGNAL ;
    PORT
      LAYER M4 ;
        RECT 17.016 51.408 17.208 51.432 ;
    END
  END dq[1021]
  PIN dq[1022]
    DIRECTION INOUT ;
    USE SIGNAL ;
    PORT
      LAYER M4 ;
        RECT 17.016 51.456 17.208 51.480 ;
    END
  END dq[1022]
  PIN dq[1023]
    DIRECTION INOUT ;
    USE SIGNAL ;
    PORT
      LAYER M4 ;
        RECT 17.016 51.504 17.208 51.528 ;
    END
  END dq[1023]
  PIN ck[0]
    DIRECTION INOUT ;
    USE SIGNAL ;
    PORT
      LAYER M5 ;
        RECT 8.592 53.736 8.616 53.928 ;
    END
  END ck[0]
  OBS
    LAYER M1 ;
      RECT 0 0 17.256 53.976 ;
    LAYER M2 ;
      RECT 0 0 17.256 53.976 ;
    LAYER M3 ;
      RECT 0 0 17.256 53.976 ;
  END
END dsfd_hstnh_1024
END LIBRARY
